VERSION 5.8 ;
BUSBITCHARS "[]" ;
DIVIDERCHAR "/" ;
UNITS
    DATABASE MICRONS 1000 ;
END UNITS

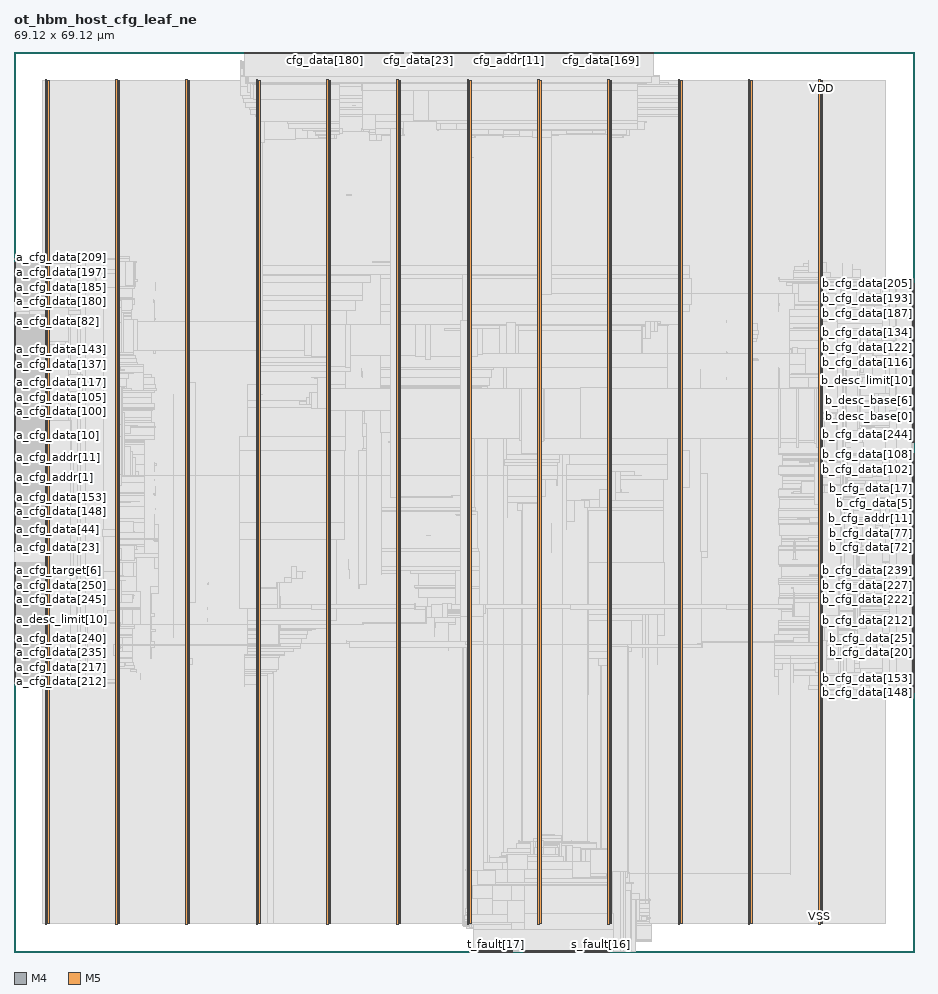
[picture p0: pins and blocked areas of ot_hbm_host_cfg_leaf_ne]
MACRO ot_hbm_host_cfg_leaf_ne
  FOREIGN ot_hbm_host_cfg_leaf_ne 0 0 ;
  CLASS BLOCK ;
  SIZE 69.12 BY 69.12 ;
  PIN a_cfg_addr[0]
    DIRECTION OUTPUT ;
    USE SIGNAL ;
    PORT
      LAYER M4 ;
        RECT  0 36.912 0.084 36.936 ;
    END
  END a_cfg_addr[0]
  PIN a_cfg_addr[10]
    DIRECTION OUTPUT ;
    USE SIGNAL ;
    PORT
      LAYER M4 ;
        RECT  0 37.872 0.084 37.896 ;
    END
  END a_cfg_addr[10]
  PIN a_cfg_addr[11]
    DIRECTION OUTPUT ;
    USE SIGNAL ;
    PORT
      LAYER M4 ;
        RECT  0 37.968 0.084 37.992 ;
    END
  END a_cfg_addr[11]
  PIN a_cfg_addr[1]
    DIRECTION OUTPUT ;
    USE SIGNAL ;
    PORT
      LAYER M4 ;
        RECT  0 37.008 0.084 37.032 ;
    END
  END a_cfg_addr[1]
  PIN a_cfg_addr[2]
    DIRECTION OUTPUT ;
    USE SIGNAL ;
    PORT
      LAYER M4 ;
        RECT  0 37.104 0.084 37.128 ;
    END
  END a_cfg_addr[2]
  PIN a_cfg_addr[3]
    DIRECTION OUTPUT ;
    USE SIGNAL ;
    PORT
      LAYER M4 ;
        RECT  0 37.2 0.084 37.224 ;
    END
  END a_cfg_addr[3]
  PIN a_cfg_addr[4]
    DIRECTION OUTPUT ;
    USE SIGNAL ;
    PORT
      LAYER M4 ;
        RECT  0 37.296 0.084 37.32 ;
    END
  END a_cfg_addr[4]
  PIN a_cfg_addr[5]
    DIRECTION OUTPUT ;
    USE SIGNAL ;
    PORT
      LAYER M4 ;
        RECT  0 37.392 0.084 37.416 ;
    END
  END a_cfg_addr[5]
  PIN a_cfg_addr[6]
    DIRECTION OUTPUT ;
    USE SIGNAL ;
    PORT
      LAYER M4 ;
        RECT  0 37.488 0.084 37.512 ;
    END
  END a_cfg_addr[6]
  PIN a_cfg_addr[7]
    DIRECTION OUTPUT ;
    USE SIGNAL ;
    PORT
      LAYER M4 ;
        RECT  0 37.584 0.084 37.608 ;
    END
  END a_cfg_addr[7]
  PIN a_cfg_addr[8]
    DIRECTION OUTPUT ;
    USE SIGNAL ;
    PORT
      LAYER M4 ;
        RECT  0 37.68 0.084 37.704 ;
    END
  END a_cfg_addr[8]
  PIN a_cfg_addr[9]
    DIRECTION OUTPUT ;
    USE SIGNAL ;
    PORT
      LAYER M4 ;
        RECT  0 37.776 0.084 37.8 ;
    END
  END a_cfg_addr[9]
  PIN a_cfg_data[0]
    DIRECTION OUTPUT ;
    USE SIGNAL ;
    PORT
      LAYER M4 ;
        RECT  0 38.064 0.084 38.088 ;
    END
  END a_cfg_data[0]
  PIN a_cfg_data[100]
    DIRECTION OUTPUT ;
    USE SIGNAL ;
    PORT
      LAYER M4 ;
        RECT  0 41.52 0.084 41.544 ;
    END
  END a_cfg_data[100]
  PIN a_cfg_data[101]
    DIRECTION OUTPUT ;
    USE SIGNAL ;
    PORT
      LAYER M4 ;
        RECT  0 41.616 0.084 41.64 ;
    END
  END a_cfg_data[101]
  PIN a_cfg_data[102]
    DIRECTION OUTPUT ;
    USE SIGNAL ;
    PORT
      LAYER M4 ;
        RECT  0 41.712 0.084 41.736 ;
    END
  END a_cfg_data[102]
  PIN a_cfg_data[103]
    DIRECTION OUTPUT ;
    USE SIGNAL ;
    PORT
      LAYER M4 ;
        RECT  0 41.808 0.084 41.832 ;
    END
  END a_cfg_data[103]
  PIN a_cfg_data[104]
    DIRECTION OUTPUT ;
    USE SIGNAL ;
    PORT
      LAYER M4 ;
        RECT  0 41.904 0.084 41.928 ;
    END
  END a_cfg_data[104]
  PIN a_cfg_data[105]
    DIRECTION OUTPUT ;
    USE SIGNAL ;
    PORT
      LAYER M4 ;
        RECT  0 42 0.084 42.024 ;
    END
  END a_cfg_data[105]
  PIN a_cfg_data[106]
    DIRECTION OUTPUT ;
    USE SIGNAL ;
    PORT
      LAYER M4 ;
        RECT  0 42.096 0.084 42.12 ;
    END
  END a_cfg_data[106]
  PIN a_cfg_data[107]
    DIRECTION OUTPUT ;
    USE SIGNAL ;
    PORT
      LAYER M4 ;
        RECT  0 42.192 0.084 42.216 ;
    END
  END a_cfg_data[107]
  PIN a_cfg_data[108]
    DIRECTION OUTPUT ;
    USE SIGNAL ;
    PORT
      LAYER M4 ;
        RECT  0 42.288 0.084 42.312 ;
    END
  END a_cfg_data[108]
  PIN a_cfg_data[109]
    DIRECTION OUTPUT ;
    USE SIGNAL ;
    PORT
      LAYER M4 ;
        RECT  0 42.384 0.084 42.408 ;
    END
  END a_cfg_data[109]
  PIN a_cfg_data[10]
    DIRECTION OUTPUT ;
    USE SIGNAL ;
    PORT
      LAYER M4 ;
        RECT  0 39.024 0.084 39.048 ;
    END
  END a_cfg_data[10]
  PIN a_cfg_data[110]
    DIRECTION OUTPUT ;
    USE SIGNAL ;
    PORT
      LAYER M4 ;
        RECT  0 42.48 0.084 42.504 ;
    END
  END a_cfg_data[110]
  PIN a_cfg_data[111]
    DIRECTION OUTPUT ;
    USE SIGNAL ;
    PORT
      LAYER M4 ;
        RECT  0 42.576 0.084 42.6 ;
    END
  END a_cfg_data[111]
  PIN a_cfg_data[112]
    DIRECTION OUTPUT ;
    USE SIGNAL ;
    PORT
      LAYER M4 ;
        RECT  0 42.672 0.084 42.696 ;
    END
  END a_cfg_data[112]
  PIN a_cfg_data[113]
    DIRECTION OUTPUT ;
    USE SIGNAL ;
    PORT
      LAYER M4 ;
        RECT  0 42.768 0.084 42.792 ;
    END
  END a_cfg_data[113]
  PIN a_cfg_data[114]
    DIRECTION OUTPUT ;
    USE SIGNAL ;
    PORT
      LAYER M4 ;
        RECT  0 42.864 0.084 42.888 ;
    END
  END a_cfg_data[114]
  PIN a_cfg_data[115]
    DIRECTION OUTPUT ;
    USE SIGNAL ;
    PORT
      LAYER M4 ;
        RECT  0 42.96 0.084 42.984 ;
    END
  END a_cfg_data[115]
  PIN a_cfg_data[116]
    DIRECTION OUTPUT ;
    USE SIGNAL ;
    PORT
      LAYER M4 ;
        RECT  0 43.056 0.084 43.08 ;
    END
  END a_cfg_data[116]
  PIN a_cfg_data[117]
    DIRECTION OUTPUT ;
    USE SIGNAL ;
    PORT
      LAYER M4 ;
        RECT  0 43.152 0.084 43.176 ;
    END
  END a_cfg_data[117]
  PIN a_cfg_data[118]
    DIRECTION OUTPUT ;
    USE SIGNAL ;
    PORT
      LAYER M4 ;
        RECT  0 43.248 0.084 43.272 ;
    END
  END a_cfg_data[118]
  PIN a_cfg_data[119]
    DIRECTION OUTPUT ;
    USE SIGNAL ;
    PORT
      LAYER M4 ;
        RECT  0 43.344 0.084 43.368 ;
    END
  END a_cfg_data[119]
  PIN a_cfg_data[11]
    DIRECTION OUTPUT ;
    USE SIGNAL ;
    PORT
      LAYER M4 ;
        RECT  0 39.12 0.084 39.144 ;
    END
  END a_cfg_data[11]
  PIN a_cfg_data[120]
    DIRECTION OUTPUT ;
    USE SIGNAL ;
    PORT
      LAYER M4 ;
        RECT  0 43.44 0.084 43.464 ;
    END
  END a_cfg_data[120]
  PIN a_cfg_data[121]
    DIRECTION OUTPUT ;
    USE SIGNAL ;
    PORT
      LAYER M4 ;
        RECT  0 43.536 0.084 43.56 ;
    END
  END a_cfg_data[121]
  PIN a_cfg_data[122]
    DIRECTION OUTPUT ;
    USE SIGNAL ;
    PORT
      LAYER M4 ;
        RECT  0 43.632 0.084 43.656 ;
    END
  END a_cfg_data[122]
  PIN a_cfg_data[123]
    DIRECTION OUTPUT ;
    USE SIGNAL ;
    PORT
      LAYER M4 ;
        RECT  0 43.728 0.084 43.752 ;
    END
  END a_cfg_data[123]
  PIN a_cfg_data[124]
    DIRECTION OUTPUT ;
    USE SIGNAL ;
    PORT
      LAYER M4 ;
        RECT  0 43.824 0.084 43.848 ;
    END
  END a_cfg_data[124]
  PIN a_cfg_data[125]
    DIRECTION OUTPUT ;
    USE SIGNAL ;
    PORT
      LAYER M4 ;
        RECT  0 43.92 0.084 43.944 ;
    END
  END a_cfg_data[125]
  PIN a_cfg_data[126]
    DIRECTION OUTPUT ;
    USE SIGNAL ;
    PORT
      LAYER M4 ;
        RECT  0 44.016 0.084 44.04 ;
    END
  END a_cfg_data[126]
  PIN a_cfg_data[127]
    DIRECTION OUTPUT ;
    USE SIGNAL ;
    PORT
      LAYER M4 ;
        RECT  0 44.112 0.084 44.136 ;
    END
  END a_cfg_data[127]
  PIN a_cfg_data[128]
    DIRECTION OUTPUT ;
    USE SIGNAL ;
    PORT
      LAYER M4 ;
        RECT  0 44.208 0.084 44.232 ;
    END
  END a_cfg_data[128]
  PIN a_cfg_data[129]
    DIRECTION OUTPUT ;
    USE SIGNAL ;
    PORT
      LAYER M4 ;
        RECT  0 44.304 0.084 44.328 ;
    END
  END a_cfg_data[129]
  PIN a_cfg_data[12]
    DIRECTION OUTPUT ;
    USE SIGNAL ;
    PORT
      LAYER M4 ;
        RECT  0 39.216 0.084 39.24 ;
    END
  END a_cfg_data[12]
  PIN a_cfg_data[130]
    DIRECTION OUTPUT ;
    USE SIGNAL ;
    PORT
      LAYER M4 ;
        RECT  0 44.4 0.084 44.424 ;
    END
  END a_cfg_data[130]
  PIN a_cfg_data[131]
    DIRECTION OUTPUT ;
    USE SIGNAL ;
    PORT
      LAYER M4 ;
        RECT  0 44.496 0.084 44.52 ;
    END
  END a_cfg_data[131]
  PIN a_cfg_data[132]
    DIRECTION OUTPUT ;
    USE SIGNAL ;
    PORT
      LAYER M4 ;
        RECT  0 44.592 0.084 44.616 ;
    END
  END a_cfg_data[132]
  PIN a_cfg_data[133]
    DIRECTION OUTPUT ;
    USE SIGNAL ;
    PORT
      LAYER M4 ;
        RECT  0 44.688 0.084 44.712 ;
    END
  END a_cfg_data[133]
  PIN a_cfg_data[134]
    DIRECTION OUTPUT ;
    USE SIGNAL ;
    PORT
      LAYER M4 ;
        RECT  0 44.784 0.084 44.808 ;
    END
  END a_cfg_data[134]
  PIN a_cfg_data[135]
    DIRECTION OUTPUT ;
    USE SIGNAL ;
    PORT
      LAYER M4 ;
        RECT  0 44.88 0.084 44.904 ;
    END
  END a_cfg_data[135]
  PIN a_cfg_data[136]
    DIRECTION OUTPUT ;
    USE SIGNAL ;
    PORT
      LAYER M4 ;
        RECT  0 44.976 0.084 45 ;
    END
  END a_cfg_data[136]
  PIN a_cfg_data[137]
    DIRECTION OUTPUT ;
    USE SIGNAL ;
    PORT
      LAYER M4 ;
        RECT  0 45.072 0.084 45.096 ;
    END
  END a_cfg_data[137]
  PIN a_cfg_data[138]
    DIRECTION OUTPUT ;
    USE SIGNAL ;
    PORT
      LAYER M4 ;
        RECT  0 45.168 0.084 45.192 ;
    END
  END a_cfg_data[138]
  PIN a_cfg_data[139]
    DIRECTION OUTPUT ;
    USE SIGNAL ;
    PORT
      LAYER M4 ;
        RECT  0 45.264 0.084 45.288 ;
    END
  END a_cfg_data[139]
  PIN a_cfg_data[13]
    DIRECTION OUTPUT ;
    USE SIGNAL ;
    PORT
      LAYER M4 ;
        RECT  0 39.312 0.084 39.336 ;
    END
  END a_cfg_data[13]
  PIN a_cfg_data[140]
    DIRECTION OUTPUT ;
    USE SIGNAL ;
    PORT
      LAYER M4 ;
        RECT  0 45.36 0.084 45.384 ;
    END
  END a_cfg_data[140]
  PIN a_cfg_data[141]
    DIRECTION OUTPUT ;
    USE SIGNAL ;
    PORT
      LAYER M4 ;
        RECT  0 45.456 0.084 45.48 ;
    END
  END a_cfg_data[141]
  PIN a_cfg_data[142]
    DIRECTION OUTPUT ;
    USE SIGNAL ;
    PORT
      LAYER M4 ;
        RECT  0 45.552 0.084 45.576 ;
    END
  END a_cfg_data[142]
  PIN a_cfg_data[143]
    DIRECTION OUTPUT ;
    USE SIGNAL ;
    PORT
      LAYER M4 ;
        RECT  0 45.648 0.084 45.672 ;
    END
  END a_cfg_data[143]
  PIN a_cfg_data[144]
    DIRECTION OUTPUT ;
    USE SIGNAL ;
    PORT
      LAYER M4 ;
        RECT  0 45.744 0.084 45.768 ;
    END
  END a_cfg_data[144]
  PIN a_cfg_data[145]
    DIRECTION OUTPUT ;
    USE SIGNAL ;
    PORT
      LAYER M4 ;
        RECT  0 45.84 0.084 45.864 ;
    END
  END a_cfg_data[145]
  PIN a_cfg_data[146]
    DIRECTION OUTPUT ;
    USE SIGNAL ;
    PORT
      LAYER M4 ;
        RECT  0 45.936 0.084 45.96 ;
    END
  END a_cfg_data[146]
  PIN a_cfg_data[147]
    DIRECTION OUTPUT ;
    USE SIGNAL ;
    PORT
      LAYER M4 ;
        RECT  0 46.032 0.084 46.056 ;
    END
  END a_cfg_data[147]
  PIN a_cfg_data[148]
    DIRECTION OUTPUT ;
    USE SIGNAL ;
    PORT
      LAYER M4 ;
        RECT  0 33.84 0.084 33.864 ;
    END
  END a_cfg_data[148]
  PIN a_cfg_data[149]
    DIRECTION OUTPUT ;
    USE SIGNAL ;
    PORT
      LAYER M4 ;
        RECT  0 33.936 0.084 33.96 ;
    END
  END a_cfg_data[149]
  PIN a_cfg_data[14]
    DIRECTION OUTPUT ;
    USE SIGNAL ;
    PORT
      LAYER M4 ;
        RECT  0 39.408 0.084 39.432 ;
    END
  END a_cfg_data[14]
  PIN a_cfg_data[150]
    DIRECTION OUTPUT ;
    USE SIGNAL ;
    PORT
      LAYER M4 ;
        RECT  0 34.032 0.084 34.056 ;
    END
  END a_cfg_data[150]
  PIN a_cfg_data[151]
    DIRECTION OUTPUT ;
    USE SIGNAL ;
    PORT
      LAYER M4 ;
        RECT  0 34.128 0.084 34.152 ;
    END
  END a_cfg_data[151]
  PIN a_cfg_data[152]
    DIRECTION OUTPUT ;
    USE SIGNAL ;
    PORT
      LAYER M4 ;
        RECT  0 34.224 0.084 34.248 ;
    END
  END a_cfg_data[152]
  PIN a_cfg_data[153]
    DIRECTION OUTPUT ;
    USE SIGNAL ;
    PORT
      LAYER M4 ;
        RECT  0 34.32 0.084 34.344 ;
    END
  END a_cfg_data[153]
  PIN a_cfg_data[154]
    DIRECTION OUTPUT ;
    USE SIGNAL ;
    PORT
      LAYER M4 ;
        RECT  0 34.416 0.084 34.44 ;
    END
  END a_cfg_data[154]
  PIN a_cfg_data[155]
    DIRECTION OUTPUT ;
    USE SIGNAL ;
    PORT
      LAYER M4 ;
        RECT  0 34.512 0.084 34.536 ;
    END
  END a_cfg_data[155]
  PIN a_cfg_data[156]
    DIRECTION OUTPUT ;
    USE SIGNAL ;
    PORT
      LAYER M4 ;
        RECT  0 34.608 0.084 34.632 ;
    END
  END a_cfg_data[156]
  PIN a_cfg_data[157]
    DIRECTION OUTPUT ;
    USE SIGNAL ;
    PORT
      LAYER M4 ;
        RECT  0 34.704 0.084 34.728 ;
    END
  END a_cfg_data[157]
  PIN a_cfg_data[158]
    DIRECTION OUTPUT ;
    USE SIGNAL ;
    PORT
      LAYER M4 ;
        RECT  0 34.8 0.084 34.824 ;
    END
  END a_cfg_data[158]
  PIN a_cfg_data[159]
    DIRECTION OUTPUT ;
    USE SIGNAL ;
    PORT
      LAYER M4 ;
        RECT  0 34.896 0.084 34.92 ;
    END
  END a_cfg_data[159]
  PIN a_cfg_data[15]
    DIRECTION OUTPUT ;
    USE SIGNAL ;
    PORT
      LAYER M4 ;
        RECT  0 39.504 0.084 39.528 ;
    END
  END a_cfg_data[15]
  PIN a_cfg_data[160]
    DIRECTION OUTPUT ;
    USE SIGNAL ;
    PORT
      LAYER M4 ;
        RECT  0 34.992 0.084 35.016 ;
    END
  END a_cfg_data[160]
  PIN a_cfg_data[161]
    DIRECTION OUTPUT ;
    USE SIGNAL ;
    PORT
      LAYER M4 ;
        RECT  0 35.088 0.084 35.112 ;
    END
  END a_cfg_data[161]
  PIN a_cfg_data[162]
    DIRECTION OUTPUT ;
    USE SIGNAL ;
    PORT
      LAYER M4 ;
        RECT  0 35.184 0.084 35.208 ;
    END
  END a_cfg_data[162]
  PIN a_cfg_data[163]
    DIRECTION OUTPUT ;
    USE SIGNAL ;
    PORT
      LAYER M4 ;
        RECT  0 35.28 0.084 35.304 ;
    END
  END a_cfg_data[163]
  PIN a_cfg_data[164]
    DIRECTION OUTPUT ;
    USE SIGNAL ;
    PORT
      LAYER M4 ;
        RECT  0 35.376 0.084 35.4 ;
    END
  END a_cfg_data[164]
  PIN a_cfg_data[165]
    DIRECTION OUTPUT ;
    USE SIGNAL ;
    PORT
      LAYER M4 ;
        RECT  0 35.472 0.084 35.496 ;
    END
  END a_cfg_data[165]
  PIN a_cfg_data[166]
    DIRECTION OUTPUT ;
    USE SIGNAL ;
    PORT
      LAYER M4 ;
        RECT  0 35.568 0.084 35.592 ;
    END
  END a_cfg_data[166]
  PIN a_cfg_data[167]
    DIRECTION OUTPUT ;
    USE SIGNAL ;
    PORT
      LAYER M4 ;
        RECT  0 35.664 0.084 35.688 ;
    END
  END a_cfg_data[167]
  PIN a_cfg_data[168]
    DIRECTION OUTPUT ;
    USE SIGNAL ;
    PORT
      LAYER M4 ;
        RECT  0 35.76 0.084 35.784 ;
    END
  END a_cfg_data[168]
  PIN a_cfg_data[169]
    DIRECTION OUTPUT ;
    USE SIGNAL ;
    PORT
      LAYER M4 ;
        RECT  0 35.856 0.084 35.88 ;
    END
  END a_cfg_data[169]
  PIN a_cfg_data[16]
    DIRECTION OUTPUT ;
    USE SIGNAL ;
    PORT
      LAYER M4 ;
        RECT  0 39.6 0.084 39.624 ;
    END
  END a_cfg_data[16]
  PIN a_cfg_data[170]
    DIRECTION OUTPUT ;
    USE SIGNAL ;
    PORT
      LAYER M4 ;
        RECT  0 35.952 0.084 35.976 ;
    END
  END a_cfg_data[170]
  PIN a_cfg_data[171]
    DIRECTION OUTPUT ;
    USE SIGNAL ;
    PORT
      LAYER M4 ;
        RECT  0 36.048 0.084 36.072 ;
    END
  END a_cfg_data[171]
  PIN a_cfg_data[172]
    DIRECTION OUTPUT ;
    USE SIGNAL ;
    PORT
      LAYER M4 ;
        RECT  0 36.144 0.084 36.168 ;
    END
  END a_cfg_data[172]
  PIN a_cfg_data[173]
    DIRECTION OUTPUT ;
    USE SIGNAL ;
    PORT
      LAYER M4 ;
        RECT  0 36.24 0.084 36.264 ;
    END
  END a_cfg_data[173]
  PIN a_cfg_data[174]
    DIRECTION OUTPUT ;
    USE SIGNAL ;
    PORT
      LAYER M4 ;
        RECT  0 36.336 0.084 36.36 ;
    END
  END a_cfg_data[174]
  PIN a_cfg_data[175]
    DIRECTION OUTPUT ;
    USE SIGNAL ;
    PORT
      LAYER M4 ;
        RECT  0 36.432 0.084 36.456 ;
    END
  END a_cfg_data[175]
  PIN a_cfg_data[176]
    DIRECTION OUTPUT ;
    USE SIGNAL ;
    PORT
      LAYER M4 ;
        RECT  0 36.528 0.084 36.552 ;
    END
  END a_cfg_data[176]
  PIN a_cfg_data[177]
    DIRECTION OUTPUT ;
    USE SIGNAL ;
    PORT
      LAYER M4 ;
        RECT  0 36.624 0.084 36.648 ;
    END
  END a_cfg_data[177]
  PIN a_cfg_data[178]
    DIRECTION OUTPUT ;
    USE SIGNAL ;
    PORT
      LAYER M4 ;
        RECT  0 36.72 0.084 36.744 ;
    END
  END a_cfg_data[178]
  PIN a_cfg_data[179]
    DIRECTION OUTPUT ;
    USE SIGNAL ;
    PORT
      LAYER M4 ;
        RECT  0 36.816 0.084 36.84 ;
    END
  END a_cfg_data[179]
  PIN a_cfg_data[17]
    DIRECTION OUTPUT ;
    USE SIGNAL ;
    PORT
      LAYER M4 ;
        RECT  0 39.696 0.084 39.72 ;
    END
  END a_cfg_data[17]
  PIN a_cfg_data[180]
    DIRECTION OUTPUT ;
    USE SIGNAL ;
    PORT
      LAYER M4 ;
        RECT  0 49.968 0.084 49.992 ;
    END
  END a_cfg_data[180]
  PIN a_cfg_data[181]
    DIRECTION OUTPUT ;
    USE SIGNAL ;
    PORT
      LAYER M4 ;
        RECT  0 50.064 0.084 50.088 ;
    END
  END a_cfg_data[181]
  PIN a_cfg_data[182]
    DIRECTION OUTPUT ;
    USE SIGNAL ;
    PORT
      LAYER M4 ;
        RECT  0 50.16 0.084 50.184 ;
    END
  END a_cfg_data[182]
  PIN a_cfg_data[183]
    DIRECTION OUTPUT ;
    USE SIGNAL ;
    PORT
      LAYER M4 ;
        RECT  0 50.256 0.084 50.28 ;
    END
  END a_cfg_data[183]
  PIN a_cfg_data[184]
    DIRECTION OUTPUT ;
    USE SIGNAL ;
    PORT
      LAYER M4 ;
        RECT  0 50.352 0.084 50.376 ;
    END
  END a_cfg_data[184]
  PIN a_cfg_data[185]
    DIRECTION OUTPUT ;
    USE SIGNAL ;
    PORT
      LAYER M4 ;
        RECT  0 50.448 0.084 50.472 ;
    END
  END a_cfg_data[185]
  PIN a_cfg_data[186]
    DIRECTION OUTPUT ;
    USE SIGNAL ;
    PORT
      LAYER M4 ;
        RECT  0 50.544 0.084 50.568 ;
    END
  END a_cfg_data[186]
  PIN a_cfg_data[187]
    DIRECTION OUTPUT ;
    USE SIGNAL ;
    PORT
      LAYER M4 ;
        RECT  0 50.64 0.084 50.664 ;
    END
  END a_cfg_data[187]
  PIN a_cfg_data[188]
    DIRECTION OUTPUT ;
    USE SIGNAL ;
    PORT
      LAYER M4 ;
        RECT  0 50.736 0.084 50.76 ;
    END
  END a_cfg_data[188]
  PIN a_cfg_data[189]
    DIRECTION OUTPUT ;
    USE SIGNAL ;
    PORT
      LAYER M4 ;
        RECT  0 50.832 0.084 50.856 ;
    END
  END a_cfg_data[189]
  PIN a_cfg_data[18]
    DIRECTION OUTPUT ;
    USE SIGNAL ;
    PORT
      LAYER M4 ;
        RECT  0 39.792 0.084 39.816 ;
    END
  END a_cfg_data[18]
  PIN a_cfg_data[190]
    DIRECTION OUTPUT ;
    USE SIGNAL ;
    PORT
      LAYER M4 ;
        RECT  0 50.928 0.084 50.952 ;
    END
  END a_cfg_data[190]
  PIN a_cfg_data[191]
    DIRECTION OUTPUT ;
    USE SIGNAL ;
    PORT
      LAYER M4 ;
        RECT  0 51.024 0.084 51.048 ;
    END
  END a_cfg_data[191]
  PIN a_cfg_data[192]
    DIRECTION OUTPUT ;
    USE SIGNAL ;
    PORT
      LAYER M4 ;
        RECT  0 51.12 0.084 51.144 ;
    END
  END a_cfg_data[192]
  PIN a_cfg_data[193]
    DIRECTION OUTPUT ;
    USE SIGNAL ;
    PORT
      LAYER M4 ;
        RECT  0 51.216 0.084 51.24 ;
    END
  END a_cfg_data[193]
  PIN a_cfg_data[194]
    DIRECTION OUTPUT ;
    USE SIGNAL ;
    PORT
      LAYER M4 ;
        RECT  0 51.312 0.084 51.336 ;
    END
  END a_cfg_data[194]
  PIN a_cfg_data[195]
    DIRECTION OUTPUT ;
    USE SIGNAL ;
    PORT
      LAYER M4 ;
        RECT  0 51.408 0.084 51.432 ;
    END
  END a_cfg_data[195]
  PIN a_cfg_data[196]
    DIRECTION OUTPUT ;
    USE SIGNAL ;
    PORT
      LAYER M4 ;
        RECT  0 51.504 0.084 51.528 ;
    END
  END a_cfg_data[196]
  PIN a_cfg_data[197]
    DIRECTION OUTPUT ;
    USE SIGNAL ;
    PORT
      LAYER M4 ;
        RECT  0 51.6 0.084 51.624 ;
    END
  END a_cfg_data[197]
  PIN a_cfg_data[198]
    DIRECTION OUTPUT ;
    USE SIGNAL ;
    PORT
      LAYER M4 ;
        RECT  0 51.696 0.084 51.72 ;
    END
  END a_cfg_data[198]
  PIN a_cfg_data[199]
    DIRECTION OUTPUT ;
    USE SIGNAL ;
    PORT
      LAYER M4 ;
        RECT  0 51.792 0.084 51.816 ;
    END
  END a_cfg_data[199]
  PIN a_cfg_data[19]
    DIRECTION OUTPUT ;
    USE SIGNAL ;
    PORT
      LAYER M4 ;
        RECT  0 39.888 0.084 39.912 ;
    END
  END a_cfg_data[19]
  PIN a_cfg_data[1]
    DIRECTION OUTPUT ;
    USE SIGNAL ;
    PORT
      LAYER M4 ;
        RECT  0 38.16 0.084 38.184 ;
    END
  END a_cfg_data[1]
  PIN a_cfg_data[200]
    DIRECTION OUTPUT ;
    USE SIGNAL ;
    PORT
      LAYER M4 ;
        RECT  0 51.888 0.084 51.912 ;
    END
  END a_cfg_data[200]
  PIN a_cfg_data[201]
    DIRECTION OUTPUT ;
    USE SIGNAL ;
    PORT
      LAYER M4 ;
        RECT  0 51.984 0.084 52.008 ;
    END
  END a_cfg_data[201]
  PIN a_cfg_data[202]
    DIRECTION OUTPUT ;
    USE SIGNAL ;
    PORT
      LAYER M4 ;
        RECT  0 52.08 0.084 52.104 ;
    END
  END a_cfg_data[202]
  PIN a_cfg_data[203]
    DIRECTION OUTPUT ;
    USE SIGNAL ;
    PORT
      LAYER M4 ;
        RECT  0 52.176 0.084 52.2 ;
    END
  END a_cfg_data[203]
  PIN a_cfg_data[204]
    DIRECTION OUTPUT ;
    USE SIGNAL ;
    PORT
      LAYER M4 ;
        RECT  0 52.272 0.084 52.296 ;
    END
  END a_cfg_data[204]
  PIN a_cfg_data[205]
    DIRECTION OUTPUT ;
    USE SIGNAL ;
    PORT
      LAYER M4 ;
        RECT  0 52.368 0.084 52.392 ;
    END
  END a_cfg_data[205]
  PIN a_cfg_data[206]
    DIRECTION OUTPUT ;
    USE SIGNAL ;
    PORT
      LAYER M4 ;
        RECT  0 52.464 0.084 52.488 ;
    END
  END a_cfg_data[206]
  PIN a_cfg_data[207]
    DIRECTION OUTPUT ;
    USE SIGNAL ;
    PORT
      LAYER M4 ;
        RECT  0 52.56 0.084 52.584 ;
    END
  END a_cfg_data[207]
  PIN a_cfg_data[208]
    DIRECTION OUTPUT ;
    USE SIGNAL ;
    PORT
      LAYER M4 ;
        RECT  0 52.656 0.084 52.68 ;
    END
  END a_cfg_data[208]
  PIN a_cfg_data[209]
    DIRECTION OUTPUT ;
    USE SIGNAL ;
    PORT
      LAYER M4 ;
        RECT  0 52.752 0.084 52.776 ;
    END
  END a_cfg_data[209]
  PIN a_cfg_data[20]
    DIRECTION OUTPUT ;
    USE SIGNAL ;
    PORT
      LAYER M4 ;
        RECT  0 30.768 0.084 30.792 ;
    END
  END a_cfg_data[20]
  PIN a_cfg_data[210]
    DIRECTION OUTPUT ;
    USE SIGNAL ;
    PORT
      LAYER M4 ;
        RECT  0 52.848 0.084 52.872 ;
    END
  END a_cfg_data[210]
  PIN a_cfg_data[211]
    DIRECTION OUTPUT ;
    USE SIGNAL ;
    PORT
      LAYER M4 ;
        RECT  0 52.944 0.084 52.968 ;
    END
  END a_cfg_data[211]
  PIN a_cfg_data[212]
    DIRECTION OUTPUT ;
    USE SIGNAL ;
    PORT
      LAYER M4 ;
        RECT  0 20.784 0.084 20.808 ;
    END
  END a_cfg_data[212]
  PIN a_cfg_data[213]
    DIRECTION OUTPUT ;
    USE SIGNAL ;
    PORT
      LAYER M4 ;
        RECT  0 20.88 0.084 20.904 ;
    END
  END a_cfg_data[213]
  PIN a_cfg_data[214]
    DIRECTION OUTPUT ;
    USE SIGNAL ;
    PORT
      LAYER M4 ;
        RECT  0 20.976 0.084 21 ;
    END
  END a_cfg_data[214]
  PIN a_cfg_data[215]
    DIRECTION OUTPUT ;
    USE SIGNAL ;
    PORT
      LAYER M4 ;
        RECT  0 21.072 0.084 21.096 ;
    END
  END a_cfg_data[215]
  PIN a_cfg_data[216]
    DIRECTION OUTPUT ;
    USE SIGNAL ;
    PORT
      LAYER M4 ;
        RECT  0 21.168 0.084 21.192 ;
    END
  END a_cfg_data[216]
  PIN a_cfg_data[217]
    DIRECTION OUTPUT ;
    USE SIGNAL ;
    PORT
      LAYER M4 ;
        RECT  0 21.264 0.084 21.288 ;
    END
  END a_cfg_data[217]
  PIN a_cfg_data[218]
    DIRECTION OUTPUT ;
    USE SIGNAL ;
    PORT
      LAYER M4 ;
        RECT  0 21.36 0.084 21.384 ;
    END
  END a_cfg_data[218]
  PIN a_cfg_data[219]
    DIRECTION OUTPUT ;
    USE SIGNAL ;
    PORT
      LAYER M4 ;
        RECT  0 21.456 0.084 21.48 ;
    END
  END a_cfg_data[219]
  PIN a_cfg_data[21]
    DIRECTION OUTPUT ;
    USE SIGNAL ;
    PORT
      LAYER M4 ;
        RECT  0 30.864 0.084 30.888 ;
    END
  END a_cfg_data[21]
  PIN a_cfg_data[220]
    DIRECTION OUTPUT ;
    USE SIGNAL ;
    PORT
      LAYER M4 ;
        RECT  0 21.552 0.084 21.576 ;
    END
  END a_cfg_data[220]
  PIN a_cfg_data[221]
    DIRECTION OUTPUT ;
    USE SIGNAL ;
    PORT
      LAYER M4 ;
        RECT  0 21.648 0.084 21.672 ;
    END
  END a_cfg_data[221]
  PIN a_cfg_data[222]
    DIRECTION OUTPUT ;
    USE SIGNAL ;
    PORT
      LAYER M4 ;
        RECT  0 21.744 0.084 21.768 ;
    END
  END a_cfg_data[222]
  PIN a_cfg_data[223]
    DIRECTION OUTPUT ;
    USE SIGNAL ;
    PORT
      LAYER M4 ;
        RECT  0 21.84 0.084 21.864 ;
    END
  END a_cfg_data[223]
  PIN a_cfg_data[224]
    DIRECTION OUTPUT ;
    USE SIGNAL ;
    PORT
      LAYER M4 ;
        RECT  0 21.936 0.084 21.96 ;
    END
  END a_cfg_data[224]
  PIN a_cfg_data[225]
    DIRECTION OUTPUT ;
    USE SIGNAL ;
    PORT
      LAYER M4 ;
        RECT  0 22.032 0.084 22.056 ;
    END
  END a_cfg_data[225]
  PIN a_cfg_data[226]
    DIRECTION OUTPUT ;
    USE SIGNAL ;
    PORT
      LAYER M4 ;
        RECT  0 22.128 0.084 22.152 ;
    END
  END a_cfg_data[226]
  PIN a_cfg_data[227]
    DIRECTION OUTPUT ;
    USE SIGNAL ;
    PORT
      LAYER M4 ;
        RECT  0 22.224 0.084 22.248 ;
    END
  END a_cfg_data[227]
  PIN a_cfg_data[228]
    DIRECTION OUTPUT ;
    USE SIGNAL ;
    PORT
      LAYER M4 ;
        RECT  0 22.32 0.084 22.344 ;
    END
  END a_cfg_data[228]
  PIN a_cfg_data[229]
    DIRECTION OUTPUT ;
    USE SIGNAL ;
    PORT
      LAYER M4 ;
        RECT  0 22.416 0.084 22.44 ;
    END
  END a_cfg_data[229]
  PIN a_cfg_data[22]
    DIRECTION OUTPUT ;
    USE SIGNAL ;
    PORT
      LAYER M4 ;
        RECT  0 30.96 0.084 30.984 ;
    END
  END a_cfg_data[22]
  PIN a_cfg_data[230]
    DIRECTION OUTPUT ;
    USE SIGNAL ;
    PORT
      LAYER M4 ;
        RECT  0 22.512 0.084 22.536 ;
    END
  END a_cfg_data[230]
  PIN a_cfg_data[231]
    DIRECTION OUTPUT ;
    USE SIGNAL ;
    PORT
      LAYER M4 ;
        RECT  0 22.608 0.084 22.632 ;
    END
  END a_cfg_data[231]
  PIN a_cfg_data[232]
    DIRECTION OUTPUT ;
    USE SIGNAL ;
    PORT
      LAYER M4 ;
        RECT  0 22.704 0.084 22.728 ;
    END
  END a_cfg_data[232]
  PIN a_cfg_data[233]
    DIRECTION OUTPUT ;
    USE SIGNAL ;
    PORT
      LAYER M4 ;
        RECT  0 22.8 0.084 22.824 ;
    END
  END a_cfg_data[233]
  PIN a_cfg_data[234]
    DIRECTION OUTPUT ;
    USE SIGNAL ;
    PORT
      LAYER M4 ;
        RECT  0 22.896 0.084 22.92 ;
    END
  END a_cfg_data[234]
  PIN a_cfg_data[235]
    DIRECTION OUTPUT ;
    USE SIGNAL ;
    PORT
      LAYER M4 ;
        RECT  0 22.992 0.084 23.016 ;
    END
  END a_cfg_data[235]
  PIN a_cfg_data[236]
    DIRECTION OUTPUT ;
    USE SIGNAL ;
    PORT
      LAYER M4 ;
        RECT  0 23.088 0.084 23.112 ;
    END
  END a_cfg_data[236]
  PIN a_cfg_data[237]
    DIRECTION OUTPUT ;
    USE SIGNAL ;
    PORT
      LAYER M4 ;
        RECT  0 23.184 0.084 23.208 ;
    END
  END a_cfg_data[237]
  PIN a_cfg_data[238]
    DIRECTION OUTPUT ;
    USE SIGNAL ;
    PORT
      LAYER M4 ;
        RECT  0 23.28 0.084 23.304 ;
    END
  END a_cfg_data[238]
  PIN a_cfg_data[239]
    DIRECTION OUTPUT ;
    USE SIGNAL ;
    PORT
      LAYER M4 ;
        RECT  0 23.376 0.084 23.4 ;
    END
  END a_cfg_data[239]
  PIN a_cfg_data[23]
    DIRECTION OUTPUT ;
    USE SIGNAL ;
    PORT
      LAYER M4 ;
        RECT  0 31.056 0.084 31.08 ;
    END
  END a_cfg_data[23]
  PIN a_cfg_data[240]
    DIRECTION OUTPUT ;
    USE SIGNAL ;
    PORT
      LAYER M4 ;
        RECT  0 23.472 0.084 23.496 ;
    END
  END a_cfg_data[240]
  PIN a_cfg_data[241]
    DIRECTION OUTPUT ;
    USE SIGNAL ;
    PORT
      LAYER M4 ;
        RECT  0 23.568 0.084 23.592 ;
    END
  END a_cfg_data[241]
  PIN a_cfg_data[242]
    DIRECTION OUTPUT ;
    USE SIGNAL ;
    PORT
      LAYER M4 ;
        RECT  0 23.664 0.084 23.688 ;
    END
  END a_cfg_data[242]
  PIN a_cfg_data[243]
    DIRECTION OUTPUT ;
    USE SIGNAL ;
    PORT
      LAYER M4 ;
        RECT  0 23.76 0.084 23.784 ;
    END
  END a_cfg_data[243]
  PIN a_cfg_data[244]
    DIRECTION OUTPUT ;
    USE SIGNAL ;
    PORT
      LAYER M4 ;
        RECT  0 26.928 0.084 26.952 ;
    END
  END a_cfg_data[244]
  PIN a_cfg_data[245]
    DIRECTION OUTPUT ;
    USE SIGNAL ;
    PORT
      LAYER M4 ;
        RECT  0 27.024 0.084 27.048 ;
    END
  END a_cfg_data[245]
  PIN a_cfg_data[246]
    DIRECTION OUTPUT ;
    USE SIGNAL ;
    PORT
      LAYER M4 ;
        RECT  0 27.12 0.084 27.144 ;
    END
  END a_cfg_data[246]
  PIN a_cfg_data[247]
    DIRECTION OUTPUT ;
    USE SIGNAL ;
    PORT
      LAYER M4 ;
        RECT  0 27.216 0.084 27.24 ;
    END
  END a_cfg_data[247]
  PIN a_cfg_data[248]
    DIRECTION OUTPUT ;
    USE SIGNAL ;
    PORT
      LAYER M4 ;
        RECT  0 27.312 0.084 27.336 ;
    END
  END a_cfg_data[248]
  PIN a_cfg_data[249]
    DIRECTION OUTPUT ;
    USE SIGNAL ;
    PORT
      LAYER M4 ;
        RECT  0 27.408 0.084 27.432 ;
    END
  END a_cfg_data[249]
  PIN a_cfg_data[24]
    DIRECTION OUTPUT ;
    USE SIGNAL ;
    PORT
      LAYER M4 ;
        RECT  0 31.152 0.084 31.176 ;
    END
  END a_cfg_data[24]
  PIN a_cfg_data[250]
    DIRECTION OUTPUT ;
    USE SIGNAL ;
    PORT
      LAYER M4 ;
        RECT  0 27.504 0.084 27.528 ;
    END
  END a_cfg_data[250]
  PIN a_cfg_data[251]
    DIRECTION OUTPUT ;
    USE SIGNAL ;
    PORT
      LAYER M4 ;
        RECT  0 27.6 0.084 27.624 ;
    END
  END a_cfg_data[251]
  PIN a_cfg_data[252]
    DIRECTION OUTPUT ;
    USE SIGNAL ;
    PORT
      LAYER M4 ;
        RECT  0 27.696 0.084 27.72 ;
    END
  END a_cfg_data[252]
  PIN a_cfg_data[253]
    DIRECTION OUTPUT ;
    USE SIGNAL ;
    PORT
      LAYER M4 ;
        RECT  0 27.792 0.084 27.816 ;
    END
  END a_cfg_data[253]
  PIN a_cfg_data[254]
    DIRECTION OUTPUT ;
    USE SIGNAL ;
    PORT
      LAYER M4 ;
        RECT  0 27.888 0.084 27.912 ;
    END
  END a_cfg_data[254]
  PIN a_cfg_data[255]
    DIRECTION OUTPUT ;
    USE SIGNAL ;
    PORT
      LAYER M4 ;
        RECT  0 27.984 0.084 28.008 ;
    END
  END a_cfg_data[255]
  PIN a_cfg_data[25]
    DIRECTION OUTPUT ;
    USE SIGNAL ;
    PORT
      LAYER M4 ;
        RECT  0 31.248 0.084 31.272 ;
    END
  END a_cfg_data[25]
  PIN a_cfg_data[26]
    DIRECTION OUTPUT ;
    USE SIGNAL ;
    PORT
      LAYER M4 ;
        RECT  0 31.344 0.084 31.368 ;
    END
  END a_cfg_data[26]
  PIN a_cfg_data[27]
    DIRECTION OUTPUT ;
    USE SIGNAL ;
    PORT
      LAYER M4 ;
        RECT  0 31.44 0.084 31.464 ;
    END
  END a_cfg_data[27]
  PIN a_cfg_data[28]
    DIRECTION OUTPUT ;
    USE SIGNAL ;
    PORT
      LAYER M4 ;
        RECT  0 31.536 0.084 31.56 ;
    END
  END a_cfg_data[28]
  PIN a_cfg_data[29]
    DIRECTION OUTPUT ;
    USE SIGNAL ;
    PORT
      LAYER M4 ;
        RECT  0 31.632 0.084 31.656 ;
    END
  END a_cfg_data[29]
  PIN a_cfg_data[2]
    DIRECTION OUTPUT ;
    USE SIGNAL ;
    PORT
      LAYER M4 ;
        RECT  0 38.256 0.084 38.28 ;
    END
  END a_cfg_data[2]
  PIN a_cfg_data[30]
    DIRECTION OUTPUT ;
    USE SIGNAL ;
    PORT
      LAYER M4 ;
        RECT  0 31.728 0.084 31.752 ;
    END
  END a_cfg_data[30]
  PIN a_cfg_data[31]
    DIRECTION OUTPUT ;
    USE SIGNAL ;
    PORT
      LAYER M4 ;
        RECT  0 31.824 0.084 31.848 ;
    END
  END a_cfg_data[31]
  PIN a_cfg_data[32]
    DIRECTION OUTPUT ;
    USE SIGNAL ;
    PORT
      LAYER M4 ;
        RECT  0 31.92 0.084 31.944 ;
    END
  END a_cfg_data[32]
  PIN a_cfg_data[33]
    DIRECTION OUTPUT ;
    USE SIGNAL ;
    PORT
      LAYER M4 ;
        RECT  0 32.016 0.084 32.04 ;
    END
  END a_cfg_data[33]
  PIN a_cfg_data[34]
    DIRECTION OUTPUT ;
    USE SIGNAL ;
    PORT
      LAYER M4 ;
        RECT  0 32.112 0.084 32.136 ;
    END
  END a_cfg_data[34]
  PIN a_cfg_data[35]
    DIRECTION OUTPUT ;
    USE SIGNAL ;
    PORT
      LAYER M4 ;
        RECT  0 32.208 0.084 32.232 ;
    END
  END a_cfg_data[35]
  PIN a_cfg_data[36]
    DIRECTION OUTPUT ;
    USE SIGNAL ;
    PORT
      LAYER M4 ;
        RECT  0 32.304 0.084 32.328 ;
    END
  END a_cfg_data[36]
  PIN a_cfg_data[37]
    DIRECTION OUTPUT ;
    USE SIGNAL ;
    PORT
      LAYER M4 ;
        RECT  0 32.4 0.084 32.424 ;
    END
  END a_cfg_data[37]
  PIN a_cfg_data[38]
    DIRECTION OUTPUT ;
    USE SIGNAL ;
    PORT
      LAYER M4 ;
        RECT  0 32.496 0.084 32.52 ;
    END
  END a_cfg_data[38]
  PIN a_cfg_data[39]
    DIRECTION OUTPUT ;
    USE SIGNAL ;
    PORT
      LAYER M4 ;
        RECT  0 32.592 0.084 32.616 ;
    END
  END a_cfg_data[39]
  PIN a_cfg_data[3]
    DIRECTION OUTPUT ;
    USE SIGNAL ;
    PORT
      LAYER M4 ;
        RECT  0 38.352 0.084 38.376 ;
    END
  END a_cfg_data[3]
  PIN a_cfg_data[40]
    DIRECTION OUTPUT ;
    USE SIGNAL ;
    PORT
      LAYER M4 ;
        RECT  0 32.688 0.084 32.712 ;
    END
  END a_cfg_data[40]
  PIN a_cfg_data[41]
    DIRECTION OUTPUT ;
    USE SIGNAL ;
    PORT
      LAYER M4 ;
        RECT  0 32.784 0.084 32.808 ;
    END
  END a_cfg_data[41]
  PIN a_cfg_data[42]
    DIRECTION OUTPUT ;
    USE SIGNAL ;
    PORT
      LAYER M4 ;
        RECT  0 32.88 0.084 32.904 ;
    END
  END a_cfg_data[42]
  PIN a_cfg_data[43]
    DIRECTION OUTPUT ;
    USE SIGNAL ;
    PORT
      LAYER M4 ;
        RECT  0 32.976 0.084 33 ;
    END
  END a_cfg_data[43]
  PIN a_cfg_data[44]
    DIRECTION OUTPUT ;
    USE SIGNAL ;
    PORT
      LAYER M4 ;
        RECT  0 33.072 0.084 33.096 ;
    END
  END a_cfg_data[44]
  PIN a_cfg_data[45]
    DIRECTION OUTPUT ;
    USE SIGNAL ;
    PORT
      LAYER M4 ;
        RECT  0 33.168 0.084 33.192 ;
    END
  END a_cfg_data[45]
  PIN a_cfg_data[46]
    DIRECTION OUTPUT ;
    USE SIGNAL ;
    PORT
      LAYER M4 ;
        RECT  0 33.264 0.084 33.288 ;
    END
  END a_cfg_data[46]
  PIN a_cfg_data[47]
    DIRECTION OUTPUT ;
    USE SIGNAL ;
    PORT
      LAYER M4 ;
        RECT  0 33.36 0.084 33.384 ;
    END
  END a_cfg_data[47]
  PIN a_cfg_data[48]
    DIRECTION OUTPUT ;
    USE SIGNAL ;
    PORT
      LAYER M4 ;
        RECT  0 33.456 0.084 33.48 ;
    END
  END a_cfg_data[48]
  PIN a_cfg_data[49]
    DIRECTION OUTPUT ;
    USE SIGNAL ;
    PORT
      LAYER M4 ;
        RECT  0 33.552 0.084 33.576 ;
    END
  END a_cfg_data[49]
  PIN a_cfg_data[4]
    DIRECTION OUTPUT ;
    USE SIGNAL ;
    PORT
      LAYER M4 ;
        RECT  0 38.448 0.084 38.472 ;
    END
  END a_cfg_data[4]
  PIN a_cfg_data[50]
    DIRECTION OUTPUT ;
    USE SIGNAL ;
    PORT
      LAYER M4 ;
        RECT  0 33.648 0.084 33.672 ;
    END
  END a_cfg_data[50]
  PIN a_cfg_data[51]
    DIRECTION OUTPUT ;
    USE SIGNAL ;
    PORT
      LAYER M4 ;
        RECT  0 33.744 0.084 33.768 ;
    END
  END a_cfg_data[51]
  PIN a_cfg_data[52]
    DIRECTION OUTPUT ;
    USE SIGNAL ;
    PORT
      LAYER M4 ;
        RECT  0 46.128 0.084 46.152 ;
    END
  END a_cfg_data[52]
  PIN a_cfg_data[53]
    DIRECTION OUTPUT ;
    USE SIGNAL ;
    PORT
      LAYER M4 ;
        RECT  0 46.224 0.084 46.248 ;
    END
  END a_cfg_data[53]
  PIN a_cfg_data[54]
    DIRECTION OUTPUT ;
    USE SIGNAL ;
    PORT
      LAYER M4 ;
        RECT  0 46.32 0.084 46.344 ;
    END
  END a_cfg_data[54]
  PIN a_cfg_data[55]
    DIRECTION OUTPUT ;
    USE SIGNAL ;
    PORT
      LAYER M4 ;
        RECT  0 46.416 0.084 46.44 ;
    END
  END a_cfg_data[55]
  PIN a_cfg_data[56]
    DIRECTION OUTPUT ;
    USE SIGNAL ;
    PORT
      LAYER M4 ;
        RECT  0 46.512 0.084 46.536 ;
    END
  END a_cfg_data[56]
  PIN a_cfg_data[57]
    DIRECTION OUTPUT ;
    USE SIGNAL ;
    PORT
      LAYER M4 ;
        RECT  0 46.608 0.084 46.632 ;
    END
  END a_cfg_data[57]
  PIN a_cfg_data[58]
    DIRECTION OUTPUT ;
    USE SIGNAL ;
    PORT
      LAYER M4 ;
        RECT  0 46.704 0.084 46.728 ;
    END
  END a_cfg_data[58]
  PIN a_cfg_data[59]
    DIRECTION OUTPUT ;
    USE SIGNAL ;
    PORT
      LAYER M4 ;
        RECT  0 46.8 0.084 46.824 ;
    END
  END a_cfg_data[59]
  PIN a_cfg_data[5]
    DIRECTION OUTPUT ;
    USE SIGNAL ;
    PORT
      LAYER M4 ;
        RECT  0 38.544 0.084 38.568 ;
    END
  END a_cfg_data[5]
  PIN a_cfg_data[60]
    DIRECTION OUTPUT ;
    USE SIGNAL ;
    PORT
      LAYER M4 ;
        RECT  0 46.896 0.084 46.92 ;
    END
  END a_cfg_data[60]
  PIN a_cfg_data[61]
    DIRECTION OUTPUT ;
    USE SIGNAL ;
    PORT
      LAYER M4 ;
        RECT  0 46.992 0.084 47.016 ;
    END
  END a_cfg_data[61]
  PIN a_cfg_data[62]
    DIRECTION OUTPUT ;
    USE SIGNAL ;
    PORT
      LAYER M4 ;
        RECT  0 47.088 0.084 47.112 ;
    END
  END a_cfg_data[62]
  PIN a_cfg_data[63]
    DIRECTION OUTPUT ;
    USE SIGNAL ;
    PORT
      LAYER M4 ;
        RECT  0 47.184 0.084 47.208 ;
    END
  END a_cfg_data[63]
  PIN a_cfg_data[64]
    DIRECTION OUTPUT ;
    USE SIGNAL ;
    PORT
      LAYER M4 ;
        RECT  0 47.28 0.084 47.304 ;
    END
  END a_cfg_data[64]
  PIN a_cfg_data[65]
    DIRECTION OUTPUT ;
    USE SIGNAL ;
    PORT
      LAYER M4 ;
        RECT  0 47.376 0.084 47.4 ;
    END
  END a_cfg_data[65]
  PIN a_cfg_data[66]
    DIRECTION OUTPUT ;
    USE SIGNAL ;
    PORT
      LAYER M4 ;
        RECT  0 47.472 0.084 47.496 ;
    END
  END a_cfg_data[66]
  PIN a_cfg_data[67]
    DIRECTION OUTPUT ;
    USE SIGNAL ;
    PORT
      LAYER M4 ;
        RECT  0 47.568 0.084 47.592 ;
    END
  END a_cfg_data[67]
  PIN a_cfg_data[68]
    DIRECTION OUTPUT ;
    USE SIGNAL ;
    PORT
      LAYER M4 ;
        RECT  0 47.664 0.084 47.688 ;
    END
  END a_cfg_data[68]
  PIN a_cfg_data[69]
    DIRECTION OUTPUT ;
    USE SIGNAL ;
    PORT
      LAYER M4 ;
        RECT  0 47.76 0.084 47.784 ;
    END
  END a_cfg_data[69]
  PIN a_cfg_data[6]
    DIRECTION OUTPUT ;
    USE SIGNAL ;
    PORT
      LAYER M4 ;
        RECT  0 38.64 0.084 38.664 ;
    END
  END a_cfg_data[6]
  PIN a_cfg_data[70]
    DIRECTION OUTPUT ;
    USE SIGNAL ;
    PORT
      LAYER M4 ;
        RECT  0 47.856 0.084 47.88 ;
    END
  END a_cfg_data[70]
  PIN a_cfg_data[71]
    DIRECTION OUTPUT ;
    USE SIGNAL ;
    PORT
      LAYER M4 ;
        RECT  0 47.952 0.084 47.976 ;
    END
  END a_cfg_data[71]
  PIN a_cfg_data[72]
    DIRECTION OUTPUT ;
    USE SIGNAL ;
    PORT
      LAYER M4 ;
        RECT  0 48.048 0.084 48.072 ;
    END
  END a_cfg_data[72]
  PIN a_cfg_data[73]
    DIRECTION OUTPUT ;
    USE SIGNAL ;
    PORT
      LAYER M4 ;
        RECT  0 48.144 0.084 48.168 ;
    END
  END a_cfg_data[73]
  PIN a_cfg_data[74]
    DIRECTION OUTPUT ;
    USE SIGNAL ;
    PORT
      LAYER M4 ;
        RECT  0 48.24 0.084 48.264 ;
    END
  END a_cfg_data[74]
  PIN a_cfg_data[75]
    DIRECTION OUTPUT ;
    USE SIGNAL ;
    PORT
      LAYER M4 ;
        RECT  0 48.336 0.084 48.36 ;
    END
  END a_cfg_data[75]
  PIN a_cfg_data[76]
    DIRECTION OUTPUT ;
    USE SIGNAL ;
    PORT
      LAYER M4 ;
        RECT  0 48.432 0.084 48.456 ;
    END
  END a_cfg_data[76]
  PIN a_cfg_data[77]
    DIRECTION OUTPUT ;
    USE SIGNAL ;
    PORT
      LAYER M4 ;
        RECT  0 48.528 0.084 48.552 ;
    END
  END a_cfg_data[77]
  PIN a_cfg_data[78]
    DIRECTION OUTPUT ;
    USE SIGNAL ;
    PORT
      LAYER M4 ;
        RECT  0 48.624 0.084 48.648 ;
    END
  END a_cfg_data[78]
  PIN a_cfg_data[79]
    DIRECTION OUTPUT ;
    USE SIGNAL ;
    PORT
      LAYER M4 ;
        RECT  0 48.72 0.084 48.744 ;
    END
  END a_cfg_data[79]
  PIN a_cfg_data[7]
    DIRECTION OUTPUT ;
    USE SIGNAL ;
    PORT
      LAYER M4 ;
        RECT  0 38.736 0.084 38.76 ;
    END
  END a_cfg_data[7]
  PIN a_cfg_data[80]
    DIRECTION OUTPUT ;
    USE SIGNAL ;
    PORT
      LAYER M4 ;
        RECT  0 48.816 0.084 48.84 ;
    END
  END a_cfg_data[80]
  PIN a_cfg_data[81]
    DIRECTION OUTPUT ;
    USE SIGNAL ;
    PORT
      LAYER M4 ;
        RECT  0 48.912 0.084 48.936 ;
    END
  END a_cfg_data[81]
  PIN a_cfg_data[82]
    DIRECTION OUTPUT ;
    USE SIGNAL ;
    PORT
      LAYER M4 ;
        RECT  0 49.008 0.084 49.032 ;
    END
  END a_cfg_data[82]
  PIN a_cfg_data[83]
    DIRECTION OUTPUT ;
    USE SIGNAL ;
    PORT
      LAYER M4 ;
        RECT  0 49.104 0.084 49.128 ;
    END
  END a_cfg_data[83]
  PIN a_cfg_data[84]
    DIRECTION OUTPUT ;
    USE SIGNAL ;
    PORT
      LAYER M4 ;
        RECT  0 39.984 0.084 40.008 ;
    END
  END a_cfg_data[84]
  PIN a_cfg_data[85]
    DIRECTION OUTPUT ;
    USE SIGNAL ;
    PORT
      LAYER M4 ;
        RECT  0 40.08 0.084 40.104 ;
    END
  END a_cfg_data[85]
  PIN a_cfg_data[86]
    DIRECTION OUTPUT ;
    USE SIGNAL ;
    PORT
      LAYER M4 ;
        RECT  0 40.176 0.084 40.2 ;
    END
  END a_cfg_data[86]
  PIN a_cfg_data[87]
    DIRECTION OUTPUT ;
    USE SIGNAL ;
    PORT
      LAYER M4 ;
        RECT  0 40.272 0.084 40.296 ;
    END
  END a_cfg_data[87]
  PIN a_cfg_data[88]
    DIRECTION OUTPUT ;
    USE SIGNAL ;
    PORT
      LAYER M4 ;
        RECT  0 40.368 0.084 40.392 ;
    END
  END a_cfg_data[88]
  PIN a_cfg_data[89]
    DIRECTION OUTPUT ;
    USE SIGNAL ;
    PORT
      LAYER M4 ;
        RECT  0 40.464 0.084 40.488 ;
    END
  END a_cfg_data[89]
  PIN a_cfg_data[8]
    DIRECTION OUTPUT ;
    USE SIGNAL ;
    PORT
      LAYER M4 ;
        RECT  0 38.832 0.084 38.856 ;
    END
  END a_cfg_data[8]
  PIN a_cfg_data[90]
    DIRECTION OUTPUT ;
    USE SIGNAL ;
    PORT
      LAYER M4 ;
        RECT  0 40.56 0.084 40.584 ;
    END
  END a_cfg_data[90]
  PIN a_cfg_data[91]
    DIRECTION OUTPUT ;
    USE SIGNAL ;
    PORT
      LAYER M4 ;
        RECT  0 40.656 0.084 40.68 ;
    END
  END a_cfg_data[91]
  PIN a_cfg_data[92]
    DIRECTION OUTPUT ;
    USE SIGNAL ;
    PORT
      LAYER M4 ;
        RECT  0 40.752 0.084 40.776 ;
    END
  END a_cfg_data[92]
  PIN a_cfg_data[93]
    DIRECTION OUTPUT ;
    USE SIGNAL ;
    PORT
      LAYER M4 ;
        RECT  0 40.848 0.084 40.872 ;
    END
  END a_cfg_data[93]
  PIN a_cfg_data[94]
    DIRECTION OUTPUT ;
    USE SIGNAL ;
    PORT
      LAYER M4 ;
        RECT  0 40.944 0.084 40.968 ;
    END
  END a_cfg_data[94]
  PIN a_cfg_data[95]
    DIRECTION OUTPUT ;
    USE SIGNAL ;
    PORT
      LAYER M4 ;
        RECT  0 41.04 0.084 41.064 ;
    END
  END a_cfg_data[95]
  PIN a_cfg_data[96]
    DIRECTION OUTPUT ;
    USE SIGNAL ;
    PORT
      LAYER M4 ;
        RECT  0 41.136 0.084 41.16 ;
    END
  END a_cfg_data[96]
  PIN a_cfg_data[97]
    DIRECTION OUTPUT ;
    USE SIGNAL ;
    PORT
      LAYER M4 ;
        RECT  0 41.232 0.084 41.256 ;
    END
  END a_cfg_data[97]
  PIN a_cfg_data[98]
    DIRECTION OUTPUT ;
    USE SIGNAL ;
    PORT
      LAYER M4 ;
        RECT  0 41.328 0.084 41.352 ;
    END
  END a_cfg_data[98]
  PIN a_cfg_data[99]
    DIRECTION OUTPUT ;
    USE SIGNAL ;
    PORT
      LAYER M4 ;
        RECT  0 41.424 0.084 41.448 ;
    END
  END a_cfg_data[99]
  PIN a_cfg_data[9]
    DIRECTION OUTPUT ;
    USE SIGNAL ;
    PORT
      LAYER M4 ;
        RECT  0 38.928 0.084 38.952 ;
    END
  END a_cfg_data[9]
  PIN a_cfg_target[0]
    DIRECTION OUTPUT ;
    USE SIGNAL ;
    PORT
      LAYER M4 ;
        RECT  0 28.08 0.084 28.104 ;
    END
  END a_cfg_target[0]
  PIN a_cfg_target[1]
    DIRECTION OUTPUT ;
    USE SIGNAL ;
    PORT
      LAYER M4 ;
        RECT  0 28.176 0.084 28.2 ;
    END
  END a_cfg_target[1]
  PIN a_cfg_target[2]
    DIRECTION OUTPUT ;
    USE SIGNAL ;
    PORT
      LAYER M4 ;
        RECT  0 28.272 0.084 28.296 ;
    END
  END a_cfg_target[2]
  PIN a_cfg_target[3]
    DIRECTION OUTPUT ;
    USE SIGNAL ;
    PORT
      LAYER M4 ;
        RECT  0 28.368 0.084 28.392 ;
    END
  END a_cfg_target[3]
  PIN a_cfg_target[4]
    DIRECTION OUTPUT ;
    USE SIGNAL ;
    PORT
      LAYER M4 ;
        RECT  0 28.464 0.084 28.488 ;
    END
  END a_cfg_target[4]
  PIN a_cfg_target[5]
    DIRECTION OUTPUT ;
    USE SIGNAL ;
    PORT
      LAYER M4 ;
        RECT  0 28.56 0.084 28.584 ;
    END
  END a_cfg_target[5]
  PIN a_cfg_target[6]
    DIRECTION OUTPUT ;
    USE SIGNAL ;
    PORT
      LAYER M4 ;
        RECT  0 28.656 0.084 28.68 ;
    END
  END a_cfg_target[6]
  PIN a_cfg_target[7]
    DIRECTION OUTPUT ;
    USE SIGNAL ;
    PORT
      LAYER M4 ;
        RECT  0 28.752 0.084 28.776 ;
    END
  END a_cfg_target[7]
  PIN a_cfg_v
    DIRECTION OUTPUT ;
    USE SIGNAL ;
    PORT
      LAYER M4 ;
        RECT  0 28.848 0.084 28.872 ;
    END
  END a_cfg_v
  PIN a_desc_base[0]
    DIRECTION OUTPUT ;
    USE SIGNAL ;
    PORT
      LAYER M4 ;
        RECT  0 28.944 0.084 28.968 ;
    END
  END a_desc_base[0]
  PIN a_desc_base[10]
    DIRECTION OUTPUT ;
    USE SIGNAL ;
    PORT
      LAYER M4 ;
        RECT  0 29.904 0.084 29.928 ;
    END
  END a_desc_base[10]
  PIN a_desc_base[11]
    DIRECTION OUTPUT ;
    USE SIGNAL ;
    PORT
      LAYER M4 ;
        RECT  0 23.856 0.084 23.88 ;
    END
  END a_desc_base[11]
  PIN a_desc_base[1]
    DIRECTION OUTPUT ;
    USE SIGNAL ;
    PORT
      LAYER M4 ;
        RECT  0 29.04 0.084 29.064 ;
    END
  END a_desc_base[1]
  PIN a_desc_base[2]
    DIRECTION OUTPUT ;
    USE SIGNAL ;
    PORT
      LAYER M4 ;
        RECT  0 29.136 0.084 29.16 ;
    END
  END a_desc_base[2]
  PIN a_desc_base[3]
    DIRECTION OUTPUT ;
    USE SIGNAL ;
    PORT
      LAYER M4 ;
        RECT  0 29.232 0.084 29.256 ;
    END
  END a_desc_base[3]
  PIN a_desc_base[4]
    DIRECTION OUTPUT ;
    USE SIGNAL ;
    PORT
      LAYER M4 ;
        RECT  0 29.328 0.084 29.352 ;
    END
  END a_desc_base[4]
  PIN a_desc_base[5]
    DIRECTION OUTPUT ;
    USE SIGNAL ;
    PORT
      LAYER M4 ;
        RECT  0 29.424 0.084 29.448 ;
    END
  END a_desc_base[5]
  PIN a_desc_base[6]
    DIRECTION OUTPUT ;
    USE SIGNAL ;
    PORT
      LAYER M4 ;
        RECT  0 29.52 0.084 29.544 ;
    END
  END a_desc_base[6]
  PIN a_desc_base[7]
    DIRECTION OUTPUT ;
    USE SIGNAL ;
    PORT
      LAYER M4 ;
        RECT  0 29.616 0.084 29.64 ;
    END
  END a_desc_base[7]
  PIN a_desc_base[8]
    DIRECTION OUTPUT ;
    USE SIGNAL ;
    PORT
      LAYER M4 ;
        RECT  0 29.712 0.084 29.736 ;
    END
  END a_desc_base[8]
  PIN a_desc_base[9]
    DIRECTION OUTPUT ;
    USE SIGNAL ;
    PORT
      LAYER M4 ;
        RECT  0 29.808 0.084 29.832 ;
    END
  END a_desc_base[9]
  PIN a_desc_limit[0]
    DIRECTION OUTPUT ;
    USE SIGNAL ;
    PORT
      LAYER M4 ;
        RECT  0 23.952 0.084 23.976 ;
    END
  END a_desc_limit[0]
  PIN a_desc_limit[10]
    DIRECTION OUTPUT ;
    USE SIGNAL ;
    PORT
      LAYER M4 ;
        RECT  0 24.912 0.084 24.936 ;
    END
  END a_desc_limit[10]
  PIN a_desc_limit[11]
    DIRECTION OUTPUT ;
    USE SIGNAL ;
    PORT
      LAYER M4 ;
        RECT  0 25.008 0.084 25.032 ;
    END
  END a_desc_limit[11]
  PIN a_desc_limit[12]
    DIRECTION OUTPUT ;
    USE SIGNAL ;
    PORT
      LAYER M4 ;
        RECT  0 25.104 0.084 25.128 ;
    END
  END a_desc_limit[12]
  PIN a_desc_limit[1]
    DIRECTION OUTPUT ;
    USE SIGNAL ;
    PORT
      LAYER M4 ;
        RECT  0 24.048 0.084 24.072 ;
    END
  END a_desc_limit[1]
  PIN a_desc_limit[2]
    DIRECTION OUTPUT ;
    USE SIGNAL ;
    PORT
      LAYER M4 ;
        RECT  0 24.144 0.084 24.168 ;
    END
  END a_desc_limit[2]
  PIN a_desc_limit[3]
    DIRECTION OUTPUT ;
    USE SIGNAL ;
    PORT
      LAYER M4 ;
        RECT  0 24.24 0.084 24.264 ;
    END
  END a_desc_limit[3]
  PIN a_desc_limit[4]
    DIRECTION OUTPUT ;
    USE SIGNAL ;
    PORT
      LAYER M4 ;
        RECT  0 24.336 0.084 24.36 ;
    END
  END a_desc_limit[4]
  PIN a_desc_limit[5]
    DIRECTION OUTPUT ;
    USE SIGNAL ;
    PORT
      LAYER M4 ;
        RECT  0 24.432 0.084 24.456 ;
    END
  END a_desc_limit[5]
  PIN a_desc_limit[6]
    DIRECTION OUTPUT ;
    USE SIGNAL ;
    PORT
      LAYER M4 ;
        RECT  0 24.528 0.084 24.552 ;
    END
  END a_desc_limit[6]
  PIN a_desc_limit[7]
    DIRECTION OUTPUT ;
    USE SIGNAL ;
    PORT
      LAYER M4 ;
        RECT  0 24.624 0.084 24.648 ;
    END
  END a_desc_limit[7]
  PIN a_desc_limit[8]
    DIRECTION OUTPUT ;
    USE SIGNAL ;
    PORT
      LAYER M4 ;
        RECT  0 24.72 0.084 24.744 ;
    END
  END a_desc_limit[8]
  PIN a_desc_limit[9]
    DIRECTION OUTPUT ;
    USE SIGNAL ;
    PORT
      LAYER M4 ;
        RECT  0 24.816 0.084 24.84 ;
    END
  END a_desc_limit[9]
  PIN a_desc_loops[0]
    DIRECTION OUTPUT ;
    USE SIGNAL ;
    PORT
      LAYER M4 ;
        RECT  0 25.2 0.084 25.224 ;
    END
  END a_desc_loops[0]
  PIN a_desc_loops[10]
    DIRECTION OUTPUT ;
    USE SIGNAL ;
    PORT
      LAYER M4 ;
        RECT  0 26.16 0.084 26.184 ;
    END
  END a_desc_loops[10]
  PIN a_desc_loops[11]
    DIRECTION OUTPUT ;
    USE SIGNAL ;
    PORT
      LAYER M4 ;
        RECT  0 26.256 0.084 26.28 ;
    END
  END a_desc_loops[11]
  PIN a_desc_loops[12]
    DIRECTION OUTPUT ;
    USE SIGNAL ;
    PORT
      LAYER M4 ;
        RECT  0 26.352 0.084 26.376 ;
    END
  END a_desc_loops[12]
  PIN a_desc_loops[13]
    DIRECTION OUTPUT ;
    USE SIGNAL ;
    PORT
      LAYER M4 ;
        RECT  0 26.448 0.084 26.472 ;
    END
  END a_desc_loops[13]
  PIN a_desc_loops[14]
    DIRECTION OUTPUT ;
    USE SIGNAL ;
    PORT
      LAYER M4 ;
        RECT  0 26.544 0.084 26.568 ;
    END
  END a_desc_loops[14]
  PIN a_desc_loops[15]
    DIRECTION OUTPUT ;
    USE SIGNAL ;
    PORT
      LAYER M4 ;
        RECT  0 26.64 0.084 26.664 ;
    END
  END a_desc_loops[15]
  PIN a_desc_loops[1]
    DIRECTION OUTPUT ;
    USE SIGNAL ;
    PORT
      LAYER M4 ;
        RECT  0 25.296 0.084 25.32 ;
    END
  END a_desc_loops[1]
  PIN a_desc_loops[2]
    DIRECTION OUTPUT ;
    USE SIGNAL ;
    PORT
      LAYER M4 ;
        RECT  0 25.392 0.084 25.416 ;
    END
  END a_desc_loops[2]
  PIN a_desc_loops[3]
    DIRECTION OUTPUT ;
    USE SIGNAL ;
    PORT
      LAYER M4 ;
        RECT  0 25.488 0.084 25.512 ;
    END
  END a_desc_loops[3]
  PIN a_desc_loops[4]
    DIRECTION OUTPUT ;
    USE SIGNAL ;
    PORT
      LAYER M4 ;
        RECT  0 25.584 0.084 25.608 ;
    END
  END a_desc_loops[4]
  PIN a_desc_loops[5]
    DIRECTION OUTPUT ;
    USE SIGNAL ;
    PORT
      LAYER M4 ;
        RECT  0 25.68 0.084 25.704 ;
    END
  END a_desc_loops[5]
  PIN a_desc_loops[6]
    DIRECTION OUTPUT ;
    USE SIGNAL ;
    PORT
      LAYER M4 ;
        RECT  0 25.776 0.084 25.8 ;
    END
  END a_desc_loops[6]
  PIN a_desc_loops[7]
    DIRECTION OUTPUT ;
    USE SIGNAL ;
    PORT
      LAYER M4 ;
        RECT  0 25.872 0.084 25.896 ;
    END
  END a_desc_loops[7]
  PIN a_desc_loops[8]
    DIRECTION OUTPUT ;
    USE SIGNAL ;
    PORT
      LAYER M4 ;
        RECT  0 25.968 0.084 25.992 ;
    END
  END a_desc_loops[8]
  PIN a_desc_loops[9]
    DIRECTION OUTPUT ;
    USE SIGNAL ;
    PORT
      LAYER M4 ;
        RECT  0 26.064 0.084 26.088 ;
    END
  END a_desc_loops[9]
  PIN a_desc_v
    DIRECTION OUTPUT ;
    USE SIGNAL ;
    PORT
      LAYER M4 ;
        RECT  0 26.736 0.084 26.76 ;
    END
  END a_desc_v
  PIN a_launch_v
    DIRECTION OUTPUT ;
    USE SIGNAL ;
    PORT
      LAYER M4 ;
        RECT  0 26.832 0.084 26.856 ;
    END
  END a_launch_v
  PIN b_cfg_addr[0]
    DIRECTION OUTPUT ;
    USE SIGNAL ;
    PORT
      LAYER M4 ;
        RECT  69.036 32.208 69.12 32.232 ;
    END
  END b_cfg_addr[0]
  PIN b_cfg_addr[10]
    DIRECTION OUTPUT ;
    USE SIGNAL ;
    PORT
      LAYER M4 ;
        RECT  69.036 33.168 69.12 33.192 ;
    END
  END b_cfg_addr[10]
  PIN b_cfg_addr[11]
    DIRECTION OUTPUT ;
    USE SIGNAL ;
    PORT
      LAYER M4 ;
        RECT  69.036 33.264 69.12 33.288 ;
    END
  END b_cfg_addr[11]
  PIN b_cfg_addr[1]
    DIRECTION OUTPUT ;
    USE SIGNAL ;
    PORT
      LAYER M4 ;
        RECT  69.036 32.304 69.12 32.328 ;
    END
  END b_cfg_addr[1]
  PIN b_cfg_addr[2]
    DIRECTION OUTPUT ;
    USE SIGNAL ;
    PORT
      LAYER M4 ;
        RECT  69.036 32.4 69.12 32.424 ;
    END
  END b_cfg_addr[2]
  PIN b_cfg_addr[3]
    DIRECTION OUTPUT ;
    USE SIGNAL ;
    PORT
      LAYER M4 ;
        RECT  69.036 32.496 69.12 32.52 ;
    END
  END b_cfg_addr[3]
  PIN b_cfg_addr[4]
    DIRECTION OUTPUT ;
    USE SIGNAL ;
    PORT
      LAYER M4 ;
        RECT  69.036 32.592 69.12 32.616 ;
    END
  END b_cfg_addr[4]
  PIN b_cfg_addr[5]
    DIRECTION OUTPUT ;
    USE SIGNAL ;
    PORT
      LAYER M4 ;
        RECT  69.036 32.688 69.12 32.712 ;
    END
  END b_cfg_addr[5]
  PIN b_cfg_addr[6]
    DIRECTION OUTPUT ;
    USE SIGNAL ;
    PORT
      LAYER M4 ;
        RECT  69.036 32.784 69.12 32.808 ;
    END
  END b_cfg_addr[6]
  PIN b_cfg_addr[7]
    DIRECTION OUTPUT ;
    USE SIGNAL ;
    PORT
      LAYER M4 ;
        RECT  69.036 32.88 69.12 32.904 ;
    END
  END b_cfg_addr[7]
  PIN b_cfg_addr[8]
    DIRECTION OUTPUT ;
    USE SIGNAL ;
    PORT
      LAYER M4 ;
        RECT  69.036 32.976 69.12 33 ;
    END
  END b_cfg_addr[8]
  PIN b_cfg_addr[9]
    DIRECTION OUTPUT ;
    USE SIGNAL ;
    PORT
      LAYER M4 ;
        RECT  69.036 33.072 69.12 33.096 ;
    END
  END b_cfg_addr[9]
  PIN b_cfg_data[0]
    DIRECTION OUTPUT ;
    USE SIGNAL ;
    PORT
      LAYER M4 ;
        RECT  69.036 33.36 69.12 33.384 ;
    END
  END b_cfg_data[0]
  PIN b_cfg_data[100]
    DIRECTION OUTPUT ;
    USE SIGNAL ;
    PORT
      LAYER M4 ;
        RECT  69.036 36.816 69.12 36.84 ;
    END
  END b_cfg_data[100]
  PIN b_cfg_data[101]
    DIRECTION OUTPUT ;
    USE SIGNAL ;
    PORT
      LAYER M4 ;
        RECT  69.036 36.912 69.12 36.936 ;
    END
  END b_cfg_data[101]
  PIN b_cfg_data[102]
    DIRECTION OUTPUT ;
    USE SIGNAL ;
    PORT
      LAYER M4 ;
        RECT  69.036 37.008 69.12 37.032 ;
    END
  END b_cfg_data[102]
  PIN b_cfg_data[103]
    DIRECTION OUTPUT ;
    USE SIGNAL ;
    PORT
      LAYER M4 ;
        RECT  69.036 37.104 69.12 37.128 ;
    END
  END b_cfg_data[103]
  PIN b_cfg_data[104]
    DIRECTION OUTPUT ;
    USE SIGNAL ;
    PORT
      LAYER M4 ;
        RECT  69.036 37.2 69.12 37.224 ;
    END
  END b_cfg_data[104]
  PIN b_cfg_data[105]
    DIRECTION OUTPUT ;
    USE SIGNAL ;
    PORT
      LAYER M4 ;
        RECT  69.036 37.296 69.12 37.32 ;
    END
  END b_cfg_data[105]
  PIN b_cfg_data[106]
    DIRECTION OUTPUT ;
    USE SIGNAL ;
    PORT
      LAYER M4 ;
        RECT  69.036 37.392 69.12 37.416 ;
    END
  END b_cfg_data[106]
  PIN b_cfg_data[107]
    DIRECTION OUTPUT ;
    USE SIGNAL ;
    PORT
      LAYER M4 ;
        RECT  69.036 37.488 69.12 37.512 ;
    END
  END b_cfg_data[107]
  PIN b_cfg_data[108]
    DIRECTION OUTPUT ;
    USE SIGNAL ;
    PORT
      LAYER M4 ;
        RECT  69.036 37.584 69.12 37.608 ;
    END
  END b_cfg_data[108]
  PIN b_cfg_data[109]
    DIRECTION OUTPUT ;
    USE SIGNAL ;
    PORT
      LAYER M4 ;
        RECT  69.036 37.68 69.12 37.704 ;
    END
  END b_cfg_data[109]
  PIN b_cfg_data[10]
    DIRECTION OUTPUT ;
    USE SIGNAL ;
    PORT
      LAYER M4 ;
        RECT  69.036 34.32 69.12 34.344 ;
    END
  END b_cfg_data[10]
  PIN b_cfg_data[110]
    DIRECTION OUTPUT ;
    USE SIGNAL ;
    PORT
      LAYER M4 ;
        RECT  69.036 37.776 69.12 37.8 ;
    END
  END b_cfg_data[110]
  PIN b_cfg_data[111]
    DIRECTION OUTPUT ;
    USE SIGNAL ;
    PORT
      LAYER M4 ;
        RECT  69.036 37.872 69.12 37.896 ;
    END
  END b_cfg_data[111]
  PIN b_cfg_data[112]
    DIRECTION OUTPUT ;
    USE SIGNAL ;
    PORT
      LAYER M4 ;
        RECT  69.036 37.968 69.12 37.992 ;
    END
  END b_cfg_data[112]
  PIN b_cfg_data[113]
    DIRECTION OUTPUT ;
    USE SIGNAL ;
    PORT
      LAYER M4 ;
        RECT  69.036 38.064 69.12 38.088 ;
    END
  END b_cfg_data[113]
  PIN b_cfg_data[114]
    DIRECTION OUTPUT ;
    USE SIGNAL ;
    PORT
      LAYER M4 ;
        RECT  69.036 38.16 69.12 38.184 ;
    END
  END b_cfg_data[114]
  PIN b_cfg_data[115]
    DIRECTION OUTPUT ;
    USE SIGNAL ;
    PORT
      LAYER M4 ;
        RECT  69.036 38.256 69.12 38.28 ;
    END
  END b_cfg_data[115]
  PIN b_cfg_data[116]
    DIRECTION OUTPUT ;
    USE SIGNAL ;
    PORT
      LAYER M4 ;
        RECT  69.036 45.264 69.12 45.288 ;
    END
  END b_cfg_data[116]
  PIN b_cfg_data[117]
    DIRECTION OUTPUT ;
    USE SIGNAL ;
    PORT
      LAYER M4 ;
        RECT  69.036 45.36 69.12 45.384 ;
    END
  END b_cfg_data[117]
  PIN b_cfg_data[118]
    DIRECTION OUTPUT ;
    USE SIGNAL ;
    PORT
      LAYER M4 ;
        RECT  69.036 45.456 69.12 45.48 ;
    END
  END b_cfg_data[118]
  PIN b_cfg_data[119]
    DIRECTION OUTPUT ;
    USE SIGNAL ;
    PORT
      LAYER M4 ;
        RECT  69.036 45.552 69.12 45.576 ;
    END
  END b_cfg_data[119]
  PIN b_cfg_data[11]
    DIRECTION OUTPUT ;
    USE SIGNAL ;
    PORT
      LAYER M4 ;
        RECT  69.036 34.416 69.12 34.44 ;
    END
  END b_cfg_data[11]
  PIN b_cfg_data[120]
    DIRECTION OUTPUT ;
    USE SIGNAL ;
    PORT
      LAYER M4 ;
        RECT  69.036 45.648 69.12 45.672 ;
    END
  END b_cfg_data[120]
  PIN b_cfg_data[121]
    DIRECTION OUTPUT ;
    USE SIGNAL ;
    PORT
      LAYER M4 ;
        RECT  69.036 45.744 69.12 45.768 ;
    END
  END b_cfg_data[121]
  PIN b_cfg_data[122]
    DIRECTION OUTPUT ;
    USE SIGNAL ;
    PORT
      LAYER M4 ;
        RECT  69.036 45.84 69.12 45.864 ;
    END
  END b_cfg_data[122]
  PIN b_cfg_data[123]
    DIRECTION OUTPUT ;
    USE SIGNAL ;
    PORT
      LAYER M4 ;
        RECT  69.036 45.936 69.12 45.96 ;
    END
  END b_cfg_data[123]
  PIN b_cfg_data[124]
    DIRECTION OUTPUT ;
    USE SIGNAL ;
    PORT
      LAYER M4 ;
        RECT  69.036 46.032 69.12 46.056 ;
    END
  END b_cfg_data[124]
  PIN b_cfg_data[125]
    DIRECTION OUTPUT ;
    USE SIGNAL ;
    PORT
      LAYER M4 ;
        RECT  69.036 46.128 69.12 46.152 ;
    END
  END b_cfg_data[125]
  PIN b_cfg_data[126]
    DIRECTION OUTPUT ;
    USE SIGNAL ;
    PORT
      LAYER M4 ;
        RECT  69.036 46.224 69.12 46.248 ;
    END
  END b_cfg_data[126]
  PIN b_cfg_data[127]
    DIRECTION OUTPUT ;
    USE SIGNAL ;
    PORT
      LAYER M4 ;
        RECT  69.036 46.32 69.12 46.344 ;
    END
  END b_cfg_data[127]
  PIN b_cfg_data[128]
    DIRECTION OUTPUT ;
    USE SIGNAL ;
    PORT
      LAYER M4 ;
        RECT  69.036 46.416 69.12 46.44 ;
    END
  END b_cfg_data[128]
  PIN b_cfg_data[129]
    DIRECTION OUTPUT ;
    USE SIGNAL ;
    PORT
      LAYER M4 ;
        RECT  69.036 46.512 69.12 46.536 ;
    END
  END b_cfg_data[129]
  PIN b_cfg_data[12]
    DIRECTION OUTPUT ;
    USE SIGNAL ;
    PORT
      LAYER M4 ;
        RECT  69.036 34.512 69.12 34.536 ;
    END
  END b_cfg_data[12]
  PIN b_cfg_data[130]
    DIRECTION OUTPUT ;
    USE SIGNAL ;
    PORT
      LAYER M4 ;
        RECT  69.036 46.608 69.12 46.632 ;
    END
  END b_cfg_data[130]
  PIN b_cfg_data[131]
    DIRECTION OUTPUT ;
    USE SIGNAL ;
    PORT
      LAYER M4 ;
        RECT  69.036 46.704 69.12 46.728 ;
    END
  END b_cfg_data[131]
  PIN b_cfg_data[132]
    DIRECTION OUTPUT ;
    USE SIGNAL ;
    PORT
      LAYER M4 ;
        RECT  69.036 46.8 69.12 46.824 ;
    END
  END b_cfg_data[132]
  PIN b_cfg_data[133]
    DIRECTION OUTPUT ;
    USE SIGNAL ;
    PORT
      LAYER M4 ;
        RECT  69.036 46.896 69.12 46.92 ;
    END
  END b_cfg_data[133]
  PIN b_cfg_data[134]
    DIRECTION OUTPUT ;
    USE SIGNAL ;
    PORT
      LAYER M4 ;
        RECT  69.036 46.992 69.12 47.016 ;
    END
  END b_cfg_data[134]
  PIN b_cfg_data[135]
    DIRECTION OUTPUT ;
    USE SIGNAL ;
    PORT
      LAYER M4 ;
        RECT  69.036 47.088 69.12 47.112 ;
    END
  END b_cfg_data[135]
  PIN b_cfg_data[136]
    DIRECTION OUTPUT ;
    USE SIGNAL ;
    PORT
      LAYER M4 ;
        RECT  69.036 47.184 69.12 47.208 ;
    END
  END b_cfg_data[136]
  PIN b_cfg_data[137]
    DIRECTION OUTPUT ;
    USE SIGNAL ;
    PORT
      LAYER M4 ;
        RECT  69.036 47.28 69.12 47.304 ;
    END
  END b_cfg_data[137]
  PIN b_cfg_data[138]
    DIRECTION OUTPUT ;
    USE SIGNAL ;
    PORT
      LAYER M4 ;
        RECT  69.036 47.376 69.12 47.4 ;
    END
  END b_cfg_data[138]
  PIN b_cfg_data[139]
    DIRECTION OUTPUT ;
    USE SIGNAL ;
    PORT
      LAYER M4 ;
        RECT  69.036 47.472 69.12 47.496 ;
    END
  END b_cfg_data[139]
  PIN b_cfg_data[13]
    DIRECTION OUTPUT ;
    USE SIGNAL ;
    PORT
      LAYER M4 ;
        RECT  69.036 34.608 69.12 34.632 ;
    END
  END b_cfg_data[13]
  PIN b_cfg_data[140]
    DIRECTION OUTPUT ;
    USE SIGNAL ;
    PORT
      LAYER M4 ;
        RECT  69.036 47.568 69.12 47.592 ;
    END
  END b_cfg_data[140]
  PIN b_cfg_data[141]
    DIRECTION OUTPUT ;
    USE SIGNAL ;
    PORT
      LAYER M4 ;
        RECT  69.036 47.664 69.12 47.688 ;
    END
  END b_cfg_data[141]
  PIN b_cfg_data[142]
    DIRECTION OUTPUT ;
    USE SIGNAL ;
    PORT
      LAYER M4 ;
        RECT  69.036 47.76 69.12 47.784 ;
    END
  END b_cfg_data[142]
  PIN b_cfg_data[143]
    DIRECTION OUTPUT ;
    USE SIGNAL ;
    PORT
      LAYER M4 ;
        RECT  69.036 47.856 69.12 47.88 ;
    END
  END b_cfg_data[143]
  PIN b_cfg_data[144]
    DIRECTION OUTPUT ;
    USE SIGNAL ;
    PORT
      LAYER M4 ;
        RECT  69.036 47.952 69.12 47.976 ;
    END
  END b_cfg_data[144]
  PIN b_cfg_data[145]
    DIRECTION OUTPUT ;
    USE SIGNAL ;
    PORT
      LAYER M4 ;
        RECT  69.036 48.048 69.12 48.072 ;
    END
  END b_cfg_data[145]
  PIN b_cfg_data[146]
    DIRECTION OUTPUT ;
    USE SIGNAL ;
    PORT
      LAYER M4 ;
        RECT  69.036 48.144 69.12 48.168 ;
    END
  END b_cfg_data[146]
  PIN b_cfg_data[147]
    DIRECTION OUTPUT ;
    USE SIGNAL ;
    PORT
      LAYER M4 ;
        RECT  69.036 48.24 69.12 48.264 ;
    END
  END b_cfg_data[147]
  PIN b_cfg_data[148]
    DIRECTION OUTPUT ;
    USE SIGNAL ;
    PORT
      LAYER M4 ;
        RECT  69.036 19.92 69.12 19.944 ;
    END
  END b_cfg_data[148]
  PIN b_cfg_data[149]
    DIRECTION OUTPUT ;
    USE SIGNAL ;
    PORT
      LAYER M4 ;
        RECT  69.036 20.016 69.12 20.04 ;
    END
  END b_cfg_data[149]
  PIN b_cfg_data[14]
    DIRECTION OUTPUT ;
    USE SIGNAL ;
    PORT
      LAYER M4 ;
        RECT  69.036 34.704 69.12 34.728 ;
    END
  END b_cfg_data[14]
  PIN b_cfg_data[150]
    DIRECTION OUTPUT ;
    USE SIGNAL ;
    PORT
      LAYER M4 ;
        RECT  69.036 20.112 69.12 20.136 ;
    END
  END b_cfg_data[150]
  PIN b_cfg_data[151]
    DIRECTION OUTPUT ;
    USE SIGNAL ;
    PORT
      LAYER M4 ;
        RECT  69.036 20.208 69.12 20.232 ;
    END
  END b_cfg_data[151]
  PIN b_cfg_data[152]
    DIRECTION OUTPUT ;
    USE SIGNAL ;
    PORT
      LAYER M4 ;
        RECT  69.036 20.304 69.12 20.328 ;
    END
  END b_cfg_data[152]
  PIN b_cfg_data[153]
    DIRECTION OUTPUT ;
    USE SIGNAL ;
    PORT
      LAYER M4 ;
        RECT  69.036 20.4 69.12 20.424 ;
    END
  END b_cfg_data[153]
  PIN b_cfg_data[154]
    DIRECTION OUTPUT ;
    USE SIGNAL ;
    PORT
      LAYER M4 ;
        RECT  69.036 20.496 69.12 20.52 ;
    END
  END b_cfg_data[154]
  PIN b_cfg_data[155]
    DIRECTION OUTPUT ;
    USE SIGNAL ;
    PORT
      LAYER M4 ;
        RECT  69.036 20.592 69.12 20.616 ;
    END
  END b_cfg_data[155]
  PIN b_cfg_data[156]
    DIRECTION OUTPUT ;
    USE SIGNAL ;
    PORT
      LAYER M4 ;
        RECT  69.036 20.688 69.12 20.712 ;
    END
  END b_cfg_data[156]
  PIN b_cfg_data[157]
    DIRECTION OUTPUT ;
    USE SIGNAL ;
    PORT
      LAYER M4 ;
        RECT  69.036 20.784 69.12 20.808 ;
    END
  END b_cfg_data[157]
  PIN b_cfg_data[158]
    DIRECTION OUTPUT ;
    USE SIGNAL ;
    PORT
      LAYER M4 ;
        RECT  69.036 20.88 69.12 20.904 ;
    END
  END b_cfg_data[158]
  PIN b_cfg_data[159]
    DIRECTION OUTPUT ;
    USE SIGNAL ;
    PORT
      LAYER M4 ;
        RECT  69.036 20.976 69.12 21 ;
    END
  END b_cfg_data[159]
  PIN b_cfg_data[15]
    DIRECTION OUTPUT ;
    USE SIGNAL ;
    PORT
      LAYER M4 ;
        RECT  69.036 34.8 69.12 34.824 ;
    END
  END b_cfg_data[15]
  PIN b_cfg_data[160]
    DIRECTION OUTPUT ;
    USE SIGNAL ;
    PORT
      LAYER M4 ;
        RECT  69.036 21.072 69.12 21.096 ;
    END
  END b_cfg_data[160]
  PIN b_cfg_data[161]
    DIRECTION OUTPUT ;
    USE SIGNAL ;
    PORT
      LAYER M4 ;
        RECT  69.036 21.168 69.12 21.192 ;
    END
  END b_cfg_data[161]
  PIN b_cfg_data[162]
    DIRECTION OUTPUT ;
    USE SIGNAL ;
    PORT
      LAYER M4 ;
        RECT  69.036 21.264 69.12 21.288 ;
    END
  END b_cfg_data[162]
  PIN b_cfg_data[163]
    DIRECTION OUTPUT ;
    USE SIGNAL ;
    PORT
      LAYER M4 ;
        RECT  69.036 21.36 69.12 21.384 ;
    END
  END b_cfg_data[163]
  PIN b_cfg_data[164]
    DIRECTION OUTPUT ;
    USE SIGNAL ;
    PORT
      LAYER M4 ;
        RECT  69.036 21.456 69.12 21.48 ;
    END
  END b_cfg_data[164]
  PIN b_cfg_data[165]
    DIRECTION OUTPUT ;
    USE SIGNAL ;
    PORT
      LAYER M4 ;
        RECT  69.036 21.552 69.12 21.576 ;
    END
  END b_cfg_data[165]
  PIN b_cfg_data[166]
    DIRECTION OUTPUT ;
    USE SIGNAL ;
    PORT
      LAYER M4 ;
        RECT  69.036 21.648 69.12 21.672 ;
    END
  END b_cfg_data[166]
  PIN b_cfg_data[167]
    DIRECTION OUTPUT ;
    USE SIGNAL ;
    PORT
      LAYER M4 ;
        RECT  69.036 21.744 69.12 21.768 ;
    END
  END b_cfg_data[167]
  PIN b_cfg_data[168]
    DIRECTION OUTPUT ;
    USE SIGNAL ;
    PORT
      LAYER M4 ;
        RECT  69.036 21.84 69.12 21.864 ;
    END
  END b_cfg_data[168]
  PIN b_cfg_data[169]
    DIRECTION OUTPUT ;
    USE SIGNAL ;
    PORT
      LAYER M4 ;
        RECT  69.036 21.936 69.12 21.96 ;
    END
  END b_cfg_data[169]
  PIN b_cfg_data[16]
    DIRECTION OUTPUT ;
    USE SIGNAL ;
    PORT
      LAYER M4 ;
        RECT  69.036 34.896 69.12 34.92 ;
    END
  END b_cfg_data[16]
  PIN b_cfg_data[170]
    DIRECTION OUTPUT ;
    USE SIGNAL ;
    PORT
      LAYER M4 ;
        RECT  69.036 22.032 69.12 22.056 ;
    END
  END b_cfg_data[170]
  PIN b_cfg_data[171]
    DIRECTION OUTPUT ;
    USE SIGNAL ;
    PORT
      LAYER M4 ;
        RECT  69.036 22.128 69.12 22.152 ;
    END
  END b_cfg_data[171]
  PIN b_cfg_data[172]
    DIRECTION OUTPUT ;
    USE SIGNAL ;
    PORT
      LAYER M4 ;
        RECT  69.036 22.224 69.12 22.248 ;
    END
  END b_cfg_data[172]
  PIN b_cfg_data[173]
    DIRECTION OUTPUT ;
    USE SIGNAL ;
    PORT
      LAYER M4 ;
        RECT  69.036 22.32 69.12 22.344 ;
    END
  END b_cfg_data[173]
  PIN b_cfg_data[174]
    DIRECTION OUTPUT ;
    USE SIGNAL ;
    PORT
      LAYER M4 ;
        RECT  69.036 22.416 69.12 22.44 ;
    END
  END b_cfg_data[174]
  PIN b_cfg_data[175]
    DIRECTION OUTPUT ;
    USE SIGNAL ;
    PORT
      LAYER M4 ;
        RECT  69.036 22.512 69.12 22.536 ;
    END
  END b_cfg_data[175]
  PIN b_cfg_data[176]
    DIRECTION OUTPUT ;
    USE SIGNAL ;
    PORT
      LAYER M4 ;
        RECT  69.036 22.608 69.12 22.632 ;
    END
  END b_cfg_data[176]
  PIN b_cfg_data[177]
    DIRECTION OUTPUT ;
    USE SIGNAL ;
    PORT
      LAYER M4 ;
        RECT  69.036 22.704 69.12 22.728 ;
    END
  END b_cfg_data[177]
  PIN b_cfg_data[178]
    DIRECTION OUTPUT ;
    USE SIGNAL ;
    PORT
      LAYER M4 ;
        RECT  69.036 22.8 69.12 22.824 ;
    END
  END b_cfg_data[178]
  PIN b_cfg_data[179]
    DIRECTION OUTPUT ;
    USE SIGNAL ;
    PORT
      LAYER M4 ;
        RECT  69.036 22.896 69.12 22.92 ;
    END
  END b_cfg_data[179]
  PIN b_cfg_data[17]
    DIRECTION OUTPUT ;
    USE SIGNAL ;
    PORT
      LAYER M4 ;
        RECT  69.036 34.992 69.12 35.016 ;
    END
  END b_cfg_data[17]
  PIN b_cfg_data[180]
    DIRECTION OUTPUT ;
    USE SIGNAL ;
    PORT
      LAYER M4 ;
        RECT  69.036 48.336 69.12 48.36 ;
    END
  END b_cfg_data[180]
  PIN b_cfg_data[181]
    DIRECTION OUTPUT ;
    USE SIGNAL ;
    PORT
      LAYER M4 ;
        RECT  69.036 48.432 69.12 48.456 ;
    END
  END b_cfg_data[181]
  PIN b_cfg_data[182]
    DIRECTION OUTPUT ;
    USE SIGNAL ;
    PORT
      LAYER M4 ;
        RECT  69.036 48.528 69.12 48.552 ;
    END
  END b_cfg_data[182]
  PIN b_cfg_data[183]
    DIRECTION OUTPUT ;
    USE SIGNAL ;
    PORT
      LAYER M4 ;
        RECT  69.036 48.624 69.12 48.648 ;
    END
  END b_cfg_data[183]
  PIN b_cfg_data[184]
    DIRECTION OUTPUT ;
    USE SIGNAL ;
    PORT
      LAYER M4 ;
        RECT  69.036 48.72 69.12 48.744 ;
    END
  END b_cfg_data[184]
  PIN b_cfg_data[185]
    DIRECTION OUTPUT ;
    USE SIGNAL ;
    PORT
      LAYER M4 ;
        RECT  69.036 48.816 69.12 48.84 ;
    END
  END b_cfg_data[185]
  PIN b_cfg_data[186]
    DIRECTION OUTPUT ;
    USE SIGNAL ;
    PORT
      LAYER M4 ;
        RECT  69.036 48.912 69.12 48.936 ;
    END
  END b_cfg_data[186]
  PIN b_cfg_data[187]
    DIRECTION OUTPUT ;
    USE SIGNAL ;
    PORT
      LAYER M4 ;
        RECT  69.036 49.008 69.12 49.032 ;
    END
  END b_cfg_data[187]
  PIN b_cfg_data[188]
    DIRECTION OUTPUT ;
    USE SIGNAL ;
    PORT
      LAYER M4 ;
        RECT  69.036 49.104 69.12 49.128 ;
    END
  END b_cfg_data[188]
  PIN b_cfg_data[189]
    DIRECTION OUTPUT ;
    USE SIGNAL ;
    PORT
      LAYER M4 ;
        RECT  69.036 49.2 69.12 49.224 ;
    END
  END b_cfg_data[189]
  PIN b_cfg_data[18]
    DIRECTION OUTPUT ;
    USE SIGNAL ;
    PORT
      LAYER M4 ;
        RECT  69.036 35.088 69.12 35.112 ;
    END
  END b_cfg_data[18]
  PIN b_cfg_data[190]
    DIRECTION OUTPUT ;
    USE SIGNAL ;
    PORT
      LAYER M4 ;
        RECT  69.036 49.296 69.12 49.32 ;
    END
  END b_cfg_data[190]
  PIN b_cfg_data[191]
    DIRECTION OUTPUT ;
    USE SIGNAL ;
    PORT
      LAYER M4 ;
        RECT  69.036 49.392 69.12 49.416 ;
    END
  END b_cfg_data[191]
  PIN b_cfg_data[192]
    DIRECTION OUTPUT ;
    USE SIGNAL ;
    PORT
      LAYER M4 ;
        RECT  69.036 49.488 69.12 49.512 ;
    END
  END b_cfg_data[192]
  PIN b_cfg_data[193]
    DIRECTION OUTPUT ;
    USE SIGNAL ;
    PORT
      LAYER M4 ;
        RECT  69.036 49.584 69.12 49.608 ;
    END
  END b_cfg_data[193]
  PIN b_cfg_data[194]
    DIRECTION OUTPUT ;
    USE SIGNAL ;
    PORT
      LAYER M4 ;
        RECT  69.036 49.68 69.12 49.704 ;
    END
  END b_cfg_data[194]
  PIN b_cfg_data[195]
    DIRECTION OUTPUT ;
    USE SIGNAL ;
    PORT
      LAYER M4 ;
        RECT  69.036 49.776 69.12 49.8 ;
    END
  END b_cfg_data[195]
  PIN b_cfg_data[196]
    DIRECTION OUTPUT ;
    USE SIGNAL ;
    PORT
      LAYER M4 ;
        RECT  69.036 49.872 69.12 49.896 ;
    END
  END b_cfg_data[196]
  PIN b_cfg_data[197]
    DIRECTION OUTPUT ;
    USE SIGNAL ;
    PORT
      LAYER M4 ;
        RECT  69.036 49.968 69.12 49.992 ;
    END
  END b_cfg_data[197]
  PIN b_cfg_data[198]
    DIRECTION OUTPUT ;
    USE SIGNAL ;
    PORT
      LAYER M4 ;
        RECT  69.036 50.064 69.12 50.088 ;
    END
  END b_cfg_data[198]
  PIN b_cfg_data[199]
    DIRECTION OUTPUT ;
    USE SIGNAL ;
    PORT
      LAYER M4 ;
        RECT  69.036 50.16 69.12 50.184 ;
    END
  END b_cfg_data[199]
  PIN b_cfg_data[19]
    DIRECTION OUTPUT ;
    USE SIGNAL ;
    PORT
      LAYER M4 ;
        RECT  69.036 35.184 69.12 35.208 ;
    END
  END b_cfg_data[19]
  PIN b_cfg_data[1]
    DIRECTION OUTPUT ;
    USE SIGNAL ;
    PORT
      LAYER M4 ;
        RECT  69.036 33.456 69.12 33.48 ;
    END
  END b_cfg_data[1]
  PIN b_cfg_data[200]
    DIRECTION OUTPUT ;
    USE SIGNAL ;
    PORT
      LAYER M4 ;
        RECT  69.036 50.256 69.12 50.28 ;
    END
  END b_cfg_data[200]
  PIN b_cfg_data[201]
    DIRECTION OUTPUT ;
    USE SIGNAL ;
    PORT
      LAYER M4 ;
        RECT  69.036 50.352 69.12 50.376 ;
    END
  END b_cfg_data[201]
  PIN b_cfg_data[202]
    DIRECTION OUTPUT ;
    USE SIGNAL ;
    PORT
      LAYER M4 ;
        RECT  69.036 50.448 69.12 50.472 ;
    END
  END b_cfg_data[202]
  PIN b_cfg_data[203]
    DIRECTION OUTPUT ;
    USE SIGNAL ;
    PORT
      LAYER M4 ;
        RECT  69.036 50.544 69.12 50.568 ;
    END
  END b_cfg_data[203]
  PIN b_cfg_data[204]
    DIRECTION OUTPUT ;
    USE SIGNAL ;
    PORT
      LAYER M4 ;
        RECT  69.036 50.64 69.12 50.664 ;
    END
  END b_cfg_data[204]
  PIN b_cfg_data[205]
    DIRECTION OUTPUT ;
    USE SIGNAL ;
    PORT
      LAYER M4 ;
        RECT  69.036 50.736 69.12 50.76 ;
    END
  END b_cfg_data[205]
  PIN b_cfg_data[206]
    DIRECTION OUTPUT ;
    USE SIGNAL ;
    PORT
      LAYER M4 ;
        RECT  69.036 50.832 69.12 50.856 ;
    END
  END b_cfg_data[206]
  PIN b_cfg_data[207]
    DIRECTION OUTPUT ;
    USE SIGNAL ;
    PORT
      LAYER M4 ;
        RECT  69.036 50.928 69.12 50.952 ;
    END
  END b_cfg_data[207]
  PIN b_cfg_data[208]
    DIRECTION OUTPUT ;
    USE SIGNAL ;
    PORT
      LAYER M4 ;
        RECT  69.036 51.024 69.12 51.048 ;
    END
  END b_cfg_data[208]
  PIN b_cfg_data[209]
    DIRECTION OUTPUT ;
    USE SIGNAL ;
    PORT
      LAYER M4 ;
        RECT  69.036 51.12 69.12 51.144 ;
    END
  END b_cfg_data[209]
  PIN b_cfg_data[20]
    DIRECTION OUTPUT ;
    USE SIGNAL ;
    PORT
      LAYER M4 ;
        RECT  69.036 22.992 69.12 23.016 ;
    END
  END b_cfg_data[20]
  PIN b_cfg_data[210]
    DIRECTION OUTPUT ;
    USE SIGNAL ;
    PORT
      LAYER M4 ;
        RECT  69.036 51.216 69.12 51.24 ;
    END
  END b_cfg_data[210]
  PIN b_cfg_data[211]
    DIRECTION OUTPUT ;
    USE SIGNAL ;
    PORT
      LAYER M4 ;
        RECT  69.036 51.312 69.12 51.336 ;
    END
  END b_cfg_data[211]
  PIN b_cfg_data[212]
    DIRECTION OUTPUT ;
    USE SIGNAL ;
    PORT
      LAYER M4 ;
        RECT  69.036 26.064 69.12 26.088 ;
    END
  END b_cfg_data[212]
  PIN b_cfg_data[213]
    DIRECTION OUTPUT ;
    USE SIGNAL ;
    PORT
      LAYER M4 ;
        RECT  69.036 26.16 69.12 26.184 ;
    END
  END b_cfg_data[213]
  PIN b_cfg_data[214]
    DIRECTION OUTPUT ;
    USE SIGNAL ;
    PORT
      LAYER M4 ;
        RECT  69.036 26.256 69.12 26.28 ;
    END
  END b_cfg_data[214]
  PIN b_cfg_data[215]
    DIRECTION OUTPUT ;
    USE SIGNAL ;
    PORT
      LAYER M4 ;
        RECT  69.036 26.352 69.12 26.376 ;
    END
  END b_cfg_data[215]
  PIN b_cfg_data[216]
    DIRECTION OUTPUT ;
    USE SIGNAL ;
    PORT
      LAYER M4 ;
        RECT  69.036 26.448 69.12 26.472 ;
    END
  END b_cfg_data[216]
  PIN b_cfg_data[217]
    DIRECTION OUTPUT ;
    USE SIGNAL ;
    PORT
      LAYER M4 ;
        RECT  69.036 26.544 69.12 26.568 ;
    END
  END b_cfg_data[217]
  PIN b_cfg_data[218]
    DIRECTION OUTPUT ;
    USE SIGNAL ;
    PORT
      LAYER M4 ;
        RECT  69.036 26.64 69.12 26.664 ;
    END
  END b_cfg_data[218]
  PIN b_cfg_data[219]
    DIRECTION OUTPUT ;
    USE SIGNAL ;
    PORT
      LAYER M4 ;
        RECT  69.036 26.736 69.12 26.76 ;
    END
  END b_cfg_data[219]
  PIN b_cfg_data[21]
    DIRECTION OUTPUT ;
    USE SIGNAL ;
    PORT
      LAYER M4 ;
        RECT  69.036 23.088 69.12 23.112 ;
    END
  END b_cfg_data[21]
  PIN b_cfg_data[220]
    DIRECTION OUTPUT ;
    USE SIGNAL ;
    PORT
      LAYER M4 ;
        RECT  69.036 26.832 69.12 26.856 ;
    END
  END b_cfg_data[220]
  PIN b_cfg_data[221]
    DIRECTION OUTPUT ;
    USE SIGNAL ;
    PORT
      LAYER M4 ;
        RECT  69.036 26.928 69.12 26.952 ;
    END
  END b_cfg_data[221]
  PIN b_cfg_data[222]
    DIRECTION OUTPUT ;
    USE SIGNAL ;
    PORT
      LAYER M4 ;
        RECT  69.036 27.024 69.12 27.048 ;
    END
  END b_cfg_data[222]
  PIN b_cfg_data[223]
    DIRECTION OUTPUT ;
    USE SIGNAL ;
    PORT
      LAYER M4 ;
        RECT  69.036 27.12 69.12 27.144 ;
    END
  END b_cfg_data[223]
  PIN b_cfg_data[224]
    DIRECTION OUTPUT ;
    USE SIGNAL ;
    PORT
      LAYER M4 ;
        RECT  69.036 27.216 69.12 27.24 ;
    END
  END b_cfg_data[224]
  PIN b_cfg_data[225]
    DIRECTION OUTPUT ;
    USE SIGNAL ;
    PORT
      LAYER M4 ;
        RECT  69.036 27.312 69.12 27.336 ;
    END
  END b_cfg_data[225]
  PIN b_cfg_data[226]
    DIRECTION OUTPUT ;
    USE SIGNAL ;
    PORT
      LAYER M4 ;
        RECT  69.036 27.408 69.12 27.432 ;
    END
  END b_cfg_data[226]
  PIN b_cfg_data[227]
    DIRECTION OUTPUT ;
    USE SIGNAL ;
    PORT
      LAYER M4 ;
        RECT  69.036 27.504 69.12 27.528 ;
    END
  END b_cfg_data[227]
  PIN b_cfg_data[228]
    DIRECTION OUTPUT ;
    USE SIGNAL ;
    PORT
      LAYER M4 ;
        RECT  69.036 27.6 69.12 27.624 ;
    END
  END b_cfg_data[228]
  PIN b_cfg_data[229]
    DIRECTION OUTPUT ;
    USE SIGNAL ;
    PORT
      LAYER M4 ;
        RECT  69.036 27.696 69.12 27.72 ;
    END
  END b_cfg_data[229]
  PIN b_cfg_data[22]
    DIRECTION OUTPUT ;
    USE SIGNAL ;
    PORT
      LAYER M4 ;
        RECT  69.036 23.184 69.12 23.208 ;
    END
  END b_cfg_data[22]
  PIN b_cfg_data[230]
    DIRECTION OUTPUT ;
    USE SIGNAL ;
    PORT
      LAYER M4 ;
        RECT  69.036 27.792 69.12 27.816 ;
    END
  END b_cfg_data[230]
  PIN b_cfg_data[231]
    DIRECTION OUTPUT ;
    USE SIGNAL ;
    PORT
      LAYER M4 ;
        RECT  69.036 27.888 69.12 27.912 ;
    END
  END b_cfg_data[231]
  PIN b_cfg_data[232]
    DIRECTION OUTPUT ;
    USE SIGNAL ;
    PORT
      LAYER M4 ;
        RECT  69.036 27.984 69.12 28.008 ;
    END
  END b_cfg_data[232]
  PIN b_cfg_data[233]
    DIRECTION OUTPUT ;
    USE SIGNAL ;
    PORT
      LAYER M4 ;
        RECT  69.036 28.08 69.12 28.104 ;
    END
  END b_cfg_data[233]
  PIN b_cfg_data[234]
    DIRECTION OUTPUT ;
    USE SIGNAL ;
    PORT
      LAYER M4 ;
        RECT  69.036 28.176 69.12 28.2 ;
    END
  END b_cfg_data[234]
  PIN b_cfg_data[235]
    DIRECTION OUTPUT ;
    USE SIGNAL ;
    PORT
      LAYER M4 ;
        RECT  69.036 28.272 69.12 28.296 ;
    END
  END b_cfg_data[235]
  PIN b_cfg_data[236]
    DIRECTION OUTPUT ;
    USE SIGNAL ;
    PORT
      LAYER M4 ;
        RECT  69.036 28.368 69.12 28.392 ;
    END
  END b_cfg_data[236]
  PIN b_cfg_data[237]
    DIRECTION OUTPUT ;
    USE SIGNAL ;
    PORT
      LAYER M4 ;
        RECT  69.036 28.464 69.12 28.488 ;
    END
  END b_cfg_data[237]
  PIN b_cfg_data[238]
    DIRECTION OUTPUT ;
    USE SIGNAL ;
    PORT
      LAYER M4 ;
        RECT  69.036 28.56 69.12 28.584 ;
    END
  END b_cfg_data[238]
  PIN b_cfg_data[239]
    DIRECTION OUTPUT ;
    USE SIGNAL ;
    PORT
      LAYER M4 ;
        RECT  69.036 28.656 69.12 28.68 ;
    END
  END b_cfg_data[239]
  PIN b_cfg_data[23]
    DIRECTION OUTPUT ;
    USE SIGNAL ;
    PORT
      LAYER M4 ;
        RECT  69.036 23.28 69.12 23.304 ;
    END
  END b_cfg_data[23]
  PIN b_cfg_data[240]
    DIRECTION OUTPUT ;
    USE SIGNAL ;
    PORT
      LAYER M4 ;
        RECT  69.036 28.752 69.12 28.776 ;
    END
  END b_cfg_data[240]
  PIN b_cfg_data[241]
    DIRECTION OUTPUT ;
    USE SIGNAL ;
    PORT
      LAYER M4 ;
        RECT  69.036 28.848 69.12 28.872 ;
    END
  END b_cfg_data[241]
  PIN b_cfg_data[242]
    DIRECTION OUTPUT ;
    USE SIGNAL ;
    PORT
      LAYER M4 ;
        RECT  69.036 28.944 69.12 28.968 ;
    END
  END b_cfg_data[242]
  PIN b_cfg_data[243]
    DIRECTION OUTPUT ;
    USE SIGNAL ;
    PORT
      LAYER M4 ;
        RECT  69.036 29.04 69.12 29.064 ;
    END
  END b_cfg_data[243]
  PIN b_cfg_data[244]
    DIRECTION OUTPUT ;
    USE SIGNAL ;
    PORT
      LAYER M4 ;
        RECT  69.036 39.12 69.12 39.144 ;
    END
  END b_cfg_data[244]
  PIN b_cfg_data[245]
    DIRECTION OUTPUT ;
    USE SIGNAL ;
    PORT
      LAYER M4 ;
        RECT  69.036 39.216 69.12 39.24 ;
    END
  END b_cfg_data[245]
  PIN b_cfg_data[246]
    DIRECTION OUTPUT ;
    USE SIGNAL ;
    PORT
      LAYER M4 ;
        RECT  69.036 39.312 69.12 39.336 ;
    END
  END b_cfg_data[246]
  PIN b_cfg_data[247]
    DIRECTION OUTPUT ;
    USE SIGNAL ;
    PORT
      LAYER M4 ;
        RECT  69.036 39.408 69.12 39.432 ;
    END
  END b_cfg_data[247]
  PIN b_cfg_data[248]
    DIRECTION OUTPUT ;
    USE SIGNAL ;
    PORT
      LAYER M4 ;
        RECT  69.036 39.504 69.12 39.528 ;
    END
  END b_cfg_data[248]
  PIN b_cfg_data[249]
    DIRECTION OUTPUT ;
    USE SIGNAL ;
    PORT
      LAYER M4 ;
        RECT  69.036 39.6 69.12 39.624 ;
    END
  END b_cfg_data[249]
  PIN b_cfg_data[24]
    DIRECTION OUTPUT ;
    USE SIGNAL ;
    PORT
      LAYER M4 ;
        RECT  69.036 23.376 69.12 23.4 ;
    END
  END b_cfg_data[24]
  PIN b_cfg_data[250]
    DIRECTION OUTPUT ;
    USE SIGNAL ;
    PORT
      LAYER M4 ;
        RECT  69.036 39.696 69.12 39.72 ;
    END
  END b_cfg_data[250]
  PIN b_cfg_data[251]
    DIRECTION OUTPUT ;
    USE SIGNAL ;
    PORT
      LAYER M4 ;
        RECT  69.036 39.792 69.12 39.816 ;
    END
  END b_cfg_data[251]
  PIN b_cfg_data[252]
    DIRECTION OUTPUT ;
    USE SIGNAL ;
    PORT
      LAYER M4 ;
        RECT  69.036 39.888 69.12 39.912 ;
    END
  END b_cfg_data[252]
  PIN b_cfg_data[253]
    DIRECTION OUTPUT ;
    USE SIGNAL ;
    PORT
      LAYER M4 ;
        RECT  69.036 39.984 69.12 40.008 ;
    END
  END b_cfg_data[253]
  PIN b_cfg_data[254]
    DIRECTION OUTPUT ;
    USE SIGNAL ;
    PORT
      LAYER M4 ;
        RECT  69.036 40.08 69.12 40.104 ;
    END
  END b_cfg_data[254]
  PIN b_cfg_data[255]
    DIRECTION OUTPUT ;
    USE SIGNAL ;
    PORT
      LAYER M4 ;
        RECT  69.036 40.176 69.12 40.2 ;
    END
  END b_cfg_data[255]
  PIN b_cfg_data[25]
    DIRECTION OUTPUT ;
    USE SIGNAL ;
    PORT
      LAYER M4 ;
        RECT  69.036 23.472 69.12 23.496 ;
    END
  END b_cfg_data[25]
  PIN b_cfg_data[26]
    DIRECTION OUTPUT ;
    USE SIGNAL ;
    PORT
      LAYER M4 ;
        RECT  69.036 23.568 69.12 23.592 ;
    END
  END b_cfg_data[26]
  PIN b_cfg_data[27]
    DIRECTION OUTPUT ;
    USE SIGNAL ;
    PORT
      LAYER M4 ;
        RECT  69.036 23.664 69.12 23.688 ;
    END
  END b_cfg_data[27]
  PIN b_cfg_data[28]
    DIRECTION OUTPUT ;
    USE SIGNAL ;
    PORT
      LAYER M4 ;
        RECT  69.036 23.76 69.12 23.784 ;
    END
  END b_cfg_data[28]
  PIN b_cfg_data[29]
    DIRECTION OUTPUT ;
    USE SIGNAL ;
    PORT
      LAYER M4 ;
        RECT  69.036 23.856 69.12 23.88 ;
    END
  END b_cfg_data[29]
  PIN b_cfg_data[2]
    DIRECTION OUTPUT ;
    USE SIGNAL ;
    PORT
      LAYER M4 ;
        RECT  69.036 33.552 69.12 33.576 ;
    END
  END b_cfg_data[2]
  PIN b_cfg_data[30]
    DIRECTION OUTPUT ;
    USE SIGNAL ;
    PORT
      LAYER M4 ;
        RECT  69.036 23.952 69.12 23.976 ;
    END
  END b_cfg_data[30]
  PIN b_cfg_data[31]
    DIRECTION OUTPUT ;
    USE SIGNAL ;
    PORT
      LAYER M4 ;
        RECT  69.036 24.048 69.12 24.072 ;
    END
  END b_cfg_data[31]
  PIN b_cfg_data[32]
    DIRECTION OUTPUT ;
    USE SIGNAL ;
    PORT
      LAYER M4 ;
        RECT  69.036 24.144 69.12 24.168 ;
    END
  END b_cfg_data[32]
  PIN b_cfg_data[33]
    DIRECTION OUTPUT ;
    USE SIGNAL ;
    PORT
      LAYER M4 ;
        RECT  69.036 24.24 69.12 24.264 ;
    END
  END b_cfg_data[33]
  PIN b_cfg_data[34]
    DIRECTION OUTPUT ;
    USE SIGNAL ;
    PORT
      LAYER M4 ;
        RECT  69.036 24.336 69.12 24.36 ;
    END
  END b_cfg_data[34]
  PIN b_cfg_data[35]
    DIRECTION OUTPUT ;
    USE SIGNAL ;
    PORT
      LAYER M4 ;
        RECT  69.036 24.432 69.12 24.456 ;
    END
  END b_cfg_data[35]
  PIN b_cfg_data[36]
    DIRECTION OUTPUT ;
    USE SIGNAL ;
    PORT
      LAYER M4 ;
        RECT  69.036 24.528 69.12 24.552 ;
    END
  END b_cfg_data[36]
  PIN b_cfg_data[37]
    DIRECTION OUTPUT ;
    USE SIGNAL ;
    PORT
      LAYER M4 ;
        RECT  69.036 24.624 69.12 24.648 ;
    END
  END b_cfg_data[37]
  PIN b_cfg_data[38]
    DIRECTION OUTPUT ;
    USE SIGNAL ;
    PORT
      LAYER M4 ;
        RECT  69.036 24.72 69.12 24.744 ;
    END
  END b_cfg_data[38]
  PIN b_cfg_data[39]
    DIRECTION OUTPUT ;
    USE SIGNAL ;
    PORT
      LAYER M4 ;
        RECT  69.036 24.816 69.12 24.84 ;
    END
  END b_cfg_data[39]
  PIN b_cfg_data[3]
    DIRECTION OUTPUT ;
    USE SIGNAL ;
    PORT
      LAYER M4 ;
        RECT  69.036 33.648 69.12 33.672 ;
    END
  END b_cfg_data[3]
  PIN b_cfg_data[40]
    DIRECTION OUTPUT ;
    USE SIGNAL ;
    PORT
      LAYER M4 ;
        RECT  69.036 24.912 69.12 24.936 ;
    END
  END b_cfg_data[40]
  PIN b_cfg_data[41]
    DIRECTION OUTPUT ;
    USE SIGNAL ;
    PORT
      LAYER M4 ;
        RECT  69.036 25.008 69.12 25.032 ;
    END
  END b_cfg_data[41]
  PIN b_cfg_data[42]
    DIRECTION OUTPUT ;
    USE SIGNAL ;
    PORT
      LAYER M4 ;
        RECT  69.036 25.104 69.12 25.128 ;
    END
  END b_cfg_data[42]
  PIN b_cfg_data[43]
    DIRECTION OUTPUT ;
    USE SIGNAL ;
    PORT
      LAYER M4 ;
        RECT  69.036 25.2 69.12 25.224 ;
    END
  END b_cfg_data[43]
  PIN b_cfg_data[44]
    DIRECTION OUTPUT ;
    USE SIGNAL ;
    PORT
      LAYER M4 ;
        RECT  69.036 25.296 69.12 25.32 ;
    END
  END b_cfg_data[44]
  PIN b_cfg_data[45]
    DIRECTION OUTPUT ;
    USE SIGNAL ;
    PORT
      LAYER M4 ;
        RECT  69.036 25.392 69.12 25.416 ;
    END
  END b_cfg_data[45]
  PIN b_cfg_data[46]
    DIRECTION OUTPUT ;
    USE SIGNAL ;
    PORT
      LAYER M4 ;
        RECT  69.036 25.488 69.12 25.512 ;
    END
  END b_cfg_data[46]
  PIN b_cfg_data[47]
    DIRECTION OUTPUT ;
    USE SIGNAL ;
    PORT
      LAYER M4 ;
        RECT  69.036 25.584 69.12 25.608 ;
    END
  END b_cfg_data[47]
  PIN b_cfg_data[48]
    DIRECTION OUTPUT ;
    USE SIGNAL ;
    PORT
      LAYER M4 ;
        RECT  69.036 25.68 69.12 25.704 ;
    END
  END b_cfg_data[48]
  PIN b_cfg_data[49]
    DIRECTION OUTPUT ;
    USE SIGNAL ;
    PORT
      LAYER M4 ;
        RECT  69.036 25.776 69.12 25.8 ;
    END
  END b_cfg_data[49]
  PIN b_cfg_data[4]
    DIRECTION OUTPUT ;
    USE SIGNAL ;
    PORT
      LAYER M4 ;
        RECT  69.036 33.744 69.12 33.768 ;
    END
  END b_cfg_data[4]
  PIN b_cfg_data[50]
    DIRECTION OUTPUT ;
    USE SIGNAL ;
    PORT
      LAYER M4 ;
        RECT  69.036 25.872 69.12 25.896 ;
    END
  END b_cfg_data[50]
  PIN b_cfg_data[51]
    DIRECTION OUTPUT ;
    USE SIGNAL ;
    PORT
      LAYER M4 ;
        RECT  69.036 25.968 69.12 25.992 ;
    END
  END b_cfg_data[51]
  PIN b_cfg_data[52]
    DIRECTION OUTPUT ;
    USE SIGNAL ;
    PORT
      LAYER M4 ;
        RECT  69.036 29.136 69.12 29.16 ;
    END
  END b_cfg_data[52]
  PIN b_cfg_data[53]
    DIRECTION OUTPUT ;
    USE SIGNAL ;
    PORT
      LAYER M4 ;
        RECT  69.036 29.232 69.12 29.256 ;
    END
  END b_cfg_data[53]
  PIN b_cfg_data[54]
    DIRECTION OUTPUT ;
    USE SIGNAL ;
    PORT
      LAYER M4 ;
        RECT  69.036 29.328 69.12 29.352 ;
    END
  END b_cfg_data[54]
  PIN b_cfg_data[55]
    DIRECTION OUTPUT ;
    USE SIGNAL ;
    PORT
      LAYER M4 ;
        RECT  69.036 29.424 69.12 29.448 ;
    END
  END b_cfg_data[55]
  PIN b_cfg_data[56]
    DIRECTION OUTPUT ;
    USE SIGNAL ;
    PORT
      LAYER M4 ;
        RECT  69.036 29.52 69.12 29.544 ;
    END
  END b_cfg_data[56]
  PIN b_cfg_data[57]
    DIRECTION OUTPUT ;
    USE SIGNAL ;
    PORT
      LAYER M4 ;
        RECT  69.036 29.616 69.12 29.64 ;
    END
  END b_cfg_data[57]
  PIN b_cfg_data[58]
    DIRECTION OUTPUT ;
    USE SIGNAL ;
    PORT
      LAYER M4 ;
        RECT  69.036 29.712 69.12 29.736 ;
    END
  END b_cfg_data[58]
  PIN b_cfg_data[59]
    DIRECTION OUTPUT ;
    USE SIGNAL ;
    PORT
      LAYER M4 ;
        RECT  69.036 29.808 69.12 29.832 ;
    END
  END b_cfg_data[59]
  PIN b_cfg_data[5]
    DIRECTION OUTPUT ;
    USE SIGNAL ;
    PORT
      LAYER M4 ;
        RECT  69.036 33.84 69.12 33.864 ;
    END
  END b_cfg_data[5]
  PIN b_cfg_data[60]
    DIRECTION OUTPUT ;
    USE SIGNAL ;
    PORT
      LAYER M4 ;
        RECT  69.036 29.904 69.12 29.928 ;
    END
  END b_cfg_data[60]
  PIN b_cfg_data[61]
    DIRECTION OUTPUT ;
    USE SIGNAL ;
    PORT
      LAYER M4 ;
        RECT  69.036 30 69.12 30.024 ;
    END
  END b_cfg_data[61]
  PIN b_cfg_data[62]
    DIRECTION OUTPUT ;
    USE SIGNAL ;
    PORT
      LAYER M4 ;
        RECT  69.036 30.096 69.12 30.12 ;
    END
  END b_cfg_data[62]
  PIN b_cfg_data[63]
    DIRECTION OUTPUT ;
    USE SIGNAL ;
    PORT
      LAYER M4 ;
        RECT  69.036 30.192 69.12 30.216 ;
    END
  END b_cfg_data[63]
  PIN b_cfg_data[64]
    DIRECTION OUTPUT ;
    USE SIGNAL ;
    PORT
      LAYER M4 ;
        RECT  69.036 30.288 69.12 30.312 ;
    END
  END b_cfg_data[64]
  PIN b_cfg_data[65]
    DIRECTION OUTPUT ;
    USE SIGNAL ;
    PORT
      LAYER M4 ;
        RECT  69.036 30.384 69.12 30.408 ;
    END
  END b_cfg_data[65]
  PIN b_cfg_data[66]
    DIRECTION OUTPUT ;
    USE SIGNAL ;
    PORT
      LAYER M4 ;
        RECT  69.036 30.48 69.12 30.504 ;
    END
  END b_cfg_data[66]
  PIN b_cfg_data[67]
    DIRECTION OUTPUT ;
    USE SIGNAL ;
    PORT
      LAYER M4 ;
        RECT  69.036 30.576 69.12 30.6 ;
    END
  END b_cfg_data[67]
  PIN b_cfg_data[68]
    DIRECTION OUTPUT ;
    USE SIGNAL ;
    PORT
      LAYER M4 ;
        RECT  69.036 30.672 69.12 30.696 ;
    END
  END b_cfg_data[68]
  PIN b_cfg_data[69]
    DIRECTION OUTPUT ;
    USE SIGNAL ;
    PORT
      LAYER M4 ;
        RECT  69.036 30.768 69.12 30.792 ;
    END
  END b_cfg_data[69]
  PIN b_cfg_data[6]
    DIRECTION OUTPUT ;
    USE SIGNAL ;
    PORT
      LAYER M4 ;
        RECT  69.036 33.936 69.12 33.96 ;
    END
  END b_cfg_data[6]
  PIN b_cfg_data[70]
    DIRECTION OUTPUT ;
    USE SIGNAL ;
    PORT
      LAYER M4 ;
        RECT  69.036 30.864 69.12 30.888 ;
    END
  END b_cfg_data[70]
  PIN b_cfg_data[71]
    DIRECTION OUTPUT ;
    USE SIGNAL ;
    PORT
      LAYER M4 ;
        RECT  69.036 30.96 69.12 30.984 ;
    END
  END b_cfg_data[71]
  PIN b_cfg_data[72]
    DIRECTION OUTPUT ;
    USE SIGNAL ;
    PORT
      LAYER M4 ;
        RECT  69.036 31.056 69.12 31.08 ;
    END
  END b_cfg_data[72]
  PIN b_cfg_data[73]
    DIRECTION OUTPUT ;
    USE SIGNAL ;
    PORT
      LAYER M4 ;
        RECT  69.036 31.152 69.12 31.176 ;
    END
  END b_cfg_data[73]
  PIN b_cfg_data[74]
    DIRECTION OUTPUT ;
    USE SIGNAL ;
    PORT
      LAYER M4 ;
        RECT  69.036 31.248 69.12 31.272 ;
    END
  END b_cfg_data[74]
  PIN b_cfg_data[75]
    DIRECTION OUTPUT ;
    USE SIGNAL ;
    PORT
      LAYER M4 ;
        RECT  69.036 31.344 69.12 31.368 ;
    END
  END b_cfg_data[75]
  PIN b_cfg_data[76]
    DIRECTION OUTPUT ;
    USE SIGNAL ;
    PORT
      LAYER M4 ;
        RECT  69.036 31.44 69.12 31.464 ;
    END
  END b_cfg_data[76]
  PIN b_cfg_data[77]
    DIRECTION OUTPUT ;
    USE SIGNAL ;
    PORT
      LAYER M4 ;
        RECT  69.036 31.536 69.12 31.56 ;
    END
  END b_cfg_data[77]
  PIN b_cfg_data[78]
    DIRECTION OUTPUT ;
    USE SIGNAL ;
    PORT
      LAYER M4 ;
        RECT  69.036 31.632 69.12 31.656 ;
    END
  END b_cfg_data[78]
  PIN b_cfg_data[79]
    DIRECTION OUTPUT ;
    USE SIGNAL ;
    PORT
      LAYER M4 ;
        RECT  69.036 31.728 69.12 31.752 ;
    END
  END b_cfg_data[79]
  PIN b_cfg_data[7]
    DIRECTION OUTPUT ;
    USE SIGNAL ;
    PORT
      LAYER M4 ;
        RECT  69.036 34.032 69.12 34.056 ;
    END
  END b_cfg_data[7]
  PIN b_cfg_data[80]
    DIRECTION OUTPUT ;
    USE SIGNAL ;
    PORT
      LAYER M4 ;
        RECT  69.036 31.824 69.12 31.848 ;
    END
  END b_cfg_data[80]
  PIN b_cfg_data[81]
    DIRECTION OUTPUT ;
    USE SIGNAL ;
    PORT
      LAYER M4 ;
        RECT  69.036 31.92 69.12 31.944 ;
    END
  END b_cfg_data[81]
  PIN b_cfg_data[82]
    DIRECTION OUTPUT ;
    USE SIGNAL ;
    PORT
      LAYER M4 ;
        RECT  69.036 32.016 69.12 32.04 ;
    END
  END b_cfg_data[82]
  PIN b_cfg_data[83]
    DIRECTION OUTPUT ;
    USE SIGNAL ;
    PORT
      LAYER M4 ;
        RECT  69.036 32.112 69.12 32.136 ;
    END
  END b_cfg_data[83]
  PIN b_cfg_data[84]
    DIRECTION OUTPUT ;
    USE SIGNAL ;
    PORT
      LAYER M4 ;
        RECT  69.036 35.28 69.12 35.304 ;
    END
  END b_cfg_data[84]
  PIN b_cfg_data[85]
    DIRECTION OUTPUT ;
    USE SIGNAL ;
    PORT
      LAYER M4 ;
        RECT  69.036 35.376 69.12 35.4 ;
    END
  END b_cfg_data[85]
  PIN b_cfg_data[86]
    DIRECTION OUTPUT ;
    USE SIGNAL ;
    PORT
      LAYER M4 ;
        RECT  69.036 35.472 69.12 35.496 ;
    END
  END b_cfg_data[86]
  PIN b_cfg_data[87]
    DIRECTION OUTPUT ;
    USE SIGNAL ;
    PORT
      LAYER M4 ;
        RECT  69.036 35.568 69.12 35.592 ;
    END
  END b_cfg_data[87]
  PIN b_cfg_data[88]
    DIRECTION OUTPUT ;
    USE SIGNAL ;
    PORT
      LAYER M4 ;
        RECT  69.036 35.664 69.12 35.688 ;
    END
  END b_cfg_data[88]
  PIN b_cfg_data[89]
    DIRECTION OUTPUT ;
    USE SIGNAL ;
    PORT
      LAYER M4 ;
        RECT  69.036 35.76 69.12 35.784 ;
    END
  END b_cfg_data[89]
  PIN b_cfg_data[8]
    DIRECTION OUTPUT ;
    USE SIGNAL ;
    PORT
      LAYER M4 ;
        RECT  69.036 34.128 69.12 34.152 ;
    END
  END b_cfg_data[8]
  PIN b_cfg_data[90]
    DIRECTION OUTPUT ;
    USE SIGNAL ;
    PORT
      LAYER M4 ;
        RECT  69.036 35.856 69.12 35.88 ;
    END
  END b_cfg_data[90]
  PIN b_cfg_data[91]
    DIRECTION OUTPUT ;
    USE SIGNAL ;
    PORT
      LAYER M4 ;
        RECT  69.036 35.952 69.12 35.976 ;
    END
  END b_cfg_data[91]
  PIN b_cfg_data[92]
    DIRECTION OUTPUT ;
    USE SIGNAL ;
    PORT
      LAYER M4 ;
        RECT  69.036 36.048 69.12 36.072 ;
    END
  END b_cfg_data[92]
  PIN b_cfg_data[93]
    DIRECTION OUTPUT ;
    USE SIGNAL ;
    PORT
      LAYER M4 ;
        RECT  69.036 36.144 69.12 36.168 ;
    END
  END b_cfg_data[93]
  PIN b_cfg_data[94]
    DIRECTION OUTPUT ;
    USE SIGNAL ;
    PORT
      LAYER M4 ;
        RECT  69.036 36.24 69.12 36.264 ;
    END
  END b_cfg_data[94]
  PIN b_cfg_data[95]
    DIRECTION OUTPUT ;
    USE SIGNAL ;
    PORT
      LAYER M4 ;
        RECT  69.036 36.336 69.12 36.36 ;
    END
  END b_cfg_data[95]
  PIN b_cfg_data[96]
    DIRECTION OUTPUT ;
    USE SIGNAL ;
    PORT
      LAYER M4 ;
        RECT  69.036 36.432 69.12 36.456 ;
    END
  END b_cfg_data[96]
  PIN b_cfg_data[97]
    DIRECTION OUTPUT ;
    USE SIGNAL ;
    PORT
      LAYER M4 ;
        RECT  69.036 36.528 69.12 36.552 ;
    END
  END b_cfg_data[97]
  PIN b_cfg_data[98]
    DIRECTION OUTPUT ;
    USE SIGNAL ;
    PORT
      LAYER M4 ;
        RECT  69.036 36.624 69.12 36.648 ;
    END
  END b_cfg_data[98]
  PIN b_cfg_data[99]
    DIRECTION OUTPUT ;
    USE SIGNAL ;
    PORT
      LAYER M4 ;
        RECT  69.036 36.72 69.12 36.744 ;
    END
  END b_cfg_data[99]
  PIN b_cfg_data[9]
    DIRECTION OUTPUT ;
    USE SIGNAL ;
    PORT
      LAYER M4 ;
        RECT  69.036 34.224 69.12 34.248 ;
    END
  END b_cfg_data[9]
  PIN b_cfg_target[0]
    DIRECTION OUTPUT ;
    USE SIGNAL ;
    PORT
      LAYER M4 ;
        RECT  69.036 40.272 69.12 40.296 ;
    END
  END b_cfg_target[0]
  PIN b_cfg_target[1]
    DIRECTION OUTPUT ;
    USE SIGNAL ;
    PORT
      LAYER M4 ;
        RECT  69.036 40.368 69.12 40.392 ;
    END
  END b_cfg_target[1]
  PIN b_cfg_target[2]
    DIRECTION OUTPUT ;
    USE SIGNAL ;
    PORT
      LAYER M4 ;
        RECT  69.036 40.464 69.12 40.488 ;
    END
  END b_cfg_target[2]
  PIN b_cfg_target[3]
    DIRECTION OUTPUT ;
    USE SIGNAL ;
    PORT
      LAYER M4 ;
        RECT  69.036 40.56 69.12 40.584 ;
    END
  END b_cfg_target[3]
  PIN b_cfg_target[4]
    DIRECTION OUTPUT ;
    USE SIGNAL ;
    PORT
      LAYER M4 ;
        RECT  69.036 40.656 69.12 40.68 ;
    END
  END b_cfg_target[4]
  PIN b_cfg_target[5]
    DIRECTION OUTPUT ;
    USE SIGNAL ;
    PORT
      LAYER M4 ;
        RECT  69.036 40.752 69.12 40.776 ;
    END
  END b_cfg_target[5]
  PIN b_cfg_target[6]
    DIRECTION OUTPUT ;
    USE SIGNAL ;
    PORT
      LAYER M4 ;
        RECT  69.036 40.848 69.12 40.872 ;
    END
  END b_cfg_target[6]
  PIN b_cfg_target[7]
    DIRECTION OUTPUT ;
    USE SIGNAL ;
    PORT
      LAYER M4 ;
        RECT  69.036 40.944 69.12 40.968 ;
    END
  END b_cfg_target[7]
  PIN b_cfg_v
    DIRECTION OUTPUT ;
    USE SIGNAL ;
    PORT
      LAYER M4 ;
        RECT  69.036 41.04 69.12 41.064 ;
    END
  END b_cfg_v
  PIN b_desc_base[0]
    DIRECTION OUTPUT ;
    USE SIGNAL ;
    PORT
      LAYER M4 ;
        RECT  69.036 41.136 69.12 41.16 ;
    END
  END b_desc_base[0]
  PIN b_desc_base[10]
    DIRECTION OUTPUT ;
    USE SIGNAL ;
    PORT
      LAYER M4 ;
        RECT  69.036 42.096 69.12 42.12 ;
    END
  END b_desc_base[10]
  PIN b_desc_base[11]
    DIRECTION OUTPUT ;
    USE SIGNAL ;
    PORT
      LAYER M4 ;
        RECT  69.036 42.192 69.12 42.216 ;
    END
  END b_desc_base[11]
  PIN b_desc_base[1]
    DIRECTION OUTPUT ;
    USE SIGNAL ;
    PORT
      LAYER M4 ;
        RECT  69.036 41.232 69.12 41.256 ;
    END
  END b_desc_base[1]
  PIN b_desc_base[2]
    DIRECTION OUTPUT ;
    USE SIGNAL ;
    PORT
      LAYER M4 ;
        RECT  69.036 41.328 69.12 41.352 ;
    END
  END b_desc_base[2]
  PIN b_desc_base[3]
    DIRECTION OUTPUT ;
    USE SIGNAL ;
    PORT
      LAYER M4 ;
        RECT  69.036 41.424 69.12 41.448 ;
    END
  END b_desc_base[3]
  PIN b_desc_base[4]
    DIRECTION OUTPUT ;
    USE SIGNAL ;
    PORT
      LAYER M4 ;
        RECT  69.036 41.52 69.12 41.544 ;
    END
  END b_desc_base[4]
  PIN b_desc_base[5]
    DIRECTION OUTPUT ;
    USE SIGNAL ;
    PORT
      LAYER M4 ;
        RECT  69.036 41.616 69.12 41.64 ;
    END
  END b_desc_base[5]
  PIN b_desc_base[6]
    DIRECTION OUTPUT ;
    USE SIGNAL ;
    PORT
      LAYER M4 ;
        RECT  69.036 41.712 69.12 41.736 ;
    END
  END b_desc_base[6]
  PIN b_desc_base[7]
    DIRECTION OUTPUT ;
    USE SIGNAL ;
    PORT
      LAYER M4 ;
        RECT  69.036 41.808 69.12 41.832 ;
    END
  END b_desc_base[7]
  PIN b_desc_base[8]
    DIRECTION OUTPUT ;
    USE SIGNAL ;
    PORT
      LAYER M4 ;
        RECT  69.036 41.904 69.12 41.928 ;
    END
  END b_desc_base[8]
  PIN b_desc_base[9]
    DIRECTION OUTPUT ;
    USE SIGNAL ;
    PORT
      LAYER M4 ;
        RECT  69.036 42 69.12 42.024 ;
    END
  END b_desc_base[9]
  PIN b_desc_limit[0]
    DIRECTION OUTPUT ;
    USE SIGNAL ;
    PORT
      LAYER M4 ;
        RECT  69.036 42.288 69.12 42.312 ;
    END
  END b_desc_limit[0]
  PIN b_desc_limit[10]
    DIRECTION OUTPUT ;
    USE SIGNAL ;
    PORT
      LAYER M4 ;
        RECT  69.036 43.248 69.12 43.272 ;
    END
  END b_desc_limit[10]
  PIN b_desc_limit[11]
    DIRECTION OUTPUT ;
    USE SIGNAL ;
    PORT
      LAYER M4 ;
        RECT  69.036 43.344 69.12 43.368 ;
    END
  END b_desc_limit[11]
  PIN b_desc_limit[12]
    DIRECTION OUTPUT ;
    USE SIGNAL ;
    PORT
      LAYER M4 ;
        RECT  69.036 43.44 69.12 43.464 ;
    END
  END b_desc_limit[12]
  PIN b_desc_limit[1]
    DIRECTION OUTPUT ;
    USE SIGNAL ;
    PORT
      LAYER M4 ;
        RECT  69.036 42.384 69.12 42.408 ;
    END
  END b_desc_limit[1]
  PIN b_desc_limit[2]
    DIRECTION OUTPUT ;
    USE SIGNAL ;
    PORT
      LAYER M4 ;
        RECT  69.036 42.48 69.12 42.504 ;
    END
  END b_desc_limit[2]
  PIN b_desc_limit[3]
    DIRECTION OUTPUT ;
    USE SIGNAL ;
    PORT
      LAYER M4 ;
        RECT  69.036 42.576 69.12 42.6 ;
    END
  END b_desc_limit[3]
  PIN b_desc_limit[4]
    DIRECTION OUTPUT ;
    USE SIGNAL ;
    PORT
      LAYER M4 ;
        RECT  69.036 42.672 69.12 42.696 ;
    END
  END b_desc_limit[4]
  PIN b_desc_limit[5]
    DIRECTION OUTPUT ;
    USE SIGNAL ;
    PORT
      LAYER M4 ;
        RECT  69.036 42.768 69.12 42.792 ;
    END
  END b_desc_limit[5]
  PIN b_desc_limit[6]
    DIRECTION OUTPUT ;
    USE SIGNAL ;
    PORT
      LAYER M4 ;
        RECT  69.036 42.864 69.12 42.888 ;
    END
  END b_desc_limit[6]
  PIN b_desc_limit[7]
    DIRECTION OUTPUT ;
    USE SIGNAL ;
    PORT
      LAYER M4 ;
        RECT  69.036 42.96 69.12 42.984 ;
    END
  END b_desc_limit[7]
  PIN b_desc_limit[8]
    DIRECTION OUTPUT ;
    USE SIGNAL ;
    PORT
      LAYER M4 ;
        RECT  69.036 43.056 69.12 43.08 ;
    END
  END b_desc_limit[8]
  PIN b_desc_limit[9]
    DIRECTION OUTPUT ;
    USE SIGNAL ;
    PORT
      LAYER M4 ;
        RECT  69.036 43.152 69.12 43.176 ;
    END
  END b_desc_limit[9]
  PIN b_desc_loops[0]
    DIRECTION OUTPUT ;
    USE SIGNAL ;
    PORT
      LAYER M4 ;
        RECT  69.036 43.536 69.12 43.56 ;
    END
  END b_desc_loops[0]
  PIN b_desc_loops[10]
    DIRECTION OUTPUT ;
    USE SIGNAL ;
    PORT
      LAYER M4 ;
        RECT  69.036 44.496 69.12 44.52 ;
    END
  END b_desc_loops[10]
  PIN b_desc_loops[11]
    DIRECTION OUTPUT ;
    USE SIGNAL ;
    PORT
      LAYER M4 ;
        RECT  69.036 44.592 69.12 44.616 ;
    END
  END b_desc_loops[11]
  PIN b_desc_loops[12]
    DIRECTION OUTPUT ;
    USE SIGNAL ;
    PORT
      LAYER M4 ;
        RECT  69.036 44.688 69.12 44.712 ;
    END
  END b_desc_loops[12]
  PIN b_desc_loops[13]
    DIRECTION OUTPUT ;
    USE SIGNAL ;
    PORT
      LAYER M4 ;
        RECT  69.036 44.784 69.12 44.808 ;
    END
  END b_desc_loops[13]
  PIN b_desc_loops[14]
    DIRECTION OUTPUT ;
    USE SIGNAL ;
    PORT
      LAYER M4 ;
        RECT  69.036 44.88 69.12 44.904 ;
    END
  END b_desc_loops[14]
  PIN b_desc_loops[15]
    DIRECTION OUTPUT ;
    USE SIGNAL ;
    PORT
      LAYER M4 ;
        RECT  69.036 44.976 69.12 45 ;
    END
  END b_desc_loops[15]
  PIN b_desc_loops[1]
    DIRECTION OUTPUT ;
    USE SIGNAL ;
    PORT
      LAYER M4 ;
        RECT  69.036 43.632 69.12 43.656 ;
    END
  END b_desc_loops[1]
  PIN b_desc_loops[2]
    DIRECTION OUTPUT ;
    USE SIGNAL ;
    PORT
      LAYER M4 ;
        RECT  69.036 43.728 69.12 43.752 ;
    END
  END b_desc_loops[2]
  PIN b_desc_loops[3]
    DIRECTION OUTPUT ;
    USE SIGNAL ;
    PORT
      LAYER M4 ;
        RECT  69.036 43.824 69.12 43.848 ;
    END
  END b_desc_loops[3]
  PIN b_desc_loops[4]
    DIRECTION OUTPUT ;
    USE SIGNAL ;
    PORT
      LAYER M4 ;
        RECT  69.036 43.92 69.12 43.944 ;
    END
  END b_desc_loops[4]
  PIN b_desc_loops[5]
    DIRECTION OUTPUT ;
    USE SIGNAL ;
    PORT
      LAYER M4 ;
        RECT  69.036 44.016 69.12 44.04 ;
    END
  END b_desc_loops[5]
  PIN b_desc_loops[6]
    DIRECTION OUTPUT ;
    USE SIGNAL ;
    PORT
      LAYER M4 ;
        RECT  69.036 44.112 69.12 44.136 ;
    END
  END b_desc_loops[6]
  PIN b_desc_loops[7]
    DIRECTION OUTPUT ;
    USE SIGNAL ;
    PORT
      LAYER M4 ;
        RECT  69.036 44.208 69.12 44.232 ;
    END
  END b_desc_loops[7]
  PIN b_desc_loops[8]
    DIRECTION OUTPUT ;
    USE SIGNAL ;
    PORT
      LAYER M4 ;
        RECT  69.036 44.304 69.12 44.328 ;
    END
  END b_desc_loops[8]
  PIN b_desc_loops[9]
    DIRECTION OUTPUT ;
    USE SIGNAL ;
    PORT
      LAYER M4 ;
        RECT  69.036 44.4 69.12 44.424 ;
    END
  END b_desc_loops[9]
  PIN b_desc_v
    DIRECTION OUTPUT ;
    USE SIGNAL ;
    PORT
      LAYER M4 ;
        RECT  69.036 45.072 69.12 45.096 ;
    END
  END b_desc_v
  PIN b_launch_v
    DIRECTION OUTPUT ;
    USE SIGNAL ;
    PORT
      LAYER M4 ;
        RECT  69.036 45.168 69.12 45.192 ;
    END
  END b_launch_v
  PIN cfg_addr[0]
    DIRECTION INPUT ;
    USE SIGNAL ;
    PORT
      LAYER M5 ;
        RECT  36.912 69.036 36.936 69.12 ;
    END
  END cfg_addr[0]
  PIN cfg_addr[10]
    DIRECTION INPUT ;
    USE SIGNAL ;
    PORT
      LAYER M5 ;
        RECT  37.872 69.036 37.896 69.12 ;
    END
  END cfg_addr[10]
  PIN cfg_addr[11]
    DIRECTION INPUT ;
    USE SIGNAL ;
    PORT
      LAYER M5 ;
        RECT  37.968 69.036 37.992 69.12 ;
    END
  END cfg_addr[11]
  PIN cfg_addr[1]
    DIRECTION INPUT ;
    USE SIGNAL ;
    PORT
      LAYER M5 ;
        RECT  37.008 69.036 37.032 69.12 ;
    END
  END cfg_addr[1]
  PIN cfg_addr[2]
    DIRECTION INPUT ;
    USE SIGNAL ;
    PORT
      LAYER M5 ;
        RECT  37.104 69.036 37.128 69.12 ;
    END
  END cfg_addr[2]
  PIN cfg_addr[3]
    DIRECTION INPUT ;
    USE SIGNAL ;
    PORT
      LAYER M5 ;
        RECT  37.2 69.036 37.224 69.12 ;
    END
  END cfg_addr[3]
  PIN cfg_addr[4]
    DIRECTION INPUT ;
    USE SIGNAL ;
    PORT
      LAYER M5 ;
        RECT  37.296 69.036 37.32 69.12 ;
    END
  END cfg_addr[4]
  PIN cfg_addr[5]
    DIRECTION INPUT ;
    USE SIGNAL ;
    PORT
      LAYER M5 ;
        RECT  37.392 69.036 37.416 69.12 ;
    END
  END cfg_addr[5]
  PIN cfg_addr[6]
    DIRECTION INPUT ;
    USE SIGNAL ;
    PORT
      LAYER M5 ;
        RECT  37.488 69.036 37.512 69.12 ;
    END
  END cfg_addr[6]
  PIN cfg_addr[7]
    DIRECTION INPUT ;
    USE SIGNAL ;
    PORT
      LAYER M5 ;
        RECT  37.584 69.036 37.608 69.12 ;
    END
  END cfg_addr[7]
  PIN cfg_addr[8]
    DIRECTION INPUT ;
    USE SIGNAL ;
    PORT
      LAYER M5 ;
        RECT  37.68 69.036 37.704 69.12 ;
    END
  END cfg_addr[8]
  PIN cfg_addr[9]
    DIRECTION INPUT ;
    USE SIGNAL ;
    PORT
      LAYER M5 ;
        RECT  37.776 69.036 37.8 69.12 ;
    END
  END cfg_addr[9]
  PIN cfg_data[0]
    DIRECTION INPUT ;
    USE SIGNAL ;
    PORT
      LAYER M5 ;
        RECT  38.064 69.036 38.088 69.12 ;
    END
  END cfg_data[0]
  PIN cfg_data[100]
    DIRECTION INPUT ;
    USE SIGNAL ;
    PORT
      LAYER M5 ;
        RECT  41.52 69.036 41.544 69.12 ;
    END
  END cfg_data[100]
  PIN cfg_data[101]
    DIRECTION INPUT ;
    USE SIGNAL ;
    PORT
      LAYER M5 ;
        RECT  41.616 69.036 41.64 69.12 ;
    END
  END cfg_data[101]
  PIN cfg_data[102]
    DIRECTION INPUT ;
    USE SIGNAL ;
    PORT
      LAYER M5 ;
        RECT  41.712 69.036 41.736 69.12 ;
    END
  END cfg_data[102]
  PIN cfg_data[103]
    DIRECTION INPUT ;
    USE SIGNAL ;
    PORT
      LAYER M5 ;
        RECT  41.808 69.036 41.832 69.12 ;
    END
  END cfg_data[103]
  PIN cfg_data[104]
    DIRECTION INPUT ;
    USE SIGNAL ;
    PORT
      LAYER M5 ;
        RECT  41.904 69.036 41.928 69.12 ;
    END
  END cfg_data[104]
  PIN cfg_data[105]
    DIRECTION INPUT ;
    USE SIGNAL ;
    PORT
      LAYER M5 ;
        RECT  42 69.036 42.024 69.12 ;
    END
  END cfg_data[105]
  PIN cfg_data[106]
    DIRECTION INPUT ;
    USE SIGNAL ;
    PORT
      LAYER M5 ;
        RECT  42.096 69.036 42.12 69.12 ;
    END
  END cfg_data[106]
  PIN cfg_data[107]
    DIRECTION INPUT ;
    USE SIGNAL ;
    PORT
      LAYER M5 ;
        RECT  42.192 69.036 42.216 69.12 ;
    END
  END cfg_data[107]
  PIN cfg_data[108]
    DIRECTION INPUT ;
    USE SIGNAL ;
    PORT
      LAYER M5 ;
        RECT  42.288 69.036 42.312 69.12 ;
    END
  END cfg_data[108]
  PIN cfg_data[109]
    DIRECTION INPUT ;
    USE SIGNAL ;
    PORT
      LAYER M5 ;
        RECT  42.384 69.036 42.408 69.12 ;
    END
  END cfg_data[109]
  PIN cfg_data[10]
    DIRECTION INPUT ;
    USE SIGNAL ;
    PORT
      LAYER M5 ;
        RECT  39.024 69.036 39.048 69.12 ;
    END
  END cfg_data[10]
  PIN cfg_data[110]
    DIRECTION INPUT ;
    USE SIGNAL ;
    PORT
      LAYER M5 ;
        RECT  42.48 69.036 42.504 69.12 ;
    END
  END cfg_data[110]
  PIN cfg_data[111]
    DIRECTION INPUT ;
    USE SIGNAL ;
    PORT
      LAYER M5 ;
        RECT  42.576 69.036 42.6 69.12 ;
    END
  END cfg_data[111]
  PIN cfg_data[112]
    DIRECTION INPUT ;
    USE SIGNAL ;
    PORT
      LAYER M5 ;
        RECT  42.672 69.036 42.696 69.12 ;
    END
  END cfg_data[112]
  PIN cfg_data[113]
    DIRECTION INPUT ;
    USE SIGNAL ;
    PORT
      LAYER M5 ;
        RECT  42.768 69.036 42.792 69.12 ;
    END
  END cfg_data[113]
  PIN cfg_data[114]
    DIRECTION INPUT ;
    USE SIGNAL ;
    PORT
      LAYER M5 ;
        RECT  42.864 69.036 42.888 69.12 ;
    END
  END cfg_data[114]
  PIN cfg_data[115]
    DIRECTION INPUT ;
    USE SIGNAL ;
    PORT
      LAYER M5 ;
        RECT  42.96 69.036 42.984 69.12 ;
    END
  END cfg_data[115]
  PIN cfg_data[116]
    DIRECTION INPUT ;
    USE SIGNAL ;
    PORT
      LAYER M5 ;
        RECT  33.84 69.036 33.864 69.12 ;
    END
  END cfg_data[116]
  PIN cfg_data[117]
    DIRECTION INPUT ;
    USE SIGNAL ;
    PORT
      LAYER M5 ;
        RECT  33.936 69.036 33.96 69.12 ;
    END
  END cfg_data[117]
  PIN cfg_data[118]
    DIRECTION INPUT ;
    USE SIGNAL ;
    PORT
      LAYER M5 ;
        RECT  34.032 69.036 34.056 69.12 ;
    END
  END cfg_data[118]
  PIN cfg_data[119]
    DIRECTION INPUT ;
    USE SIGNAL ;
    PORT
      LAYER M5 ;
        RECT  34.128 69.036 34.152 69.12 ;
    END
  END cfg_data[119]
  PIN cfg_data[11]
    DIRECTION INPUT ;
    USE SIGNAL ;
    PORT
      LAYER M5 ;
        RECT  39.12 69.036 39.144 69.12 ;
    END
  END cfg_data[11]
  PIN cfg_data[120]
    DIRECTION INPUT ;
    USE SIGNAL ;
    PORT
      LAYER M5 ;
        RECT  34.224 69.036 34.248 69.12 ;
    END
  END cfg_data[120]
  PIN cfg_data[121]
    DIRECTION INPUT ;
    USE SIGNAL ;
    PORT
      LAYER M5 ;
        RECT  34.32 69.036 34.344 69.12 ;
    END
  END cfg_data[121]
  PIN cfg_data[122]
    DIRECTION INPUT ;
    USE SIGNAL ;
    PORT
      LAYER M5 ;
        RECT  34.416 69.036 34.44 69.12 ;
    END
  END cfg_data[122]
  PIN cfg_data[123]
    DIRECTION INPUT ;
    USE SIGNAL ;
    PORT
      LAYER M5 ;
        RECT  34.512 69.036 34.536 69.12 ;
    END
  END cfg_data[123]
  PIN cfg_data[124]
    DIRECTION INPUT ;
    USE SIGNAL ;
    PORT
      LAYER M5 ;
        RECT  34.608 69.036 34.632 69.12 ;
    END
  END cfg_data[124]
  PIN cfg_data[125]
    DIRECTION INPUT ;
    USE SIGNAL ;
    PORT
      LAYER M5 ;
        RECT  34.704 69.036 34.728 69.12 ;
    END
  END cfg_data[125]
  PIN cfg_data[126]
    DIRECTION INPUT ;
    USE SIGNAL ;
    PORT
      LAYER M5 ;
        RECT  34.8 69.036 34.824 69.12 ;
    END
  END cfg_data[126]
  PIN cfg_data[127]
    DIRECTION INPUT ;
    USE SIGNAL ;
    PORT
      LAYER M5 ;
        RECT  34.896 69.036 34.92 69.12 ;
    END
  END cfg_data[127]
  PIN cfg_data[128]
    DIRECTION INPUT ;
    USE SIGNAL ;
    PORT
      LAYER M5 ;
        RECT  34.992 69.036 35.016 69.12 ;
    END
  END cfg_data[128]
  PIN cfg_data[129]
    DIRECTION INPUT ;
    USE SIGNAL ;
    PORT
      LAYER M5 ;
        RECT  35.088 69.036 35.112 69.12 ;
    END
  END cfg_data[129]
  PIN cfg_data[12]
    DIRECTION INPUT ;
    USE SIGNAL ;
    PORT
      LAYER M5 ;
        RECT  39.216 69.036 39.24 69.12 ;
    END
  END cfg_data[12]
  PIN cfg_data[130]
    DIRECTION INPUT ;
    USE SIGNAL ;
    PORT
      LAYER M5 ;
        RECT  35.184 69.036 35.208 69.12 ;
    END
  END cfg_data[130]
  PIN cfg_data[131]
    DIRECTION INPUT ;
    USE SIGNAL ;
    PORT
      LAYER M5 ;
        RECT  35.28 69.036 35.304 69.12 ;
    END
  END cfg_data[131]
  PIN cfg_data[132]
    DIRECTION INPUT ;
    USE SIGNAL ;
    PORT
      LAYER M5 ;
        RECT  35.376 69.036 35.4 69.12 ;
    END
  END cfg_data[132]
  PIN cfg_data[133]
    DIRECTION INPUT ;
    USE SIGNAL ;
    PORT
      LAYER M5 ;
        RECT  35.472 69.036 35.496 69.12 ;
    END
  END cfg_data[133]
  PIN cfg_data[134]
    DIRECTION INPUT ;
    USE SIGNAL ;
    PORT
      LAYER M5 ;
        RECT  35.568 69.036 35.592 69.12 ;
    END
  END cfg_data[134]
  PIN cfg_data[135]
    DIRECTION INPUT ;
    USE SIGNAL ;
    PORT
      LAYER M5 ;
        RECT  35.664 69.036 35.688 69.12 ;
    END
  END cfg_data[135]
  PIN cfg_data[136]
    DIRECTION INPUT ;
    USE SIGNAL ;
    PORT
      LAYER M5 ;
        RECT  35.76 69.036 35.784 69.12 ;
    END
  END cfg_data[136]
  PIN cfg_data[137]
    DIRECTION INPUT ;
    USE SIGNAL ;
    PORT
      LAYER M5 ;
        RECT  35.856 69.036 35.88 69.12 ;
    END
  END cfg_data[137]
  PIN cfg_data[138]
    DIRECTION INPUT ;
    USE SIGNAL ;
    PORT
      LAYER M5 ;
        RECT  35.952 69.036 35.976 69.12 ;
    END
  END cfg_data[138]
  PIN cfg_data[139]
    DIRECTION INPUT ;
    USE SIGNAL ;
    PORT
      LAYER M5 ;
        RECT  36.048 69.036 36.072 69.12 ;
    END
  END cfg_data[139]
  PIN cfg_data[13]
    DIRECTION INPUT ;
    USE SIGNAL ;
    PORT
      LAYER M5 ;
        RECT  39.312 69.036 39.336 69.12 ;
    END
  END cfg_data[13]
  PIN cfg_data[140]
    DIRECTION INPUT ;
    USE SIGNAL ;
    PORT
      LAYER M5 ;
        RECT  36.144 69.036 36.168 69.12 ;
    END
  END cfg_data[140]
  PIN cfg_data[141]
    DIRECTION INPUT ;
    USE SIGNAL ;
    PORT
      LAYER M5 ;
        RECT  36.24 69.036 36.264 69.12 ;
    END
  END cfg_data[141]
  PIN cfg_data[142]
    DIRECTION INPUT ;
    USE SIGNAL ;
    PORT
      LAYER M5 ;
        RECT  36.336 69.036 36.36 69.12 ;
    END
  END cfg_data[142]
  PIN cfg_data[143]
    DIRECTION INPUT ;
    USE SIGNAL ;
    PORT
      LAYER M5 ;
        RECT  36.432 69.036 36.456 69.12 ;
    END
  END cfg_data[143]
  PIN cfg_data[144]
    DIRECTION INPUT ;
    USE SIGNAL ;
    PORT
      LAYER M5 ;
        RECT  36.528 69.036 36.552 69.12 ;
    END
  END cfg_data[144]
  PIN cfg_data[145]
    DIRECTION INPUT ;
    USE SIGNAL ;
    PORT
      LAYER M5 ;
        RECT  36.624 69.036 36.648 69.12 ;
    END
  END cfg_data[145]
  PIN cfg_data[146]
    DIRECTION INPUT ;
    USE SIGNAL ;
    PORT
      LAYER M5 ;
        RECT  36.72 69.036 36.744 69.12 ;
    END
  END cfg_data[146]
  PIN cfg_data[147]
    DIRECTION INPUT ;
    USE SIGNAL ;
    PORT
      LAYER M5 ;
        RECT  36.816 69.036 36.84 69.12 ;
    END
  END cfg_data[147]
  PIN cfg_data[148]
    DIRECTION INPUT ;
    USE SIGNAL ;
    PORT
      LAYER M5 ;
        RECT  43.056 69.036 43.08 69.12 ;
    END
  END cfg_data[148]
  PIN cfg_data[149]
    DIRECTION INPUT ;
    USE SIGNAL ;
    PORT
      LAYER M5 ;
        RECT  43.152 69.036 43.176 69.12 ;
    END
  END cfg_data[149]
  PIN cfg_data[14]
    DIRECTION INPUT ;
    USE SIGNAL ;
    PORT
      LAYER M5 ;
        RECT  39.408 69.036 39.432 69.12 ;
    END
  END cfg_data[14]
  PIN cfg_data[150]
    DIRECTION INPUT ;
    USE SIGNAL ;
    PORT
      LAYER M5 ;
        RECT  43.248 69.036 43.272 69.12 ;
    END
  END cfg_data[150]
  PIN cfg_data[151]
    DIRECTION INPUT ;
    USE SIGNAL ;
    PORT
      LAYER M5 ;
        RECT  43.344 69.036 43.368 69.12 ;
    END
  END cfg_data[151]
  PIN cfg_data[152]
    DIRECTION INPUT ;
    USE SIGNAL ;
    PORT
      LAYER M5 ;
        RECT  43.44 69.036 43.464 69.12 ;
    END
  END cfg_data[152]
  PIN cfg_data[153]
    DIRECTION INPUT ;
    USE SIGNAL ;
    PORT
      LAYER M5 ;
        RECT  43.536 69.036 43.56 69.12 ;
    END
  END cfg_data[153]
  PIN cfg_data[154]
    DIRECTION INPUT ;
    USE SIGNAL ;
    PORT
      LAYER M5 ;
        RECT  43.632 69.036 43.656 69.12 ;
    END
  END cfg_data[154]
  PIN cfg_data[155]
    DIRECTION INPUT ;
    USE SIGNAL ;
    PORT
      LAYER M5 ;
        RECT  43.728 69.036 43.752 69.12 ;
    END
  END cfg_data[155]
  PIN cfg_data[156]
    DIRECTION INPUT ;
    USE SIGNAL ;
    PORT
      LAYER M5 ;
        RECT  43.824 69.036 43.848 69.12 ;
    END
  END cfg_data[156]
  PIN cfg_data[157]
    DIRECTION INPUT ;
    USE SIGNAL ;
    PORT
      LAYER M5 ;
        RECT  43.92 69.036 43.944 69.12 ;
    END
  END cfg_data[157]
  PIN cfg_data[158]
    DIRECTION INPUT ;
    USE SIGNAL ;
    PORT
      LAYER M5 ;
        RECT  44.016 69.036 44.04 69.12 ;
    END
  END cfg_data[158]
  PIN cfg_data[159]
    DIRECTION INPUT ;
    USE SIGNAL ;
    PORT
      LAYER M5 ;
        RECT  44.112 69.036 44.136 69.12 ;
    END
  END cfg_data[159]
  PIN cfg_data[15]
    DIRECTION INPUT ;
    USE SIGNAL ;
    PORT
      LAYER M5 ;
        RECT  39.504 69.036 39.528 69.12 ;
    END
  END cfg_data[15]
  PIN cfg_data[160]
    DIRECTION INPUT ;
    USE SIGNAL ;
    PORT
      LAYER M5 ;
        RECT  44.208 69.036 44.232 69.12 ;
    END
  END cfg_data[160]
  PIN cfg_data[161]
    DIRECTION INPUT ;
    USE SIGNAL ;
    PORT
      LAYER M5 ;
        RECT  44.304 69.036 44.328 69.12 ;
    END
  END cfg_data[161]
  PIN cfg_data[162]
    DIRECTION INPUT ;
    USE SIGNAL ;
    PORT
      LAYER M5 ;
        RECT  44.4 69.036 44.424 69.12 ;
    END
  END cfg_data[162]
  PIN cfg_data[163]
    DIRECTION INPUT ;
    USE SIGNAL ;
    PORT
      LAYER M5 ;
        RECT  44.496 69.036 44.52 69.12 ;
    END
  END cfg_data[163]
  PIN cfg_data[164]
    DIRECTION INPUT ;
    USE SIGNAL ;
    PORT
      LAYER M5 ;
        RECT  44.592 69.036 44.616 69.12 ;
    END
  END cfg_data[164]
  PIN cfg_data[165]
    DIRECTION INPUT ;
    USE SIGNAL ;
    PORT
      LAYER M5 ;
        RECT  44.688 69.036 44.712 69.12 ;
    END
  END cfg_data[165]
  PIN cfg_data[166]
    DIRECTION INPUT ;
    USE SIGNAL ;
    PORT
      LAYER M5 ;
        RECT  44.784 69.036 44.808 69.12 ;
    END
  END cfg_data[166]
  PIN cfg_data[167]
    DIRECTION INPUT ;
    USE SIGNAL ;
    PORT
      LAYER M5 ;
        RECT  44.88 69.036 44.904 69.12 ;
    END
  END cfg_data[167]
  PIN cfg_data[168]
    DIRECTION INPUT ;
    USE SIGNAL ;
    PORT
      LAYER M5 ;
        RECT  44.976 69.036 45 69.12 ;
    END
  END cfg_data[168]
  PIN cfg_data[169]
    DIRECTION INPUT ;
    USE SIGNAL ;
    PORT
      LAYER M5 ;
        RECT  45.072 69.036 45.096 69.12 ;
    END
  END cfg_data[169]
  PIN cfg_data[16]
    DIRECTION INPUT ;
    USE SIGNAL ;
    PORT
      LAYER M5 ;
        RECT  39.6 69.036 39.624 69.12 ;
    END
  END cfg_data[16]
  PIN cfg_data[170]
    DIRECTION INPUT ;
    USE SIGNAL ;
    PORT
      LAYER M5 ;
        RECT  45.168 69.036 45.192 69.12 ;
    END
  END cfg_data[170]
  PIN cfg_data[171]
    DIRECTION INPUT ;
    USE SIGNAL ;
    PORT
      LAYER M5 ;
        RECT  45.264 69.036 45.288 69.12 ;
    END
  END cfg_data[171]
  PIN cfg_data[172]
    DIRECTION INPUT ;
    USE SIGNAL ;
    PORT
      LAYER M5 ;
        RECT  45.36 69.036 45.384 69.12 ;
    END
  END cfg_data[172]
  PIN cfg_data[173]
    DIRECTION INPUT ;
    USE SIGNAL ;
    PORT
      LAYER M5 ;
        RECT  45.456 69.036 45.48 69.12 ;
    END
  END cfg_data[173]
  PIN cfg_data[174]
    DIRECTION INPUT ;
    USE SIGNAL ;
    PORT
      LAYER M5 ;
        RECT  45.552 69.036 45.576 69.12 ;
    END
  END cfg_data[174]
  PIN cfg_data[175]
    DIRECTION INPUT ;
    USE SIGNAL ;
    PORT
      LAYER M5 ;
        RECT  45.648 69.036 45.672 69.12 ;
    END
  END cfg_data[175]
  PIN cfg_data[176]
    DIRECTION INPUT ;
    USE SIGNAL ;
    PORT
      LAYER M5 ;
        RECT  45.744 69.036 45.768 69.12 ;
    END
  END cfg_data[176]
  PIN cfg_data[177]
    DIRECTION INPUT ;
    USE SIGNAL ;
    PORT
      LAYER M5 ;
        RECT  45.84 69.036 45.864 69.12 ;
    END
  END cfg_data[177]
  PIN cfg_data[178]
    DIRECTION INPUT ;
    USE SIGNAL ;
    PORT
      LAYER M5 ;
        RECT  45.936 69.036 45.96 69.12 ;
    END
  END cfg_data[178]
  PIN cfg_data[179]
    DIRECTION INPUT ;
    USE SIGNAL ;
    PORT
      LAYER M5 ;
        RECT  46.032 69.036 46.056 69.12 ;
    END
  END cfg_data[179]
  PIN cfg_data[17]
    DIRECTION INPUT ;
    USE SIGNAL ;
    PORT
      LAYER M5 ;
        RECT  39.696 69.036 39.72 69.12 ;
    END
  END cfg_data[17]
  PIN cfg_data[180]
    DIRECTION INPUT ;
    USE SIGNAL ;
    PORT
      LAYER M5 ;
        RECT  23.856 69.036 23.88 69.12 ;
    END
  END cfg_data[180]
  PIN cfg_data[181]
    DIRECTION INPUT ;
    USE SIGNAL ;
    PORT
      LAYER M5 ;
        RECT  23.952 69.036 23.976 69.12 ;
    END
  END cfg_data[181]
  PIN cfg_data[182]
    DIRECTION INPUT ;
    USE SIGNAL ;
    PORT
      LAYER M5 ;
        RECT  24.048 69.036 24.072 69.12 ;
    END
  END cfg_data[182]
  PIN cfg_data[183]
    DIRECTION INPUT ;
    USE SIGNAL ;
    PORT
      LAYER M5 ;
        RECT  24.144 69.036 24.168 69.12 ;
    END
  END cfg_data[183]
  PIN cfg_data[184]
    DIRECTION INPUT ;
    USE SIGNAL ;
    PORT
      LAYER M5 ;
        RECT  24.24 69.036 24.264 69.12 ;
    END
  END cfg_data[184]
  PIN cfg_data[185]
    DIRECTION INPUT ;
    USE SIGNAL ;
    PORT
      LAYER M5 ;
        RECT  24.336 69.036 24.36 69.12 ;
    END
  END cfg_data[185]
  PIN cfg_data[186]
    DIRECTION INPUT ;
    USE SIGNAL ;
    PORT
      LAYER M5 ;
        RECT  24.432 69.036 24.456 69.12 ;
    END
  END cfg_data[186]
  PIN cfg_data[187]
    DIRECTION INPUT ;
    USE SIGNAL ;
    PORT
      LAYER M5 ;
        RECT  24.528 69.036 24.552 69.12 ;
    END
  END cfg_data[187]
  PIN cfg_data[188]
    DIRECTION INPUT ;
    USE SIGNAL ;
    PORT
      LAYER M5 ;
        RECT  24.624 69.036 24.648 69.12 ;
    END
  END cfg_data[188]
  PIN cfg_data[189]
    DIRECTION INPUT ;
    USE SIGNAL ;
    PORT
      LAYER M5 ;
        RECT  24.72 69.036 24.744 69.12 ;
    END
  END cfg_data[189]
  PIN cfg_data[18]
    DIRECTION INPUT ;
    USE SIGNAL ;
    PORT
      LAYER M5 ;
        RECT  39.792 69.036 39.816 69.12 ;
    END
  END cfg_data[18]
  PIN cfg_data[190]
    DIRECTION INPUT ;
    USE SIGNAL ;
    PORT
      LAYER M5 ;
        RECT  24.816 69.036 24.84 69.12 ;
    END
  END cfg_data[190]
  PIN cfg_data[191]
    DIRECTION INPUT ;
    USE SIGNAL ;
    PORT
      LAYER M5 ;
        RECT  24.912 69.036 24.936 69.12 ;
    END
  END cfg_data[191]
  PIN cfg_data[192]
    DIRECTION INPUT ;
    USE SIGNAL ;
    PORT
      LAYER M5 ;
        RECT  25.008 69.036 25.032 69.12 ;
    END
  END cfg_data[192]
  PIN cfg_data[193]
    DIRECTION INPUT ;
    USE SIGNAL ;
    PORT
      LAYER M5 ;
        RECT  25.104 69.036 25.128 69.12 ;
    END
  END cfg_data[193]
  PIN cfg_data[194]
    DIRECTION INPUT ;
    USE SIGNAL ;
    PORT
      LAYER M5 ;
        RECT  25.2 69.036 25.224 69.12 ;
    END
  END cfg_data[194]
  PIN cfg_data[195]
    DIRECTION INPUT ;
    USE SIGNAL ;
    PORT
      LAYER M5 ;
        RECT  25.296 69.036 25.32 69.12 ;
    END
  END cfg_data[195]
  PIN cfg_data[196]
    DIRECTION INPUT ;
    USE SIGNAL ;
    PORT
      LAYER M5 ;
        RECT  25.392 69.036 25.416 69.12 ;
    END
  END cfg_data[196]
  PIN cfg_data[197]
    DIRECTION INPUT ;
    USE SIGNAL ;
    PORT
      LAYER M5 ;
        RECT  25.488 69.036 25.512 69.12 ;
    END
  END cfg_data[197]
  PIN cfg_data[198]
    DIRECTION INPUT ;
    USE SIGNAL ;
    PORT
      LAYER M5 ;
        RECT  25.584 69.036 25.608 69.12 ;
    END
  END cfg_data[198]
  PIN cfg_data[199]
    DIRECTION INPUT ;
    USE SIGNAL ;
    PORT
      LAYER M5 ;
        RECT  25.68 69.036 25.704 69.12 ;
    END
  END cfg_data[199]
  PIN cfg_data[19]
    DIRECTION INPUT ;
    USE SIGNAL ;
    PORT
      LAYER M5 ;
        RECT  39.888 69.036 39.912 69.12 ;
    END
  END cfg_data[19]
  PIN cfg_data[1]
    DIRECTION INPUT ;
    USE SIGNAL ;
    PORT
      LAYER M5 ;
        RECT  38.16 69.036 38.184 69.12 ;
    END
  END cfg_data[1]
  PIN cfg_data[200]
    DIRECTION INPUT ;
    USE SIGNAL ;
    PORT
      LAYER M5 ;
        RECT  25.776 69.036 25.8 69.12 ;
    END
  END cfg_data[200]
  PIN cfg_data[201]
    DIRECTION INPUT ;
    USE SIGNAL ;
    PORT
      LAYER M5 ;
        RECT  25.872 69.036 25.896 69.12 ;
    END
  END cfg_data[201]
  PIN cfg_data[202]
    DIRECTION INPUT ;
    USE SIGNAL ;
    PORT
      LAYER M5 ;
        RECT  25.968 69.036 25.992 69.12 ;
    END
  END cfg_data[202]
  PIN cfg_data[203]
    DIRECTION INPUT ;
    USE SIGNAL ;
    PORT
      LAYER M5 ;
        RECT  26.064 69.036 26.088 69.12 ;
    END
  END cfg_data[203]
  PIN cfg_data[204]
    DIRECTION INPUT ;
    USE SIGNAL ;
    PORT
      LAYER M5 ;
        RECT  26.16 69.036 26.184 69.12 ;
    END
  END cfg_data[204]
  PIN cfg_data[205]
    DIRECTION INPUT ;
    USE SIGNAL ;
    PORT
      LAYER M5 ;
        RECT  26.256 69.036 26.28 69.12 ;
    END
  END cfg_data[205]
  PIN cfg_data[206]
    DIRECTION INPUT ;
    USE SIGNAL ;
    PORT
      LAYER M5 ;
        RECT  26.352 69.036 26.376 69.12 ;
    END
  END cfg_data[206]
  PIN cfg_data[207]
    DIRECTION INPUT ;
    USE SIGNAL ;
    PORT
      LAYER M5 ;
        RECT  26.448 69.036 26.472 69.12 ;
    END
  END cfg_data[207]
  PIN cfg_data[208]
    DIRECTION INPUT ;
    USE SIGNAL ;
    PORT
      LAYER M5 ;
        RECT  26.544 69.036 26.568 69.12 ;
    END
  END cfg_data[208]
  PIN cfg_data[209]
    DIRECTION INPUT ;
    USE SIGNAL ;
    PORT
      LAYER M5 ;
        RECT  26.64 69.036 26.664 69.12 ;
    END
  END cfg_data[209]
  PIN cfg_data[20]
    DIRECTION INPUT ;
    USE SIGNAL ;
    PORT
      LAYER M5 ;
        RECT  30.768 69.036 30.792 69.12 ;
    END
  END cfg_data[20]
  PIN cfg_data[210]
    DIRECTION INPUT ;
    USE SIGNAL ;
    PORT
      LAYER M5 ;
        RECT  26.736 69.036 26.76 69.12 ;
    END
  END cfg_data[210]
  PIN cfg_data[211]
    DIRECTION INPUT ;
    USE SIGNAL ;
    PORT
      LAYER M5 ;
        RECT  26.832 69.036 26.856 69.12 ;
    END
  END cfg_data[211]
  PIN cfg_data[212]
    DIRECTION INPUT ;
    USE SIGNAL ;
    PORT
      LAYER M5 ;
        RECT  17.712 69.036 17.736 69.12 ;
    END
  END cfg_data[212]
  PIN cfg_data[213]
    DIRECTION INPUT ;
    USE SIGNAL ;
    PORT
      LAYER M5 ;
        RECT  17.808 69.036 17.832 69.12 ;
    END
  END cfg_data[213]
  PIN cfg_data[214]
    DIRECTION INPUT ;
    USE SIGNAL ;
    PORT
      LAYER M5 ;
        RECT  17.904 69.036 17.928 69.12 ;
    END
  END cfg_data[214]
  PIN cfg_data[215]
    DIRECTION INPUT ;
    USE SIGNAL ;
    PORT
      LAYER M5 ;
        RECT  18 69.036 18.024 69.12 ;
    END
  END cfg_data[215]
  PIN cfg_data[216]
    DIRECTION INPUT ;
    USE SIGNAL ;
    PORT
      LAYER M5 ;
        RECT  18.096 69.036 18.12 69.12 ;
    END
  END cfg_data[216]
  PIN cfg_data[217]
    DIRECTION INPUT ;
    USE SIGNAL ;
    PORT
      LAYER M5 ;
        RECT  18.192 69.036 18.216 69.12 ;
    END
  END cfg_data[217]
  PIN cfg_data[218]
    DIRECTION INPUT ;
    USE SIGNAL ;
    PORT
      LAYER M5 ;
        RECT  18.288 69.036 18.312 69.12 ;
    END
  END cfg_data[218]
  PIN cfg_data[219]
    DIRECTION INPUT ;
    USE SIGNAL ;
    PORT
      LAYER M5 ;
        RECT  18.384 69.036 18.408 69.12 ;
    END
  END cfg_data[219]
  PIN cfg_data[21]
    DIRECTION INPUT ;
    USE SIGNAL ;
    PORT
      LAYER M5 ;
        RECT  30.864 69.036 30.888 69.12 ;
    END
  END cfg_data[21]
  PIN cfg_data[220]
    DIRECTION INPUT ;
    USE SIGNAL ;
    PORT
      LAYER M5 ;
        RECT  18.48 69.036 18.504 69.12 ;
    END
  END cfg_data[220]
  PIN cfg_data[221]
    DIRECTION INPUT ;
    USE SIGNAL ;
    PORT
      LAYER M5 ;
        RECT  18.576 69.036 18.6 69.12 ;
    END
  END cfg_data[221]
  PIN cfg_data[222]
    DIRECTION INPUT ;
    USE SIGNAL ;
    PORT
      LAYER M5 ;
        RECT  18.672 69.036 18.696 69.12 ;
    END
  END cfg_data[222]
  PIN cfg_data[223]
    DIRECTION INPUT ;
    USE SIGNAL ;
    PORT
      LAYER M5 ;
        RECT  18.768 69.036 18.792 69.12 ;
    END
  END cfg_data[223]
  PIN cfg_data[224]
    DIRECTION INPUT ;
    USE SIGNAL ;
    PORT
      LAYER M5 ;
        RECT  18.864 69.036 18.888 69.12 ;
    END
  END cfg_data[224]
  PIN cfg_data[225]
    DIRECTION INPUT ;
    USE SIGNAL ;
    PORT
      LAYER M5 ;
        RECT  18.96 69.036 18.984 69.12 ;
    END
  END cfg_data[225]
  PIN cfg_data[226]
    DIRECTION INPUT ;
    USE SIGNAL ;
    PORT
      LAYER M5 ;
        RECT  19.056 69.036 19.08 69.12 ;
    END
  END cfg_data[226]
  PIN cfg_data[227]
    DIRECTION INPUT ;
    USE SIGNAL ;
    PORT
      LAYER M5 ;
        RECT  19.152 69.036 19.176 69.12 ;
    END
  END cfg_data[227]
  PIN cfg_data[228]
    DIRECTION INPUT ;
    USE SIGNAL ;
    PORT
      LAYER M5 ;
        RECT  19.248 69.036 19.272 69.12 ;
    END
  END cfg_data[228]
  PIN cfg_data[229]
    DIRECTION INPUT ;
    USE SIGNAL ;
    PORT
      LAYER M5 ;
        RECT  19.344 69.036 19.368 69.12 ;
    END
  END cfg_data[229]
  PIN cfg_data[22]
    DIRECTION INPUT ;
    USE SIGNAL ;
    PORT
      LAYER M5 ;
        RECT  30.96 69.036 30.984 69.12 ;
    END
  END cfg_data[22]
  PIN cfg_data[230]
    DIRECTION INPUT ;
    USE SIGNAL ;
    PORT
      LAYER M5 ;
        RECT  19.44 69.036 19.464 69.12 ;
    END
  END cfg_data[230]
  PIN cfg_data[231]
    DIRECTION INPUT ;
    USE SIGNAL ;
    PORT
      LAYER M5 ;
        RECT  19.536 69.036 19.56 69.12 ;
    END
  END cfg_data[231]
  PIN cfg_data[232]
    DIRECTION INPUT ;
    USE SIGNAL ;
    PORT
      LAYER M5 ;
        RECT  19.632 69.036 19.656 69.12 ;
    END
  END cfg_data[232]
  PIN cfg_data[233]
    DIRECTION INPUT ;
    USE SIGNAL ;
    PORT
      LAYER M5 ;
        RECT  19.728 69.036 19.752 69.12 ;
    END
  END cfg_data[233]
  PIN cfg_data[234]
    DIRECTION INPUT ;
    USE SIGNAL ;
    PORT
      LAYER M5 ;
        RECT  19.824 69.036 19.848 69.12 ;
    END
  END cfg_data[234]
  PIN cfg_data[235]
    DIRECTION INPUT ;
    USE SIGNAL ;
    PORT
      LAYER M5 ;
        RECT  19.92 69.036 19.944 69.12 ;
    END
  END cfg_data[235]
  PIN cfg_data[236]
    DIRECTION INPUT ;
    USE SIGNAL ;
    PORT
      LAYER M5 ;
        RECT  20.016 69.036 20.04 69.12 ;
    END
  END cfg_data[236]
  PIN cfg_data[237]
    DIRECTION INPUT ;
    USE SIGNAL ;
    PORT
      LAYER M5 ;
        RECT  20.112 69.036 20.136 69.12 ;
    END
  END cfg_data[237]
  PIN cfg_data[238]
    DIRECTION INPUT ;
    USE SIGNAL ;
    PORT
      LAYER M5 ;
        RECT  20.208 69.036 20.232 69.12 ;
    END
  END cfg_data[238]
  PIN cfg_data[239]
    DIRECTION INPUT ;
    USE SIGNAL ;
    PORT
      LAYER M5 ;
        RECT  20.304 69.036 20.328 69.12 ;
    END
  END cfg_data[239]
  PIN cfg_data[23]
    DIRECTION INPUT ;
    USE SIGNAL ;
    PORT
      LAYER M5 ;
        RECT  31.056 69.036 31.08 69.12 ;
    END
  END cfg_data[23]
  PIN cfg_data[240]
    DIRECTION INPUT ;
    USE SIGNAL ;
    PORT
      LAYER M5 ;
        RECT  20.4 69.036 20.424 69.12 ;
    END
  END cfg_data[240]
  PIN cfg_data[241]
    DIRECTION INPUT ;
    USE SIGNAL ;
    PORT
      LAYER M5 ;
        RECT  20.496 69.036 20.52 69.12 ;
    END
  END cfg_data[241]
  PIN cfg_data[242]
    DIRECTION INPUT ;
    USE SIGNAL ;
    PORT
      LAYER M5 ;
        RECT  20.592 69.036 20.616 69.12 ;
    END
  END cfg_data[242]
  PIN cfg_data[243]
    DIRECTION INPUT ;
    USE SIGNAL ;
    PORT
      LAYER M5 ;
        RECT  20.688 69.036 20.712 69.12 ;
    END
  END cfg_data[243]
  PIN cfg_data[244]
    DIRECTION INPUT ;
    USE SIGNAL ;
    PORT
      LAYER M5 ;
        RECT  26.928 69.036 26.952 69.12 ;
    END
  END cfg_data[244]
  PIN cfg_data[245]
    DIRECTION INPUT ;
    USE SIGNAL ;
    PORT
      LAYER M5 ;
        RECT  27.024 69.036 27.048 69.12 ;
    END
  END cfg_data[245]
  PIN cfg_data[246]
    DIRECTION INPUT ;
    USE SIGNAL ;
    PORT
      LAYER M5 ;
        RECT  27.12 69.036 27.144 69.12 ;
    END
  END cfg_data[246]
  PIN cfg_data[247]
    DIRECTION INPUT ;
    USE SIGNAL ;
    PORT
      LAYER M5 ;
        RECT  27.216 69.036 27.24 69.12 ;
    END
  END cfg_data[247]
  PIN cfg_data[248]
    DIRECTION INPUT ;
    USE SIGNAL ;
    PORT
      LAYER M5 ;
        RECT  27.312 69.036 27.336 69.12 ;
    END
  END cfg_data[248]
  PIN cfg_data[249]
    DIRECTION INPUT ;
    USE SIGNAL ;
    PORT
      LAYER M5 ;
        RECT  27.408 69.036 27.432 69.12 ;
    END
  END cfg_data[249]
  PIN cfg_data[24]
    DIRECTION INPUT ;
    USE SIGNAL ;
    PORT
      LAYER M5 ;
        RECT  31.152 69.036 31.176 69.12 ;
    END
  END cfg_data[24]
  PIN cfg_data[250]
    DIRECTION INPUT ;
    USE SIGNAL ;
    PORT
      LAYER M5 ;
        RECT  27.504 69.036 27.528 69.12 ;
    END
  END cfg_data[250]
  PIN cfg_data[251]
    DIRECTION INPUT ;
    USE SIGNAL ;
    PORT
      LAYER M5 ;
        RECT  27.6 69.036 27.624 69.12 ;
    END
  END cfg_data[251]
  PIN cfg_data[252]
    DIRECTION INPUT ;
    USE SIGNAL ;
    PORT
      LAYER M5 ;
        RECT  27.696 69.036 27.72 69.12 ;
    END
  END cfg_data[252]
  PIN cfg_data[253]
    DIRECTION INPUT ;
    USE SIGNAL ;
    PORT
      LAYER M5 ;
        RECT  27.792 69.036 27.816 69.12 ;
    END
  END cfg_data[253]
  PIN cfg_data[254]
    DIRECTION INPUT ;
    USE SIGNAL ;
    PORT
      LAYER M5 ;
        RECT  27.888 69.036 27.912 69.12 ;
    END
  END cfg_data[254]
  PIN cfg_data[255]
    DIRECTION INPUT ;
    USE SIGNAL ;
    PORT
      LAYER M5 ;
        RECT  27.984 69.036 28.008 69.12 ;
    END
  END cfg_data[255]
  PIN cfg_data[25]
    DIRECTION INPUT ;
    USE SIGNAL ;
    PORT
      LAYER M5 ;
        RECT  31.248 69.036 31.272 69.12 ;
    END
  END cfg_data[25]
  PIN cfg_data[26]
    DIRECTION INPUT ;
    USE SIGNAL ;
    PORT
      LAYER M5 ;
        RECT  31.344 69.036 31.368 69.12 ;
    END
  END cfg_data[26]
  PIN cfg_data[27]
    DIRECTION INPUT ;
    USE SIGNAL ;
    PORT
      LAYER M5 ;
        RECT  31.44 69.036 31.464 69.12 ;
    END
  END cfg_data[27]
  PIN cfg_data[28]
    DIRECTION INPUT ;
    USE SIGNAL ;
    PORT
      LAYER M5 ;
        RECT  31.536 69.036 31.56 69.12 ;
    END
  END cfg_data[28]
  PIN cfg_data[29]
    DIRECTION INPUT ;
    USE SIGNAL ;
    PORT
      LAYER M5 ;
        RECT  31.632 69.036 31.656 69.12 ;
    END
  END cfg_data[29]
  PIN cfg_data[2]
    DIRECTION INPUT ;
    USE SIGNAL ;
    PORT
      LAYER M5 ;
        RECT  38.256 69.036 38.28 69.12 ;
    END
  END cfg_data[2]
  PIN cfg_data[30]
    DIRECTION INPUT ;
    USE SIGNAL ;
    PORT
      LAYER M5 ;
        RECT  31.728 69.036 31.752 69.12 ;
    END
  END cfg_data[30]
  PIN cfg_data[31]
    DIRECTION INPUT ;
    USE SIGNAL ;
    PORT
      LAYER M5 ;
        RECT  31.824 69.036 31.848 69.12 ;
    END
  END cfg_data[31]
  PIN cfg_data[32]
    DIRECTION INPUT ;
    USE SIGNAL ;
    PORT
      LAYER M5 ;
        RECT  31.92 69.036 31.944 69.12 ;
    END
  END cfg_data[32]
  PIN cfg_data[33]
    DIRECTION INPUT ;
    USE SIGNAL ;
    PORT
      LAYER M5 ;
        RECT  32.016 69.036 32.04 69.12 ;
    END
  END cfg_data[33]
  PIN cfg_data[34]
    DIRECTION INPUT ;
    USE SIGNAL ;
    PORT
      LAYER M5 ;
        RECT  32.112 69.036 32.136 69.12 ;
    END
  END cfg_data[34]
  PIN cfg_data[35]
    DIRECTION INPUT ;
    USE SIGNAL ;
    PORT
      LAYER M5 ;
        RECT  32.208 69.036 32.232 69.12 ;
    END
  END cfg_data[35]
  PIN cfg_data[36]
    DIRECTION INPUT ;
    USE SIGNAL ;
    PORT
      LAYER M5 ;
        RECT  32.304 69.036 32.328 69.12 ;
    END
  END cfg_data[36]
  PIN cfg_data[37]
    DIRECTION INPUT ;
    USE SIGNAL ;
    PORT
      LAYER M5 ;
        RECT  32.4 69.036 32.424 69.12 ;
    END
  END cfg_data[37]
  PIN cfg_data[38]
    DIRECTION INPUT ;
    USE SIGNAL ;
    PORT
      LAYER M5 ;
        RECT  32.496 69.036 32.52 69.12 ;
    END
  END cfg_data[38]
  PIN cfg_data[39]
    DIRECTION INPUT ;
    USE SIGNAL ;
    PORT
      LAYER M5 ;
        RECT  32.592 69.036 32.616 69.12 ;
    END
  END cfg_data[39]
  PIN cfg_data[3]
    DIRECTION INPUT ;
    USE SIGNAL ;
    PORT
      LAYER M5 ;
        RECT  38.352 69.036 38.376 69.12 ;
    END
  END cfg_data[3]
  PIN cfg_data[40]
    DIRECTION INPUT ;
    USE SIGNAL ;
    PORT
      LAYER M5 ;
        RECT  32.688 69.036 32.712 69.12 ;
    END
  END cfg_data[40]
  PIN cfg_data[41]
    DIRECTION INPUT ;
    USE SIGNAL ;
    PORT
      LAYER M5 ;
        RECT  32.784 69.036 32.808 69.12 ;
    END
  END cfg_data[41]
  PIN cfg_data[42]
    DIRECTION INPUT ;
    USE SIGNAL ;
    PORT
      LAYER M5 ;
        RECT  32.88 69.036 32.904 69.12 ;
    END
  END cfg_data[42]
  PIN cfg_data[43]
    DIRECTION INPUT ;
    USE SIGNAL ;
    PORT
      LAYER M5 ;
        RECT  32.976 69.036 33 69.12 ;
    END
  END cfg_data[43]
  PIN cfg_data[44]
    DIRECTION INPUT ;
    USE SIGNAL ;
    PORT
      LAYER M5 ;
        RECT  33.072 69.036 33.096 69.12 ;
    END
  END cfg_data[44]
  PIN cfg_data[45]
    DIRECTION INPUT ;
    USE SIGNAL ;
    PORT
      LAYER M5 ;
        RECT  33.168 69.036 33.192 69.12 ;
    END
  END cfg_data[45]
  PIN cfg_data[46]
    DIRECTION INPUT ;
    USE SIGNAL ;
    PORT
      LAYER M5 ;
        RECT  33.264 69.036 33.288 69.12 ;
    END
  END cfg_data[46]
  PIN cfg_data[47]
    DIRECTION INPUT ;
    USE SIGNAL ;
    PORT
      LAYER M5 ;
        RECT  33.36 69.036 33.384 69.12 ;
    END
  END cfg_data[47]
  PIN cfg_data[48]
    DIRECTION INPUT ;
    USE SIGNAL ;
    PORT
      LAYER M5 ;
        RECT  33.456 69.036 33.48 69.12 ;
    END
  END cfg_data[48]
  PIN cfg_data[49]
    DIRECTION INPUT ;
    USE SIGNAL ;
    PORT
      LAYER M5 ;
        RECT  33.552 69.036 33.576 69.12 ;
    END
  END cfg_data[49]
  PIN cfg_data[4]
    DIRECTION INPUT ;
    USE SIGNAL ;
    PORT
      LAYER M5 ;
        RECT  38.448 69.036 38.472 69.12 ;
    END
  END cfg_data[4]
  PIN cfg_data[50]
    DIRECTION INPUT ;
    USE SIGNAL ;
    PORT
      LAYER M5 ;
        RECT  33.648 69.036 33.672 69.12 ;
    END
  END cfg_data[50]
  PIN cfg_data[51]
    DIRECTION INPUT ;
    USE SIGNAL ;
    PORT
      LAYER M5 ;
        RECT  33.744 69.036 33.768 69.12 ;
    END
  END cfg_data[51]
  PIN cfg_data[52]
    DIRECTION INPUT ;
    USE SIGNAL ;
    PORT
      LAYER M5 ;
        RECT  46.128 69.036 46.152 69.12 ;
    END
  END cfg_data[52]
  PIN cfg_data[53]
    DIRECTION INPUT ;
    USE SIGNAL ;
    PORT
      LAYER M5 ;
        RECT  46.224 69.036 46.248 69.12 ;
    END
  END cfg_data[53]
  PIN cfg_data[54]
    DIRECTION INPUT ;
    USE SIGNAL ;
    PORT
      LAYER M5 ;
        RECT  46.32 69.036 46.344 69.12 ;
    END
  END cfg_data[54]
  PIN cfg_data[55]
    DIRECTION INPUT ;
    USE SIGNAL ;
    PORT
      LAYER M5 ;
        RECT  46.416 69.036 46.44 69.12 ;
    END
  END cfg_data[55]
  PIN cfg_data[56]
    DIRECTION INPUT ;
    USE SIGNAL ;
    PORT
      LAYER M5 ;
        RECT  46.512 69.036 46.536 69.12 ;
    END
  END cfg_data[56]
  PIN cfg_data[57]
    DIRECTION INPUT ;
    USE SIGNAL ;
    PORT
      LAYER M5 ;
        RECT  46.608 69.036 46.632 69.12 ;
    END
  END cfg_data[57]
  PIN cfg_data[58]
    DIRECTION INPUT ;
    USE SIGNAL ;
    PORT
      LAYER M5 ;
        RECT  46.704 69.036 46.728 69.12 ;
    END
  END cfg_data[58]
  PIN cfg_data[59]
    DIRECTION INPUT ;
    USE SIGNAL ;
    PORT
      LAYER M5 ;
        RECT  46.8 69.036 46.824 69.12 ;
    END
  END cfg_data[59]
  PIN cfg_data[5]
    DIRECTION INPUT ;
    USE SIGNAL ;
    PORT
      LAYER M5 ;
        RECT  38.544 69.036 38.568 69.12 ;
    END
  END cfg_data[5]
  PIN cfg_data[60]
    DIRECTION INPUT ;
    USE SIGNAL ;
    PORT
      LAYER M5 ;
        RECT  46.896 69.036 46.92 69.12 ;
    END
  END cfg_data[60]
  PIN cfg_data[61]
    DIRECTION INPUT ;
    USE SIGNAL ;
    PORT
      LAYER M5 ;
        RECT  46.992 69.036 47.016 69.12 ;
    END
  END cfg_data[61]
  PIN cfg_data[62]
    DIRECTION INPUT ;
    USE SIGNAL ;
    PORT
      LAYER M5 ;
        RECT  47.088 69.036 47.112 69.12 ;
    END
  END cfg_data[62]
  PIN cfg_data[63]
    DIRECTION INPUT ;
    USE SIGNAL ;
    PORT
      LAYER M5 ;
        RECT  47.184 69.036 47.208 69.12 ;
    END
  END cfg_data[63]
  PIN cfg_data[64]
    DIRECTION INPUT ;
    USE SIGNAL ;
    PORT
      LAYER M5 ;
        RECT  47.28 69.036 47.304 69.12 ;
    END
  END cfg_data[64]
  PIN cfg_data[65]
    DIRECTION INPUT ;
    USE SIGNAL ;
    PORT
      LAYER M5 ;
        RECT  47.376 69.036 47.4 69.12 ;
    END
  END cfg_data[65]
  PIN cfg_data[66]
    DIRECTION INPUT ;
    USE SIGNAL ;
    PORT
      LAYER M5 ;
        RECT  47.472 69.036 47.496 69.12 ;
    END
  END cfg_data[66]
  PIN cfg_data[67]
    DIRECTION INPUT ;
    USE SIGNAL ;
    PORT
      LAYER M5 ;
        RECT  47.568 69.036 47.592 69.12 ;
    END
  END cfg_data[67]
  PIN cfg_data[68]
    DIRECTION INPUT ;
    USE SIGNAL ;
    PORT
      LAYER M5 ;
        RECT  47.664 69.036 47.688 69.12 ;
    END
  END cfg_data[68]
  PIN cfg_data[69]
    DIRECTION INPUT ;
    USE SIGNAL ;
    PORT
      LAYER M5 ;
        RECT  47.76 69.036 47.784 69.12 ;
    END
  END cfg_data[69]
  PIN cfg_data[6]
    DIRECTION INPUT ;
    USE SIGNAL ;
    PORT
      LAYER M5 ;
        RECT  38.64 69.036 38.664 69.12 ;
    END
  END cfg_data[6]
  PIN cfg_data[70]
    DIRECTION INPUT ;
    USE SIGNAL ;
    PORT
      LAYER M5 ;
        RECT  47.856 69.036 47.88 69.12 ;
    END
  END cfg_data[70]
  PIN cfg_data[71]
    DIRECTION INPUT ;
    USE SIGNAL ;
    PORT
      LAYER M5 ;
        RECT  47.952 69.036 47.976 69.12 ;
    END
  END cfg_data[71]
  PIN cfg_data[72]
    DIRECTION INPUT ;
    USE SIGNAL ;
    PORT
      LAYER M5 ;
        RECT  48.048 69.036 48.072 69.12 ;
    END
  END cfg_data[72]
  PIN cfg_data[73]
    DIRECTION INPUT ;
    USE SIGNAL ;
    PORT
      LAYER M5 ;
        RECT  48.144 69.036 48.168 69.12 ;
    END
  END cfg_data[73]
  PIN cfg_data[74]
    DIRECTION INPUT ;
    USE SIGNAL ;
    PORT
      LAYER M5 ;
        RECT  48.24 69.036 48.264 69.12 ;
    END
  END cfg_data[74]
  PIN cfg_data[75]
    DIRECTION INPUT ;
    USE SIGNAL ;
    PORT
      LAYER M5 ;
        RECT  48.336 69.036 48.36 69.12 ;
    END
  END cfg_data[75]
  PIN cfg_data[76]
    DIRECTION INPUT ;
    USE SIGNAL ;
    PORT
      LAYER M5 ;
        RECT  48.432 69.036 48.456 69.12 ;
    END
  END cfg_data[76]
  PIN cfg_data[77]
    DIRECTION INPUT ;
    USE SIGNAL ;
    PORT
      LAYER M5 ;
        RECT  48.528 69.036 48.552 69.12 ;
    END
  END cfg_data[77]
  PIN cfg_data[78]
    DIRECTION INPUT ;
    USE SIGNAL ;
    PORT
      LAYER M5 ;
        RECT  48.624 69.036 48.648 69.12 ;
    END
  END cfg_data[78]
  PIN cfg_data[79]
    DIRECTION INPUT ;
    USE SIGNAL ;
    PORT
      LAYER M5 ;
        RECT  48.72 69.036 48.744 69.12 ;
    END
  END cfg_data[79]
  PIN cfg_data[7]
    DIRECTION INPUT ;
    USE SIGNAL ;
    PORT
      LAYER M5 ;
        RECT  38.736 69.036 38.76 69.12 ;
    END
  END cfg_data[7]
  PIN cfg_data[80]
    DIRECTION INPUT ;
    USE SIGNAL ;
    PORT
      LAYER M5 ;
        RECT  48.816 69.036 48.84 69.12 ;
    END
  END cfg_data[80]
  PIN cfg_data[81]
    DIRECTION INPUT ;
    USE SIGNAL ;
    PORT
      LAYER M5 ;
        RECT  48.912 69.036 48.936 69.12 ;
    END
  END cfg_data[81]
  PIN cfg_data[82]
    DIRECTION INPUT ;
    USE SIGNAL ;
    PORT
      LAYER M5 ;
        RECT  49.008 69.036 49.032 69.12 ;
    END
  END cfg_data[82]
  PIN cfg_data[83]
    DIRECTION INPUT ;
    USE SIGNAL ;
    PORT
      LAYER M5 ;
        RECT  49.104 69.036 49.128 69.12 ;
    END
  END cfg_data[83]
  PIN cfg_data[84]
    DIRECTION INPUT ;
    USE SIGNAL ;
    PORT
      LAYER M5 ;
        RECT  39.984 69.036 40.008 69.12 ;
    END
  END cfg_data[84]
  PIN cfg_data[85]
    DIRECTION INPUT ;
    USE SIGNAL ;
    PORT
      LAYER M5 ;
        RECT  40.08 69.036 40.104 69.12 ;
    END
  END cfg_data[85]
  PIN cfg_data[86]
    DIRECTION INPUT ;
    USE SIGNAL ;
    PORT
      LAYER M5 ;
        RECT  40.176 69.036 40.2 69.12 ;
    END
  END cfg_data[86]
  PIN cfg_data[87]
    DIRECTION INPUT ;
    USE SIGNAL ;
    PORT
      LAYER M5 ;
        RECT  40.272 69.036 40.296 69.12 ;
    END
  END cfg_data[87]
  PIN cfg_data[88]
    DIRECTION INPUT ;
    USE SIGNAL ;
    PORT
      LAYER M5 ;
        RECT  40.368 69.036 40.392 69.12 ;
    END
  END cfg_data[88]
  PIN cfg_data[89]
    DIRECTION INPUT ;
    USE SIGNAL ;
    PORT
      LAYER M5 ;
        RECT  40.464 69.036 40.488 69.12 ;
    END
  END cfg_data[89]
  PIN cfg_data[8]
    DIRECTION INPUT ;
    USE SIGNAL ;
    PORT
      LAYER M5 ;
        RECT  38.832 69.036 38.856 69.12 ;
    END
  END cfg_data[8]
  PIN cfg_data[90]
    DIRECTION INPUT ;
    USE SIGNAL ;
    PORT
      LAYER M5 ;
        RECT  40.56 69.036 40.584 69.12 ;
    END
  END cfg_data[90]
  PIN cfg_data[91]
    DIRECTION INPUT ;
    USE SIGNAL ;
    PORT
      LAYER M5 ;
        RECT  40.656 69.036 40.68 69.12 ;
    END
  END cfg_data[91]
  PIN cfg_data[92]
    DIRECTION INPUT ;
    USE SIGNAL ;
    PORT
      LAYER M5 ;
        RECT  40.752 69.036 40.776 69.12 ;
    END
  END cfg_data[92]
  PIN cfg_data[93]
    DIRECTION INPUT ;
    USE SIGNAL ;
    PORT
      LAYER M5 ;
        RECT  40.848 69.036 40.872 69.12 ;
    END
  END cfg_data[93]
  PIN cfg_data[94]
    DIRECTION INPUT ;
    USE SIGNAL ;
    PORT
      LAYER M5 ;
        RECT  40.944 69.036 40.968 69.12 ;
    END
  END cfg_data[94]
  PIN cfg_data[95]
    DIRECTION INPUT ;
    USE SIGNAL ;
    PORT
      LAYER M5 ;
        RECT  41.04 69.036 41.064 69.12 ;
    END
  END cfg_data[95]
  PIN cfg_data[96]
    DIRECTION INPUT ;
    USE SIGNAL ;
    PORT
      LAYER M5 ;
        RECT  41.136 69.036 41.16 69.12 ;
    END
  END cfg_data[96]
  PIN cfg_data[97]
    DIRECTION INPUT ;
    USE SIGNAL ;
    PORT
      LAYER M5 ;
        RECT  41.232 69.036 41.256 69.12 ;
    END
  END cfg_data[97]
  PIN cfg_data[98]
    DIRECTION INPUT ;
    USE SIGNAL ;
    PORT
      LAYER M5 ;
        RECT  41.328 69.036 41.352 69.12 ;
    END
  END cfg_data[98]
  PIN cfg_data[99]
    DIRECTION INPUT ;
    USE SIGNAL ;
    PORT
      LAYER M5 ;
        RECT  41.424 69.036 41.448 69.12 ;
    END
  END cfg_data[99]
  PIN cfg_data[9]
    DIRECTION INPUT ;
    USE SIGNAL ;
    PORT
      LAYER M5 ;
        RECT  38.928 69.036 38.952 69.12 ;
    END
  END cfg_data[9]
  PIN cfg_target[0]
    DIRECTION INPUT ;
    USE SIGNAL ;
    PORT
      LAYER M5 ;
        RECT  28.08 69.036 28.104 69.12 ;
    END
  END cfg_target[0]
  PIN cfg_target[1]
    DIRECTION INPUT ;
    USE SIGNAL ;
    PORT
      LAYER M5 ;
        RECT  28.176 69.036 28.2 69.12 ;
    END
  END cfg_target[1]
  PIN cfg_target[2]
    DIRECTION INPUT ;
    USE SIGNAL ;
    PORT
      LAYER M5 ;
        RECT  28.272 69.036 28.296 69.12 ;
    END
  END cfg_target[2]
  PIN cfg_target[3]
    DIRECTION INPUT ;
    USE SIGNAL ;
    PORT
      LAYER M5 ;
        RECT  28.368 69.036 28.392 69.12 ;
    END
  END cfg_target[3]
  PIN cfg_target[4]
    DIRECTION INPUT ;
    USE SIGNAL ;
    PORT
      LAYER M5 ;
        RECT  28.464 69.036 28.488 69.12 ;
    END
  END cfg_target[4]
  PIN cfg_target[5]
    DIRECTION INPUT ;
    USE SIGNAL ;
    PORT
      LAYER M5 ;
        RECT  28.56 69.036 28.584 69.12 ;
    END
  END cfg_target[5]
  PIN cfg_target[6]
    DIRECTION INPUT ;
    USE SIGNAL ;
    PORT
      LAYER M5 ;
        RECT  28.656 69.036 28.68 69.12 ;
    END
  END cfg_target[6]
  PIN cfg_target[7]
    DIRECTION INPUT ;
    USE SIGNAL ;
    PORT
      LAYER M5 ;
        RECT  28.752 69.036 28.776 69.12 ;
    END
  END cfg_target[7]
  PIN cfg_v
    DIRECTION INPUT ;
    USE SIGNAL ;
    PORT
      LAYER M5 ;
        RECT  28.848 69.036 28.872 69.12 ;
    END
  END cfg_v
  PIN clk
    DIRECTION INPUT ;
    USE SIGNAL ;
    PORT
      LAYER M5 ;
        RECT  28.944 69.036 28.968 69.12 ;
    END
  END clk
  PIN desc_base[0]
    DIRECTION INPUT ;
    USE SIGNAL ;
    PORT
      LAYER M5 ;
        RECT  29.04 69.036 29.064 69.12 ;
    END
  END desc_base[0]
  PIN desc_base[10]
    DIRECTION INPUT ;
    USE SIGNAL ;
    PORT
      LAYER M5 ;
        RECT  20.784 69.036 20.808 69.12 ;
    END
  END desc_base[10]
  PIN desc_base[11]
    DIRECTION INPUT ;
    USE SIGNAL ;
    PORT
      LAYER M5 ;
        RECT  20.88 69.036 20.904 69.12 ;
    END
  END desc_base[11]
  PIN desc_base[1]
    DIRECTION INPUT ;
    USE SIGNAL ;
    PORT
      LAYER M5 ;
        RECT  29.136 69.036 29.16 69.12 ;
    END
  END desc_base[1]
  PIN desc_base[2]
    DIRECTION INPUT ;
    USE SIGNAL ;
    PORT
      LAYER M5 ;
        RECT  29.232 69.036 29.256 69.12 ;
    END
  END desc_base[2]
  PIN desc_base[3]
    DIRECTION INPUT ;
    USE SIGNAL ;
    PORT
      LAYER M5 ;
        RECT  29.328 69.036 29.352 69.12 ;
    END
  END desc_base[3]
  PIN desc_base[4]
    DIRECTION INPUT ;
    USE SIGNAL ;
    PORT
      LAYER M5 ;
        RECT  29.424 69.036 29.448 69.12 ;
    END
  END desc_base[4]
  PIN desc_base[5]
    DIRECTION INPUT ;
    USE SIGNAL ;
    PORT
      LAYER M5 ;
        RECT  29.52 69.036 29.544 69.12 ;
    END
  END desc_base[5]
  PIN desc_base[6]
    DIRECTION INPUT ;
    USE SIGNAL ;
    PORT
      LAYER M5 ;
        RECT  29.616 69.036 29.64 69.12 ;
    END
  END desc_base[6]
  PIN desc_base[7]
    DIRECTION INPUT ;
    USE SIGNAL ;
    PORT
      LAYER M5 ;
        RECT  29.712 69.036 29.736 69.12 ;
    END
  END desc_base[7]
  PIN desc_base[8]
    DIRECTION INPUT ;
    USE SIGNAL ;
    PORT
      LAYER M5 ;
        RECT  29.808 69.036 29.832 69.12 ;
    END
  END desc_base[8]
  PIN desc_base[9]
    DIRECTION INPUT ;
    USE SIGNAL ;
    PORT
      LAYER M5 ;
        RECT  29.904 69.036 29.928 69.12 ;
    END
  END desc_base[9]
  PIN desc_limit[0]
    DIRECTION INPUT ;
    USE SIGNAL ;
    PORT
      LAYER M5 ;
        RECT  20.976 69.036 21 69.12 ;
    END
  END desc_limit[0]
  PIN desc_limit[10]
    DIRECTION INPUT ;
    USE SIGNAL ;
    PORT
      LAYER M5 ;
        RECT  21.936 69.036 21.96 69.12 ;
    END
  END desc_limit[10]
  PIN desc_limit[11]
    DIRECTION INPUT ;
    USE SIGNAL ;
    PORT
      LAYER M5 ;
        RECT  22.032 69.036 22.056 69.12 ;
    END
  END desc_limit[11]
  PIN desc_limit[12]
    DIRECTION INPUT ;
    USE SIGNAL ;
    PORT
      LAYER M5 ;
        RECT  22.128 69.036 22.152 69.12 ;
    END
  END desc_limit[12]
  PIN desc_limit[1]
    DIRECTION INPUT ;
    USE SIGNAL ;
    PORT
      LAYER M5 ;
        RECT  21.072 69.036 21.096 69.12 ;
    END
  END desc_limit[1]
  PIN desc_limit[2]
    DIRECTION INPUT ;
    USE SIGNAL ;
    PORT
      LAYER M5 ;
        RECT  21.168 69.036 21.192 69.12 ;
    END
  END desc_limit[2]
  PIN desc_limit[3]
    DIRECTION INPUT ;
    USE SIGNAL ;
    PORT
      LAYER M5 ;
        RECT  21.264 69.036 21.288 69.12 ;
    END
  END desc_limit[3]
  PIN desc_limit[4]
    DIRECTION INPUT ;
    USE SIGNAL ;
    PORT
      LAYER M5 ;
        RECT  21.36 69.036 21.384 69.12 ;
    END
  END desc_limit[4]
  PIN desc_limit[5]
    DIRECTION INPUT ;
    USE SIGNAL ;
    PORT
      LAYER M5 ;
        RECT  21.456 69.036 21.48 69.12 ;
    END
  END desc_limit[5]
  PIN desc_limit[6]
    DIRECTION INPUT ;
    USE SIGNAL ;
    PORT
      LAYER M5 ;
        RECT  21.552 69.036 21.576 69.12 ;
    END
  END desc_limit[6]
  PIN desc_limit[7]
    DIRECTION INPUT ;
    USE SIGNAL ;
    PORT
      LAYER M5 ;
        RECT  21.648 69.036 21.672 69.12 ;
    END
  END desc_limit[7]
  PIN desc_limit[8]
    DIRECTION INPUT ;
    USE SIGNAL ;
    PORT
      LAYER M5 ;
        RECT  21.744 69.036 21.768 69.12 ;
    END
  END desc_limit[8]
  PIN desc_limit[9]
    DIRECTION INPUT ;
    USE SIGNAL ;
    PORT
      LAYER M5 ;
        RECT  21.84 69.036 21.864 69.12 ;
    END
  END desc_limit[9]
  PIN desc_loops[0]
    DIRECTION INPUT ;
    USE SIGNAL ;
    PORT
      LAYER M5 ;
        RECT  22.224 69.036 22.248 69.12 ;
    END
  END desc_loops[0]
  PIN desc_loops[10]
    DIRECTION INPUT ;
    USE SIGNAL ;
    PORT
      LAYER M5 ;
        RECT  23.184 69.036 23.208 69.12 ;
    END
  END desc_loops[10]
  PIN desc_loops[11]
    DIRECTION INPUT ;
    USE SIGNAL ;
    PORT
      LAYER M5 ;
        RECT  23.28 69.036 23.304 69.12 ;
    END
  END desc_loops[11]
  PIN desc_loops[12]
    DIRECTION INPUT ;
    USE SIGNAL ;
    PORT
      LAYER M5 ;
        RECT  23.376 69.036 23.4 69.12 ;
    END
  END desc_loops[12]
  PIN desc_loops[13]
    DIRECTION INPUT ;
    USE SIGNAL ;
    PORT
      LAYER M5 ;
        RECT  23.472 69.036 23.496 69.12 ;
    END
  END desc_loops[13]
  PIN desc_loops[14]
    DIRECTION INPUT ;
    USE SIGNAL ;
    PORT
      LAYER M5 ;
        RECT  23.568 69.036 23.592 69.12 ;
    END
  END desc_loops[14]
  PIN desc_loops[15]
    DIRECTION INPUT ;
    USE SIGNAL ;
    PORT
      LAYER M5 ;
        RECT  23.664 69.036 23.688 69.12 ;
    END
  END desc_loops[15]
  PIN desc_loops[1]
    DIRECTION INPUT ;
    USE SIGNAL ;
    PORT
      LAYER M5 ;
        RECT  22.32 69.036 22.344 69.12 ;
    END
  END desc_loops[1]
  PIN desc_loops[2]
    DIRECTION INPUT ;
    USE SIGNAL ;
    PORT
      LAYER M5 ;
        RECT  22.416 69.036 22.44 69.12 ;
    END
  END desc_loops[2]
  PIN desc_loops[3]
    DIRECTION INPUT ;
    USE SIGNAL ;
    PORT
      LAYER M5 ;
        RECT  22.512 69.036 22.536 69.12 ;
    END
  END desc_loops[3]
  PIN desc_loops[4]
    DIRECTION INPUT ;
    USE SIGNAL ;
    PORT
      LAYER M5 ;
        RECT  22.608 69.036 22.632 69.12 ;
    END
  END desc_loops[4]
  PIN desc_loops[5]
    DIRECTION INPUT ;
    USE SIGNAL ;
    PORT
      LAYER M5 ;
        RECT  22.704 69.036 22.728 69.12 ;
    END
  END desc_loops[5]
  PIN desc_loops[6]
    DIRECTION INPUT ;
    USE SIGNAL ;
    PORT
      LAYER M5 ;
        RECT  22.8 69.036 22.824 69.12 ;
    END
  END desc_loops[6]
  PIN desc_loops[7]
    DIRECTION INPUT ;
    USE SIGNAL ;
    PORT
      LAYER M5 ;
        RECT  22.896 69.036 22.92 69.12 ;
    END
  END desc_loops[7]
  PIN desc_loops[8]
    DIRECTION INPUT ;
    USE SIGNAL ;
    PORT
      LAYER M5 ;
        RECT  22.992 69.036 23.016 69.12 ;
    END
  END desc_loops[8]
  PIN desc_loops[9]
    DIRECTION INPUT ;
    USE SIGNAL ;
    PORT
      LAYER M5 ;
        RECT  23.088 69.036 23.112 69.12 ;
    END
  END desc_loops[9]
  PIN desc_v
    DIRECTION INPUT ;
    USE SIGNAL ;
    PORT
      LAYER M5 ;
        RECT  23.76 69.036 23.784 69.12 ;
    END
  END desc_v
  PIN launch_v
    DIRECTION INPUT ;
    USE SIGNAL ;
    PORT
      LAYER M5 ;
        RECT  30.576 69.036 30.6 69.12 ;
    END
  END launch_v
  PIN rst_n
    DIRECTION INPUT ;
    USE SIGNAL ;
    PORT
      LAYER M5 ;
        RECT  30.672 69.036 30.696 69.12 ;
    END
  END rst_n
  PIN s_active[0]
    DIRECTION OUTPUT ;
    USE SIGNAL ;
    PORT
      LAYER M5 ;
        RECT  42.192 0 42.216 0.084 ;
    END
  END s_active[0]
  PIN s_active[10]
    DIRECTION OUTPUT ;
    USE SIGNAL ;
    PORT
      LAYER M5 ;
        RECT  43.152 0 43.176 0.084 ;
    END
  END s_active[10]
  PIN s_active[11]
    DIRECTION OUTPUT ;
    USE SIGNAL ;
    PORT
      LAYER M5 ;
        RECT  43.248 0 43.272 0.084 ;
    END
  END s_active[11]
  PIN s_active[12]
    DIRECTION OUTPUT ;
    USE SIGNAL ;
    PORT
      LAYER M5 ;
        RECT  43.344 0 43.368 0.084 ;
    END
  END s_active[12]
  PIN s_active[13]
    DIRECTION OUTPUT ;
    USE SIGNAL ;
    PORT
      LAYER M5 ;
        RECT  43.44 0 43.464 0.084 ;
    END
  END s_active[13]
  PIN s_active[1]
    DIRECTION OUTPUT ;
    USE SIGNAL ;
    PORT
      LAYER M5 ;
        RECT  42.288 0 42.312 0.084 ;
    END
  END s_active[1]
  PIN s_active[2]
    DIRECTION OUTPUT ;
    USE SIGNAL ;
    PORT
      LAYER M5 ;
        RECT  42.384 0 42.408 0.084 ;
    END
  END s_active[2]
  PIN s_active[3]
    DIRECTION OUTPUT ;
    USE SIGNAL ;
    PORT
      LAYER M5 ;
        RECT  42.48 0 42.504 0.084 ;
    END
  END s_active[3]
  PIN s_active[4]
    DIRECTION OUTPUT ;
    USE SIGNAL ;
    PORT
      LAYER M5 ;
        RECT  42.576 0 42.6 0.084 ;
    END
  END s_active[4]
  PIN s_active[5]
    DIRECTION OUTPUT ;
    USE SIGNAL ;
    PORT
      LAYER M5 ;
        RECT  42.672 0 42.696 0.084 ;
    END
  END s_active[5]
  PIN s_active[6]
    DIRECTION OUTPUT ;
    USE SIGNAL ;
    PORT
      LAYER M5 ;
        RECT  42.768 0 42.792 0.084 ;
    END
  END s_active[6]
  PIN s_active[7]
    DIRECTION OUTPUT ;
    USE SIGNAL ;
    PORT
      LAYER M5 ;
        RECT  42.864 0 42.888 0.084 ;
    END
  END s_active[7]
  PIN s_active[8]
    DIRECTION OUTPUT ;
    USE SIGNAL ;
    PORT
      LAYER M5 ;
        RECT  42.96 0 42.984 0.084 ;
    END
  END s_active[8]
  PIN s_active[9]
    DIRECTION OUTPUT ;
    USE SIGNAL ;
    PORT
      LAYER M5 ;
        RECT  43.056 0 43.08 0.084 ;
    END
  END s_active[9]
  PIN s_fault[0]
    DIRECTION OUTPUT ;
    USE SIGNAL ;
    PORT
      LAYER M5 ;
        RECT  43.536 0 43.56 0.084 ;
    END
  END s_fault[0]
  PIN s_fault[10]
    DIRECTION OUTPUT ;
    USE SIGNAL ;
    PORT
      LAYER M5 ;
        RECT  44.496 0 44.52 0.084 ;
    END
  END s_fault[10]
  PIN s_fault[11]
    DIRECTION OUTPUT ;
    USE SIGNAL ;
    PORT
      LAYER M5 ;
        RECT  44.592 0 44.616 0.084 ;
    END
  END s_fault[11]
  PIN s_fault[12]
    DIRECTION OUTPUT ;
    USE SIGNAL ;
    PORT
      LAYER M5 ;
        RECT  44.688 0 44.712 0.084 ;
    END
  END s_fault[12]
  PIN s_fault[13]
    DIRECTION OUTPUT ;
    USE SIGNAL ;
    PORT
      LAYER M5 ;
        RECT  44.784 0 44.808 0.084 ;
    END
  END s_fault[13]
  PIN s_fault[14]
    DIRECTION OUTPUT ;
    USE SIGNAL ;
    PORT
      LAYER M5 ;
        RECT  44.88 0 44.904 0.084 ;
    END
  END s_fault[14]
  PIN s_fault[15]
    DIRECTION OUTPUT ;
    USE SIGNAL ;
    PORT
      LAYER M5 ;
        RECT  44.976 0 45 0.084 ;
    END
  END s_fault[15]
  PIN s_fault[16]
    DIRECTION OUTPUT ;
    USE SIGNAL ;
    PORT
      LAYER M5 ;
        RECT  45.072 0 45.096 0.084 ;
    END
  END s_fault[16]
  PIN s_fault[17]
    DIRECTION OUTPUT ;
    USE SIGNAL ;
    PORT
      LAYER M5 ;
        RECT  45.168 0 45.192 0.084 ;
    END
  END s_fault[17]
  PIN s_fault[18]
    DIRECTION OUTPUT ;
    USE SIGNAL ;
    PORT
      LAYER M5 ;
        RECT  39.12 0 39.144 0.084 ;
    END
  END s_fault[18]
  PIN s_fault[19]
    DIRECTION OUTPUT ;
    USE SIGNAL ;
    PORT
      LAYER M5 ;
        RECT  39.216 0 39.24 0.084 ;
    END
  END s_fault[19]
  PIN s_fault[1]
    DIRECTION OUTPUT ;
    USE SIGNAL ;
    PORT
      LAYER M5 ;
        RECT  43.632 0 43.656 0.084 ;
    END
  END s_fault[1]
  PIN s_fault[20]
    DIRECTION OUTPUT ;
    USE SIGNAL ;
    PORT
      LAYER M5 ;
        RECT  39.312 0 39.336 0.084 ;
    END
  END s_fault[20]
  PIN s_fault[21]
    DIRECTION OUTPUT ;
    USE SIGNAL ;
    PORT
      LAYER M5 ;
        RECT  39.408 0 39.432 0.084 ;
    END
  END s_fault[21]
  PIN s_fault[22]
    DIRECTION OUTPUT ;
    USE SIGNAL ;
    PORT
      LAYER M5 ;
        RECT  39.504 0 39.528 0.084 ;
    END
  END s_fault[22]
  PIN s_fault[2]
    DIRECTION OUTPUT ;
    USE SIGNAL ;
    PORT
      LAYER M5 ;
        RECT  43.728 0 43.752 0.084 ;
    END
  END s_fault[2]
  PIN s_fault[3]
    DIRECTION OUTPUT ;
    USE SIGNAL ;
    PORT
      LAYER M5 ;
        RECT  43.824 0 43.848 0.084 ;
    END
  END s_fault[3]
  PIN s_fault[4]
    DIRECTION OUTPUT ;
    USE SIGNAL ;
    PORT
      LAYER M5 ;
        RECT  43.92 0 43.944 0.084 ;
    END
  END s_fault[4]
  PIN s_fault[5]
    DIRECTION OUTPUT ;
    USE SIGNAL ;
    PORT
      LAYER M5 ;
        RECT  44.016 0 44.04 0.084 ;
    END
  END s_fault[5]
  PIN s_fault[6]
    DIRECTION OUTPUT ;
    USE SIGNAL ;
    PORT
      LAYER M5 ;
        RECT  44.112 0 44.136 0.084 ;
    END
  END s_fault[6]
  PIN s_fault[7]
    DIRECTION OUTPUT ;
    USE SIGNAL ;
    PORT
      LAYER M5 ;
        RECT  44.208 0 44.232 0.084 ;
    END
  END s_fault[7]
  PIN s_fault[8]
    DIRECTION OUTPUT ;
    USE SIGNAL ;
    PORT
      LAYER M5 ;
        RECT  44.304 0 44.328 0.084 ;
    END
  END s_fault[8]
  PIN s_fault[9]
    DIRECTION OUTPUT ;
    USE SIGNAL ;
    PORT
      LAYER M5 ;
        RECT  44.4 0 44.424 0.084 ;
    END
  END s_fault[9]
  PIN s_ready[0]
    DIRECTION OUTPUT ;
    USE SIGNAL ;
    PORT
      LAYER M5 ;
        RECT  39.6 0 39.624 0.084 ;
    END
  END s_ready[0]
  PIN s_ready[10]
    DIRECTION OUTPUT ;
    USE SIGNAL ;
    PORT
      LAYER M5 ;
        RECT  40.56 0 40.584 0.084 ;
    END
  END s_ready[10]
  PIN s_ready[11]
    DIRECTION OUTPUT ;
    USE SIGNAL ;
    PORT
      LAYER M5 ;
        RECT  40.656 0 40.68 0.084 ;
    END
  END s_ready[11]
  PIN s_ready[12]
    DIRECTION OUTPUT ;
    USE SIGNAL ;
    PORT
      LAYER M5 ;
        RECT  40.752 0 40.776 0.084 ;
    END
  END s_ready[12]
  PIN s_ready[13]
    DIRECTION OUTPUT ;
    USE SIGNAL ;
    PORT
      LAYER M5 ;
        RECT  40.848 0 40.872 0.084 ;
    END
  END s_ready[13]
  PIN s_ready[1]
    DIRECTION OUTPUT ;
    USE SIGNAL ;
    PORT
      LAYER M5 ;
        RECT  39.696 0 39.72 0.084 ;
    END
  END s_ready[1]
  PIN s_ready[2]
    DIRECTION OUTPUT ;
    USE SIGNAL ;
    PORT
      LAYER M5 ;
        RECT  39.792 0 39.816 0.084 ;
    END
  END s_ready[2]
  PIN s_ready[3]
    DIRECTION OUTPUT ;
    USE SIGNAL ;
    PORT
      LAYER M5 ;
        RECT  39.888 0 39.912 0.084 ;
    END
  END s_ready[3]
  PIN s_ready[4]
    DIRECTION OUTPUT ;
    USE SIGNAL ;
    PORT
      LAYER M5 ;
        RECT  39.984 0 40.008 0.084 ;
    END
  END s_ready[4]
  PIN s_ready[5]
    DIRECTION OUTPUT ;
    USE SIGNAL ;
    PORT
      LAYER M5 ;
        RECT  40.08 0 40.104 0.084 ;
    END
  END s_ready[5]
  PIN s_ready[6]
    DIRECTION OUTPUT ;
    USE SIGNAL ;
    PORT
      LAYER M5 ;
        RECT  40.176 0 40.2 0.084 ;
    END
  END s_ready[6]
  PIN s_ready[7]
    DIRECTION OUTPUT ;
    USE SIGNAL ;
    PORT
      LAYER M5 ;
        RECT  40.272 0 40.296 0.084 ;
    END
  END s_ready[7]
  PIN s_ready[8]
    DIRECTION OUTPUT ;
    USE SIGNAL ;
    PORT
      LAYER M5 ;
        RECT  40.368 0 40.392 0.084 ;
    END
  END s_ready[8]
  PIN s_ready[9]
    DIRECTION OUTPUT ;
    USE SIGNAL ;
    PORT
      LAYER M5 ;
        RECT  40.464 0 40.488 0.084 ;
    END
  END s_ready[9]
  PIN t_active[0]
    DIRECTION INPUT ;
    USE SIGNAL ;
    PORT
      LAYER M5 ;
        RECT  40.944 0 40.968 0.084 ;
    END
  END t_active[0]
  PIN t_active[10]
    DIRECTION INPUT ;
    USE SIGNAL ;
    PORT
      LAYER M5 ;
        RECT  41.904 0 41.928 0.084 ;
    END
  END t_active[10]
  PIN t_active[11]
    DIRECTION INPUT ;
    USE SIGNAL ;
    PORT
      LAYER M5 ;
        RECT  42 0 42.024 0.084 ;
    END
  END t_active[11]
  PIN t_active[12]
    DIRECTION INPUT ;
    USE SIGNAL ;
    PORT
      LAYER M5 ;
        RECT  42.096 0 42.12 0.084 ;
    END
  END t_active[12]
  PIN t_active[13]
    DIRECTION INPUT ;
    USE SIGNAL ;
    PORT
      LAYER M5 ;
        RECT  35.28 0 35.304 0.084 ;
    END
  END t_active[13]
  PIN t_active[1]
    DIRECTION INPUT ;
    USE SIGNAL ;
    PORT
      LAYER M5 ;
        RECT  41.04 0 41.064 0.084 ;
    END
  END t_active[1]
  PIN t_active[2]
    DIRECTION INPUT ;
    USE SIGNAL ;
    PORT
      LAYER M5 ;
        RECT  41.136 0 41.16 0.084 ;
    END
  END t_active[2]
  PIN t_active[3]
    DIRECTION INPUT ;
    USE SIGNAL ;
    PORT
      LAYER M5 ;
        RECT  41.232 0 41.256 0.084 ;
    END
  END t_active[3]
  PIN t_active[4]
    DIRECTION INPUT ;
    USE SIGNAL ;
    PORT
      LAYER M5 ;
        RECT  41.328 0 41.352 0.084 ;
    END
  END t_active[4]
  PIN t_active[5]
    DIRECTION INPUT ;
    USE SIGNAL ;
    PORT
      LAYER M5 ;
        RECT  41.424 0 41.448 0.084 ;
    END
  END t_active[5]
  PIN t_active[6]
    DIRECTION INPUT ;
    USE SIGNAL ;
    PORT
      LAYER M5 ;
        RECT  41.52 0 41.544 0.084 ;
    END
  END t_active[6]
  PIN t_active[7]
    DIRECTION INPUT ;
    USE SIGNAL ;
    PORT
      LAYER M5 ;
        RECT  41.616 0 41.64 0.084 ;
    END
  END t_active[7]
  PIN t_active[8]
    DIRECTION INPUT ;
    USE SIGNAL ;
    PORT
      LAYER M5 ;
        RECT  41.712 0 41.736 0.084 ;
    END
  END t_active[8]
  PIN t_active[9]
    DIRECTION INPUT ;
    USE SIGNAL ;
    PORT
      LAYER M5 ;
        RECT  41.808 0 41.832 0.084 ;
    END
  END t_active[9]
  PIN t_fault[0]
    DIRECTION INPUT ;
    USE SIGNAL ;
    PORT
      LAYER M5 ;
        RECT  35.376 0 35.4 0.084 ;
    END
  END t_fault[0]
  PIN t_fault[10]
    DIRECTION INPUT ;
    USE SIGNAL ;
    PORT
      LAYER M5 ;
        RECT  36.336 0 36.36 0.084 ;
    END
  END t_fault[10]
  PIN t_fault[11]
    DIRECTION INPUT ;
    USE SIGNAL ;
    PORT
      LAYER M5 ;
        RECT  36.432 0 36.456 0.084 ;
    END
  END t_fault[11]
  PIN t_fault[12]
    DIRECTION INPUT ;
    USE SIGNAL ;
    PORT
      LAYER M5 ;
        RECT  36.528 0 36.552 0.084 ;
    END
  END t_fault[12]
  PIN t_fault[13]
    DIRECTION INPUT ;
    USE SIGNAL ;
    PORT
      LAYER M5 ;
        RECT  36.624 0 36.648 0.084 ;
    END
  END t_fault[13]
  PIN t_fault[14]
    DIRECTION INPUT ;
    USE SIGNAL ;
    PORT
      LAYER M5 ;
        RECT  36.72 0 36.744 0.084 ;
    END
  END t_fault[14]
  PIN t_fault[15]
    DIRECTION INPUT ;
    USE SIGNAL ;
    PORT
      LAYER M5 ;
        RECT  36.816 0 36.84 0.084 ;
    END
  END t_fault[15]
  PIN t_fault[16]
    DIRECTION INPUT ;
    USE SIGNAL ;
    PORT
      LAYER M5 ;
        RECT  36.912 0 36.936 0.084 ;
    END
  END t_fault[16]
  PIN t_fault[17]
    DIRECTION INPUT ;
    USE SIGNAL ;
    PORT
      LAYER M5 ;
        RECT  37.008 0 37.032 0.084 ;
    END
  END t_fault[17]
  PIN t_fault[18]
    DIRECTION INPUT ;
    USE SIGNAL ;
    PORT
      LAYER M5 ;
        RECT  37.104 0 37.128 0.084 ;
    END
  END t_fault[18]
  PIN t_fault[19]
    DIRECTION INPUT ;
    USE SIGNAL ;
    PORT
      LAYER M5 ;
        RECT  37.2 0 37.224 0.084 ;
    END
  END t_fault[19]
  PIN t_fault[1]
    DIRECTION INPUT ;
    USE SIGNAL ;
    PORT
      LAYER M5 ;
        RECT  35.472 0 35.496 0.084 ;
    END
  END t_fault[1]
  PIN t_fault[20]
    DIRECTION INPUT ;
    USE SIGNAL ;
    PORT
      LAYER M5 ;
        RECT  37.296 0 37.32 0.084 ;
    END
  END t_fault[20]
  PIN t_fault[21]
    DIRECTION INPUT ;
    USE SIGNAL ;
    PORT
      LAYER M5 ;
        RECT  37.392 0 37.416 0.084 ;
    END
  END t_fault[21]
  PIN t_fault[22]
    DIRECTION INPUT ;
    USE SIGNAL ;
    PORT
      LAYER M5 ;
        RECT  37.488 0 37.512 0.084 ;
    END
  END t_fault[22]
  PIN t_fault[2]
    DIRECTION INPUT ;
    USE SIGNAL ;
    PORT
      LAYER M5 ;
        RECT  35.568 0 35.592 0.084 ;
    END
  END t_fault[2]
  PIN t_fault[3]
    DIRECTION INPUT ;
    USE SIGNAL ;
    PORT
      LAYER M5 ;
        RECT  35.664 0 35.688 0.084 ;
    END
  END t_fault[3]
  PIN t_fault[4]
    DIRECTION INPUT ;
    USE SIGNAL ;
    PORT
      LAYER M5 ;
        RECT  35.76 0 35.784 0.084 ;
    END
  END t_fault[4]
  PIN t_fault[5]
    DIRECTION INPUT ;
    USE SIGNAL ;
    PORT
      LAYER M5 ;
        RECT  35.856 0 35.88 0.084 ;
    END
  END t_fault[5]
  PIN t_fault[6]
    DIRECTION INPUT ;
    USE SIGNAL ;
    PORT
      LAYER M5 ;
        RECT  35.952 0 35.976 0.084 ;
    END
  END t_fault[6]
  PIN t_fault[7]
    DIRECTION INPUT ;
    USE SIGNAL ;
    PORT
      LAYER M5 ;
        RECT  36.048 0 36.072 0.084 ;
    END
  END t_fault[7]
  PIN t_fault[8]
    DIRECTION INPUT ;
    USE SIGNAL ;
    PORT
      LAYER M5 ;
        RECT  36.144 0 36.168 0.084 ;
    END
  END t_fault[8]
  PIN t_fault[9]
    DIRECTION INPUT ;
    USE SIGNAL ;
    PORT
      LAYER M5 ;
        RECT  36.24 0 36.264 0.084 ;
    END
  END t_fault[9]
  PIN t_ready[0]
    DIRECTION INPUT ;
    USE SIGNAL ;
    PORT
      LAYER M5 ;
        RECT  37.584 0 37.608 0.084 ;
    END
  END t_ready[0]
  PIN t_ready[10]
    DIRECTION INPUT ;
    USE SIGNAL ;
    PORT
      LAYER M5 ;
        RECT  45.456 0 45.48 0.084 ;
    END
  END t_ready[10]
  PIN t_ready[11]
    DIRECTION INPUT ;
    USE SIGNAL ;
    PORT
      LAYER M5 ;
        RECT  45.552 0 45.576 0.084 ;
    END
  END t_ready[11]
  PIN t_ready[12]
    DIRECTION INPUT ;
    USE SIGNAL ;
    PORT
      LAYER M5 ;
        RECT  45.648 0 45.672 0.084 ;
    END
  END t_ready[12]
  PIN t_ready[13]
    DIRECTION INPUT ;
    USE SIGNAL ;
    PORT
      LAYER M5 ;
        RECT  45.744 0 45.768 0.084 ;
    END
  END t_ready[13]
  PIN t_ready[1]
    DIRECTION INPUT ;
    USE SIGNAL ;
    PORT
      LAYER M5 ;
        RECT  37.68 0 37.704 0.084 ;
    END
  END t_ready[1]
  PIN t_ready[2]
    DIRECTION INPUT ;
    USE SIGNAL ;
    PORT
      LAYER M5 ;
        RECT  37.776 0 37.8 0.084 ;
    END
  END t_ready[2]
  PIN t_ready[3]
    DIRECTION INPUT ;
    USE SIGNAL ;
    PORT
      LAYER M5 ;
        RECT  37.872 0 37.896 0.084 ;
    END
  END t_ready[3]
  PIN t_ready[4]
    DIRECTION INPUT ;
    USE SIGNAL ;
    PORT
      LAYER M5 ;
        RECT  37.968 0 37.992 0.084 ;
    END
  END t_ready[4]
  PIN t_ready[5]
    DIRECTION INPUT ;
    USE SIGNAL ;
    PORT
      LAYER M5 ;
        RECT  38.064 0 38.088 0.084 ;
    END
  END t_ready[5]
  PIN t_ready[6]
    DIRECTION INPUT ;
    USE SIGNAL ;
    PORT
      LAYER M5 ;
        RECT  38.16 0 38.184 0.084 ;
    END
  END t_ready[6]
  PIN t_ready[7]
    DIRECTION INPUT ;
    USE SIGNAL ;
    PORT
      LAYER M5 ;
        RECT  38.256 0 38.28 0.084 ;
    END
  END t_ready[7]
  PIN t_ready[8]
    DIRECTION INPUT ;
    USE SIGNAL ;
    PORT
      LAYER M5 ;
        RECT  45.264 0 45.288 0.084 ;
    END
  END t_ready[8]
  PIN t_ready[9]
    DIRECTION INPUT ;
    USE SIGNAL ;
    PORT
      LAYER M5 ;
        RECT  45.36 0 45.384 0.084 ;
    END
  END t_ready[9]
  PIN VDD
    DIRECTION INOUT ;
    USE POWER ;
    PORT
      LAYER M5 ;
        RECT  61.992 2.151 62.112 66.969 ;
        RECT  56.592 2.151 56.712 66.969 ;
        RECT  51.192 2.151 51.312 66.969 ;
        RECT  45.792 2.151 45.912 66.969 ;
        RECT  40.392 2.151 40.512 66.969 ;
        RECT  34.992 2.151 35.112 66.969 ;
        RECT  29.592 2.151 29.712 66.969 ;
        RECT  24.192 2.151 24.312 66.969 ;
        RECT  18.792 2.151 18.912 66.969 ;
        RECT  13.392 2.151 13.512 66.969 ;
        RECT  7.992 2.151 8.112 66.969 ;
        RECT  2.592 2.151 2.712 66.969 ;
    END
  END VDD
  PIN VSS
    DIRECTION INOUT ;
    USE GROUND ;
    PORT
      LAYER M5 ;
        RECT  61.8 2.137 61.92 66.983 ;
        RECT  56.4 2.137 56.52 66.983 ;
        RECT  51 2.137 51.12 66.983 ;
        RECT  45.6 2.137 45.72 66.983 ;
        RECT  40.2 2.137 40.32 66.983 ;
        RECT  34.8 2.137 34.92 66.983 ;
        RECT  29.4 2.137 29.52 66.983 ;
        RECT  24 2.137 24.12 66.983 ;
        RECT  18.6 2.137 18.72 66.983 ;
        RECT  13.2 2.137 13.32 66.983 ;
        RECT  7.8 2.137 7.92 66.983 ;
        RECT  2.4 2.137 2.52 66.983 ;
    END
  END VSS
  # OT_OBS_CLOSED layer=M5 d_um=1.536 added=59
  OBS
    LAYER RVTN ;
     RECT  2.16 2.16 66.96 2.295 ;
     RECT  2.16 2.565 66.96 2.835 ;
     RECT  2.16 3.105 66.96 3.375 ;
     RECT  2.16 3.645 66.96 3.915 ;
     RECT  2.16 4.185 66.96 4.455 ;
     RECT  2.16 4.725 66.96 4.995 ;
     RECT  2.16 5.265 66.96 5.535 ;
     RECT  2.16 5.805 66.96 6.075 ;
     RECT  2.16 6.345 66.96 6.615 ;
     RECT  2.16 6.885 66.96 7.155 ;
     RECT  2.16 7.425 66.96 7.695 ;
     RECT  2.16 7.965 66.96 8.235 ;
     RECT  2.16 8.505 66.96 8.775 ;
     RECT  2.16 9.045 66.96 9.315 ;
     RECT  2.16 9.585 66.96 9.855 ;
     RECT  2.16 10.125 66.96 10.395 ;
     RECT  2.16 10.665 66.96 10.935 ;
     RECT  2.16 11.205 66.96 11.475 ;
     RECT  2.16 11.745 66.96 12.015 ;
     RECT  2.16 12.285 66.96 12.555 ;
     RECT  2.16 12.825 66.96 13.095 ;
     RECT  2.16 13.365 66.96 13.635 ;
     RECT  2.16 13.905 66.96 14.175 ;
     RECT  2.16 14.445 66.96 14.715 ;
     RECT  2.16 14.985 66.96 15.255 ;
     RECT  2.16 15.525 66.96 15.795 ;
     RECT  2.16 16.065 66.96 16.335 ;
     RECT  2.16 16.605 66.96 16.875 ;
     RECT  2.16 17.145 66.96 17.415 ;
     RECT  2.16 17.685 66.96 17.955 ;
     RECT  2.16 18.225 66.96 18.495 ;
     RECT  2.16 18.765 66.96 19.035 ;
     RECT  2.16 19.305 66.96 19.575 ;
     RECT  2.16 19.845 66.96 20.115 ;
     RECT  2.16 20.385 66.96 20.655 ;
     RECT  2.16 20.925 66.96 21.195 ;
     RECT  2.16 21.465 66.96 21.735 ;
     RECT  2.16 22.005 66.96 22.275 ;
     RECT  2.16 22.545 66.96 22.815 ;
     RECT  2.16 23.085 66.96 23.355 ;
     RECT  2.16 23.625 66.96 23.895 ;
     RECT  2.16 24.165 66.96 24.435 ;
     RECT  2.16 24.705 66.96 24.975 ;
     RECT  2.16 25.245 66.96 25.515 ;
     RECT  2.16 25.785 66.96 26.055 ;
     RECT  2.16 26.325 66.96 26.595 ;
     RECT  2.16 26.865 66.96 27.135 ;
     RECT  2.16 27.405 66.96 27.675 ;
     RECT  2.16 27.945 66.96 28.215 ;
     RECT  2.16 28.485 66.96 28.755 ;
     RECT  2.16 29.025 66.96 29.295 ;
     RECT  2.16 29.565 66.96 29.835 ;
     RECT  2.16 30.105 66.96 30.375 ;
     RECT  2.16 30.645 66.96 30.915 ;
     RECT  2.16 31.185 66.96 31.455 ;
     RECT  2.16 31.725 66.96 31.995 ;
     RECT  2.16 32.265 66.96 32.535 ;
     RECT  2.16 32.805 66.96 33.075 ;
     RECT  2.16 33.345 66.96 33.615 ;
     RECT  2.16 33.885 66.96 34.155 ;
     RECT  2.16 34.425 66.96 34.695 ;
     RECT  2.16 34.965 66.96 35.235 ;
     RECT  2.16 35.505 66.96 35.775 ;
     RECT  2.16 36.045 66.96 36.315 ;
     RECT  2.16 36.585 66.96 36.855 ;
     RECT  2.16 37.125 66.96 37.395 ;
     RECT  2.16 37.665 66.96 37.935 ;
     RECT  2.16 38.205 66.96 38.475 ;
     RECT  2.16 38.745 66.96 39.015 ;
     RECT  2.16 39.285 66.96 39.555 ;
     RECT  2.16 39.825 66.96 40.095 ;
     RECT  2.16 40.365 66.96 40.635 ;
     RECT  2.16 40.905 66.96 41.175 ;
     RECT  2.16 41.445 66.96 41.715 ;
     RECT  2.16 41.985 66.96 42.255 ;
     RECT  2.16 42.525 66.96 42.795 ;
     RECT  2.16 43.065 66.96 43.335 ;
     RECT  2.16 43.605 66.96 43.875 ;
     RECT  2.16 44.145 66.96 44.415 ;
     RECT  2.16 44.685 66.96 44.955 ;
     RECT  2.16 45.225 66.96 45.495 ;
     RECT  2.16 45.765 66.96 46.035 ;
     RECT  2.16 46.305 66.96 46.575 ;
     RECT  2.16 46.845 66.96 47.115 ;
     RECT  2.16 47.385 66.96 47.655 ;
     RECT  2.16 47.925 66.96 48.195 ;
     RECT  2.16 48.465 66.96 48.735 ;
     RECT  2.16 49.005 66.96 49.275 ;
     RECT  2.16 49.545 66.96 49.815 ;
     RECT  2.16 50.085 66.96 50.355 ;
     RECT  2.16 50.625 66.96 50.895 ;
     RECT  2.16 51.165 66.96 51.435 ;
     RECT  2.16 51.705 66.96 51.975 ;
     RECT  2.16 52.245 66.96 52.515 ;
     RECT  2.16 52.785 66.96 53.055 ;
     RECT  2.16 53.325 66.96 53.595 ;
     RECT  2.16 53.865 66.96 54.135 ;
     RECT  2.16 54.405 66.96 54.675 ;
     RECT  2.16 54.945 66.96 55.215 ;
     RECT  2.16 55.485 66.96 55.755 ;
     RECT  2.16 56.025 66.96 56.295 ;
     RECT  2.16 56.565 66.96 56.835 ;
     RECT  2.16 57.105 66.96 57.375 ;
     RECT  2.16 57.645 66.96 57.915 ;
     RECT  2.16 58.185 66.96 58.455 ;
     RECT  2.16 58.725 66.96 58.995 ;
     RECT  2.16 59.265 66.96 59.535 ;
     RECT  2.16 59.805 66.96 60.075 ;
     RECT  2.16 60.345 66.96 60.615 ;
     RECT  2.16 60.885 66.96 61.155 ;
     RECT  2.16 61.425 66.96 61.695 ;
     RECT  2.16 61.965 66.96 62.235 ;
     RECT  2.16 62.505 66.96 62.775 ;
     RECT  2.16 63.045 66.96 63.315 ;
     RECT  2.16 63.585 66.96 63.855 ;
     RECT  2.16 64.125 66.96 64.395 ;
     RECT  2.16 64.665 66.96 64.935 ;
     RECT  2.16 65.205 66.96 65.475 ;
     RECT  2.16 65.745 66.96 66.015 ;
     RECT  2.16 66.285 66.96 66.555 ;
     RECT  2.16 66.825 66.96 66.96 ;
    LAYER RVTP ;
     RECT  2.16 2.295 66.96 2.565 ;
     RECT  2.16 2.835 66.96 3.105 ;
     RECT  2.16 3.375 66.96 3.645 ;
     RECT  2.16 3.915 66.96 4.185 ;
     RECT  2.16 4.455 66.96 4.725 ;
     RECT  2.16 4.995 66.96 5.265 ;
     RECT  2.16 5.535 66.96 5.805 ;
     RECT  2.16 6.075 66.96 6.345 ;
     RECT  2.16 6.615 66.96 6.885 ;
     RECT  2.16 7.155 66.96 7.425 ;
     RECT  2.16 7.695 66.96 7.965 ;
     RECT  2.16 8.235 66.96 8.505 ;
     RECT  2.16 8.775 66.96 9.045 ;
     RECT  2.16 9.315 66.96 9.585 ;
     RECT  2.16 9.855 66.96 10.125 ;
     RECT  2.16 10.395 66.96 10.665 ;
     RECT  2.16 10.935 66.96 11.205 ;
     RECT  2.16 11.475 66.96 11.745 ;
     RECT  2.16 12.015 66.96 12.285 ;
     RECT  2.16 12.555 66.96 12.825 ;
     RECT  2.16 13.095 66.96 13.365 ;
     RECT  2.16 13.635 66.96 13.905 ;
     RECT  2.16 14.175 66.96 14.445 ;
     RECT  2.16 14.715 66.96 14.985 ;
     RECT  2.16 15.255 66.96 15.525 ;
     RECT  2.16 15.795 66.96 16.065 ;
     RECT  2.16 16.335 66.96 16.605 ;
     RECT  2.16 16.875 66.96 17.145 ;
     RECT  2.16 17.415 66.96 17.685 ;
     RECT  2.16 17.955 66.96 18.225 ;
     RECT  2.16 18.495 66.96 18.765 ;
     RECT  2.16 19.035 66.96 19.305 ;
     RECT  2.16 19.575 66.96 19.845 ;
     RECT  2.16 20.115 66.96 20.385 ;
     RECT  2.16 20.655 66.96 20.925 ;
     RECT  2.16 21.195 66.96 21.465 ;
     RECT  2.16 21.735 66.96 22.005 ;
     RECT  2.16 22.275 66.96 22.545 ;
     RECT  2.16 22.815 66.96 23.085 ;
     RECT  2.16 23.355 66.96 23.625 ;
     RECT  2.16 23.895 66.96 24.165 ;
     RECT  2.16 24.435 66.96 24.705 ;
     RECT  2.16 24.975 66.96 25.245 ;
     RECT  2.16 25.515 66.96 25.785 ;
     RECT  2.16 26.055 66.96 26.325 ;
     RECT  2.16 26.595 66.96 26.865 ;
     RECT  2.16 27.135 66.96 27.405 ;
     RECT  2.16 27.675 66.96 27.945 ;
     RECT  2.16 28.215 66.96 28.485 ;
     RECT  2.16 28.755 66.96 29.025 ;
     RECT  2.16 29.295 66.96 29.565 ;
     RECT  2.16 29.835 66.96 30.105 ;
     RECT  2.16 30.375 66.96 30.645 ;
     RECT  2.16 30.915 66.96 31.185 ;
     RECT  2.16 31.455 66.96 31.725 ;
     RECT  2.16 31.995 66.96 32.265 ;
     RECT  2.16 32.535 66.96 32.805 ;
     RECT  2.16 33.075 66.96 33.345 ;
     RECT  2.16 33.615 66.96 33.885 ;
     RECT  2.16 34.155 66.96 34.425 ;
     RECT  2.16 34.695 66.96 34.965 ;
     RECT  2.16 35.235 66.96 35.505 ;
     RECT  2.16 35.775 66.96 36.045 ;
     RECT  2.16 36.315 66.96 36.585 ;
     RECT  2.16 36.855 66.96 37.125 ;
     RECT  2.16 37.395 66.96 37.665 ;
     RECT  2.16 37.935 66.96 38.205 ;
     RECT  2.16 38.475 66.96 38.745 ;
     RECT  2.16 39.015 66.96 39.285 ;
     RECT  2.16 39.555 66.96 39.825 ;
     RECT  2.16 40.095 66.96 40.365 ;
     RECT  2.16 40.635 66.96 40.905 ;
     RECT  2.16 41.175 66.96 41.445 ;
     RECT  2.16 41.715 66.96 41.985 ;
     RECT  2.16 42.255 66.96 42.525 ;
     RECT  2.16 42.795 66.96 43.065 ;
     RECT  2.16 43.335 66.96 43.605 ;
     RECT  2.16 43.875 66.96 44.145 ;
     RECT  2.16 44.415 66.96 44.685 ;
     RECT  2.16 44.955 66.96 45.225 ;
     RECT  2.16 45.495 66.96 45.765 ;
     RECT  2.16 46.035 66.96 46.305 ;
     RECT  2.16 46.575 66.96 46.845 ;
     RECT  2.16 47.115 66.96 47.385 ;
     RECT  2.16 47.655 66.96 47.925 ;
     RECT  2.16 48.195 66.96 48.465 ;
     RECT  2.16 48.735 66.96 49.005 ;
     RECT  2.16 49.275 66.96 49.545 ;
     RECT  2.16 49.815 66.96 50.085 ;
     RECT  2.16 50.355 66.96 50.625 ;
     RECT  2.16 50.895 66.96 51.165 ;
     RECT  2.16 51.435 66.96 51.705 ;
     RECT  2.16 51.975 66.96 52.245 ;
     RECT  2.16 52.515 66.96 52.785 ;
     RECT  2.16 53.055 66.96 53.325 ;
     RECT  2.16 53.595 66.96 53.865 ;
     RECT  2.16 54.135 66.96 54.405 ;
     RECT  2.16 54.675 66.96 54.945 ;
     RECT  2.16 55.215 66.96 55.485 ;
     RECT  2.16 55.755 66.96 56.025 ;
     RECT  2.16 56.295 66.96 56.565 ;
     RECT  2.16 56.835 66.96 57.105 ;
     RECT  2.16 57.375 66.96 57.645 ;
     RECT  2.16 57.915 66.96 58.185 ;
     RECT  2.16 58.455 66.96 58.725 ;
     RECT  2.16 58.995 66.96 59.265 ;
     RECT  2.16 59.535 66.96 59.805 ;
     RECT  2.16 60.075 66.96 60.345 ;
     RECT  2.16 60.615 66.96 60.885 ;
     RECT  2.16 61.155 66.96 61.425 ;
     RECT  2.16 61.695 66.96 61.965 ;
     RECT  2.16 62.235 66.96 62.505 ;
     RECT  2.16 62.775 66.96 63.045 ;
     RECT  2.16 63.315 66.96 63.585 ;
     RECT  2.16 63.855 66.96 64.125 ;
     RECT  2.16 64.395 66.96 64.665 ;
     RECT  2.16 64.935 66.96 65.205 ;
     RECT  2.16 65.475 66.96 65.745 ;
     RECT  2.16 66.015 66.96 66.285 ;
     RECT  2.16 66.555 66.96 66.825 ;
    LAYER M1 ;
     RECT  2.16 2.151 66.96 66.969 ;
    LAYER M2 ;
     RECT  0.103 48.366 0.175 48.456 ;
     RECT  0.103 21.402 0.203 21.42 ;
     RECT  0.103 23.796 0.203 23.814 ;
     RECT  0.103 25.758 0.203 25.776 ;
     RECT  0.103 27.072 0.203 27.774 ;
     RECT  0.103 31.23 0.203 31.914 ;
     RECT  0.103 33.93 0.203 33.948 ;
     RECT  0.103 34.776 0.203 34.794 ;
     RECT  0.103 35.712 0.203 35.73 ;
     RECT  0.103 38.412 0.203 38.43 ;
     RECT  0.103 40.644 0.203 40.662 ;
     RECT  0.103 41.922 0.203 42.174 ;
     RECT  0.103 44.19 0.203 44.91 ;
     RECT  0.103 46.08 0.203 46.098 ;
     RECT  0.103 51.21 0.203 51.228 ;
     RECT  0.203 44.892 0.239 44.91 ;
     RECT  0.175 48.366 0.311 49.104 ;
     RECT  0.247 26.802 0.347 26.82 ;
     RECT  0.211 32.976 0.535 33.066 ;
     RECT  0.103 37.566 0.535 37.584 ;
     RECT  0.211 42.696 0.535 43.164 ;
     RECT  0.535 22.716 0.635 22.914 ;
     RECT  0.535 50.13 0.635 50.454 ;
     RECT  0.535 36.126 1.147 36.144 ;
     RECT  1.147 36.054 1.175 36.144 ;
     RECT  0.535 21.636 2.16 21.654 ;
     RECT  0.635 22.716 2.16 22.734 ;
     RECT  0.535 24.246 2.16 24.264 ;
     RECT  0.203 31.734 2.16 31.914 ;
     RECT  0.535 32.814 2.16 33.066 ;
     RECT  1.175 36.054 2.16 36.072 ;
     RECT  0.535 37.404 2.16 37.584 ;
     RECT  0.535 41.454 2.16 41.472 ;
     RECT  0.535 42.696 2.16 43.326 ;
     RECT  2.155 47.286 2.16 47.304 ;
     RECT  0.311 48.366 2.16 48.384 ;
     RECT  0.635 50.13 2.16 50.148 ;
     RECT  2.16 2.151 19.435 66.969 ;
     RECT  19.435 2.151 19.967 67.014 ;
     RECT  19.967 2.151 34.411 66.969 ;
     RECT  34.411 2.07 34.555 66.969 ;
     RECT  34.555 1.962 34.735 66.969 ;
     RECT  34.735 1.8 36.391 66.969 ;
     RECT  36.391 1.764 37.571 66.969 ;
     RECT  37.571 1.8 37.607 66.969 ;
     RECT  37.607 1.836 38.983 66.969 ;
     RECT  38.983 1.152 39.047 66.969 ;
     RECT  39.047 1.152 39.119 1.17 ;
     RECT  39.047 2.034 42.107 66.969 ;
     RECT  42.107 2.07 44.023 66.969 ;
     RECT  44.023 2.034 45.067 66.969 ;
     RECT  45.067 1.998 45.103 66.969 ;
     RECT  45.103 1.962 47.219 66.969 ;
     RECT  47.219 1.998 48.479 66.969 ;
     RECT  48.479 2.106 48.695 66.969 ;
     RECT  48.695 2.151 66.96 66.969 ;
     RECT  66.96 19.746 67.811 51.534 ;
     RECT  67.811 19.746 67.847 23.886 ;
     RECT  67.811 24.714 67.847 40.464 ;
     RECT  67.811 41.382 68.351 51.534 ;
     RECT  67.847 19.746 68.387 21.654 ;
     RECT  67.847 24.714 68.387 38.304 ;
     RECT  68.351 41.49 68.387 51.534 ;
     RECT  68.387 19.746 68.423 19.764 ;
     RECT  68.387 24.714 68.423 26.964 ;
     RECT  68.387 27.756 68.423 29.124 ;
     RECT  68.387 30.006 68.423 31.68 ;
     RECT  68.387 32.616 68.423 38.304 ;
     RECT  67.847 39.06 68.423 40.464 ;
     RECT  68.387 41.688 68.423 42.75 ;
     RECT  68.387 43.65 68.423 47.646 ;
     RECT  68.387 21.51 68.459 21.654 ;
     RECT  68.423 24.714 68.459 25.506 ;
     RECT  68.423 26.334 68.459 26.784 ;
     RECT  68.423 39.366 68.459 40.464 ;
     RECT  68.423 42.732 68.459 42.75 ;
     RECT  68.459 25.254 68.963 25.506 ;
     RECT  68.387 50.094 68.963 51.534 ;
     RECT  68.963 25.254 68.999 25.308 ;
     RECT  68.459 26.334 68.999 26.586 ;
     RECT  68.423 27.756 68.999 28.044 ;
     RECT  68.423 33.048 68.999 36.684 ;
     RECT  68.423 41.688 68.999 41.814 ;
     RECT  68.423 43.65 68.999 47.448 ;
     RECT  68.387 20.628 69.035 20.646 ;
     RECT  68.459 21.546 69.035 21.654 ;
     RECT  67.847 22.752 69.035 23.886 ;
     RECT  68.999 25.254 69.035 25.272 ;
     RECT  68.999 26.334 69.035 26.514 ;
     RECT  68.999 27.756 69.035 27.774 ;
     RECT  68.423 29.106 69.035 29.124 ;
     RECT  68.423 30.456 69.035 31.68 ;
     RECT  68.999 33.048 69.035 35.19 ;
     RECT  68.999 36.054 69.035 36.684 ;
     RECT  68.423 37.566 69.035 38.304 ;
     RECT  68.459 40.446 69.035 40.464 ;
     RECT  68.999 41.688 69.035 41.706 ;
     RECT  68.999 43.686 69.035 46.368 ;
     RECT  68.999 47.124 69.035 47.448 ;
     RECT  68.387 48.402 69.035 49.104 ;
     RECT  68.963 50.094 69.035 51.426 ;
    LAYER M3 ;
     RECT  42.696 0.043 42.714 0.091 ;
     RECT  42.228 0.091 42.714 0.173 ;
     RECT  40.68 0.091 40.698 0.235 ;
     RECT  40.572 0.235 40.698 0.413 ;
     RECT  35.928 0.139 35.946 0.523 ;
     RECT  37.62 0.091 37.638 0.571 ;
     RECT  47.7 0.043 47.718 0.859 ;
     RECT  48.96 0.811 48.978 0.859 ;
     RECT  47.7 0.859 48.978 0.907 ;
     RECT  47.232 0.907 48.978 0.955 ;
     RECT  38.988 0.523 39.006 1.099 ;
     RECT  35.316 0.523 35.946 1.147 ;
     RECT  36.72 0.571 36.738 1.147 ;
     RECT  37.548 0.571 37.638 1.723 ;
     RECT  38.988 1.099 39.69 1.723 ;
     RECT  41.004 0.523 41.022 1.723 ;
     RECT  41.004 1.723 41.49 1.771 ;
     RECT  42.228 0.173 42.246 1.771 ;
     RECT  35.316 1.147 36.738 1.795 ;
     RECT  34.74 1.795 36.738 1.957 ;
     RECT  37.548 1.723 39.798 1.957 ;
     RECT  45.108 1.723 45.486 1.993 ;
     RECT  45.072 1.993 45.486 2.011 ;
     RECT  44.172 1.147 44.19 2.029 ;
     RECT  46.944 0.955 48.978 2.059 ;
     RECT  34.56 1.957 39.798 2.065 ;
     RECT  40.86 1.771 42.246 2.065 ;
     RECT  34.416 2.065 39.798 2.101 ;
     RECT  40.86 2.065 42.318 2.101 ;
     RECT  44.028 2.029 44.19 2.101 ;
     RECT  45.072 2.011 45.522 2.101 ;
     RECT  44.028 2.101 45.522 2.143 ;
     RECT  34.416 2.101 42.318 2.191 ;
     RECT  46.656 2.059 48.978 2.219 ;
     RECT  34.416 2.191 42.894 2.255 ;
     RECT  44.028 2.143 45.705 2.299 ;
     RECT  34.56 2.255 42.894 2.335 ;
     RECT  43.704 2.299 45.705 2.335 ;
     RECT  46.656 2.219 48.834 2.335 ;
     RECT  34.56 2.335 45.705 2.347 ;
     RECT  46.512 2.335 48.834 2.347 ;
     RECT  2.415 2.143 2.505 2.413 ;
     RECT  7.815 2.143 7.905 2.413 ;
     RECT  13.215 2.143 13.305 2.413 ;
     RECT  18.615 2.143 18.705 2.413 ;
     RECT  24.015 2.143 24.105 2.413 ;
     RECT  29.415 2.143 29.505 2.413 ;
     RECT  51.015 2.143 51.105 2.413 ;
     RECT  56.415 2.143 56.505 2.413 ;
     RECT  61.815 2.143 61.905 2.413 ;
     RECT  34.56 2.347 48.834 2.489 ;
     RECT  34.632 2.489 48.834 2.795 ;
     RECT  34.668 2.795 48.834 3.029 ;
     RECT  34.704 3.029 48.834 3.335 ;
     RECT  34.815 3.335 48.834 3.749 ;
     RECT  48.816 3.749 48.834 4.109 ;
     RECT  34.815 3.749 48.042 4.487 ;
     RECT  34.815 4.487 47.394 5.269 ;
     RECT  34.815 5.269 47.574 5.369 ;
     RECT  48.672 5.995 48.69 6.035 ;
     RECT  34.815 5.369 47.286 6.071 ;
     RECT  34.815 6.071 47.214 6.115 ;
     RECT  34.776 6.115 47.214 6.277 ;
     RECT  34.704 6.277 47.214 6.317 ;
     RECT  34.776 6.317 47.214 6.539 ;
     RECT  34.776 6.539 46.746 6.575 ;
     RECT  36.144 6.575 46.746 6.611 ;
     RECT  36.504 6.611 46.746 6.683 ;
     RECT  36.504 6.683 46.71 6.809 ;
     RECT  36.504 6.809 46.53 7.259 ;
     RECT  37.296 7.259 46.53 7.349 ;
     RECT  36.504 7.259 36.522 7.385 ;
     RECT  37.44 7.349 45.954 7.385 ;
     RECT  37.44 7.385 45.897 7.655 ;
     RECT  34.776 6.575 35.262 7.765 ;
     RECT  34.776 7.765 35.586 7.771 ;
     RECT  34.776 7.771 36.018 7.805 ;
     RECT  37.908 7.655 45.897 7.925 ;
     RECT  38.592 7.925 45.897 7.961 ;
     RECT  36 7.805 36.018 8.093 ;
     RECT  38.592 7.961 44.73 8.339 ;
     RECT  38.772 8.339 44.73 8.429 ;
     RECT  39.636 8.429 44.19 8.465 ;
     RECT  39.708 8.465 43.866 8.501 ;
     RECT  38.772 8.429 38.79 8.525 ;
     RECT  42.804 8.501 42.822 8.573 ;
     RECT  39.924 8.501 42.03 8.699 ;
     RECT  40.176 8.699 42.03 8.969 ;
     RECT  40.176 8.969 41.49 9.005 ;
     RECT  40.215 9.005 41.13 9.041 ;
     RECT  61.815 2.413 62.097 19.741 ;
     RECT  61.815 19.741 62.442 19.771 ;
     RECT  45.615 7.961 45.897 19.849 ;
     RECT  66.132 19.915 66.15 20.011 ;
     RECT  66.132 20.011 66.726 20.047 ;
     RECT  61.815 19.771 63.486 20.083 ;
     RECT  68.4 19.741 68.418 20.107 ;
     RECT  64.692 19.885 64.71 20.119 ;
     RECT  65.7 20.047 66.726 20.119 ;
     RECT  64.692 20.119 66.726 20.147 ;
     RECT  66.672 20.147 66.726 20.155 ;
     RECT  61.056 20.155 61.074 20.191 ;
     RECT  61.815 20.083 63.594 20.191 ;
     RECT  64.692 20.147 65.718 20.191 ;
     RECT  45.615 19.849 46.458 20.389 ;
     RECT  61.056 20.191 63.738 20.461 ;
     RECT  64.476 20.191 65.718 20.461 ;
     RECT  61.056 20.461 65.718 20.489 ;
     RECT  68.364 20.107 68.418 20.491 ;
     RECT  6.84 20.281 6.858 20.551 ;
     RECT  17.676 20.389 17.694 20.551 ;
     RECT  18.615 2.413 18.897 20.551 ;
     RECT  5.184 20.461 5.85 20.573 ;
     RECT  66.672 20.155 67.302 20.581 ;
     RECT  68.364 20.491 69.03 20.581 ;
     RECT  6.84 20.551 7.074 20.623 ;
     RECT  7.815 2.413 8.097 20.623 ;
     RECT  4.356 20.539 4.374 20.695 ;
     RECT  4.068 20.695 4.374 20.731 ;
     RECT  5.472 20.573 5.85 20.731 ;
     RECT  6.84 20.623 8.097 20.731 ;
     RECT  2.415 2.413 2.697 20.779 ;
     RECT  66.672 20.581 69.03 20.849 ;
     RECT  3.96 20.731 4.374 21.001 ;
     RECT  3.96 21.001 4.41 21.067 ;
     RECT  2.304 20.779 2.697 21.091 ;
     RECT  3.456 21.067 4.41 21.091 ;
     RECT  66.672 20.849 66.726 21.091 ;
     RECT  58.716 19.777 58.734 21.127 ;
     RECT  2.304 21.091 4.41 21.211 ;
     RECT  17.676 20.551 18.897 21.271 ;
     RECT  59.868 20.731 59.886 21.271 ;
     RECT  61.092 20.489 65.106 21.271 ;
     RECT  17.676 21.271 19.458 21.361 ;
     RECT  66.204 21.091 66.726 21.361 ;
     RECT  0.144 20.923 0.162 21.388 ;
     RECT  9.684 20.893 9.702 21.389 ;
     RECT  5.472 20.731 8.097 21.469 ;
     RECT  0.108 21.388 0.198 21.485 ;
     RECT  65.988 21.361 66.726 21.533 ;
     RECT  2.304 21.211 4.446 21.541 ;
     RECT  5.436 21.469 8.097 21.541 ;
     RECT  9.396 21.469 9.414 21.541 ;
     RECT  17.676 21.361 19.854 21.541 ;
     RECT  67.824 20.849 69.03 21.581 ;
     RECT  0.144 21.485 0.198 21.631 ;
     RECT  59.868 21.271 65.106 21.631 ;
     RECT  8.964 21.541 9.414 21.659 ;
     RECT  66.6 21.533 66.726 21.659 ;
     RECT  58.392 21.127 58.734 21.667 ;
     RECT  0.144 21.631 0.558 21.677 ;
     RECT  59.868 21.631 65.286 21.677 ;
     RECT  69.012 21.581 69.03 21.677 ;
     RECT  2.304 21.541 8.097 21.695 ;
     RECT  17.676 21.541 20.178 21.703 ;
     RECT  5.472 21.695 8.097 21.775 ;
     RECT  8.964 21.659 9.27 21.775 ;
     RECT  67.824 21.581 67.842 21.835 ;
     RECT  0.144 21.677 0.162 21.869 ;
     RECT  67.788 21.835 67.842 21.928 ;
     RECT  45.615 20.389 46.638 22.009 ;
     RECT  5.472 21.775 9.27 22.037 ;
     RECT  13.215 2.413 13.497 22.045 ;
     RECT  66.708 21.659 66.726 22.045 ;
     RECT  67.752 21.928 67.842 22.045 ;
     RECT  58.392 21.667 58.986 22.171 ;
     RECT  59.868 21.677 64.962 22.171 ;
     RECT  5.472 22.037 9.162 22.199 ;
     RECT  2.304 21.695 4.662 22.507 ;
     RECT  5.472 22.199 9.09 22.507 ;
     RECT  44.136 19.777 44.154 22.513 ;
     RECT  44.892 22.009 46.638 22.513 ;
     RECT  13.215 22.045 13.698 22.541 ;
     RECT  44.136 22.513 46.638 22.549 ;
     RECT  58.392 22.171 64.962 22.549 ;
     RECT  66.708 22.045 67.842 22.585 ;
     RECT  2.304 22.507 9.09 22.603 ;
     RECT  17.676 21.703 20.322 22.621 ;
     RECT  58.392 22.549 65.07 22.775 ;
     RECT  17.676 22.621 20.394 22.783 ;
     RECT  0.54 22.711 0.558 22.843 ;
     RECT  17.676 22.783 20.79 22.847 ;
     RECT  65.844 22.549 65.862 22.891 ;
     RECT  66.6 22.585 67.842 22.891 ;
     RECT  69.012 22.411 69.03 22.891 ;
     RECT  0.54 22.843 0.63 22.919 ;
     RECT  0.54 22.919 0.558 22.928 ;
     RECT  17.964 22.847 20.79 23.053 ;
     RECT  2.268 22.603 9.09 23.081 ;
     RECT  44.136 22.549 47.034 23.089 ;
     RECT  65.844 22.891 69.03 23.213 ;
     RECT  17.964 23.053 21.474 23.323 ;
     RECT  2.268 23.081 8.298 23.357 ;
     RECT  10.512 22.549 10.53 23.395 ;
     RECT  17.964 23.323 21.978 23.431 ;
     RECT  58.392 22.775 64.674 23.521 ;
     RECT  65.448 23.323 65.466 23.521 ;
     RECT  52.812 23.419 52.83 23.611 ;
     RECT  10.512 23.395 10.782 23.629 ;
     RECT  17.964 23.431 22.014 23.665 ;
     RECT  66.276 23.213 69.03 23.693 ;
     RECT  52.524 23.611 52.83 23.729 ;
     RECT  0.144 23.611 0.162 23.788 ;
     RECT  25.776 23.419 25.794 23.791 ;
     RECT  56.415 2.413 56.697 23.791 ;
     RECT  10.512 23.629 10.818 23.819 ;
     RECT  25.524 23.791 25.794 23.819 ;
     RECT  56.304 23.791 56.697 23.837 ;
     RECT  52.776 23.729 52.83 23.842 ;
     RECT  25.524 23.819 25.542 23.885 ;
     RECT  58.392 23.521 65.466 23.891 ;
     RECT  58.392 23.891 65.394 23.927 ;
     RECT  17.964 23.665 22.086 24.061 ;
     RECT  0.108 23.788 0.198 24.077 ;
     RECT  2.304 23.357 8.298 24.169 ;
     RECT  9.072 23.081 9.09 24.169 ;
     RECT  0.144 24.077 0.198 24.241 ;
     RECT  66.276 23.693 67.806 24.269 ;
     RECT  2.304 24.169 9.09 24.331 ;
     RECT  49.392 22.081 49.41 24.331 ;
     RECT  2.268 24.331 9.09 24.368 ;
     RECT  58.392 23.927 64.746 24.395 ;
     RECT  17.964 24.061 22.482 24.403 ;
     RECT  48.24 22.585 48.258 24.403 ;
     RECT  66.672 24.269 67.806 24.427 ;
     RECT  69.012 23.693 69.03 24.427 ;
     RECT  10.512 23.819 10.53 24.601 ;
     RECT  0.144 24.241 0.558 24.701 ;
     RECT  17.964 24.403 22.554 24.709 ;
     RECT  58.716 24.395 64.746 24.709 ;
     RECT  10.512 24.601 10.854 24.737 ;
     RECT  17.964 24.709 22.842 24.745 ;
     RECT  0.54 24.701 0.558 24.749 ;
     RECT  33.372 23.161 33.39 24.781 ;
     RECT  58.716 24.709 64.782 24.781 ;
     RECT  2.304 24.368 9.09 24.871 ;
     RECT  17.964 24.745 23.13 24.871 ;
     RECT  24.015 2.413 24.297 24.871 ;
     RECT  58.716 24.781 64.818 24.871 ;
     RECT  32.292 24.205 32.31 24.943 ;
     RECT  2.304 24.871 9.234 25.003 ;
     RECT  58.716 24.871 65.502 25.051 ;
     RECT  66.672 24.427 69.03 25.051 ;
     RECT  2.304 25.003 9.27 25.141 ;
     RECT  33.336 24.781 33.39 25.141 ;
     RECT  2.304 25.141 9.414 25.169 ;
     RECT  9.072 25.169 9.414 25.177 ;
     RECT  26.784 25.147 26.802 25.277 ;
     RECT  58.716 25.051 69.03 25.277 ;
     RECT  58.716 25.277 68.994 25.313 ;
     RECT  32.292 24.943 32.346 25.321 ;
     RECT  33.336 25.141 33.93 25.321 ;
     RECT  17.964 24.871 24.297 25.447 ;
     RECT  48.24 24.403 48.294 25.447 ;
     RECT  58.716 25.313 68.958 25.475 ;
     RECT  17.964 25.447 24.786 25.483 ;
     RECT  44.136 23.089 47.394 25.483 ;
     RECT  48.168 25.447 48.294 25.483 ;
     RECT  14.868 25.411 14.886 25.619 ;
     RECT  34.776 7.805 35.262 25.681 ;
     RECT  32.292 25.321 33.93 25.717 ;
     RECT  34.668 25.681 35.262 25.717 ;
     RECT  0.18 25.531 0.198 25.753 ;
     RECT  10.512 24.737 10.53 25.789 ;
     RECT  32.292 25.717 35.478 25.825 ;
     RECT  0.108 25.753 0.198 25.853 ;
     RECT  0.108 25.853 0.126 25.901 ;
     RECT  44.136 25.483 48.294 25.951 ;
     RECT  49.392 24.331 49.95 25.951 ;
     RECT  10.512 25.789 10.818 25.979 ;
     RECT  31.896 25.825 36.018 25.987 ;
     RECT  31.896 25.987 36.054 26.011 ;
     RECT  10.512 25.979 10.782 26.015 ;
     RECT  31.896 26.011 36.234 26.051 ;
     RECT  31.896 26.051 36.162 26.131 ;
     RECT  58.968 25.475 68.958 26.155 ;
     RECT  31.824 26.131 36.162 26.159 ;
     RECT  31.824 26.159 36.09 26.249 ;
     RECT  31.824 26.249 36.054 26.251 ;
     RECT  31.68 26.251 36.054 26.285 ;
     RECT  31.68 26.285 33.93 26.291 ;
     RECT  2.304 25.169 8.298 26.293 ;
     RECT  9.072 25.177 9.702 26.293 ;
     RECT  58.968 26.155 69.03 26.293 ;
     RECT  17.928 25.483 24.786 26.365 ;
     RECT  2.304 26.293 9.702 26.401 ;
     RECT  14.832 26.293 14.85 26.429 ;
     RECT  42.768 26.299 42.786 26.429 ;
     RECT  54.72 26.299 54.738 26.429 ;
     RECT  2.268 26.401 9.702 26.477 ;
     RECT  26.784 26.365 26.802 26.519 ;
     RECT  58.716 26.293 69.03 26.519 ;
     RECT  30.78 26.299 30.798 26.539 ;
     RECT  58.716 26.519 68.994 26.591 ;
     RECT  34.776 26.285 36.054 26.627 ;
     RECT  34.815 26.627 36.054 26.663 ;
     RECT  30.78 26.539 30.834 26.671 ;
     RECT  0.252 26.587 0.27 26.779 ;
     RECT  30.78 26.671 30.87 26.789 ;
     RECT  0.252 26.779 0.342 26.825 ;
     RECT  13.215 22.541 13.497 26.833 ;
     RECT  0.252 26.825 0.27 26.861 ;
     RECT  0.144 26.875 0.198 27.052 ;
     RECT  58.716 26.591 68.454 27.167 ;
     RECT  31.752 26.291 33.93 27.211 ;
     RECT  58.716 27.167 67.842 27.239 ;
     RECT  58.752 27.239 67.842 27.365 ;
     RECT  58.788 27.365 67.842 27.509 ;
     RECT  10.512 26.015 10.53 27.571 ;
     RECT  2.304 26.477 9.702 27.671 ;
     RECT  68.976 27.499 69.03 27.779 ;
     RECT  0.108 27.052 0.198 27.788 ;
     RECT  31.032 27.211 33.93 27.949 ;
     RECT  34.815 26.663 35.73 27.949 ;
     RECT  67.248 27.509 67.842 27.985 ;
     RECT  30.852 27.949 33.93 28.021 ;
     RECT  10.512 27.571 11.106 28.049 ;
     RECT  34.776 27.949 35.73 28.049 ;
     RECT  68.976 27.779 68.994 28.049 ;
     RECT  30.78 28.021 33.93 28.139 ;
     RECT  58.788 27.509 66.078 28.219 ;
     RECT  14.868 28.219 14.886 28.255 ;
     RECT  26.496 27.913 26.514 28.255 ;
     RECT  14.868 28.255 14.958 28.319 ;
     RECT  67.248 27.985 67.878 28.363 ;
     RECT  58.716 28.219 66.078 28.381 ;
     RECT  67.248 28.363 68.418 28.381 ;
     RECT  0.144 27.788 0.162 28.397 ;
     RECT  14.94 28.319 14.958 28.409 ;
     RECT  58.716 28.381 68.418 28.493 ;
     RECT  58.716 28.493 66.114 28.715 ;
     RECT  58.968 28.715 66.114 28.823 ;
     RECT  2.304 27.671 9.414 28.859 ;
     RECT  2.304 28.859 8.442 28.949 ;
     RECT  67.284 28.493 68.418 28.949 ;
     RECT  67.284 28.949 67.338 28.973 ;
     RECT  68.328 28.949 68.418 29.035 ;
     RECT  68.328 29.035 69.03 29.057 ;
     RECT  31.032 28.139 33.93 29.065 ;
     RECT  28.224 29.029 28.242 29.101 ;
     RECT  29.415 2.413 29.697 29.101 ;
     RECT  67.284 28.973 67.302 29.227 ;
     RECT  67.248 29.227 67.302 29.323 ;
     RECT  28.224 29.101 29.697 29.335 ;
     RECT  30.456 29.065 33.93 29.335 ;
     RECT  34.815 28.049 35.73 29.335 ;
     RECT  25.74 28.687 25.758 29.363 ;
     RECT  1.152 29.275 1.17 29.419 ;
     RECT  11.088 28.049 11.106 29.461 ;
     RECT  28.224 29.335 35.73 29.569 ;
     RECT  1.152 29.419 1.242 29.597 ;
     RECT  58.968 28.823 66.078 29.641 ;
     RECT  1.152 29.597 1.17 29.645 ;
     RECT  58.788 29.641 66.078 29.669 ;
     RECT  58.788 29.669 65.61 29.731 ;
     RECT  58.716 29.731 65.61 29.759 ;
     RECT  67.212 29.323 67.302 29.899 ;
     RECT  68.364 29.057 69.03 29.899 ;
     RECT  2.304 28.949 8.298 29.911 ;
     RECT  9.18 28.859 9.414 29.911 ;
     RECT  67.212 29.899 69.03 29.911 ;
     RECT  44.136 25.951 49.95 29.939 ;
     RECT  25.668 29.371 25.686 30.173 ;
     RECT  2.304 29.911 9.414 30.209 ;
     RECT  52.776 23.842 52.794 30.271 ;
     RECT  2.415 30.209 9.414 30.307 ;
     RECT  10.8 29.461 11.106 30.307 ;
     RECT  2.415 30.307 11.106 30.569 ;
     RECT  52.776 30.271 53.298 30.721 ;
     RECT  28.188 29.569 35.73 30.749 ;
     RECT  66.672 29.911 69.03 30.763 ;
     RECT  58.716 29.759 65.502 30.847 ;
     RECT  66.528 30.763 69.03 30.875 ;
     RECT  58.716 30.847 65.682 30.883 ;
     RECT  28.188 30.749 35.694 31.019 ;
     RECT  58.716 30.883 66.33 31.109 ;
     RECT  2.415 30.569 9.99 31.147 ;
     RECT  0.144 30.763 0.162 31.225 ;
     RECT  58.788 31.109 65.79 31.253 ;
     RECT  2.304 31.147 9.99 31.289 ;
     RECT  58.968 31.253 65.79 31.517 ;
     RECT  11.088 30.569 11.106 31.531 ;
     RECT  10.8 31.531 11.106 31.621 ;
     RECT  17.352 26.365 24.786 31.657 ;
     RECT  67.248 30.875 69.03 31.657 ;
     RECT  1.152 31.099 1.17 31.675 ;
     RECT  58.968 31.517 65.718 31.685 ;
     RECT  67.212 31.657 69.03 31.685 ;
     RECT  2.415 31.289 9.99 31.693 ;
     RECT  10.728 31.621 11.106 31.693 ;
     RECT  58.968 31.685 65.646 31.721 ;
     RECT  0.108 31.225 0.198 31.729 ;
     RECT  1.152 31.675 1.242 31.729 ;
     RECT  67.212 31.685 68.418 31.729 ;
     RECT  66.528 31.729 68.418 31.757 ;
     RECT  2.415 31.693 11.106 31.793 ;
     RECT  58.968 31.721 65.574 31.793 ;
     RECT  0.108 31.729 1.242 31.853 ;
     RECT  0.108 31.853 0.558 31.949 ;
     RECT  58.968 31.793 65.178 31.999 ;
     RECT  2.415 31.793 9.99 32.203 ;
     RECT  66.528 31.757 68.382 32.503 ;
     RECT  66.168 32.503 68.382 32.611 ;
     RECT  66.168 32.611 68.418 32.779 ;
     RECT  10.8 31.793 11.106 32.801 ;
     RECT  58.788 31.999 65.178 32.809 ;
     RECT  10.8 32.801 10.818 32.881 ;
     RECT  58.716 32.809 65.178 32.881 ;
     RECT  66.168 32.779 69.03 32.881 ;
     RECT  41.292 30.649 41.31 32.909 ;
     RECT  0.54 31.949 0.558 32.971 ;
     RECT  2.304 32.203 9.99 32.999 ;
     RECT  10.764 32.881 10.818 32.999 ;
     RECT  17.352 31.657 25.362 33.007 ;
     RECT  42.444 32.431 42.462 33.043 ;
     RECT  0.216 32.971 0.558 33.197 ;
     RECT  58.716 32.881 65.322 33.241 ;
     RECT  66.096 32.881 69.03 33.241 ;
     RECT  4.14 32.999 9.99 33.269 ;
     RECT  58.716 33.241 69.03 33.377 ;
     RECT  2.304 32.999 3.294 33.485 ;
     RECT  67.788 33.377 69.03 33.485 ;
     RECT  10.8 32.999 10.818 33.611 ;
     RECT  67.788 33.485 67.842 33.773 ;
     RECT  28.188 31.019 35.622 33.809 ;
     RECT  44.136 29.939 49.878 33.889 ;
     RECT  0.144 33.739 0.198 33.916 ;
     RECT  28.188 33.809 35.442 33.917 ;
     RECT  58.716 33.377 66.582 33.917 ;
     RECT  39.024 32.611 39.042 33.925 ;
     RECT  10.836 33.961 10.854 34.079 ;
     RECT  58.716 33.917 65.106 34.079 ;
     RECT  65.88 33.917 66.582 34.117 ;
     RECT  67.788 33.773 67.806 34.117 ;
     RECT  44.064 33.889 49.878 34.123 ;
     RECT  28.188 33.917 35.406 34.151 ;
     RECT  65.88 34.117 67.806 34.187 ;
     RECT  2.415 33.485 3.294 34.219 ;
     RECT  2.304 34.219 3.294 34.231 ;
     RECT  4.212 33.269 9.99 34.231 ;
     RECT  38.664 33.925 39.042 34.465 ;
     RECT  40.215 9.041 40.497 34.465 ;
     RECT  37.872 33.385 37.89 34.501 ;
     RECT  38.664 34.465 40.497 34.501 ;
     RECT  69.012 33.485 69.03 34.69 ;
     RECT  42.444 33.043 43.038 34.699 ;
     RECT  43.776 34.123 49.878 34.699 ;
     RECT  58.752 34.079 65.106 34.771 ;
     RECT  66.564 34.187 67.806 34.795 ;
     RECT  68.976 34.69 69.03 34.795 ;
     RECT  0.108 33.916 0.198 34.799 ;
     RECT  58.752 34.771 65.358 34.933 ;
     RECT  66.564 34.795 69.03 34.933 ;
     RECT  58.716 34.933 65.358 34.997 ;
     RECT  37.872 34.501 40.497 35.005 ;
     RECT  2.304 34.231 9.99 35.068 ;
     RECT  10.8 35.041 10.89 35.131 ;
     RECT  10.728 35.131 10.89 35.159 ;
     RECT  66.24 34.933 69.03 35.195 ;
     RECT  2.268 35.068 9.99 35.231 ;
     RECT  10.728 35.159 10.854 35.231 ;
     RECT  3.96 35.231 9.99 35.267 ;
     RECT  2.268 35.231 3.15 35.339 ;
     RECT  58.716 34.997 65.286 35.537 ;
     RECT  58.788 35.537 65.286 35.573 ;
     RECT  66.24 35.195 68.994 35.671 ;
     RECT  0.144 34.799 0.162 35.692 ;
     RECT  51.015 2.413 51.297 35.707 ;
     RECT  10.836 35.231 10.854 35.771 ;
     RECT  0.108 35.692 0.198 35.885 ;
     RECT  66.204 35.671 68.994 35.947 ;
     RECT  59.004 35.573 65.286 35.977 ;
     RECT  2.304 35.339 3.15 36.085 ;
     RECT  3.996 35.267 9.99 36.085 ;
     RECT  1.152 36.049 1.17 36.121 ;
     RECT  59.004 35.977 65.358 36.211 ;
     RECT  66.204 35.947 69.03 36.211 ;
     RECT  42.444 34.699 49.878 36.283 ;
     RECT  10.8 36.211 10.818 36.311 ;
     RECT  37.872 35.005 40.842 36.319 ;
     RECT  41.688 35.851 41.706 36.319 ;
     RECT  2.304 36.085 9.99 36.509 ;
     RECT  59.004 36.211 69.03 36.509 ;
     RECT  59.004 36.509 67.806 36.589 ;
     RECT  58.896 36.589 67.806 36.661 ;
     RECT  0.54 36.121 1.17 36.715 ;
     RECT  52.704 30.721 53.298 36.779 ;
     RECT  0.54 36.715 1.278 36.845 ;
     RECT  0.54 36.845 0.558 36.859 ;
     RECT  10.764 36.931 10.782 37.129 ;
     RECT  58.716 36.661 67.806 37.319 ;
     RECT  10.764 37.129 10.818 37.327 ;
     RECT  58.788 37.319 67.806 37.327 ;
     RECT  69.012 36.509 69.03 37.327 ;
     RECT  37.872 36.319 41.706 37.363 ;
     RECT  58.788 37.327 69.03 37.391 ;
     RECT  10.764 37.327 10.926 37.399 ;
     RECT  2.304 36.509 3.294 37.435 ;
     RECT  4.032 36.509 9.99 37.435 ;
     RECT  42.444 36.283 50.202 37.463 ;
     RECT  10.764 37.399 10.962 37.499 ;
     RECT  0.144 36.859 0.558 37.561 ;
     RECT  10.764 37.499 10.782 37.589 ;
     RECT  37.656 37.363 41.706 37.597 ;
     RECT  59.04 37.391 69.03 37.709 ;
     RECT  0.108 37.561 0.558 37.805 ;
     RECT  59.04 37.709 66.726 37.805 ;
     RECT  37.656 37.597 41.886 37.859 ;
     RECT  59.04 37.805 66.69 37.931 ;
     RECT  59.04 37.931 66.51 38.129 ;
     RECT  2.304 37.435 9.99 38.189 ;
     RECT  59.04 38.129 66.078 38.201 ;
     RECT  67.788 37.709 69.03 38.201 ;
     RECT  37.8 37.859 41.886 38.245 ;
     RECT  42.624 37.463 50.202 38.245 ;
     RECT  59.04 38.201 66.006 38.245 ;
     RECT  67.824 38.201 69.03 38.285 ;
     RECT  58.716 38.245 66.006 38.309 ;
     RECT  69.012 38.285 69.03 38.309 ;
     RECT  65.988 38.309 66.006 38.399 ;
     RECT  17.352 33.007 25.398 38.479 ;
     RECT  26.496 28.255 27.054 38.507 ;
     RECT  51.015 35.707 51.894 38.507 ;
     RECT  0.108 37.805 0.198 38.669 ;
     RECT  26.784 38.507 27.054 38.669 ;
     RECT  0.18 38.669 0.198 38.717 ;
     RECT  2.304 38.189 3.33 38.923 ;
     RECT  2.232 38.923 3.33 38.983 ;
     RECT  4.14 38.189 9.99 38.983 ;
     RECT  67.824 38.285 67.842 39.055 ;
     RECT  67.824 39.055 68.418 39.115 ;
     RECT  2.232 38.983 9.99 39.119 ;
     RECT  58.716 38.309 65.25 39.119 ;
     RECT  2.268 39.119 9.99 39.212 ;
     RECT  67.788 39.115 68.418 39.245 ;
     RECT  2.304 39.212 9.99 39.317 ;
     RECT  7.164 39.317 9.99 39.361 ;
     RECT  10.8 39.325 10.818 39.361 ;
     RECT  68.328 39.245 68.418 39.361 ;
     RECT  56.415 23.837 56.697 39.451 ;
     RECT  66.672 39.325 66.69 39.451 ;
     RECT  56.304 39.451 56.697 39.488 ;
     RECT  66.672 39.451 67.302 39.515 ;
     RECT  26.856 38.669 27.054 39.559 ;
     RECT  17.352 38.479 25.47 39.623 ;
     RECT  7.164 39.361 10.818 39.629 ;
     RECT  28.188 34.151 35.334 39.865 ;
     RECT  2.304 39.317 6.282 39.965 ;
     RECT  58.716 39.119 65.142 40.171 ;
     RECT  65.88 40.135 65.898 40.171 ;
     RECT  68.328 39.361 68.454 40.171 ;
     RECT  7.236 39.629 10.818 40.261 ;
     RECT  58.716 40.171 65.898 40.261 ;
     RECT  66.708 39.515 67.302 40.261 ;
     RECT  58.716 40.261 67.302 40.267 ;
     RECT  68.328 40.171 69.03 40.267 ;
     RECT  2.304 39.965 6.246 40.289 ;
     RECT  7.236 40.261 10.854 40.361 ;
     RECT  58.716 40.267 69.03 40.469 ;
     RECT  4.32 40.289 6.246 40.493 ;
     RECT  2.304 40.289 3.51 40.559 ;
     RECT  26.784 39.559 27.054 40.559 ;
     RECT  7.236 40.361 10.818 40.631 ;
     RECT  0.144 39.883 0.162 40.636 ;
     RECT  4.356 40.493 6.246 40.667 ;
     RECT  7.236 40.631 10.53 40.801 ;
     RECT  58.716 40.469 68.382 40.829 ;
     RECT  0.108 40.636 0.198 40.877 ;
     RECT  66.204 40.829 68.382 40.877 ;
     RECT  4.428 40.667 6.246 41.071 ;
     RECT  7.164 40.801 10.53 41.071 ;
     RECT  2.304 40.559 3.474 41.099 ;
     RECT  67.248 40.877 68.382 41.323 ;
     RECT  0.144 40.877 0.198 41.449 ;
     RECT  26.784 40.559 26.946 41.477 ;
     RECT  67.248 41.323 69.03 41.549 ;
     RECT  4.428 41.071 10.53 41.611 ;
     RECT  56.415 39.488 56.697 41.611 ;
     RECT  0.144 41.449 0.558 41.645 ;
     RECT  4.428 41.611 10.638 41.647 ;
     RECT  4.428 41.647 10.782 41.683 ;
     RECT  67.824 41.549 69.03 41.711 ;
     RECT  4.428 41.683 10.818 41.719 ;
     RECT  66.204 40.877 66.366 41.755 ;
     RECT  4.32 41.719 10.818 41.791 ;
     RECT  17.928 39.623 25.47 41.791 ;
     RECT  0.144 41.645 0.198 41.803 ;
     RECT  4.284 41.791 10.818 41.803 ;
     RECT  67.824 41.711 68.994 41.819 ;
     RECT  58.716 40.829 65.142 41.953 ;
     RECT  66.096 41.755 66.366 41.953 ;
     RECT  54.792 41.881 54.81 41.981 ;
     RECT  2.304 41.099 3.33 42.025 ;
     RECT  58.716 41.953 66.366 42.025 ;
     RECT  4.212 41.803 10.818 42.089 ;
     RECT  26.784 41.477 26.874 42.089 ;
     RECT  56.304 41.611 56.697 42.089 ;
     RECT  67.824 41.819 68.418 42.125 ;
     RECT  2.304 42.025 3.438 42.151 ;
     RECT  4.212 42.089 10.53 42.151 ;
     RECT  54.72 42.025 54.738 42.179 ;
     RECT  0.108 41.803 0.198 42.221 ;
     RECT  0.18 42.221 0.198 42.269 ;
     RECT  26.784 42.089 26.802 42.287 ;
     RECT  58.716 42.025 66.474 42.331 ;
     RECT  17.928 41.791 25.686 42.359 ;
     RECT  2.304 42.151 10.53 42.557 ;
     RECT  67.86 42.125 68.418 42.667 ;
     RECT  58.716 42.331 66.726 42.719 ;
     RECT  66.132 42.719 66.726 42.727 ;
     RECT  67.86 42.667 68.454 42.755 ;
     RECT  67.86 42.755 68.418 42.797 ;
     RECT  12.24 24.169 12.258 42.827 ;
     RECT  58.716 42.719 65.034 42.827 ;
     RECT  66.132 42.727 66.87 42.893 ;
     RECT  66.852 42.893 66.87 42.899 ;
     RECT  0.216 42.691 0.234 42.952 ;
     RECT  67.86 42.797 68.382 42.955 ;
     RECT  0.216 42.952 0.27 42.961 ;
     RECT  6.12 42.557 10.53 42.961 ;
     RECT  67.788 42.955 68.382 43.085 ;
     RECT  6.12 42.961 10.782 43.097 ;
     RECT  67.788 43.085 67.842 43.105 ;
     RECT  9.936 43.097 10.782 43.141 ;
     RECT  0.216 42.961 0.342 43.181 ;
     RECT  56.415 42.089 56.697 43.243 ;
     RECT  9.936 43.141 10.926 43.259 ;
     RECT  6.12 43.097 9.054 43.295 ;
     RECT  56.304 43.243 56.697 43.295 ;
     RECT  28.152 39.865 35.334 43.339 ;
     RECT  59.544 42.827 65.034 43.367 ;
     RECT  2.304 42.557 5.382 43.411 ;
     RECT  6.12 43.295 8.622 43.411 ;
     RECT  28.152 43.339 35.91 43.411 ;
     RECT  61.776 43.367 65.034 43.501 ;
     RECT  28.152 43.411 36.306 43.537 ;
     RECT  0.54 43.303 0.558 43.565 ;
     RECT  9.936 43.259 10.854 43.565 ;
     RECT  17.928 42.359 25.47 43.601 ;
     RECT  13.215 26.833 13.95 43.709 ;
     RECT  61.776 43.501 65.106 43.807 ;
     RECT  67.248 43.105 67.842 43.915 ;
     RECT  68.976 43.531 69.03 43.915 ;
     RECT  66.168 43.915 66.186 43.951 ;
     RECT  2.304 43.411 8.622 44.041 ;
     RECT  2.304 44.041 8.73 44.069 ;
     RECT  66.06 43.951 66.186 44.069 ;
     RECT  4.068 44.069 8.73 44.077 ;
     RECT  54.72 43.951 54.738 44.105 ;
     RECT  9.936 43.565 10.818 44.141 ;
     RECT  2.304 44.069 3.294 44.149 ;
     RECT  28.152 43.537 36.486 44.149 ;
     RECT  59.544 43.367 61.038 44.149 ;
     RECT  61.776 43.807 65.178 44.149 ;
     RECT  67.248 43.915 69.03 44.149 ;
     RECT  0.144 44.011 0.198 44.185 ;
     RECT  26.748 44.113 26.766 44.221 ;
     RECT  66.672 44.149 69.03 44.249 ;
     RECT  2.268 44.149 3.294 44.333 ;
     RECT  59.544 44.149 65.898 44.339 ;
     RECT  9.936 44.141 10.53 44.375 ;
     RECT  4.068 44.077 8.802 44.419 ;
     RECT  4.068 44.419 9.198 44.491 ;
     RECT  9.936 44.375 9.954 44.491 ;
     RECT  18.615 43.601 25.47 44.581 ;
     RECT  26.676 44.221 26.766 44.609 ;
     RECT  28.152 44.149 36.702 44.725 ;
     RECT  52.704 36.779 52.722 44.753 ;
     RECT  0.108 44.185 0.198 44.779 ;
     RECT  26.676 44.609 26.694 44.789 ;
     RECT  58.716 42.827 58.806 44.789 ;
     RECT  58.716 44.789 58.734 44.879 ;
     RECT  28.152 44.725 36.846 44.887 ;
     RECT  37.8 38.245 50.202 44.887 ;
     RECT  0.108 44.779 0.342 44.909 ;
     RECT  0.108 44.909 0.234 44.915 ;
     RECT  0.216 44.915 0.234 44.957 ;
     RECT  2.304 44.333 3.294 44.971 ;
     RECT  4.068 44.491 9.954 44.971 ;
     RECT  61.815 44.339 65.898 44.971 ;
     RECT  67.212 44.249 69.03 44.987 ;
     RECT  18.615 44.581 25.866 45.005 ;
     RECT  61.815 44.971 65.934 45.023 ;
     RECT  59.544 44.339 61.038 45.112 ;
     RECT  61.815 45.023 65.466 45.112 ;
     RECT  2.304 44.971 9.954 45.149 ;
     RECT  59.544 45.112 65.466 45.149 ;
     RECT  2.304 45.149 9.45 45.257 ;
     RECT  18.615 45.005 25.83 45.257 ;
     RECT  56.415 43.295 56.697 45.391 ;
     RECT  61.815 45.149 65.466 45.419 ;
     RECT  56.415 45.391 57.042 45.427 ;
     RECT  56.415 45.427 57.186 45.527 ;
     RECT  2.304 45.257 9.378 45.563 ;
     RECT  56.415 45.527 57.114 45.563 ;
     RECT  56.415 45.563 57.042 45.599 ;
     RECT  18.615 45.257 25.722 45.689 ;
     RECT  66.24 45.535 66.258 45.769 ;
     RECT  2.304 45.563 9.342 45.797 ;
     RECT  65.952 45.769 66.258 45.805 ;
     RECT  67.248 44.987 69.03 45.805 ;
     RECT  2.304 45.797 9.198 45.869 ;
     RECT  0.144 45.643 0.162 45.931 ;
     RECT  56.415 45.599 56.754 45.931 ;
     RECT  10.8 45.931 10.818 45.967 ;
     RECT  56.304 45.931 56.754 45.968 ;
     RECT  54.792 45.931 54.81 46.003 ;
     RECT  54.72 46.003 54.81 46.031 ;
     RECT  0.144 45.931 0.342 46.06 ;
     RECT  54.72 46.031 54.738 46.103 ;
     RECT  56.415 45.968 56.754 46.103 ;
     RECT  2.415 45.869 9.198 46.109 ;
     RECT  61.815 45.419 64.962 46.237 ;
     RECT  0.108 46.06 0.342 46.253 ;
     RECT  61.815 46.237 65.106 46.273 ;
     RECT  65.952 45.805 69.03 46.273 ;
     RECT  0.18 46.253 0.342 46.301 ;
     RECT  59.544 45.149 61.038 46.309 ;
     RECT  59.544 46.309 61.074 46.381 ;
     RECT  61.815 46.273 69.03 46.381 ;
     RECT  0.216 46.301 0.342 46.541 ;
     RECT  2.415 46.109 9.126 46.571 ;
     RECT  10.692 45.967 10.854 46.579 ;
     RECT  2.415 46.571 8.55 46.651 ;
     RECT  0.216 46.541 0.234 46.733 ;
     RECT  10.26 46.579 10.854 46.849 ;
     RECT  56.415 46.103 56.697 46.849 ;
     RECT  2.304 46.651 8.55 46.913 ;
     RECT  59.544 46.381 69.03 46.949 ;
     RECT  2.304 46.913 8.442 47.039 ;
     RECT  56.415 46.849 57.042 47.083 ;
     RECT  2.304 47.039 8.37 47.272 ;
     RECT  2.16 47.272 8.37 47.309 ;
     RECT  0.18 47.323 0.198 47.419 ;
     RECT  67.716 46.949 69.03 47.453 ;
     RECT  56.415 47.083 57.078 47.461 ;
     RECT  0.144 47.419 0.198 47.597 ;
     RECT  9.216 47.425 9.234 47.615 ;
     RECT  10.26 46.849 10.926 47.687 ;
     RECT  59.544 46.949 66.654 47.695 ;
     RECT  2.304 47.309 8.37 47.723 ;
     RECT  10.728 47.687 10.926 47.759 ;
     RECT  18.615 45.689 25.686 47.759 ;
     RECT  56.415 47.461 57.15 47.759 ;
     RECT  2.304 47.723 5.706 47.849 ;
     RECT  59.544 47.695 66.726 47.857 ;
     RECT  67.716 47.453 68.418 47.857 ;
     RECT  6.48 47.723 8.37 47.929 ;
     RECT  18.615 47.759 25.542 48.127 ;
     RECT  28.152 44.887 50.202 48.127 ;
     RECT  18.216 48.127 25.542 48.173 ;
     RECT  28.152 48.127 50.274 48.199 ;
     RECT  51.015 38.507 51.297 48.199 ;
     RECT  59.544 47.857 68.418 48.235 ;
     RECT  56.415 47.759 57.078 48.299 ;
     RECT  0.18 47.597 0.198 48.331 ;
     RECT  17.748 48.235 17.766 48.413 ;
     RECT  10.728 47.759 10.818 48.425 ;
     RECT  54.72 48.361 54.738 48.461 ;
     RECT  6.48 47.929 8.658 48.505 ;
     RECT  9.396 48.469 9.414 48.505 ;
     RECT  6.48 48.505 9.45 48.523 ;
     RECT  10.764 48.425 10.818 48.541 ;
     RECT  6.444 48.523 9.45 48.605 ;
     RECT  0.108 48.331 0.198 48.653 ;
     RECT  10.764 48.541 10.854 48.659 ;
     RECT  2.304 47.849 5.562 48.667 ;
     RECT  59.544 48.235 69.03 48.803 ;
     RECT  6.444 48.605 9.054 48.811 ;
     RECT  2.304 48.667 5.598 48.839 ;
     RECT  2.304 48.839 4.014 48.848 ;
     RECT  4.824 48.839 5.598 48.901 ;
     RECT  6.372 48.811 9.054 48.901 ;
     RECT  10.764 48.659 10.818 48.929 ;
     RECT  4.824 48.901 9.054 49.037 ;
     RECT  0.18 48.653 0.198 49.051 ;
     RECT  5.904 49.037 9.054 49.085 ;
     RECT  0.18 49.051 0.306 49.109 ;
     RECT  5.904 49.085 6.93 49.109 ;
     RECT  0.18 49.109 0.198 49.133 ;
     RECT  1.116 49.003 1.134 49.181 ;
     RECT  5.904 49.109 6.75 49.199 ;
     RECT  28.152 48.199 51.297 49.207 ;
     RECT  67.284 48.803 69.03 49.229 ;
     RECT  6.012 49.199 6.75 49.235 ;
     RECT  18.615 48.173 25.542 49.243 ;
     RECT  7.815 49.085 9.054 49.271 ;
     RECT  59.544 48.803 66.114 49.307 ;
     RECT  9.036 49.271 9.054 49.351 ;
     RECT  9.036 49.351 9.126 49.379 ;
     RECT  67.284 49.229 67.302 49.579 ;
     RECT  58.716 49.171 58.734 49.621 ;
     RECT  59.976 49.307 66.114 49.621 ;
     RECT  67.248 49.579 67.302 49.621 ;
     RECT  59.976 49.621 67.302 49.739 ;
     RECT  9.108 49.379 9.126 49.747 ;
     RECT  28.152 49.207 51.894 49.747 ;
     RECT  4.824 49.037 5.166 49.783 ;
     RECT  58.716 49.621 58.806 49.811 ;
     RECT  2.415 48.848 4.014 49.855 ;
     RECT  4.824 49.783 5.238 49.855 ;
     RECT  10.8 48.929 10.818 49.855 ;
     RECT  65.448 49.739 67.302 49.981 ;
     RECT  68.328 49.229 69.03 49.981 ;
     RECT  2.415 49.855 5.238 50.009 ;
     RECT  6.012 49.235 6.21 50.009 ;
     RECT  10.728 49.855 10.818 50.009 ;
     RECT  6.984 49.855 7.002 50.011 ;
     RECT  6.84 50.011 7.002 50.051 ;
     RECT  18.615 49.243 26.262 50.053 ;
     RECT  2.415 50.009 4.302 50.059 ;
     RECT  65.448 49.981 69.03 50.093 ;
     RECT  10.728 50.009 10.746 50.117 ;
     RECT  5.076 50.009 5.238 50.125 ;
     RECT  7.815 49.271 8.262 50.125 ;
     RECT  9.108 49.747 9.234 50.125 ;
     RECT  5.076 50.125 5.742 50.153 ;
     RECT  7.815 50.125 9.234 50.153 ;
     RECT  65.448 50.093 66.726 50.153 ;
     RECT  7.815 50.153 9.126 50.251 ;
     RECT  7.236 50.251 9.126 50.288 ;
     RECT  0.54 50.125 0.558 50.395 ;
     RECT  18.615 50.053 26.73 50.431 ;
     RECT  0.54 50.395 0.63 50.459 ;
     RECT  58.716 49.811 58.734 50.459 ;
     RECT  0.54 50.459 0.558 50.477 ;
     RECT  65.628 50.153 66.726 50.477 ;
     RECT  65.628 50.477 66.546 50.549 ;
     RECT  65.628 50.549 65.646 50.729 ;
     RECT  2.304 50.059 4.302 50.791 ;
     RECT  59.976 49.739 64.674 50.791 ;
     RECT  67.788 50.093 69.03 50.819 ;
     RECT  5.364 50.153 5.742 50.899 ;
     RECT  2.304 50.791 4.518 50.923 ;
     RECT  5.364 50.899 6.426 50.923 ;
     RECT  7.815 50.288 9.126 50.971 ;
     RECT  2.304 50.923 6.426 51.019 ;
     RECT  7.815 50.971 9.234 51.097 ;
     RECT  7.815 51.097 9.306 51.149 ;
     RECT  66.528 50.549 66.546 51.149 ;
     RECT  2.304 51.019 6.75 51.169 ;
     RECT  7.815 51.149 8.262 51.169 ;
     RECT  59.868 50.791 64.674 51.169 ;
     RECT  0.144 51.019 0.198 51.196 ;
     RECT  9.036 51.149 9.306 51.269 ;
     RECT  0.108 51.196 0.198 51.341 ;
     RECT  68.328 50.819 69.03 51.359 ;
     RECT  0.18 51.341 0.198 51.389 ;
     RECT  59.292 51.169 64.674 51.403 ;
     RECT  10.836 50.791 10.854 51.431 ;
     RECT  68.94 51.359 69.03 51.431 ;
     RECT  18.615 50.431 26.766 51.439 ;
     RECT  9.288 51.269 9.306 51.511 ;
     RECT  59.292 51.403 64.998 51.511 ;
     RECT  68.94 51.431 68.958 51.539 ;
     RECT  9.288 51.511 9.45 51.629 ;
     RECT  66.672 51.403 66.69 51.629 ;
     RECT  58.788 51.511 64.998 51.665 ;
     RECT  58.788 51.665 58.806 51.673 ;
     RECT  28.152 49.747 52.002 51.701 ;
     RECT  58.716 51.673 58.806 51.773 ;
     RECT  59.868 51.665 64.998 51.773 ;
     RECT  63.612 51.773 64.998 51.809 ;
     RECT  18.615 51.439 27.378 51.979 ;
     RECT  9.288 51.629 9.306 52.015 ;
     RECT  18.615 51.979 27.414 52.015 ;
     RECT  28.152 51.701 51.894 52.015 ;
     RECT  63.612 51.809 63.666 52.043 ;
     RECT  2.304 51.169 8.262 52.051 ;
     RECT  9.216 52.015 9.306 52.051 ;
     RECT  1.152 52.027 1.17 52.075 ;
     RECT  59.868 51.773 62.73 52.169 ;
     RECT  1.152 52.075 1.278 52.205 ;
     RECT  59.868 52.169 62.37 52.205 ;
     RECT  59.868 52.205 61.002 52.313 ;
     RECT  64.404 51.809 64.998 52.439 ;
     RECT  2.304 52.051 9.306 52.619 ;
     RECT  59.976 52.313 61.002 52.619 ;
     RECT  2.304 52.619 3.294 52.745 ;
     RECT  18.615 52.015 51.894 52.745 ;
     RECT  64.404 52.439 64.422 52.781 ;
     RECT  4.068 52.619 9.306 52.789 ;
     RECT  63.612 52.043 63.63 52.853 ;
     RECT  2.304 52.745 2.697 52.889 ;
     RECT  60.624 52.619 61.002 52.889 ;
     RECT  61.815 52.205 62.37 52.979 ;
     RECT  4.068 52.789 9.342 52.981 ;
     RECT  4.068 52.981 9.414 53.015 ;
     RECT  4.5 53.015 9.414 53.021 ;
     RECT  60.984 52.889 61.002 53.123 ;
     RECT  4.5 53.021 5.814 53.249 ;
     RECT  6.768 53.021 8.874 53.249 ;
     RECT  4.5 53.249 5.058 53.285 ;
     RECT  7.815 53.249 8.874 53.393 ;
     RECT  8.856 53.393 8.874 53.429 ;
     RECT  5.04 53.285 5.058 53.519 ;
     RECT  5.796 53.249 5.814 53.519 ;
     RECT  6.912 53.249 6.93 53.519 ;
     RECT  18.615 52.745 51.297 64.165 ;
     RECT  18.576 64.165 51.297 64.327 ;
     RECT  18.18 64.327 51.297 64.705 ;
     RECT  18.072 64.705 51.297 64.867 ;
     RECT  17.784 64.867 51.297 65.245 ;
     RECT  17.64 65.245 51.297 65.515 ;
     RECT  17.568 65.515 51.297 65.785 ;
     RECT  17.424 65.785 51.297 66.479 ;
     RECT  29.268 66.479 51.297 66.653 ;
     RECT  2.415 52.889 2.697 66.707 ;
     RECT  7.815 53.393 8.097 66.707 ;
     RECT  13.215 43.709 13.497 66.707 ;
     RECT  51.015 66.653 51.297 66.707 ;
     RECT  56.415 48.299 56.697 66.707 ;
     RECT  61.815 52.979 62.097 66.707 ;
     RECT  29.268 66.653 50.238 66.749 ;
     RECT  29.268 66.749 39.402 66.797 ;
     RECT  29.268 66.797 37.242 66.857 ;
     RECT  40.212 66.749 49.59 66.893 ;
     RECT  31.14 66.857 37.242 66.929 ;
     RECT  2.415 66.707 2.505 66.977 ;
     RECT  7.815 66.707 7.905 66.977 ;
     RECT  13.215 66.707 13.305 66.977 ;
     RECT  40.215 66.893 44.442 66.977 ;
     RECT  51.015 66.707 51.105 66.977 ;
     RECT  56.415 66.707 56.505 66.977 ;
     RECT  61.815 66.707 61.905 66.977 ;
     RECT  40.356 66.977 44.442 67.085 ;
     RECT  17.424 66.479 28.494 67.229 ;
     RECT  29.268 66.857 30.402 67.229 ;
     RECT  45.396 66.893 49.59 67.229 ;
     RECT  17.424 67.229 24.894 67.277 ;
     RECT  25.632 67.229 28.494 67.277 ;
     RECT  29.34 67.229 29.358 67.277 ;
     RECT  30.384 67.229 30.402 67.277 ;
     RECT  31.14 66.929 33.966 67.277 ;
     RECT  34.74 66.929 37.242 67.277 ;
     RECT  38.016 66.797 39.402 67.277 ;
     RECT  41.04 67.085 44.442 67.277 ;
     RECT  45.972 67.229 49.59 67.277 ;
     RECT  23.58 67.277 23.922 67.325 ;
     RECT  24.696 67.277 24.714 67.325 ;
     RECT  36.072 67.277 37.242 67.325 ;
     RECT  46.044 67.277 46.422 67.325 ;
     RECT  23.58 67.325 23.598 67.805 ;
     RECT  17.424 67.277 17.658 67.853 ;
     RECT  27.792 67.277 28.458 67.853 ;
     RECT  32.904 67.277 32.922 67.853 ;
     RECT  34.74 67.277 35.298 67.853 ;
     RECT  36.432 67.325 37.242 67.853 ;
     RECT  39.384 67.277 39.402 67.853 ;
     RECT  41.976 67.277 43.254 67.853 ;
     RECT  44.316 67.277 44.334 67.853 ;
     RECT  17.424 67.853 17.586 67.901 ;
     RECT  27.792 67.853 27.81 68.381 ;
     RECT  31.356 67.277 31.914 68.381 ;
     RECT  17.424 67.901 17.442 68.429 ;
     RECT  37.008 67.853 37.242 68.429 ;
     RECT  42.624 67.853 42.642 68.429 ;
     RECT  29.268 68.443 29.286 68.621 ;
     RECT  45.18 68.683 45.198 68.731 ;
     RECT  23.364 68.779 23.382 68.827 ;
     RECT  45.18 68.731 45.306 68.875 ;
     RECT  47.16 67.277 47.178 68.875 ;
     RECT  19.26 67.277 19.818 68.957 ;
     RECT  22.932 68.827 23.382 68.957 ;
     RECT  47.016 68.875 47.178 68.957 ;
     RECT  19.26 68.957 19.278 69.005 ;
     RECT  23.004 68.957 23.382 69.005 ;
     RECT  31.788 68.381 31.806 69.005 ;
     RECT  34.236 68.875 34.254 69.005 ;
     RECT  37.224 68.429 37.242 69.005 ;
     RECT  44.892 68.875 45.306 69.005 ;
     RECT  47.016 68.957 47.034 69.005 ;
     RECT  48.996 67.277 49.014 69.005 ;
    LAYER M4 ;
     RECT  0.084 20.784 2.408 20.808 ;
     RECT  0.06 20.808 2.408 20.88 ;
     RECT  0.084 20.88 2.408 20.904 ;
     RECT  0.06 20.904 2.408 20.976 ;
     RECT  0.084 20.976 2.408 21 ;
     RECT  0.06 21 2.408 21.072 ;
     RECT  0.084 21.072 2.408 21.096 ;
     RECT  0.06 21.096 2.408 21.168 ;
     RECT  0.084 21.168 2.408 21.192 ;
     RECT  0.06 21.192 2.408 21.264 ;
     RECT  0.084 21.264 2.408 21.288 ;
     RECT  0.06 21.288 2.408 21.36 ;
     RECT  0.084 21.36 2.408 21.384 ;
     RECT  0.06 21.384 2.408 21.456 ;
     RECT  0.084 21.456 2.408 21.48 ;
     RECT  0.06 21.48 2.408 21.552 ;
     RECT  0.084 21.552 2.408 21.576 ;
     RECT  0.06 21.576 2.408 21.648 ;
     RECT  0.084 21.648 2.408 21.672 ;
     RECT  0.06 21.672 2.408 21.744 ;
     RECT  0.084 21.744 2.408 21.768 ;
     RECT  0.06 21.768 2.408 21.84 ;
     RECT  0.084 21.84 2.408 21.864 ;
     RECT  0.06 21.864 2.408 21.936 ;
     RECT  0.084 21.936 2.408 21.96 ;
     RECT  0.06 21.96 2.408 22.032 ;
     RECT  0.084 22.032 2.408 22.056 ;
     RECT  0.06 22.056 2.408 22.128 ;
     RECT  0.084 22.128 2.408 22.152 ;
     RECT  0.06 22.152 2.408 22.224 ;
     RECT  0.084 22.224 2.408 22.248 ;
     RECT  0.06 22.248 2.408 22.32 ;
     RECT  0.084 22.32 2.408 22.344 ;
     RECT  0.06 22.344 2.408 22.416 ;
     RECT  0.084 22.416 2.408 22.44 ;
     RECT  0.06 22.44 2.408 22.512 ;
     RECT  0.084 22.512 2.408 22.536 ;
     RECT  0.06 22.536 2.408 22.608 ;
     RECT  0.084 22.608 2.408 22.632 ;
     RECT  0.06 22.632 2.408 22.704 ;
     RECT  0.084 22.704 2.408 22.728 ;
     RECT  0.06 22.728 2.408 22.8 ;
     RECT  0.084 22.8 2.408 22.824 ;
     RECT  0.06 22.824 2.408 22.896 ;
     RECT  0.084 22.896 2.408 22.92 ;
     RECT  0.06 22.92 2.408 22.992 ;
     RECT  0.084 22.992 2.408 23.016 ;
     RECT  0.06 23.016 2.408 23.088 ;
     RECT  0.084 23.088 2.408 23.112 ;
     RECT  0.06 23.112 2.408 23.184 ;
     RECT  0.084 23.184 2.408 23.208 ;
     RECT  0.06 23.208 2.408 23.28 ;
     RECT  0.084 23.28 2.408 23.304 ;
     RECT  0.06 23.304 2.408 23.376 ;
     RECT  0.084 23.376 2.408 23.4 ;
     RECT  0.06 23.4 2.408 23.472 ;
     RECT  0.084 23.472 2.408 23.496 ;
     RECT  0.06 23.496 2.408 23.568 ;
     RECT  0.084 23.568 2.408 23.592 ;
     RECT  0.06 23.592 2.408 23.664 ;
     RECT  0.084 23.664 2.408 23.688 ;
     RECT  0.06 23.688 2.408 23.76 ;
     RECT  0.084 23.76 2.408 23.784 ;
     RECT  0.06 23.784 2.408 23.856 ;
     RECT  0.084 23.856 2.408 23.88 ;
     RECT  0.06 23.88 2.408 23.952 ;
     RECT  0.084 23.952 2.408 23.976 ;
     RECT  0.06 23.976 2.408 24.048 ;
     RECT  0.084 24.048 2.408 24.072 ;
     RECT  0.06 24.072 2.408 24.144 ;
     RECT  0.084 24.144 2.408 24.168 ;
     RECT  0.06 24.168 2.408 24.24 ;
     RECT  0.084 24.24 2.408 24.264 ;
     RECT  0.06 24.264 2.408 24.336 ;
     RECT  0.084 24.336 2.408 24.36 ;
     RECT  0.06 24.36 2.408 24.432 ;
     RECT  0.084 24.432 2.408 24.456 ;
     RECT  0.06 24.456 2.408 24.528 ;
     RECT  0.084 24.528 2.408 24.552 ;
     RECT  0.06 24.552 2.408 24.624 ;
     RECT  0.084 24.624 2.408 24.648 ;
     RECT  0.06 24.648 2.408 24.72 ;
     RECT  0.084 24.72 2.408 24.744 ;
     RECT  0.06 24.744 2.408 24.816 ;
     RECT  0.084 24.816 2.408 24.84 ;
     RECT  0.06 24.84 2.408 24.912 ;
     RECT  0.084 24.912 2.408 24.936 ;
     RECT  0.06 24.936 2.408 25.008 ;
     RECT  0.084 25.008 2.408 25.032 ;
     RECT  0.06 25.032 2.408 25.104 ;
     RECT  0.084 25.104 2.408 25.128 ;
     RECT  0.06 25.128 2.408 25.2 ;
     RECT  0.084 25.2 2.408 25.224 ;
     RECT  0.06 25.224 2.408 25.296 ;
     RECT  0.084 25.296 2.408 25.32 ;
     RECT  0.06 25.32 2.408 25.392 ;
     RECT  0.084 25.392 2.408 25.416 ;
     RECT  0.06 25.416 2.408 25.488 ;
     RECT  0.084 25.488 2.408 25.512 ;
     RECT  0.06 25.512 2.408 25.584 ;
     RECT  0.084 25.584 2.408 25.608 ;
     RECT  0.06 25.608 2.408 25.68 ;
     RECT  0.084 25.68 2.408 25.704 ;
     RECT  0.06 25.704 2.408 25.776 ;
     RECT  0.084 25.776 2.408 25.8 ;
     RECT  0.06 25.8 2.408 25.872 ;
     RECT  0.084 25.872 2.408 25.896 ;
     RECT  0.06 25.896 2.408 25.968 ;
     RECT  0.084 25.968 2.408 25.992 ;
     RECT  0.06 25.992 2.408 26.064 ;
     RECT  0.084 26.064 2.408 26.088 ;
     RECT  0.06 26.088 2.408 26.16 ;
     RECT  0.084 26.16 2.408 26.184 ;
     RECT  0.06 26.184 2.408 26.256 ;
     RECT  0.084 26.256 2.408 26.28 ;
     RECT  0.06 26.28 2.408 26.352 ;
     RECT  0.084 26.352 2.408 26.376 ;
     RECT  0.06 26.376 2.408 26.448 ;
     RECT  0.084 26.448 2.408 26.472 ;
     RECT  0.06 26.472 2.408 26.544 ;
     RECT  0.084 26.544 2.408 26.568 ;
     RECT  0.06 26.568 2.408 26.64 ;
     RECT  0.084 26.64 2.408 26.664 ;
     RECT  0.06 26.664 2.408 26.736 ;
     RECT  0.084 26.736 2.408 26.76 ;
     RECT  0.06 26.76 2.408 26.832 ;
     RECT  0.084 26.832 2.408 26.856 ;
     RECT  0.06 26.856 2.408 26.928 ;
     RECT  0.084 26.928 2.408 26.952 ;
     RECT  0.06 26.952 2.408 27.024 ;
     RECT  0.084 27.024 2.408 27.048 ;
     RECT  0.06 27.048 2.408 27.12 ;
     RECT  0.084 27.12 2.408 27.144 ;
     RECT  0.06 27.144 2.408 27.216 ;
     RECT  0.084 27.216 2.408 27.24 ;
     RECT  0.06 27.24 2.408 27.312 ;
     RECT  0.084 27.312 2.408 27.336 ;
     RECT  0.06 27.336 2.408 27.408 ;
     RECT  0.084 27.408 2.408 27.432 ;
     RECT  0.06 27.432 2.408 27.504 ;
     RECT  0.084 27.504 2.408 27.528 ;
     RECT  0.06 27.528 2.408 27.6 ;
     RECT  0.084 27.6 2.408 27.624 ;
     RECT  0.06 27.624 2.408 27.696 ;
     RECT  0.084 27.696 2.408 27.72 ;
     RECT  0.06 27.72 2.408 27.792 ;
     RECT  0.084 27.792 2.408 27.816 ;
     RECT  0.06 27.816 2.408 27.888 ;
     RECT  0.084 27.888 2.408 27.912 ;
     RECT  0.06 27.912 2.408 27.984 ;
     RECT  0.084 27.984 2.408 28.008 ;
     RECT  0.06 28.008 2.408 28.08 ;
     RECT  0.084 28.08 2.408 28.104 ;
     RECT  0.06 28.104 2.408 28.176 ;
     RECT  0.084 28.176 2.408 28.2 ;
     RECT  0.06 28.2 2.408 28.272 ;
     RECT  0.084 28.272 2.408 28.296 ;
     RECT  0.06 28.296 2.408 28.368 ;
     RECT  0.084 28.368 2.408 28.392 ;
     RECT  0.06 28.392 2.408 28.464 ;
     RECT  0.084 28.464 2.408 28.488 ;
     RECT  0.06 28.488 2.408 28.56 ;
     RECT  0.084 28.56 2.408 28.584 ;
     RECT  0.06 28.584 2.408 28.656 ;
     RECT  0.084 28.656 2.408 28.68 ;
     RECT  0.06 28.68 2.408 28.752 ;
     RECT  0.084 28.752 2.408 28.776 ;
     RECT  0.06 28.776 2.408 28.848 ;
     RECT  0.084 28.848 2.408 28.872 ;
     RECT  0.06 28.872 2.408 28.944 ;
     RECT  0.084 28.944 2.408 28.968 ;
     RECT  0.06 28.968 2.408 29.04 ;
     RECT  0.084 29.04 2.408 29.064 ;
     RECT  0.06 29.064 2.408 29.136 ;
     RECT  0.084 29.136 2.408 29.16 ;
     RECT  0.06 29.16 2.408 29.232 ;
     RECT  0.084 29.232 2.408 29.256 ;
     RECT  0.06 29.256 2.408 29.328 ;
     RECT  0.084 29.328 2.408 29.352 ;
     RECT  0.06 29.352 2.408 29.424 ;
     RECT  0.084 29.424 2.408 29.448 ;
     RECT  0.06 29.448 2.408 29.52 ;
     RECT  0.084 29.52 2.408 29.544 ;
     RECT  0.06 29.544 2.408 29.616 ;
     RECT  0.084 29.616 2.408 29.64 ;
     RECT  0.06 29.64 2.408 29.712 ;
     RECT  0.084 29.712 2.408 29.736 ;
     RECT  0.06 29.736 2.408 29.808 ;
     RECT  0.084 29.808 2.408 29.832 ;
     RECT  0.06 29.832 2.408 29.904 ;
     RECT  0.084 29.904 2.408 29.928 ;
     RECT  0.06 29.928 2.408 30.768 ;
     RECT  0.084 30.768 2.408 30.792 ;
     RECT  0.06 30.792 2.408 30.864 ;
     RECT  0.084 30.864 2.408 30.888 ;
     RECT  0.06 30.888 2.408 30.96 ;
     RECT  0.084 30.96 2.408 30.984 ;
     RECT  0.06 30.984 2.408 31.056 ;
     RECT  0.084 31.056 2.408 31.08 ;
     RECT  0.06 31.08 2.408 31.152 ;
     RECT  0.084 31.152 2.408 31.176 ;
     RECT  0.06 31.176 2.408 31.248 ;
     RECT  0.084 31.248 2.408 31.272 ;
     RECT  0.06 31.272 2.408 31.344 ;
     RECT  0.084 31.344 2.408 31.368 ;
     RECT  0.06 31.368 2.408 31.44 ;
     RECT  0.084 31.44 2.408 31.464 ;
     RECT  0.06 31.464 2.408 31.536 ;
     RECT  0.084 31.536 2.408 31.56 ;
     RECT  0.06 31.56 2.408 31.632 ;
     RECT  0.084 31.632 2.408 31.656 ;
     RECT  0.06 31.656 2.408 31.728 ;
     RECT  0.084 31.728 2.408 31.752 ;
     RECT  0.06 31.752 2.408 31.824 ;
     RECT  0.084 31.824 2.408 31.848 ;
     RECT  0.06 31.848 2.408 31.92 ;
     RECT  0.084 31.92 2.408 31.944 ;
     RECT  0.06 31.944 2.408 32.016 ;
     RECT  0.084 32.016 2.408 32.04 ;
     RECT  0.06 32.04 2.408 32.112 ;
     RECT  0.084 32.112 2.408 32.136 ;
     RECT  0.06 32.136 2.408 32.208 ;
     RECT  0.084 32.208 2.408 32.232 ;
     RECT  0.06 32.232 2.408 32.304 ;
     RECT  0.084 32.304 2.408 32.328 ;
     RECT  0.06 32.328 2.408 32.4 ;
     RECT  0.084 32.4 2.408 32.424 ;
     RECT  0.06 32.424 2.408 32.496 ;
     RECT  0.084 32.496 2.408 32.52 ;
     RECT  0.06 32.52 2.408 32.592 ;
     RECT  0.084 32.592 2.408 32.616 ;
     RECT  0.06 32.616 2.408 32.688 ;
     RECT  0.084 32.688 2.408 32.712 ;
     RECT  0.06 32.712 2.408 32.784 ;
     RECT  0.084 32.784 2.408 32.808 ;
     RECT  0.06 32.808 2.408 32.88 ;
     RECT  0.084 32.88 2.408 32.904 ;
     RECT  0.06 32.904 2.408 32.976 ;
     RECT  0.084 32.976 2.408 33 ;
     RECT  0.06 33 2.408 33.072 ;
     RECT  0.084 33.072 2.408 33.096 ;
     RECT  0.06 33.096 2.408 33.168 ;
     RECT  0.084 33.168 2.408 33.192 ;
     RECT  0.06 33.192 2.408 33.264 ;
     RECT  0.084 33.264 2.408 33.288 ;
     RECT  0.06 33.288 2.408 33.36 ;
     RECT  0.084 33.36 2.408 33.384 ;
     RECT  0.06 33.384 2.408 33.456 ;
     RECT  0.084 33.456 2.408 33.48 ;
     RECT  0.06 33.48 2.408 33.552 ;
     RECT  0.084 33.552 2.408 33.576 ;
     RECT  0.06 33.576 2.408 33.648 ;
     RECT  0.084 33.648 2.408 33.672 ;
     RECT  0.06 33.672 2.408 33.744 ;
     RECT  0.084 33.744 2.408 33.768 ;
     RECT  0.06 33.768 2.408 33.84 ;
     RECT  0.084 33.84 2.408 33.864 ;
     RECT  0.06 33.864 2.408 33.936 ;
     RECT  0.084 33.936 2.408 33.96 ;
     RECT  0.06 33.96 2.408 34.032 ;
     RECT  0.084 34.032 2.408 34.056 ;
     RECT  0.06 34.056 2.408 34.128 ;
     RECT  0.084 34.128 2.408 34.152 ;
     RECT  0.06 34.152 2.408 34.224 ;
     RECT  0.084 34.224 2.408 34.248 ;
     RECT  0.06 34.248 2.408 34.32 ;
     RECT  0.084 34.32 2.408 34.344 ;
     RECT  0.06 34.344 2.408 34.416 ;
     RECT  0.084 34.416 2.408 34.44 ;
     RECT  0.06 34.44 2.408 34.512 ;
     RECT  0.084 34.512 2.408 34.536 ;
     RECT  0.06 34.536 2.408 34.608 ;
     RECT  0.084 34.608 2.408 34.632 ;
     RECT  0.06 34.632 2.408 34.704 ;
     RECT  0.084 34.704 2.408 34.728 ;
     RECT  0.06 34.728 2.408 34.8 ;
     RECT  0.084 34.8 2.408 34.824 ;
     RECT  0.06 34.824 2.408 34.896 ;
     RECT  0.084 34.896 2.408 34.92 ;
     RECT  0.06 34.92 2.408 34.992 ;
     RECT  0.084 34.992 2.408 35.016 ;
     RECT  0.06 35.016 2.408 35.088 ;
     RECT  0.084 35.088 2.408 35.112 ;
     RECT  0.06 35.112 2.408 35.184 ;
     RECT  0.084 35.184 2.408 35.208 ;
     RECT  0.06 35.208 2.408 35.28 ;
     RECT  0.084 35.28 2.408 35.304 ;
     RECT  0.06 35.304 2.408 35.376 ;
     RECT  0.084 35.376 2.408 35.4 ;
     RECT  0.06 35.4 2.408 35.472 ;
     RECT  0.084 35.472 2.408 35.496 ;
     RECT  0.06 35.496 2.408 35.568 ;
     RECT  0.084 35.568 2.408 35.592 ;
     RECT  0.06 35.592 2.408 35.664 ;
     RECT  0.084 35.664 2.408 35.688 ;
     RECT  0.06 35.688 2.408 35.76 ;
     RECT  0.084 35.76 2.408 35.784 ;
     RECT  0.06 35.784 2.408 35.856 ;
     RECT  0.084 35.856 2.408 35.88 ;
     RECT  0.06 35.88 2.408 35.952 ;
     RECT  0.084 35.952 2.408 35.976 ;
     RECT  0.06 35.976 2.408 36.048 ;
     RECT  0.084 36.048 2.408 36.072 ;
     RECT  0.06 36.072 2.408 36.144 ;
     RECT  0.084 36.144 2.408 36.168 ;
     RECT  0.06 36.168 2.408 36.24 ;
     RECT  0.084 36.24 2.408 36.264 ;
     RECT  0.06 36.264 2.408 36.336 ;
     RECT  0.084 36.336 2.408 36.36 ;
     RECT  0.06 36.36 2.408 36.432 ;
     RECT  0.084 36.432 2.408 36.456 ;
     RECT  0.06 36.456 2.408 36.528 ;
     RECT  0.084 36.528 2.408 36.552 ;
     RECT  0.06 36.552 2.408 36.624 ;
     RECT  0.084 36.624 2.408 36.648 ;
     RECT  0.06 36.648 2.408 36.72 ;
     RECT  0.084 36.72 2.408 36.744 ;
     RECT  0.06 36.744 2.408 36.816 ;
     RECT  0.084 36.816 2.408 36.84 ;
     RECT  0.06 36.84 2.408 36.912 ;
     RECT  0.084 36.912 2.408 36.936 ;
     RECT  0.06 36.936 2.408 37.008 ;
     RECT  0.084 37.008 2.408 37.032 ;
     RECT  0.06 37.032 2.408 37.104 ;
     RECT  0.084 37.104 2.408 37.128 ;
     RECT  0.06 37.128 2.408 37.2 ;
     RECT  0.084 37.2 2.408 37.224 ;
     RECT  0.06 37.224 2.408 37.296 ;
     RECT  0.084 37.296 2.408 37.32 ;
     RECT  0.06 37.32 2.408 37.392 ;
     RECT  0.084 37.392 2.408 37.416 ;
     RECT  0.06 37.416 2.408 37.488 ;
     RECT  0.084 37.488 2.408 37.512 ;
     RECT  0.06 37.512 2.408 37.584 ;
     RECT  0.084 37.584 2.408 37.608 ;
     RECT  0.06 37.608 2.408 37.68 ;
     RECT  0.084 37.68 2.408 37.704 ;
     RECT  0.06 37.704 2.408 37.776 ;
     RECT  0.084 37.776 2.408 37.8 ;
     RECT  0.06 37.8 2.408 37.872 ;
     RECT  0.084 37.872 2.408 37.896 ;
     RECT  0.06 37.896 2.408 37.968 ;
     RECT  0.084 37.968 2.408 37.992 ;
     RECT  0.06 37.992 2.408 38.064 ;
     RECT  0.084 38.064 2.408 38.088 ;
     RECT  0.06 38.088 2.408 38.16 ;
     RECT  0.084 38.16 2.408 38.184 ;
     RECT  0.06 38.184 2.408 38.256 ;
     RECT  0.084 38.256 2.408 38.28 ;
     RECT  0.06 38.28 2.408 38.352 ;
     RECT  0.084 38.352 2.408 38.376 ;
     RECT  0.06 38.376 2.408 38.448 ;
     RECT  0.084 38.448 2.408 38.472 ;
     RECT  0.06 38.472 2.408 38.544 ;
     RECT  0.084 38.544 2.408 38.568 ;
     RECT  0.06 38.568 2.408 38.64 ;
     RECT  0.084 38.64 2.408 38.664 ;
     RECT  0.06 38.664 2.408 38.736 ;
     RECT  0.084 38.736 2.408 38.76 ;
     RECT  0.06 38.76 2.408 38.832 ;
     RECT  0.084 38.832 2.408 38.856 ;
     RECT  0.06 38.856 2.408 38.928 ;
     RECT  0.084 38.928 2.408 38.952 ;
     RECT  0.06 38.952 2.408 39.024 ;
     RECT  0.084 39.024 2.408 39.048 ;
     RECT  0.06 39.048 2.408 39.12 ;
     RECT  0.084 39.12 2.408 39.144 ;
     RECT  0.06 39.144 2.408 39.216 ;
     RECT  0.084 39.216 2.408 39.24 ;
     RECT  0.06 39.24 2.408 39.312 ;
     RECT  0.084 39.312 2.408 39.336 ;
     RECT  0.06 39.336 2.408 39.408 ;
     RECT  0.084 39.408 2.408 39.432 ;
     RECT  0.06 39.432 2.408 39.504 ;
     RECT  0.084 39.504 2.408 39.528 ;
     RECT  0.06 39.528 2.408 39.6 ;
     RECT  0.084 39.6 2.408 39.624 ;
     RECT  0.06 39.624 2.408 39.696 ;
     RECT  0.084 39.696 2.408 39.72 ;
     RECT  0.06 39.72 2.408 39.792 ;
     RECT  0.084 39.792 2.408 39.816 ;
     RECT  0.06 39.816 2.408 39.888 ;
     RECT  0.084 39.888 2.408 39.912 ;
     RECT  0.06 39.912 2.408 39.984 ;
     RECT  0.084 39.984 2.408 40.008 ;
     RECT  0.06 40.008 2.408 40.08 ;
     RECT  0.084 40.08 2.408 40.104 ;
     RECT  0.06 40.104 2.408 40.176 ;
     RECT  0.084 40.176 2.408 40.2 ;
     RECT  0.06 40.2 2.408 40.272 ;
     RECT  0.084 40.272 2.408 40.296 ;
     RECT  0.06 40.296 2.408 40.368 ;
     RECT  0.084 40.368 2.408 40.392 ;
     RECT  0.06 40.392 2.408 40.464 ;
     RECT  0.084 40.464 2.408 40.488 ;
     RECT  0.06 40.488 2.408 40.56 ;
     RECT  0.084 40.56 2.408 40.584 ;
     RECT  0.06 40.584 2.408 40.656 ;
     RECT  0.084 40.656 2.408 40.68 ;
     RECT  0.06 40.68 2.408 40.752 ;
     RECT  0.084 40.752 2.408 40.776 ;
     RECT  0.06 40.776 2.408 40.848 ;
     RECT  0.084 40.848 2.408 40.872 ;
     RECT  0.06 40.872 2.408 40.944 ;
     RECT  0.084 40.944 2.408 40.968 ;
     RECT  0.06 40.968 2.408 41.04 ;
     RECT  0.084 41.04 2.408 41.064 ;
     RECT  0.06 41.064 2.408 41.136 ;
     RECT  0.084 41.136 2.408 41.16 ;
     RECT  0.06 41.16 2.408 41.232 ;
     RECT  0.084 41.232 2.408 41.256 ;
     RECT  0.06 41.256 2.408 41.328 ;
     RECT  0.084 41.328 2.408 41.352 ;
     RECT  0.06 41.352 2.408 41.424 ;
     RECT  0.084 41.424 2.408 41.448 ;
     RECT  0.06 41.448 2.408 41.52 ;
     RECT  0.084 41.52 2.408 41.544 ;
     RECT  0.06 41.544 2.408 41.616 ;
     RECT  0.084 41.616 2.408 41.64 ;
     RECT  0.06 41.64 2.408 41.712 ;
     RECT  0.084 41.712 2.408 41.736 ;
     RECT  0.06 41.736 2.408 41.808 ;
     RECT  0.084 41.808 2.408 41.832 ;
     RECT  0.06 41.832 2.408 41.904 ;
     RECT  0.084 41.904 2.408 41.928 ;
     RECT  0.06 41.928 2.408 42 ;
     RECT  0.084 42 2.408 42.024 ;
     RECT  0.06 42.024 2.408 42.096 ;
     RECT  0.084 42.096 2.408 42.12 ;
     RECT  0.06 42.12 2.408 42.192 ;
     RECT  0.084 42.192 2.408 42.216 ;
     RECT  0.06 42.216 2.408 42.288 ;
     RECT  0.084 42.288 2.408 42.312 ;
     RECT  0.06 42.312 2.408 42.384 ;
     RECT  0.084 42.384 2.408 42.408 ;
     RECT  0.06 42.408 2.408 42.48 ;
     RECT  0.084 42.48 2.408 42.504 ;
     RECT  0.06 42.504 2.408 42.576 ;
     RECT  0.084 42.576 2.408 42.6 ;
     RECT  0.06 42.6 2.408 42.672 ;
     RECT  0.084 42.672 2.408 42.696 ;
     RECT  0.06 42.696 2.408 42.768 ;
     RECT  0.084 42.768 2.408 42.792 ;
     RECT  0.06 42.792 2.408 42.864 ;
     RECT  0.084 42.864 2.408 42.888 ;
     RECT  0.06 42.888 2.408 42.96 ;
     RECT  0.084 42.96 2.408 42.984 ;
     RECT  0.06 42.984 2.408 43.056 ;
     RECT  0.084 43.056 2.408 43.08 ;
     RECT  0.06 43.08 2.408 43.152 ;
     RECT  0.084 43.152 2.408 43.176 ;
     RECT  0.06 43.176 2.408 43.248 ;
     RECT  0.084 43.248 2.408 43.272 ;
     RECT  0.06 43.272 2.408 43.344 ;
     RECT  0.084 43.344 2.408 43.368 ;
     RECT  0.06 43.368 2.408 43.44 ;
     RECT  0.084 43.44 2.408 43.464 ;
     RECT  0.06 43.464 2.408 43.536 ;
     RECT  0.084 43.536 2.408 43.56 ;
     RECT  0.06 43.56 2.408 43.632 ;
     RECT  0.084 43.632 2.408 43.656 ;
     RECT  0.06 43.656 2.408 43.728 ;
     RECT  0.084 43.728 2.408 43.752 ;
     RECT  0.06 43.752 2.408 43.824 ;
     RECT  0.084 43.824 2.408 43.848 ;
     RECT  0.06 43.848 2.408 43.92 ;
     RECT  0.084 43.92 2.408 43.944 ;
     RECT  0.06 43.944 2.408 44.016 ;
     RECT  0.084 44.016 2.408 44.04 ;
     RECT  0.06 44.04 2.408 44.112 ;
     RECT  0.084 44.112 2.408 44.136 ;
     RECT  0.06 44.136 2.408 44.208 ;
     RECT  0.084 44.208 2.408 44.232 ;
     RECT  0.06 44.232 2.408 44.304 ;
     RECT  0.084 44.304 2.408 44.328 ;
     RECT  0.06 44.328 2.408 44.4 ;
     RECT  0.084 44.4 2.408 44.424 ;
     RECT  0.06 44.424 2.408 44.496 ;
     RECT  0.084 44.496 2.408 44.52 ;
     RECT  0.06 44.52 2.408 44.592 ;
     RECT  0.084 44.592 2.408 44.616 ;
     RECT  0.06 44.616 2.408 44.688 ;
     RECT  0.084 44.688 2.408 44.712 ;
     RECT  0.06 44.712 2.408 44.784 ;
     RECT  0.084 44.784 2.408 44.808 ;
     RECT  0.06 44.808 2.408 44.88 ;
     RECT  0.084 44.88 2.408 44.904 ;
     RECT  0.06 44.904 2.408 44.976 ;
     RECT  0.084 44.976 2.408 45 ;
     RECT  0.06 45 2.408 45.072 ;
     RECT  0.084 45.072 2.408 45.096 ;
     RECT  0.06 45.096 2.408 45.168 ;
     RECT  0.084 45.168 2.408 45.192 ;
     RECT  0.06 45.192 2.408 45.264 ;
     RECT  0.084 45.264 2.408 45.288 ;
     RECT  0.06 45.288 2.408 45.36 ;
     RECT  0.084 45.36 2.408 45.384 ;
     RECT  0.06 45.384 2.408 45.456 ;
     RECT  0.084 45.456 2.408 45.48 ;
     RECT  0.06 45.48 2.408 45.552 ;
     RECT  0.084 45.552 2.408 45.576 ;
     RECT  0.06 45.576 2.408 45.648 ;
     RECT  0.084 45.648 2.408 45.672 ;
     RECT  0.06 45.672 2.408 45.744 ;
     RECT  0.084 45.744 2.408 45.768 ;
     RECT  0.06 45.768 2.408 45.84 ;
     RECT  0.084 45.84 2.408 45.864 ;
     RECT  0.06 45.864 2.408 45.936 ;
     RECT  0.084 45.936 2.408 45.96 ;
     RECT  0.06 45.96 2.408 46.032 ;
     RECT  0.084 46.032 2.408 46.056 ;
     RECT  0.06 46.056 2.408 46.128 ;
     RECT  0.084 46.128 2.408 46.152 ;
     RECT  0.06 46.152 2.408 46.224 ;
     RECT  0.084 46.224 2.408 46.248 ;
     RECT  0.06 46.248 2.408 46.32 ;
     RECT  0.084 46.32 2.408 46.344 ;
     RECT  0.06 46.344 2.408 46.416 ;
     RECT  0.084 46.416 2.408 46.44 ;
     RECT  0.06 46.44 2.408 46.512 ;
     RECT  0.084 46.512 2.408 46.536 ;
     RECT  0.06 46.536 2.408 46.608 ;
     RECT  0.084 46.608 2.408 46.632 ;
     RECT  0.06 46.632 2.408 46.704 ;
     RECT  0.084 46.704 2.408 46.728 ;
     RECT  0.06 46.728 2.408 46.8 ;
     RECT  0.084 46.8 2.408 46.824 ;
     RECT  0.06 46.824 2.408 46.896 ;
     RECT  0.084 46.896 2.408 46.92 ;
     RECT  0.06 46.92 2.408 46.992 ;
     RECT  0.084 46.992 2.408 47.016 ;
     RECT  0.06 47.016 2.408 47.088 ;
     RECT  0.084 47.088 2.408 47.112 ;
     RECT  0.06 47.112 2.408 47.184 ;
     RECT  0.084 47.184 2.408 47.208 ;
     RECT  0.06 47.208 2.408 47.28 ;
     RECT  0.084 47.28 2.408 47.304 ;
     RECT  0.06 47.304 2.408 47.376 ;
     RECT  0.084 47.376 2.408 47.4 ;
     RECT  0.06 47.4 2.408 47.472 ;
     RECT  0.084 47.472 2.408 47.496 ;
     RECT  0.06 47.496 2.408 47.568 ;
     RECT  0.084 47.568 2.408 47.592 ;
     RECT  0.06 47.592 2.408 47.664 ;
     RECT  0.084 47.664 2.408 47.688 ;
     RECT  0.06 47.688 2.408 47.76 ;
     RECT  0.084 47.76 2.408 47.784 ;
     RECT  0.06 47.784 2.408 47.856 ;
     RECT  0.084 47.856 2.408 47.88 ;
     RECT  0.06 47.88 2.408 47.952 ;
     RECT  0.084 47.952 2.408 47.976 ;
     RECT  0.06 47.976 2.408 48.048 ;
     RECT  0.084 48.048 2.408 48.072 ;
     RECT  0.06 48.072 2.408 48.144 ;
     RECT  0.084 48.144 2.408 48.168 ;
     RECT  0.06 48.168 2.408 48.24 ;
     RECT  0.084 48.24 2.408 48.264 ;
     RECT  0.06 48.264 2.408 48.336 ;
     RECT  0.084 48.336 2.408 48.36 ;
     RECT  0.06 48.36 2.408 48.432 ;
     RECT  0.084 48.432 2.408 48.456 ;
     RECT  0.06 48.456 2.408 48.528 ;
     RECT  0.084 48.528 2.408 48.552 ;
     RECT  0.06 48.552 2.408 48.624 ;
     RECT  0.084 48.624 2.408 48.648 ;
     RECT  0.06 48.648 2.408 48.72 ;
     RECT  0.084 48.72 2.408 48.744 ;
     RECT  0.06 48.744 2.408 48.816 ;
     RECT  0.084 48.816 2.408 48.84 ;
     RECT  0.06 48.84 2.408 48.912 ;
     RECT  0.084 48.912 2.408 48.936 ;
     RECT  0.06 48.936 2.408 49.008 ;
     RECT  0.084 49.008 2.408 49.032 ;
     RECT  0.06 49.032 2.408 49.104 ;
     RECT  0.084 49.104 2.408 49.128 ;
     RECT  0.06 49.128 2.408 49.968 ;
     RECT  0.084 49.968 2.408 49.992 ;
     RECT  0.06 49.992 2.408 50.064 ;
     RECT  0.084 50.064 2.408 50.088 ;
     RECT  0.06 50.088 2.408 50.16 ;
     RECT  0.084 50.16 2.408 50.184 ;
     RECT  0.06 50.184 2.408 50.256 ;
     RECT  0.084 50.256 2.408 50.28 ;
     RECT  0.06 50.28 2.408 50.352 ;
     RECT  0.084 50.352 2.408 50.376 ;
     RECT  0.06 50.376 2.408 50.448 ;
     RECT  0.084 50.448 2.408 50.472 ;
     RECT  0.06 50.472 2.408 50.544 ;
     RECT  0.084 50.544 2.408 50.568 ;
     RECT  0.06 50.568 2.408 50.64 ;
     RECT  0.084 50.64 2.408 50.664 ;
     RECT  0.06 50.664 2.408 50.736 ;
     RECT  0.084 50.736 2.408 50.76 ;
     RECT  0.06 50.76 2.408 50.832 ;
     RECT  0.084 50.832 2.408 50.856 ;
     RECT  0.06 50.856 2.408 50.928 ;
     RECT  0.084 50.928 2.408 50.952 ;
     RECT  0.06 50.952 2.408 51.024 ;
     RECT  0.084 51.024 2.408 51.048 ;
     RECT  0.06 51.048 2.408 51.12 ;
     RECT  0.084 51.12 2.408 51.144 ;
     RECT  0.06 51.144 2.408 51.216 ;
     RECT  0.084 51.216 2.408 51.24 ;
     RECT  0.06 51.24 2.408 51.312 ;
     RECT  0.084 51.312 2.408 51.336 ;
     RECT  0.06 51.336 2.408 51.408 ;
     RECT  0.084 51.408 2.408 51.432 ;
     RECT  0.06 51.432 2.408 51.504 ;
     RECT  0.084 51.504 2.408 51.528 ;
     RECT  0.06 51.528 2.408 51.6 ;
     RECT  0.084 51.6 2.408 51.624 ;
     RECT  0.06 51.624 2.408 51.696 ;
     RECT  0.084 51.696 2.408 51.72 ;
     RECT  0.06 51.72 2.408 51.792 ;
     RECT  0.084 51.792 2.408 51.816 ;
     RECT  0.06 51.816 2.408 51.888 ;
     RECT  0.084 51.888 2.408 51.912 ;
     RECT  0.06 51.912 2.408 51.984 ;
     RECT  0.084 51.984 2.408 52.008 ;
     RECT  0.06 52.008 2.408 52.08 ;
     RECT  0.084 52.08 2.408 52.104 ;
     RECT  0.06 52.104 2.408 52.176 ;
     RECT  0.084 52.176 2.408 52.2 ;
     RECT  0.06 52.2 2.408 52.272 ;
     RECT  0.084 52.272 2.408 52.296 ;
     RECT  0.06 52.296 2.408 52.368 ;
     RECT  0.084 52.368 2.408 52.392 ;
     RECT  0.06 52.392 2.408 52.464 ;
     RECT  0.084 52.464 2.408 52.488 ;
     RECT  0.06 52.488 2.408 52.56 ;
     RECT  0.084 52.56 2.408 52.584 ;
     RECT  0.06 52.584 2.408 52.656 ;
     RECT  0.084 52.656 2.408 52.68 ;
     RECT  0.06 52.68 2.408 52.752 ;
     RECT  0.084 52.752 2.408 52.776 ;
     RECT  0.06 52.776 2.408 52.848 ;
     RECT  0.084 52.848 2.408 52.872 ;
     RECT  0.06 52.872 2.408 52.944 ;
     RECT  0.084 52.944 2.408 52.968 ;
     RECT  2.408 2.148 2.512 66.972 ;
     RECT  2.512 2.418 2.704 66.702 ;
     RECT  2.704 20.88 4.345 52.872 ;
     RECT  4.345 20.544 4.885 52.872 ;
     RECT  4.885 20.544 5.069 53.064 ;
     RECT  5.069 20.544 5.501 53.016 ;
     RECT  5.501 20.928 6.853 53.016 ;
     RECT  6.853 20.928 7.808 53.208 ;
     RECT  7.808 2.148 7.912 66.972 ;
     RECT  7.912 2.418 8.104 66.702 ;
     RECT  8.104 44.688 8.165 44.952 ;
     RECT  8.104 23.328 8.201 23.64 ;
     RECT  8.104 25.008 8.201 25.272 ;
     RECT  8.104 26.88 8.237 28.536 ;
     RECT  8.104 35.808 8.243 43.416 ;
     RECT  8.104 46.08 8.273 50.04 ;
     RECT  8.201 23.568 8.309 23.64 ;
     RECT  8.243 36.576 8.309 43.416 ;
     RECT  8.309 42.528 8.345 43.416 ;
     RECT  8.165 44.688 8.381 44.76 ;
     RECT  8.273 46.08 8.381 49.08 ;
     RECT  8.309 36.576 8.453 41.4 ;
     RECT  8.381 44.688 8.453 44.712 ;
     RECT  8.104 21.936 8.489 22.248 ;
     RECT  8.453 39.84 8.489 41.4 ;
     RECT  8.345 43.392 8.489 43.416 ;
     RECT  8.237 28.512 8.561 28.536 ;
     RECT  8.104 51.12 8.561 53.016 ;
     RECT  8.489 21.984 8.597 22.248 ;
     RECT  8.597 22.224 8.849 22.248 ;
     RECT  8.489 39.84 8.921 40.44 ;
     RECT  8.104 34.56 8.957 34.632 ;
     RECT  8.453 36.576 8.957 38.808 ;
     RECT  8.237 26.88 9.137 27.48 ;
     RECT  8.957 36.576 9.137 38.424 ;
     RECT  8.921 40.368 9.137 40.44 ;
     RECT  9.137 27.12 9.173 27.432 ;
     RECT  8.561 51.216 9.173 53.016 ;
     RECT  9.173 27.36 9.209 27.432 ;
     RECT  8.104 32.208 9.209 33.096 ;
     RECT  8.381 46.08 9.209 48.6 ;
     RECT  8.104 30.048 9.245 31.224 ;
     RECT  8.201 25.008 9.281 25.176 ;
     RECT  9.209 27.36 9.281 27.384 ;
     RECT  9.209 32.304 9.281 32.328 ;
     RECT  9.173 51.984 9.281 53.016 ;
     RECT  9.137 36.576 9.317 37.992 ;
     RECT  9.281 51.984 9.317 52.008 ;
     RECT  9.317 36.576 9.353 37.704 ;
     RECT  9.245 30.912 9.425 31.224 ;
     RECT  9.281 52.992 9.425 53.016 ;
     RECT  9.425 30.912 9.461 30.936 ;
     RECT  9.209 46.224 9.461 48.6 ;
     RECT  9.137 40.416 9.497 40.44 ;
     RECT  9.353 36.576 9.533 36.936 ;
     RECT  8.957 34.608 9.605 34.632 ;
     RECT  8.309 23.568 13.208 23.592 ;
     RECT  9.281 25.152 13.208 25.176 ;
     RECT  9.533 36.576 13.208 36.6 ;
     RECT  9.461 46.224 13.208 48.408 ;
     RECT  13.208 2.148 13.312 66.972 ;
     RECT  13.312 2.418 13.504 66.702 ;
     RECT  17.413 68.4 17.557 68.424 ;
     RECT  17.557 67.872 17.629 68.424 ;
     RECT  17.629 67.824 17.693 68.424 ;
     RECT  17.693 67.248 17.773 68.424 ;
     RECT  17.773 66.72 17.843 68.424 ;
     RECT  17.843 66.72 17.917 67.896 ;
     RECT  17.917 66 18.169 67.896 ;
     RECT  13.504 23.568 18.608 23.592 ;
     RECT  13.504 25.152 18.608 25.176 ;
     RECT  13.504 36.576 18.608 36.6 ;
     RECT  13.504 46.224 18.608 48.408 ;
     RECT  18.169 65.52 18.608 67.896 ;
     RECT  18.608 2.148 18.707 67.896 ;
     RECT  18.707 2.148 18.712 67.272 ;
     RECT  18.712 2.418 18.904 67.272 ;
     RECT  18.904 42.816 19.073 42.84 ;
     RECT  18.904 46.224 19.091 48.264 ;
     RECT  18.904 62.16 19.117 64.392 ;
     RECT  18.421 68.928 19.141 68.952 ;
     RECT  19.117 62.16 19.235 63.864 ;
     RECT  19.141 68.832 19.249 68.952 ;
     RECT  19.235 62.4 19.261 63.864 ;
     RECT  18.904 66.336 19.325 67.272 ;
     RECT  19.249 68.832 19.331 69 ;
     RECT  19.331 68.928 19.763 69 ;
     RECT  19.763 68.928 20.051 68.952 ;
     RECT  18.904 27.936 20.185 27.96 ;
     RECT  18.904 26.4 20.221 26.664 ;
     RECT  20.185 27.936 20.221 28.392 ;
     RECT  18.904 25.152 20.252 25.176 ;
     RECT  18.904 23.568 20.293 23.592 ;
     RECT  20.252 25.104 20.389 25.176 ;
     RECT  20.221 26.4 20.405 28.392 ;
     RECT  20.293 23.568 20.435 23.688 ;
     RECT  20.405 26.4 20.441 27.288 ;
     RECT  20.389 24.864 20.476 25.176 ;
     RECT  20.405 28.368 20.797 28.392 ;
     RECT  20.797 28.368 21.301 28.728 ;
     RECT  21.301 28.368 21.341 29.64 ;
     RECT  19.261 62.4 21.625 63.816 ;
     RECT  21.625 62.4 21.626 64.392 ;
     RECT  21.341 28.704 21.665 29.64 ;
     RECT  21.913 42.24 21.949 42.264 ;
     RECT  21.665 28.704 22.133 29.256 ;
     RECT  19.091 46.224 22.309 48.168 ;
     RECT  22.273 65.52 22.357 65.544 ;
     RECT  22.133 29.232 22.421 29.256 ;
     RECT  19.325 66.72 22.451 67.272 ;
     RECT  21.949 42.048 22.453 42.264 ;
     RECT  21.626 62.448 22.529 64.392 ;
     RECT  22.453 42.048 22.705 42.6 ;
     RECT  22.529 64.368 22.705 64.392 ;
     RECT  20.441 26.4 22.813 26.664 ;
     RECT  22.705 42.048 22.813 42.984 ;
     RECT  22.309 45.84 22.885 48.168 ;
     RECT  22.705 64.368 22.889 64.968 ;
     RECT  22.877 68.928 22.892 68.952 ;
     RECT  22.892 68.832 22.949 68.952 ;
     RECT  22.885 44.112 23.065 44.136 ;
     RECT  22.813 41.712 23.317 42.984 ;
     RECT  23.065 44.016 23.317 44.136 ;
     RECT  22.949 68.832 23.353 69 ;
     RECT  23.353 68.784 23.437 69 ;
     RECT  23.437 68.784 23.459 68.808 ;
     RECT  22.451 67.2 23.569 67.272 ;
     RECT  23.569 67.2 23.605 67.8 ;
     RECT  23.605 67.104 23.713 67.8 ;
     RECT  22.889 64.944 23.965 64.968 ;
     RECT  23.713 66.72 23.987 67.8 ;
     RECT  20.435 23.664 24.008 23.688 ;
     RECT  20.476 25.152 24.008 25.176 ;
     RECT  22.813 26.304 24.008 26.664 ;
     RECT  18.904 36.576 24.008 36.6 ;
     RECT  23.317 41.712 24.008 44.136 ;
     RECT  22.885 45.744 24.008 48.168 ;
     RECT  22.885 51.936 24.008 51.96 ;
     RECT  22.529 62.448 24.008 63.288 ;
     RECT  23.965 64.608 24.008 64.968 ;
     RECT  23.987 66.72 24.008 67.32 ;
     RECT  24.008 2.148 24.112 67.32 ;
     RECT  24.112 2.418 24.304 67.32 ;
     RECT  24.304 62.448 24.617 63.288 ;
     RECT  24.617 62.448 24.797 63.24 ;
     RECT  24.304 66.72 25.139 67.32 ;
     RECT  24.797 62.832 25.229 63.24 ;
     RECT  25.229 63.024 25.265 63.24 ;
     RECT  24.304 44.976 25.441 48.168 ;
     RECT  24.304 23.664 25.513 23.688 ;
     RECT  25.513 23.664 25.765 23.88 ;
     RECT  25.441 44.928 25.805 48.168 ;
     RECT  25.805 44.976 25.877 48.168 ;
     RECT  25.513 58.128 25.949 58.152 ;
     RECT  26.017 64.992 26.237 65.016 ;
     RECT  25.139 66.72 26.665 67.272 ;
     RECT  25.265 63.024 26.725 63.048 ;
     RECT  24.304 25.152 26.773 25.176 ;
     RECT  26.773 25.152 26.813 25.272 ;
     RECT  26.665 66.144 26.845 67.272 ;
     RECT  26.725 63.024 26.849 63.24 ;
     RECT  26.845 65.568 27.059 67.272 ;
     RECT  26.849 63.024 27.205 63.048 ;
     RECT  27.205 62.928 27.301 63.048 ;
     RECT  27.589 68.928 27.779 68.952 ;
     RECT  27.301 62.352 27.877 63.048 ;
     RECT  27.301 64.32 27.877 64.344 ;
     RECT  27.781 68.352 28.115 68.376 ;
     RECT  27.059 66.72 28.211 67.272 ;
     RECT  27.877 62.352 28.213 64.344 ;
     RECT  27.059 65.568 28.213 65.64 ;
     RECT  28.213 62.352 28.217 65.64 ;
     RECT  28.217 62.736 28.393 65.64 ;
     RECT  28.211 67.248 28.429 67.272 ;
     RECT  28.429 67.248 28.691 67.848 ;
     RECT  28.753 39.168 28.933 39.192 ;
     RECT  29.077 68.88 29.173 68.904 ;
     RECT  28.933 39.168 29.257 40.44 ;
     RECT  28.691 67.248 29.257 67.272 ;
     RECT  29.257 39.168 29.401 40.584 ;
     RECT  24.304 41.616 29.401 43.272 ;
     RECT  25.765 23.424 29.408 23.88 ;
     RECT  26.813 25.248 29.408 25.272 ;
     RECT  24.304 26.4 29.408 26.664 ;
     RECT  28.933 34.944 29.408 34.968 ;
     RECT  24.304 36.576 29.408 36.6 ;
     RECT  29.401 39.168 29.408 43.272 ;
     RECT  25.877 45.84 29.408 48.168 ;
     RECT  27.565 52.992 29.408 53.016 ;
     RECT  28.393 62.736 29.408 66.168 ;
     RECT  29.257 67.2 29.408 67.272 ;
     RECT  29.173 68.352 29.459 68.904 ;
     RECT  29.408 2.148 29.512 67.272 ;
     RECT  29.459 68.688 29.555 68.904 ;
     RECT  29.555 68.688 29.651 68.712 ;
     RECT  29.512 2.418 29.704 67.272 ;
     RECT  29.704 62.736 29.801 64.344 ;
     RECT  29.801 62.736 29.939 64.056 ;
     RECT  29.939 62.736 29.981 62.76 ;
     RECT  29.704 65.664 30.449 65.688 ;
     RECT  29.704 66.72 30.697 67.272 ;
     RECT  29.704 26.4 30.769 26.664 ;
     RECT  29.704 45.84 30.805 48.168 ;
     RECT  30.769 26.304 30.845 26.664 ;
     RECT  30.697 66.096 31.421 67.272 ;
     RECT  30.805 45.744 31.597 48.168 ;
     RECT  29.704 25.248 31.621 25.272 ;
     RECT  30.845 26.304 31.621 26.568 ;
     RECT  31.621 25.248 31.667 26.568 ;
     RECT  31.301 68.352 31.777 68.376 ;
     RECT  31.705 31.968 31.961 31.992 ;
     RECT  31.597 45.504 31.961 48.168 ;
     RECT  31.777 68.352 32.051 69 ;
     RECT  31.667 25.728 32.101 26.568 ;
     RECT  32.051 68.352 32.339 68.952 ;
     RECT  29.939 63.792 32.425 64.056 ;
     RECT  32.425 63.216 32.533 64.056 ;
     RECT  32.533 63.216 32.54 64.344 ;
     RECT  32.54 63.12 32.573 64.344 ;
     RECT  32.573 63.12 32.627 63.24 ;
     RECT  32.627 63.216 32.771 63.24 ;
     RECT  31.421 66.72 32.893 67.272 ;
     RECT  32.339 68.928 32.915 68.952 ;
     RECT  32.101 25.728 32.929 26.664 ;
     RECT  32.893 66.72 33.107 67.848 ;
     RECT  32.929 25.728 33.257 26.76 ;
     RECT  32.573 64.32 33.541 64.344 ;
     RECT  33.257 26.304 33.581 26.76 ;
     RECT  29.704 34.944 33.613 34.968 ;
     RECT  33.613 34.944 33.653 35.064 ;
     RECT  33.541 63.648 33.733 64.344 ;
     RECT  33.733 63.648 33.932 64.44 ;
     RECT  33.901 33.6 33.973 33.624 ;
     RECT  33.637 68.832 34.021 68.856 ;
     RECT  33.932 63.216 34.203 64.44 ;
     RECT  33.107 66.72 34.261 67.272 ;
     RECT  34.021 68.832 34.265 69 ;
     RECT  31.961 45.744 34.309 48.168 ;
     RECT  34.265 68.832 34.309 68.952 ;
     RECT  33.581 26.304 34.657 26.664 ;
     RECT  34.261 66.336 34.729 67.272 ;
     RECT  34.309 68.784 34.729 68.952 ;
     RECT  34.657 2.832 34.808 2.856 ;
     RECT  34.693 6.288 34.808 6.312 ;
     RECT  29.704 23.424 34.808 23.88 ;
     RECT  34.657 25.728 34.808 26.664 ;
     RECT  33.973 33.552 34.808 33.624 ;
     RECT  33.653 35.04 34.808 35.064 ;
     RECT  29.704 36.576 34.808 36.6 ;
     RECT  29.704 39.456 34.808 43.272 ;
     RECT  34.309 45.744 34.808 48.456 ;
     RECT  34.453 51.984 34.808 52.008 ;
     RECT  34.203 63.216 34.808 64.488 ;
     RECT  34.729 66.336 34.808 68.952 ;
     RECT  34.808 2.148 35.017 68.952 ;
     RECT  35.017 1.872 35.104 68.952 ;
     RECT  35.104 61.008 35.273 61.032 ;
     RECT  35.104 5.088 35.28 6.312 ;
     RECT  35.104 66.096 35.315 68.952 ;
     RECT  35.315 68.928 35.363 68.952 ;
     RECT  35.104 1.872 35.377 4.104 ;
     RECT  35.104 62.592 35.411 64.392 ;
     RECT  35.315 66.096 35.411 67.848 ;
     RECT  35.104 33.6 35.417 33.624 ;
     RECT  35.377 1.824 35.461 4.104 ;
     RECT  35.104 7.776 35.603 8.088 ;
     RECT  35.104 23.424 35.603 23.64 ;
     RECT  35.104 45.744 35.633 47.88 ;
     RECT  35.305 0.528 35.917 0.552 ;
     RECT  35.633 45.888 35.957 47.88 ;
     RECT  35.603 8.064 36.035 8.088 ;
     RECT  35.104 25.728 36.035 26.664 ;
     RECT  35.461 1.728 36.097 4.104 ;
     RECT  35.917 0.144 36.133 0.552 ;
     RECT  36.097 1.68 36.133 4.104 ;
     RECT  35.411 62.688 36.229 64.392 ;
     RECT  36.035 26.016 36.245 26.664 ;
     RECT  36.133 0.144 36.277 4.104 ;
     RECT  35.28 5.088 36.277 5.112 ;
     RECT  36.229 62.688 36.389 65.016 ;
     RECT  35.411 66.096 36.421 67.32 ;
     RECT  36.389 62.736 36.461 65.016 ;
     RECT  36.277 0.144 36.467 5.112 ;
     RECT  36.461 62.832 36.508 65.016 ;
     RECT  36.467 1.68 36.529 5.112 ;
     RECT  36.529 1.68 36.659 5.16 ;
     RECT  36.421 66.096 36.713 67.848 ;
     RECT  36.659 1.728 36.925 5.16 ;
     RECT  35.28 6.288 36.925 6.312 ;
     RECT  36.713 66.48 36.947 67.848 ;
     RECT  36.997 68.4 37.169 68.424 ;
     RECT  36.947 66.48 37.181 67.272 ;
     RECT  36.508 62.976 37.217 65.016 ;
     RECT  37.169 68.4 37.253 69 ;
     RECT  35.957 45.936 37.285 47.88 ;
     RECT  37.217 62.976 37.325 64.104 ;
     RECT  37.253 68.4 37.331 68.424 ;
     RECT  36.925 1.728 37.429 6.312 ;
     RECT  37.325 62.976 37.532 63.96 ;
     RECT  36.467 0.144 37.609 0.6 ;
     RECT  37.532 62.592 37.619 63.96 ;
     RECT  37.609 0.096 37.715 0.6 ;
     RECT  37.429 1.728 37.853 6.888 ;
     RECT  37.285 45.936 37.861 48.12 ;
     RECT  37.853 1.728 37.937 7.464 ;
     RECT  37.715 0.144 38.003 0.6 ;
     RECT  38.003 0.144 38.099 0.168 ;
     RECT  37.937 1.728 38.233 6.648 ;
     RECT  38.233 1.728 38.369 3.672 ;
     RECT  37.861 45.936 38.549 48.36 ;
     RECT  38.549 45.936 38.729 48.12 ;
     RECT  37.619 62.832 38.769 63.96 ;
     RECT  35.104 39.456 38.797 43.272 ;
     RECT  38.769 62.64 38.821 63.96 ;
     RECT  38.797 39.264 38.941 43.272 ;
     RECT  38.233 4.8 38.977 6.648 ;
     RECT  38.369 2.304 39.265 3.672 ;
     RECT  38.977 4.8 39.265 7.128 ;
     RECT  37.181 66.72 39.373 67.272 ;
     RECT  39.265 2.304 39.397 7.128 ;
     RECT  38.977 0.528 39.493 0.552 ;
     RECT  39.493 0.528 39.589 1.176 ;
     RECT  39.397 2.304 39.589 7.512 ;
     RECT  39.589 0.528 39.697 7.512 ;
     RECT  38.761 8.496 39.697 8.52 ;
     RECT  38.821 62.64 39.788 64.584 ;
     RECT  39.373 66.72 39.877 67.848 ;
     RECT  39.397 68.928 39.877 68.952 ;
     RECT  39.697 0.528 39.925 8.52 ;
     RECT  39.925 0.192 40.019 8.52 ;
     RECT  39.877 66.72 40.019 68.952 ;
     RECT  40.019 0.192 40.021 0.408 ;
     RECT  40.019 1.728 40.208 8.52 ;
     RECT  35.603 23.616 40.208 23.64 ;
     RECT  36.245 26.4 40.208 26.664 ;
     RECT  35.104 36.576 40.208 36.6 ;
     RECT  38.941 38.304 40.208 43.272 ;
     RECT  38.729 45.936 40.208 47.736 ;
     RECT  35.104 51.984 40.208 52.008 ;
     RECT  39.788 62.592 40.208 64.584 ;
     RECT  40.019 66.72 40.208 67.08 ;
     RECT  40.019 68.736 40.307 68.952 ;
     RECT  40.208 1.728 40.504 67.08 ;
     RECT  40.021 0.144 40.625 0.408 ;
     RECT  40.504 1.728 40.643 8.52 ;
     RECT  40.643 1.728 40.673 8.232 ;
     RECT  40.504 39.216 40.673 43.272 ;
     RECT  40.625 0.096 40.709 0.408 ;
     RECT  40.709 0.192 40.739 0.408 ;
     RECT  40.307 68.88 40.739 68.952 ;
     RECT  40.673 39.264 40.745 43.272 ;
     RECT  40.673 1.728 40.781 2.616 ;
     RECT  40.504 51.984 40.925 52.2 ;
     RECT  40.739 0.288 40.931 0.408 ;
     RECT  40.739 68.928 40.931 68.952 ;
     RECT  40.781 1.728 40.997 2.328 ;
     RECT  40.673 3.648 40.997 8.232 ;
     RECT  40.504 66.72 41.029 67.08 ;
     RECT  40.504 62.736 41.033 63.672 ;
     RECT  40.988 0.528 41.075 0.552 ;
     RECT  40.925 52.176 41.267 52.2 ;
     RECT  40.997 1.728 41.465 1.848 ;
     RECT  41.465 1.728 41.501 1.8 ;
     RECT  41.501 1.776 41.573 1.8 ;
     RECT  40.504 65.088 41.573 65.112 ;
     RECT  41.033 62.736 41.789 63.288 ;
     RECT  40.997 4.368 41.893 8.232 ;
     RECT  41.029 66.72 41.965 67.272 ;
     RECT  41.893 4.368 42.041 8.424 ;
     RECT  41.789 62.832 42.181 63.288 ;
     RECT  42.041 4.368 42.325 8.184 ;
     RECT  42.325 4.272 42.397 8.184 ;
     RECT  42.181 68.928 42.467 68.952 ;
     RECT  41.965 66.72 42.613 67.848 ;
     RECT  42.173 0.096 42.641 0.12 ;
     RECT  42.641 0.096 42.685 0.168 ;
     RECT  40.504 26.4 42.757 26.664 ;
     RECT  42.397 3.552 42.869 8.184 ;
     RECT  42.685 0.048 42.949 0.168 ;
     RECT  42.949 0.048 43.045 0.936 ;
     RECT  42.181 62.832 43.153 63.528 ;
     RECT  42.613 66.72 43.187 68.424 ;
     RECT  43.045 0.048 43.333 0.984 ;
     RECT  42.565 2.4 43.333 2.424 ;
     RECT  43.333 0.048 43.429 2.424 ;
     RECT  42.869 3.552 43.481 7.992 ;
     RECT  40.745 39.456 43.513 43.272 ;
     RECT  43.429 0.048 43.549 2.568 ;
     RECT  43.481 3.552 43.549 7.896 ;
     RECT  43.187 66.72 43.621 67.848 ;
     RECT  43.621 66.672 43.805 67.848 ;
     RECT  43.805 67.152 43.841 67.848 ;
     RECT  43.549 0.048 43.913 7.896 ;
     RECT  43.621 34.704 44.161 34.728 ;
     RECT  43.153 62.832 44.233 63.864 ;
     RECT  43.913 4.272 44.381 7.896 ;
     RECT  44.101 68.928 44.437 68.952 ;
     RECT  44.381 4.272 44.489 7.848 ;
     RECT  43.841 67.248 44.531 67.848 ;
     RECT  44.233 62.832 44.533 64.488 ;
     RECT  44.437 68.832 44.677 68.952 ;
     RECT  44.677 68.64 44.837 68.952 ;
     RECT  43.913 0.048 44.881 3.192 ;
     RECT  44.489 4.272 44.881 7.8 ;
     RECT  44.161 34.176 44.953 34.728 ;
     RECT  44.533 62.832 44.965 65.016 ;
     RECT  44.531 67.248 45.341 67.272 ;
     RECT  44.965 62.832 45.397 65.784 ;
     RECT  44.837 68.64 45.491 69 ;
     RECT  45.491 68.64 45.539 68.76 ;
     RECT  45.539 68.64 45.587 68.664 ;
     RECT  44.881 0.048 45.608 7.8 ;
     RECT  40.504 23.616 45.608 23.64 ;
     RECT  42.757 26.304 45.608 26.664 ;
     RECT  44.953 34.176 45.608 35.544 ;
     RECT  40.504 36.576 45.608 36.6 ;
     RECT  43.513 39.456 45.608 43.32 ;
     RECT  40.504 45.936 45.608 47.736 ;
     RECT  40.504 50.544 45.608 50.568 ;
     RECT  45.397 62.832 45.608 66.072 ;
     RECT  45.341 67.2 45.608 67.272 ;
     RECT  45.608 0.048 45.904 67.272 ;
     RECT  45.904 62.592 45.925 67.272 ;
     RECT  45.904 0.048 46.001 6.888 ;
     RECT  45.904 34.704 46.181 36.936 ;
     RECT  45.925 62.592 46.181 67.32 ;
     RECT  46.181 62.592 46.259 65.688 ;
     RECT  46.259 62.592 46.441 64.968 ;
     RECT  46.181 66.72 46.477 67.32 ;
     RECT  46.001 0.048 46.541 6.408 ;
     RECT  46.181 35.28 46.541 36.936 ;
     RECT  46.477 66.72 46.547 67.272 ;
     RECT  46.547 67.056 46.643 67.272 ;
     RECT  46.541 35.28 46.649 35.544 ;
     RECT  46.541 0.048 46.829 6.312 ;
     RECT  46.441 62.592 46.829 64.344 ;
     RECT  46.789 68.736 46.885 68.76 ;
     RECT  46.885 68.736 46.931 69 ;
     RECT  46.829 0.048 46.937 6.216 ;
     RECT  46.829 62.688 46.937 64.344 ;
     RECT  46.931 68.88 47.078 69 ;
     RECT  45.904 23.616 47.125 23.64 ;
     RECT  46.937 5.76 47.153 6.216 ;
     RECT  47.153 6 47.171 6.216 ;
     RECT  46.649 35.28 47.189 35.304 ;
     RECT  47.078 68.928 47.189 68.952 ;
     RECT  46.937 62.688 47.297 64.008 ;
     RECT  46.937 0.048 47.369 4.728 ;
     RECT  47.369 0.048 47.405 4.536 ;
     RECT  47.297 63.168 47.548 64.008 ;
     RECT  46.541 36.576 47.621 36.936 ;
     RECT  47.405 0.048 47.729 4.008 ;
     RECT  46.643 67.2 47.749 67.272 ;
     RECT  47.729 0.816 47.837 4.008 ;
     RECT  47.837 2.4 48.053 4.008 ;
     RECT  48.053 2.4 48.161 2.808 ;
     RECT  48.161 2.4 48.197 2.712 ;
     RECT  47.621 36.576 48.197 36.6 ;
     RECT  45.904 45.936 48.229 47.736 ;
     RECT  47.837 0.816 48.305 0.888 ;
     RECT  48.229 45.936 48.305 48.024 ;
     RECT  47.548 63.168 48.449 63.768 ;
     RECT  48.305 47.136 48.517 48.024 ;
     RECT  48.197 2.448 48.557 2.712 ;
     RECT  48.449 63.744 48.593 63.768 ;
     RECT  48.557 2.592 48.665 2.712 ;
     RECT  48.665 2.592 48.845 2.616 ;
     RECT  48.053 3.984 48.845 4.008 ;
     RECT  48.517 47.136 48.881 48.456 ;
     RECT  48.305 0.816 48.989 0.84 ;
     RECT  48.956 68.976 49.043 69 ;
     RECT  48.881 47.664 49.205 48.456 ;
     RECT  49.205 47.664 49.457 48.408 ;
     RECT  47.749 66.624 49.601 67.272 ;
     RECT  49.457 48.288 49.637 48.408 ;
     RECT  49.637 48.384 49.673 48.408 ;
     RECT  47.171 6 51.008 6.024 ;
     RECT  47.125 23.424 51.008 23.64 ;
     RECT  45.904 26.4 51.008 26.664 ;
     RECT  45.904 39.456 51.008 43.272 ;
     RECT  48.305 45.936 51.008 45.96 ;
     RECT  45.904 50.544 51.008 50.568 ;
     RECT  49.601 66.624 51.008 66.648 ;
     RECT  51.008 2.148 51.112 66.972 ;
     RECT  51.112 2.418 51.304 66.702 ;
     RECT  51.304 23.424 52.801 23.64 ;
     RECT  52.801 23.424 52.841 23.832 ;
     RECT  51.304 26.4 54.709 26.664 ;
     RECT  51.304 6 56.408 6.024 ;
     RECT  52.841 23.808 56.408 23.832 ;
     RECT  54.709 26.304 56.408 26.664 ;
     RECT  51.304 39.456 56.408 43.272 ;
     RECT  51.304 45.936 56.408 45.96 ;
     RECT  51.304 50.544 56.408 50.568 ;
     RECT  56.408 2.148 56.512 66.972 ;
     RECT  56.512 2.418 56.704 66.702 ;
     RECT  56.704 39.456 58.705 43.272 ;
     RECT  58.705 38.784 58.853 43.272 ;
     RECT  56.704 6 59.651 6.024 ;
     RECT  59.564 22.752 59.651 22.776 ;
     RECT  56.704 45.936 59.713 45.96 ;
     RECT  56.704 26.4 59.785 26.664 ;
     RECT  59.713 45.936 59.785 46.344 ;
     RECT  56.704 50.544 59.821 50.568 ;
     RECT  59.785 25.776 59.852 26.664 ;
     RECT  59.749 27.936 59.852 27.96 ;
     RECT  56.704 23.808 59.857 23.832 ;
     RECT  59.785 30.144 59.857 30.168 ;
     RECT  59.713 35.232 59.857 35.256 ;
     RECT  59.852 25.776 59.897 27.96 ;
     RECT  59.897 25.776 59.939 27.624 ;
     RECT  59.857 30.144 59.987 31.56 ;
     RECT  58.853 39.456 60.073 43.272 ;
     RECT  59.785 45.936 60.149 46.392 ;
     RECT  59.987 30.144 60.185 30.168 ;
     RECT  59.821 50.544 60.253 51.336 ;
     RECT  60.073 38.736 60.257 43.272 ;
     RECT  59.857 35.232 60.433 35.352 ;
     RECT  60.433 35.232 60.505 35.736 ;
     RECT  59.713 44.4 60.793 44.424 ;
     RECT  60.149 45.936 60.793 46.344 ;
     RECT  59.857 23.808 61.009 24.168 ;
     RECT  60.145 33.264 61.009 33.288 ;
     RECT  59.987 31.536 61.045 31.56 ;
     RECT  61.009 23.808 61.081 24.696 ;
     RECT  59.939 25.776 61.081 26.808 ;
     RECT  61.009 33.264 61.117 33.384 ;
     RECT  60.289 37.632 61.117 37.656 ;
     RECT  60.505 35.232 61.477 36.168 ;
     RECT  61.117 37.44 61.477 37.656 ;
     RECT  60.257 39.312 61.477 43.272 ;
     RECT  61.513 22.224 61.585 22.248 ;
     RECT  61.477 39.072 61.657 43.272 ;
     RECT  61.657 38.784 61.765 43.272 ;
     RECT  61.477 34.368 61.801 37.656 ;
     RECT  61.765 38.784 61.801 43.416 ;
     RECT  61.585 21.504 61.808 22.248 ;
     RECT  61.081 23.808 61.808 26.808 ;
     RECT  61.117 28.944 61.808 28.968 ;
     RECT  61.045 31.536 61.808 31.8 ;
     RECT  61.117 33.024 61.808 33.384 ;
     RECT  61.801 34.368 61.808 43.416 ;
     RECT  60.793 44.4 61.808 46.344 ;
     RECT  59.893 47.904 61.808 47.928 ;
     RECT  60.253 49.968 61.808 51.336 ;
     RECT  61.808 2.148 61.912 66.972 ;
     RECT  61.912 2.418 62.104 66.702 ;
     RECT  62.104 44.4 62.237 47.832 ;
     RECT  62.104 34.368 62.273 43.416 ;
     RECT  62.273 35.328 62.281 43.416 ;
     RECT  62.104 23.856 62.291 30.168 ;
     RECT  62.104 21.072 62.425 22.488 ;
     RECT  62.104 49.2 62.525 50.952 ;
     RECT  62.291 23.856 62.741 24.12 ;
     RECT  62.291 25.2 63.097 30.168 ;
     RECT  62.237 46.944 63.109 47.832 ;
     RECT  62.281 35.472 63.164 43.416 ;
     RECT  62.237 44.4 63.164 45.96 ;
     RECT  63.097 25.2 63.205 30.744 ;
     RECT  62.104 31.776 63.205 33.384 ;
     RECT  63.164 35.472 63.205 45.96 ;
     RECT  63.109 46.944 63.205 48.456 ;
     RECT  62.104 19.776 63.241 19.8 ;
     RECT  63.205 35.472 63.251 48.456 ;
     RECT  62.425 21.36 63.313 22.488 ;
     RECT  62.741 23.856 63.313 23.928 ;
     RECT  63.205 25.2 63.395 33.384 ;
     RECT  63.395 26.208 63.425 33.384 ;
     RECT  63.241 19.776 63.457 20.328 ;
     RECT  63.313 21.36 63.457 23.928 ;
     RECT  63.395 25.2 63.461 25.224 ;
     RECT  62.525 49.968 63.493 50.952 ;
     RECT  63.457 19.776 63.497 23.928 ;
     RECT  63.493 49.968 63.533 51.096 ;
     RECT  63.425 28.848 63.539 33.384 ;
     RECT  63.251 35.472 63.644 47.832 ;
     RECT  63.497 20.304 63.677 23.928 ;
     RECT  63.677 20.4 63.713 23.928 ;
     RECT  63.644 34.752 63.731 47.832 ;
     RECT  63.539 29.376 63.745 33.384 ;
     RECT  63.731 35.328 63.893 47.832 ;
     RECT  63.713 20.4 63.929 22.776 ;
     RECT  63.893 35.472 63.929 38.76 ;
     RECT  63.893 40.08 63.965 47.592 ;
     RECT  63.929 35.472 64.001 37.704 ;
     RECT  63.533 49.968 64.181 49.992 ;
     RECT  63.929 38.736 64.217 38.76 ;
     RECT  63.425 26.208 64.465 27.48 ;
     RECT  63.745 29.376 64.469 34.104 ;
     RECT  63.713 23.904 64.537 23.928 ;
     RECT  64.465 25.44 64.537 27.48 ;
     RECT  63.929 21.456 64.577 22.776 ;
     RECT  64.537 23.904 64.577 27.48 ;
     RECT  63.533 51.072 64.577 51.096 ;
     RECT  64.577 22.752 64.613 22.776 ;
     RECT  64.577 24.72 64.645 27.48 ;
     RECT  64.357 49.536 64.649 49.56 ;
     RECT  64.469 29.376 64.685 33.048 ;
     RECT  64.685 29.52 64.757 33.048 ;
     RECT  63.965 40.08 64.757 47.304 ;
     RECT  63.929 20.4 64.793 20.424 ;
     RECT  64.645 24.72 64.793 27.72 ;
     RECT  64.757 29.52 64.829 32.04 ;
     RECT  64.469 34.08 64.865 34.104 ;
     RECT  64.829 29.52 64.901 31.656 ;
     RECT  64.001 36.48 64.901 37.704 ;
     RECT  64.757 40.176 64.901 47.304 ;
     RECT  64.793 25.44 64.937 27.72 ;
     RECT  64.577 21.456 64.973 21.768 ;
     RECT  64.937 25.44 64.973 26.664 ;
     RECT  64.901 44.496 64.973 47.304 ;
     RECT  64.001 35.472 65.009 35.496 ;
     RECT  64.901 41.472 65.009 43.272 ;
     RECT  64.901 31.056 65.117 31.656 ;
     RECT  64.901 40.176 65.117 40.44 ;
     RECT  64.757 33.024 65.189 33.048 ;
     RECT  64.973 44.496 65.261 45 ;
     RECT  64.973 45.984 65.513 47.304 ;
     RECT  64.937 27.696 65.621 27.72 ;
     RECT  65.117 31.2 65.801 31.656 ;
     RECT  64.901 36.48 65.945 36.936 ;
     RECT  65.261 44.976 65.945 45 ;
     RECT  65.513 45.984 66.013 46.344 ;
     RECT  65.117 40.368 66.053 40.44 ;
     RECT  64.973 25.824 66.085 25.848 ;
     RECT  65.009 41.472 66.121 42.312 ;
     RECT  65.945 36.528 66.229 36.936 ;
     RECT  66.121 41.472 66.377 42.888 ;
     RECT  65.941 47.616 66.665 47.64 ;
     RECT  66.121 19.92 66.697 19.944 ;
     RECT  64.973 21.504 66.697 21.768 ;
     RECT  65.941 23.184 66.697 23.208 ;
     RECT  66.085 25.2 66.697 25.848 ;
     RECT  66.517 30.768 66.697 30.792 ;
     RECT  66.517 31.776 66.697 31.8 ;
     RECT  66.265 33.024 66.697 33.048 ;
     RECT  66.229 36.528 66.697 37.128 ;
     RECT  66.013 45.84 66.697 46.344 ;
     RECT  66.301 49.968 66.697 49.992 ;
     RECT  66.517 51.12 66.697 51.144 ;
     RECT  66.697 27.408 66.733 27.432 ;
     RECT  66.697 19.92 67.201 20.424 ;
     RECT  66.697 21.504 67.201 23.88 ;
     RECT  66.697 28.464 67.201 28.488 ;
     RECT  66.697 30 67.201 30.792 ;
     RECT  66.697 31.776 67.201 33.048 ;
     RECT  66.121 34.032 67.201 34.056 ;
     RECT  66.697 25.2 67.237 25.896 ;
     RECT  66.733 27.312 67.237 27.432 ;
     RECT  67.201 28.464 67.237 30.792 ;
     RECT  67.201 31.776 67.237 34.056 ;
     RECT  66.697 40.848 67.237 41.16 ;
     RECT  66.377 42.384 67.237 42.888 ;
     RECT  67.201 44.688 67.237 44.712 ;
     RECT  66.697 45.84 67.237 46.92 ;
     RECT  66.697 49.68 67.237 51.144 ;
     RECT  67.201 19.92 67.273 23.88 ;
     RECT  67.237 25.008 67.273 34.248 ;
     RECT  67.237 35.376 67.273 35.4 ;
     RECT  66.697 36.528 67.273 37.8 ;
     RECT  67.237 39.6 67.273 41.16 ;
     RECT  66.697 48.048 67.273 48.552 ;
     RECT  67.237 49.584 67.273 51.144 ;
     RECT  67.237 42.384 67.705 46.92 ;
     RECT  67.273 48.048 67.705 51.144 ;
     RECT  67.273 39.504 67.741 41.16 ;
     RECT  67.273 19.92 67.777 37.8 ;
     RECT  67.741 39.504 67.777 41.256 ;
     RECT  67.777 19.92 67.813 41.256 ;
     RECT  67.705 42.384 67.813 51.144 ;
     RECT  67.813 19.92 68.929 51.144 ;
     RECT  68.929 19.92 69.001 51.24 ;
     RECT  69.001 19.92 69.036 19.944 ;
     RECT  69.001 19.944 69.084 20.016 ;
     RECT  69.001 20.016 69.036 20.04 ;
     RECT  69.001 20.04 69.084 20.112 ;
     RECT  69.001 20.112 69.036 20.136 ;
     RECT  69.001 20.136 69.084 20.208 ;
     RECT  69.001 20.208 69.036 20.232 ;
     RECT  69.001 20.232 69.084 20.304 ;
     RECT  69.001 20.304 69.036 20.328 ;
     RECT  69.001 20.328 69.084 20.4 ;
     RECT  69.001 20.4 69.036 20.424 ;
     RECT  69.001 20.424 69.084 20.496 ;
     RECT  69.001 20.496 69.036 20.52 ;
     RECT  69.001 20.52 69.084 20.592 ;
     RECT  69.001 20.592 69.036 20.616 ;
     RECT  69.001 20.616 69.084 20.688 ;
     RECT  69.001 20.688 69.036 20.712 ;
     RECT  69.001 20.712 69.084 20.784 ;
     RECT  69.001 20.784 69.036 20.808 ;
     RECT  69.001 20.808 69.084 20.88 ;
     RECT  69.001 20.88 69.036 20.904 ;
     RECT  69.001 20.904 69.084 20.976 ;
     RECT  69.001 20.976 69.036 21 ;
     RECT  69.001 21 69.084 21.072 ;
     RECT  69.001 21.072 69.036 21.096 ;
     RECT  69.001 21.096 69.084 21.168 ;
     RECT  69.001 21.168 69.036 21.192 ;
     RECT  69.001 21.192 69.084 21.264 ;
     RECT  69.001 21.264 69.036 21.288 ;
     RECT  69.001 21.288 69.084 21.36 ;
     RECT  69.001 21.36 69.036 21.384 ;
     RECT  69.001 21.384 69.084 21.456 ;
     RECT  69.001 21.456 69.036 21.48 ;
     RECT  69.001 21.48 69.084 21.552 ;
     RECT  69.001 21.552 69.036 21.576 ;
     RECT  69.001 21.576 69.084 21.648 ;
     RECT  69.001 21.648 69.036 21.672 ;
     RECT  69.001 21.672 69.084 21.744 ;
     RECT  69.001 21.744 69.036 21.768 ;
     RECT  69.001 21.768 69.084 21.84 ;
     RECT  69.001 21.84 69.036 21.864 ;
     RECT  69.001 21.864 69.084 21.936 ;
     RECT  69.001 21.936 69.036 21.96 ;
     RECT  69.001 21.96 69.084 22.032 ;
     RECT  69.001 22.032 69.036 22.056 ;
     RECT  69.001 22.056 69.084 22.128 ;
     RECT  69.001 22.128 69.036 22.152 ;
     RECT  69.001 22.152 69.084 22.224 ;
     RECT  69.001 22.224 69.036 22.248 ;
     RECT  69.001 22.248 69.084 22.32 ;
     RECT  69.001 22.32 69.036 22.344 ;
     RECT  69.001 22.344 69.084 22.416 ;
     RECT  69.001 22.416 69.036 22.44 ;
     RECT  69.001 22.44 69.084 22.512 ;
     RECT  69.001 22.512 69.036 22.536 ;
     RECT  69.001 22.536 69.084 22.608 ;
     RECT  69.001 22.608 69.036 22.632 ;
     RECT  69.001 22.632 69.084 22.704 ;
     RECT  69.001 22.704 69.036 22.728 ;
     RECT  69.001 22.728 69.084 22.8 ;
     RECT  69.001 22.8 69.036 22.824 ;
     RECT  69.001 22.824 69.084 22.896 ;
     RECT  69.001 22.896 69.036 22.92 ;
     RECT  69.001 22.92 69.084 22.992 ;
     RECT  69.001 22.992 69.036 23.016 ;
     RECT  69.001 23.016 69.084 23.088 ;
     RECT  69.001 23.088 69.036 23.112 ;
     RECT  69.001 23.112 69.084 23.184 ;
     RECT  69.001 23.184 69.036 23.208 ;
     RECT  69.001 23.208 69.084 23.28 ;
     RECT  69.001 23.28 69.036 23.304 ;
     RECT  69.001 23.304 69.084 23.376 ;
     RECT  69.001 23.376 69.036 23.4 ;
     RECT  69.001 23.4 69.084 23.472 ;
     RECT  69.001 23.472 69.036 23.496 ;
     RECT  69.001 23.496 69.084 23.568 ;
     RECT  69.001 23.568 69.036 23.592 ;
     RECT  69.001 23.592 69.084 23.664 ;
     RECT  69.001 23.664 69.036 23.688 ;
     RECT  69.001 23.688 69.084 23.76 ;
     RECT  69.001 23.76 69.036 23.784 ;
     RECT  69.001 23.784 69.084 23.856 ;
     RECT  69.001 23.856 69.036 23.88 ;
     RECT  69.001 23.88 69.084 23.952 ;
     RECT  69.001 23.952 69.036 23.976 ;
     RECT  69.001 23.976 69.084 24.048 ;
     RECT  69.001 24.048 69.036 24.072 ;
     RECT  69.001 24.072 69.084 24.144 ;
     RECT  69.001 24.144 69.036 24.168 ;
     RECT  69.001 24.168 69.084 24.24 ;
     RECT  69.001 24.24 69.036 24.264 ;
     RECT  69.001 24.264 69.084 24.336 ;
     RECT  69.001 24.336 69.036 24.36 ;
     RECT  69.001 24.36 69.084 24.432 ;
     RECT  69.001 24.432 69.036 24.456 ;
     RECT  69.001 24.456 69.084 24.528 ;
     RECT  69.001 24.528 69.036 24.552 ;
     RECT  69.001 24.552 69.084 24.624 ;
     RECT  69.001 24.624 69.036 24.648 ;
     RECT  69.001 24.648 69.084 24.72 ;
     RECT  69.001 24.72 69.036 24.744 ;
     RECT  69.001 24.744 69.084 24.816 ;
     RECT  69.001 24.816 69.036 24.84 ;
     RECT  69.001 24.84 69.084 24.912 ;
     RECT  69.001 24.912 69.036 24.936 ;
     RECT  69.001 24.936 69.084 25.008 ;
     RECT  69.001 25.008 69.036 25.032 ;
     RECT  69.001 25.032 69.084 25.104 ;
     RECT  69.001 25.104 69.036 25.128 ;
     RECT  69.001 25.128 69.084 25.2 ;
     RECT  69.001 25.2 69.036 25.224 ;
     RECT  69.001 25.224 69.084 25.296 ;
     RECT  69.001 25.296 69.036 25.32 ;
     RECT  69.001 25.32 69.084 25.392 ;
     RECT  69.001 25.392 69.036 25.416 ;
     RECT  69.001 25.416 69.084 25.488 ;
     RECT  69.001 25.488 69.036 25.512 ;
     RECT  69.001 25.512 69.084 25.584 ;
     RECT  69.001 25.584 69.036 25.608 ;
     RECT  69.001 25.608 69.084 25.68 ;
     RECT  69.001 25.68 69.036 25.704 ;
     RECT  69.001 25.704 69.084 25.776 ;
     RECT  69.001 25.776 69.036 25.8 ;
     RECT  69.001 25.8 69.084 25.872 ;
     RECT  69.001 25.872 69.036 25.896 ;
     RECT  69.001 25.896 69.084 25.968 ;
     RECT  69.001 25.968 69.036 25.992 ;
     RECT  69.001 25.992 69.084 26.064 ;
     RECT  69.001 26.064 69.036 26.088 ;
     RECT  69.001 26.088 69.084 26.16 ;
     RECT  69.001 26.16 69.036 26.184 ;
     RECT  69.001 26.184 69.084 26.256 ;
     RECT  69.001 26.256 69.036 26.28 ;
     RECT  69.001 26.28 69.084 26.352 ;
     RECT  69.001 26.352 69.036 26.376 ;
     RECT  69.001 26.376 69.084 26.448 ;
     RECT  69.001 26.448 69.036 26.472 ;
     RECT  69.001 26.472 69.084 26.544 ;
     RECT  69.001 26.544 69.036 26.568 ;
     RECT  69.001 26.568 69.084 26.64 ;
     RECT  69.001 26.64 69.036 26.664 ;
     RECT  69.001 26.664 69.084 26.736 ;
     RECT  69.001 26.736 69.036 26.76 ;
     RECT  69.001 26.76 69.084 26.832 ;
     RECT  69.001 26.832 69.036 26.856 ;
     RECT  69.001 26.856 69.084 26.928 ;
     RECT  69.001 26.928 69.036 26.952 ;
     RECT  69.001 26.952 69.084 27.024 ;
     RECT  69.001 27.024 69.036 27.048 ;
     RECT  69.001 27.048 69.084 27.12 ;
     RECT  69.001 27.12 69.036 27.144 ;
     RECT  69.001 27.144 69.084 27.216 ;
     RECT  69.001 27.216 69.036 27.24 ;
     RECT  69.001 27.24 69.084 27.312 ;
     RECT  69.001 27.312 69.036 27.336 ;
     RECT  69.001 27.336 69.084 27.408 ;
     RECT  69.001 27.408 69.036 27.432 ;
     RECT  69.001 27.432 69.084 27.504 ;
     RECT  69.001 27.504 69.036 27.528 ;
     RECT  69.001 27.528 69.084 27.6 ;
     RECT  69.001 27.6 69.036 27.624 ;
     RECT  69.001 27.624 69.084 27.696 ;
     RECT  69.001 27.696 69.036 27.72 ;
     RECT  69.001 27.72 69.084 27.792 ;
     RECT  69.001 27.792 69.036 27.816 ;
     RECT  69.001 27.816 69.084 27.888 ;
     RECT  69.001 27.888 69.036 27.912 ;
     RECT  69.001 27.912 69.084 27.984 ;
     RECT  69.001 27.984 69.036 28.008 ;
     RECT  69.001 28.008 69.084 28.08 ;
     RECT  69.001 28.08 69.036 28.104 ;
     RECT  69.001 28.104 69.084 28.176 ;
     RECT  69.001 28.176 69.036 28.2 ;
     RECT  69.001 28.2 69.084 28.272 ;
     RECT  69.001 28.272 69.036 28.296 ;
     RECT  69.001 28.296 69.084 28.368 ;
     RECT  69.001 28.368 69.036 28.392 ;
     RECT  69.001 28.392 69.084 28.464 ;
     RECT  69.001 28.464 69.036 28.488 ;
     RECT  69.001 28.488 69.084 28.56 ;
     RECT  69.001 28.56 69.036 28.584 ;
     RECT  69.001 28.584 69.084 28.656 ;
     RECT  69.001 28.656 69.036 28.68 ;
     RECT  69.001 28.68 69.084 28.752 ;
     RECT  69.001 28.752 69.036 28.776 ;
     RECT  69.001 28.776 69.084 28.848 ;
     RECT  69.001 28.848 69.036 28.872 ;
     RECT  69.001 28.872 69.084 28.944 ;
     RECT  69.001 28.944 69.036 28.968 ;
     RECT  69.001 28.968 69.084 29.04 ;
     RECT  69.001 29.04 69.036 29.064 ;
     RECT  69.001 29.064 69.084 29.136 ;
     RECT  69.001 29.136 69.036 29.16 ;
     RECT  69.001 29.16 69.084 29.232 ;
     RECT  69.001 29.232 69.036 29.256 ;
     RECT  69.001 29.256 69.084 29.328 ;
     RECT  69.001 29.328 69.036 29.352 ;
     RECT  69.001 29.352 69.084 29.424 ;
     RECT  69.001 29.424 69.036 29.448 ;
     RECT  69.001 29.448 69.084 29.52 ;
     RECT  69.001 29.52 69.036 29.544 ;
     RECT  69.001 29.544 69.084 29.616 ;
     RECT  69.001 29.616 69.036 29.64 ;
     RECT  69.001 29.64 69.084 29.712 ;
     RECT  69.001 29.712 69.036 29.736 ;
     RECT  69.001 29.736 69.084 29.808 ;
     RECT  69.001 29.808 69.036 29.832 ;
     RECT  69.001 29.832 69.084 29.904 ;
     RECT  69.001 29.904 69.036 29.928 ;
     RECT  69.001 29.928 69.084 30 ;
     RECT  69.001 30 69.036 30.024 ;
     RECT  69.001 30.024 69.084 30.096 ;
     RECT  69.001 30.096 69.036 30.12 ;
     RECT  69.001 30.12 69.084 30.192 ;
     RECT  69.001 30.192 69.036 30.216 ;
     RECT  69.001 30.216 69.084 30.288 ;
     RECT  69.001 30.288 69.036 30.312 ;
     RECT  69.001 30.312 69.084 30.384 ;
     RECT  69.001 30.384 69.036 30.408 ;
     RECT  69.001 30.408 69.084 30.48 ;
     RECT  69.001 30.48 69.036 30.504 ;
     RECT  69.001 30.504 69.084 30.576 ;
     RECT  69.001 30.576 69.036 30.6 ;
     RECT  69.001 30.6 69.084 30.672 ;
     RECT  69.001 30.672 69.036 30.696 ;
     RECT  69.001 30.696 69.084 30.768 ;
     RECT  69.001 30.768 69.036 30.792 ;
     RECT  69.001 30.792 69.084 30.864 ;
     RECT  69.001 30.864 69.036 30.888 ;
     RECT  69.001 30.888 69.084 30.96 ;
     RECT  69.001 30.96 69.036 30.984 ;
     RECT  69.001 30.984 69.084 31.056 ;
     RECT  69.001 31.056 69.036 31.08 ;
     RECT  69.001 31.08 69.084 31.152 ;
     RECT  69.001 31.152 69.036 31.176 ;
     RECT  69.001 31.176 69.084 31.248 ;
     RECT  69.001 31.248 69.036 31.272 ;
     RECT  69.001 31.272 69.084 31.344 ;
     RECT  69.001 31.344 69.036 31.368 ;
     RECT  69.001 31.368 69.084 31.44 ;
     RECT  69.001 31.44 69.036 31.464 ;
     RECT  69.001 31.464 69.084 31.536 ;
     RECT  69.001 31.536 69.036 31.56 ;
     RECT  69.001 31.56 69.084 31.632 ;
     RECT  69.001 31.632 69.036 31.656 ;
     RECT  69.001 31.656 69.084 31.728 ;
     RECT  69.001 31.728 69.036 31.752 ;
     RECT  69.001 31.752 69.084 31.824 ;
     RECT  69.001 31.824 69.036 31.848 ;
     RECT  69.001 31.848 69.084 31.92 ;
     RECT  69.001 31.92 69.036 31.944 ;
     RECT  69.001 31.944 69.084 32.016 ;
     RECT  69.001 32.016 69.036 32.04 ;
     RECT  69.001 32.04 69.084 32.112 ;
     RECT  69.001 32.112 69.036 32.136 ;
     RECT  69.001 32.136 69.084 32.208 ;
     RECT  69.001 32.208 69.036 32.232 ;
     RECT  69.001 32.232 69.084 32.304 ;
     RECT  69.001 32.304 69.036 32.328 ;
     RECT  69.001 32.328 69.084 32.4 ;
     RECT  69.001 32.4 69.036 32.424 ;
     RECT  69.001 32.424 69.084 32.496 ;
     RECT  69.001 32.496 69.036 32.52 ;
     RECT  69.001 32.52 69.084 32.592 ;
     RECT  69.001 32.592 69.036 32.616 ;
     RECT  69.001 32.616 69.084 32.688 ;
     RECT  69.001 32.688 69.036 32.712 ;
     RECT  69.001 32.712 69.084 32.784 ;
     RECT  69.001 32.784 69.036 32.808 ;
     RECT  69.001 32.808 69.084 32.88 ;
     RECT  69.001 32.88 69.036 32.904 ;
     RECT  69.001 32.904 69.084 32.976 ;
     RECT  69.001 32.976 69.036 33 ;
     RECT  69.001 33 69.084 33.072 ;
     RECT  69.001 33.072 69.036 33.096 ;
     RECT  69.001 33.096 69.084 33.168 ;
     RECT  69.001 33.168 69.036 33.192 ;
     RECT  69.001 33.192 69.084 33.264 ;
     RECT  69.001 33.264 69.036 33.288 ;
     RECT  69.001 33.288 69.084 33.36 ;
     RECT  69.001 33.36 69.036 33.384 ;
     RECT  69.001 33.384 69.084 33.456 ;
     RECT  69.001 33.456 69.036 33.48 ;
     RECT  69.001 33.48 69.084 33.552 ;
     RECT  69.001 33.552 69.036 33.576 ;
     RECT  69.001 33.576 69.084 33.648 ;
     RECT  69.001 33.648 69.036 33.672 ;
     RECT  69.001 33.672 69.084 33.744 ;
     RECT  69.001 33.744 69.036 33.768 ;
     RECT  69.001 33.768 69.084 33.84 ;
     RECT  69.001 33.84 69.036 33.864 ;
     RECT  69.001 33.864 69.084 33.936 ;
     RECT  69.001 33.936 69.036 33.96 ;
     RECT  69.001 33.96 69.084 34.032 ;
     RECT  69.001 34.032 69.036 34.056 ;
     RECT  69.001 34.056 69.084 34.128 ;
     RECT  69.001 34.128 69.036 34.152 ;
     RECT  69.001 34.152 69.084 34.224 ;
     RECT  69.001 34.224 69.036 34.248 ;
     RECT  69.001 34.248 69.084 34.32 ;
     RECT  69.001 34.32 69.036 34.344 ;
     RECT  69.001 34.344 69.084 34.416 ;
     RECT  69.001 34.416 69.036 34.44 ;
     RECT  69.001 34.44 69.084 34.512 ;
     RECT  69.001 34.512 69.036 34.536 ;
     RECT  69.001 34.536 69.084 34.608 ;
     RECT  69.001 34.608 69.036 34.632 ;
     RECT  69.001 34.632 69.084 34.704 ;
     RECT  69.001 34.704 69.036 34.728 ;
     RECT  69.001 34.728 69.084 34.8 ;
     RECT  69.001 34.8 69.036 34.824 ;
     RECT  69.001 34.824 69.084 34.896 ;
     RECT  69.001 34.896 69.036 34.92 ;
     RECT  69.001 34.92 69.084 34.992 ;
     RECT  69.001 34.992 69.036 35.016 ;
     RECT  69.001 35.016 69.084 35.088 ;
     RECT  69.001 35.088 69.036 35.112 ;
     RECT  69.001 35.112 69.084 35.184 ;
     RECT  69.001 35.184 69.036 35.208 ;
     RECT  69.001 35.208 69.084 35.28 ;
     RECT  69.001 35.28 69.036 35.304 ;
     RECT  69.001 35.304 69.084 35.376 ;
     RECT  69.001 35.376 69.036 35.4 ;
     RECT  69.001 35.4 69.084 35.472 ;
     RECT  69.001 35.472 69.036 35.496 ;
     RECT  69.001 35.496 69.084 35.568 ;
     RECT  69.001 35.568 69.036 35.592 ;
     RECT  69.001 35.592 69.084 35.664 ;
     RECT  69.001 35.664 69.036 35.688 ;
     RECT  69.001 35.688 69.084 35.76 ;
     RECT  69.001 35.76 69.036 35.784 ;
     RECT  69.001 35.784 69.084 35.856 ;
     RECT  69.001 35.856 69.036 35.88 ;
     RECT  69.001 35.88 69.084 35.952 ;
     RECT  69.001 35.952 69.036 35.976 ;
     RECT  69.001 35.976 69.084 36.048 ;
     RECT  69.001 36.048 69.036 36.072 ;
     RECT  69.001 36.072 69.084 36.144 ;
     RECT  69.001 36.144 69.036 36.168 ;
     RECT  69.001 36.168 69.084 36.24 ;
     RECT  69.001 36.24 69.036 36.264 ;
     RECT  69.001 36.264 69.084 36.336 ;
     RECT  69.001 36.336 69.036 36.36 ;
     RECT  69.001 36.36 69.084 36.432 ;
     RECT  69.001 36.432 69.036 36.456 ;
     RECT  69.001 36.456 69.084 36.528 ;
     RECT  69.001 36.528 69.036 36.552 ;
     RECT  69.001 36.552 69.084 36.624 ;
     RECT  69.001 36.624 69.036 36.648 ;
     RECT  69.001 36.648 69.084 36.72 ;
     RECT  69.001 36.72 69.036 36.744 ;
     RECT  69.001 36.744 69.084 36.816 ;
     RECT  69.001 36.816 69.036 36.84 ;
     RECT  69.001 36.84 69.084 36.912 ;
     RECT  69.001 36.912 69.036 36.936 ;
     RECT  69.001 36.936 69.084 37.008 ;
     RECT  69.001 37.008 69.036 37.032 ;
     RECT  69.001 37.032 69.084 37.104 ;
     RECT  69.001 37.104 69.036 37.128 ;
     RECT  69.001 37.128 69.084 37.2 ;
     RECT  69.001 37.2 69.036 37.224 ;
     RECT  69.001 37.224 69.084 37.296 ;
     RECT  69.001 37.296 69.036 37.32 ;
     RECT  69.001 37.32 69.084 37.392 ;
     RECT  69.001 37.392 69.036 37.416 ;
     RECT  69.001 37.416 69.084 37.488 ;
     RECT  69.001 37.488 69.036 37.512 ;
     RECT  69.001 37.512 69.084 37.584 ;
     RECT  69.001 37.584 69.036 37.608 ;
     RECT  69.001 37.608 69.084 37.68 ;
     RECT  69.001 37.68 69.036 37.704 ;
     RECT  69.001 37.704 69.084 37.776 ;
     RECT  69.001 37.776 69.036 37.8 ;
     RECT  69.001 37.8 69.084 37.872 ;
     RECT  69.001 37.872 69.036 37.896 ;
     RECT  69.001 37.896 69.084 37.968 ;
     RECT  69.001 37.968 69.036 37.992 ;
     RECT  69.001 37.992 69.084 38.064 ;
     RECT  69.001 38.064 69.036 38.088 ;
     RECT  69.001 38.088 69.084 38.16 ;
     RECT  69.001 38.16 69.036 38.184 ;
     RECT  69.001 38.184 69.084 38.256 ;
     RECT  69.001 38.256 69.036 38.28 ;
     RECT  69.001 38.28 69.084 39.12 ;
     RECT  69.001 39.12 69.036 39.144 ;
     RECT  69.001 39.144 69.084 39.216 ;
     RECT  69.001 39.216 69.036 39.24 ;
     RECT  69.001 39.24 69.084 39.312 ;
     RECT  69.001 39.312 69.036 39.336 ;
     RECT  69.001 39.336 69.084 39.408 ;
     RECT  69.001 39.408 69.036 39.432 ;
     RECT  69.001 39.432 69.084 39.504 ;
     RECT  69.001 39.504 69.036 39.528 ;
     RECT  69.001 39.528 69.084 39.6 ;
     RECT  69.001 39.6 69.036 39.624 ;
     RECT  69.001 39.624 69.084 39.696 ;
     RECT  69.001 39.696 69.036 39.72 ;
     RECT  69.001 39.72 69.084 39.792 ;
     RECT  69.001 39.792 69.036 39.816 ;
     RECT  69.001 39.816 69.084 39.888 ;
     RECT  69.001 39.888 69.036 39.912 ;
     RECT  69.001 39.912 69.084 39.984 ;
     RECT  69.001 39.984 69.036 40.008 ;
     RECT  69.001 40.008 69.084 40.08 ;
     RECT  69.001 40.08 69.036 40.104 ;
     RECT  69.001 40.104 69.084 40.176 ;
     RECT  69.001 40.176 69.036 40.2 ;
     RECT  69.001 40.2 69.084 40.272 ;
     RECT  69.001 40.272 69.036 40.296 ;
     RECT  69.001 40.296 69.084 40.368 ;
     RECT  69.001 40.368 69.036 40.392 ;
     RECT  69.001 40.392 69.084 40.464 ;
     RECT  69.001 40.464 69.036 40.488 ;
     RECT  69.001 40.488 69.084 40.56 ;
     RECT  69.001 40.56 69.036 40.584 ;
     RECT  69.001 40.584 69.084 40.656 ;
     RECT  69.001 40.656 69.036 40.68 ;
     RECT  69.001 40.68 69.084 40.752 ;
     RECT  69.001 40.752 69.036 40.776 ;
     RECT  69.001 40.776 69.084 40.848 ;
     RECT  69.001 40.848 69.036 40.872 ;
     RECT  69.001 40.872 69.084 40.944 ;
     RECT  69.001 40.944 69.036 40.968 ;
     RECT  69.001 40.968 69.084 41.04 ;
     RECT  69.001 41.04 69.036 41.064 ;
     RECT  69.001 41.064 69.084 41.136 ;
     RECT  69.001 41.136 69.036 41.16 ;
     RECT  69.001 41.16 69.084 41.232 ;
     RECT  69.001 41.232 69.036 41.256 ;
     RECT  69.001 41.256 69.084 41.328 ;
     RECT  69.001 41.328 69.036 41.352 ;
     RECT  69.001 41.352 69.084 41.424 ;
     RECT  69.001 41.424 69.036 41.448 ;
     RECT  69.001 41.448 69.084 41.52 ;
     RECT  69.001 41.52 69.036 41.544 ;
     RECT  69.001 41.544 69.084 41.616 ;
     RECT  69.001 41.616 69.036 41.64 ;
     RECT  69.001 41.64 69.084 41.712 ;
     RECT  69.001 41.712 69.036 41.736 ;
     RECT  69.001 41.736 69.084 41.808 ;
     RECT  69.001 41.808 69.036 41.832 ;
     RECT  69.001 41.832 69.084 41.904 ;
     RECT  69.001 41.904 69.036 41.928 ;
     RECT  69.001 41.928 69.084 42 ;
     RECT  69.001 42 69.036 42.024 ;
     RECT  69.001 42.024 69.084 42.096 ;
     RECT  69.001 42.096 69.036 42.12 ;
     RECT  69.001 42.12 69.084 42.192 ;
     RECT  69.001 42.192 69.036 42.216 ;
     RECT  69.001 42.216 69.084 42.288 ;
     RECT  69.001 42.288 69.036 42.312 ;
     RECT  69.001 42.312 69.084 42.384 ;
     RECT  69.001 42.384 69.036 42.408 ;
     RECT  69.001 42.408 69.084 42.48 ;
     RECT  69.001 42.48 69.036 42.504 ;
     RECT  69.001 42.504 69.084 42.576 ;
     RECT  69.001 42.576 69.036 42.6 ;
     RECT  69.001 42.6 69.084 42.672 ;
     RECT  69.001 42.672 69.036 42.696 ;
     RECT  69.001 42.696 69.084 42.768 ;
     RECT  69.001 42.768 69.036 42.792 ;
     RECT  69.001 42.792 69.084 42.864 ;
     RECT  69.001 42.864 69.036 42.888 ;
     RECT  69.001 42.888 69.084 42.96 ;
     RECT  69.001 42.96 69.036 42.984 ;
     RECT  69.001 42.984 69.084 43.056 ;
     RECT  69.001 43.056 69.036 43.08 ;
     RECT  69.001 43.08 69.084 43.152 ;
     RECT  69.001 43.152 69.036 43.176 ;
     RECT  69.001 43.176 69.084 43.248 ;
     RECT  69.001 43.248 69.036 43.272 ;
     RECT  69.001 43.272 69.084 43.344 ;
     RECT  69.001 43.344 69.036 43.368 ;
     RECT  69.001 43.368 69.084 43.44 ;
     RECT  69.001 43.44 69.036 43.464 ;
     RECT  69.001 43.464 69.084 43.536 ;
     RECT  69.001 43.536 69.036 43.56 ;
     RECT  69.001 43.56 69.084 43.632 ;
     RECT  69.001 43.632 69.036 43.656 ;
     RECT  69.001 43.656 69.084 43.728 ;
     RECT  69.001 43.728 69.036 43.752 ;
     RECT  69.001 43.752 69.084 43.824 ;
     RECT  69.001 43.824 69.036 43.848 ;
     RECT  69.001 43.848 69.084 43.92 ;
     RECT  69.001 43.92 69.036 43.944 ;
     RECT  69.001 43.944 69.084 44.016 ;
     RECT  69.001 44.016 69.036 44.04 ;
     RECT  69.001 44.04 69.084 44.112 ;
     RECT  69.001 44.112 69.036 44.136 ;
     RECT  69.001 44.136 69.084 44.208 ;
     RECT  69.001 44.208 69.036 44.232 ;
     RECT  69.001 44.232 69.084 44.304 ;
     RECT  69.001 44.304 69.036 44.328 ;
     RECT  69.001 44.328 69.084 44.4 ;
     RECT  69.001 44.4 69.036 44.424 ;
     RECT  69.001 44.424 69.084 44.496 ;
     RECT  69.001 44.496 69.036 44.52 ;
     RECT  69.001 44.52 69.084 44.592 ;
     RECT  69.001 44.592 69.036 44.616 ;
     RECT  69.001 44.616 69.084 44.688 ;
     RECT  69.001 44.688 69.036 44.712 ;
     RECT  69.001 44.712 69.084 44.784 ;
     RECT  69.001 44.784 69.036 44.808 ;
     RECT  69.001 44.808 69.084 44.88 ;
     RECT  69.001 44.88 69.036 44.904 ;
     RECT  69.001 44.904 69.084 44.976 ;
     RECT  69.001 44.976 69.036 45 ;
     RECT  69.001 45 69.084 45.072 ;
     RECT  69.001 45.072 69.036 45.096 ;
     RECT  69.001 45.096 69.084 45.168 ;
     RECT  69.001 45.168 69.036 45.192 ;
     RECT  69.001 45.192 69.084 45.264 ;
     RECT  69.001 45.264 69.036 45.288 ;
     RECT  69.001 45.288 69.084 45.36 ;
     RECT  69.001 45.36 69.036 45.384 ;
     RECT  69.001 45.384 69.084 45.456 ;
     RECT  69.001 45.456 69.036 45.48 ;
     RECT  69.001 45.48 69.084 45.552 ;
     RECT  69.001 45.552 69.036 45.576 ;
     RECT  69.001 45.576 69.084 45.648 ;
     RECT  69.001 45.648 69.036 45.672 ;
     RECT  69.001 45.672 69.084 45.744 ;
     RECT  69.001 45.744 69.036 45.768 ;
     RECT  69.001 45.768 69.084 45.84 ;
     RECT  69.001 45.84 69.036 45.864 ;
     RECT  69.001 45.864 69.084 45.936 ;
     RECT  69.001 45.936 69.036 45.96 ;
     RECT  69.001 45.96 69.084 46.032 ;
     RECT  69.001 46.032 69.036 46.056 ;
     RECT  69.001 46.056 69.084 46.128 ;
     RECT  69.001 46.128 69.036 46.152 ;
     RECT  69.001 46.152 69.084 46.224 ;
     RECT  69.001 46.224 69.036 46.248 ;
     RECT  69.001 46.248 69.084 46.32 ;
     RECT  69.001 46.32 69.036 46.344 ;
     RECT  69.001 46.344 69.084 46.416 ;
     RECT  69.001 46.416 69.036 46.44 ;
     RECT  69.001 46.44 69.084 46.512 ;
     RECT  69.001 46.512 69.036 46.536 ;
     RECT  69.001 46.536 69.084 46.608 ;
     RECT  69.001 46.608 69.036 46.632 ;
     RECT  69.001 46.632 69.084 46.704 ;
     RECT  69.001 46.704 69.036 46.728 ;
     RECT  69.001 46.728 69.084 46.8 ;
     RECT  69.001 46.8 69.036 46.824 ;
     RECT  69.001 46.824 69.084 46.896 ;
     RECT  69.001 46.896 69.036 46.92 ;
     RECT  69.001 46.92 69.084 46.992 ;
     RECT  69.001 46.992 69.036 47.016 ;
     RECT  69.001 47.016 69.084 47.088 ;
     RECT  69.001 47.088 69.036 47.112 ;
     RECT  69.001 47.112 69.084 47.184 ;
     RECT  69.001 47.184 69.036 47.208 ;
     RECT  69.001 47.208 69.084 47.28 ;
     RECT  69.001 47.28 69.036 47.304 ;
     RECT  69.001 47.304 69.084 47.376 ;
     RECT  69.001 47.376 69.036 47.4 ;
     RECT  69.001 47.4 69.084 47.472 ;
     RECT  69.001 47.472 69.036 47.496 ;
     RECT  69.001 47.496 69.084 47.568 ;
     RECT  69.001 47.568 69.036 47.592 ;
     RECT  69.001 47.592 69.084 47.664 ;
     RECT  69.001 47.664 69.036 47.688 ;
     RECT  69.001 47.688 69.084 47.76 ;
     RECT  69.001 47.76 69.036 47.784 ;
     RECT  69.001 47.784 69.084 47.856 ;
     RECT  69.001 47.856 69.036 47.88 ;
     RECT  69.001 47.88 69.084 47.952 ;
     RECT  69.001 47.952 69.036 47.976 ;
     RECT  69.001 47.976 69.084 48.048 ;
     RECT  69.001 48.048 69.036 48.072 ;
     RECT  69.001 48.072 69.084 48.144 ;
     RECT  69.001 48.144 69.036 48.168 ;
     RECT  69.001 48.168 69.084 48.24 ;
     RECT  69.001 48.24 69.036 48.264 ;
     RECT  69.001 48.264 69.084 48.336 ;
     RECT  69.001 48.336 69.036 48.36 ;
     RECT  69.001 48.36 69.084 48.432 ;
     RECT  69.001 48.432 69.036 48.456 ;
     RECT  69.001 48.456 69.084 48.528 ;
     RECT  69.001 48.528 69.036 48.552 ;
     RECT  69.001 48.552 69.084 48.624 ;
     RECT  69.001 48.624 69.036 48.648 ;
     RECT  69.001 48.648 69.084 48.72 ;
     RECT  69.001 48.72 69.036 48.744 ;
     RECT  69.001 48.744 69.084 48.816 ;
     RECT  69.001 48.816 69.036 48.84 ;
     RECT  69.001 48.84 69.084 48.912 ;
     RECT  69.001 48.912 69.036 48.936 ;
     RECT  69.001 48.936 69.084 49.008 ;
     RECT  69.001 49.008 69.036 49.032 ;
     RECT  69.001 49.032 69.084 49.104 ;
     RECT  69.001 49.104 69.036 49.128 ;
     RECT  69.001 49.128 69.084 49.2 ;
     RECT  69.001 49.2 69.036 49.224 ;
     RECT  69.001 49.224 69.084 49.296 ;
     RECT  69.001 49.296 69.036 49.32 ;
     RECT  69.001 49.32 69.084 49.392 ;
     RECT  69.001 49.392 69.036 49.416 ;
     RECT  69.001 49.416 69.084 49.488 ;
     RECT  69.001 49.488 69.036 49.512 ;
     RECT  69.001 49.512 69.084 49.584 ;
     RECT  69.001 49.584 69.036 49.608 ;
     RECT  69.001 49.608 69.084 49.68 ;
     RECT  69.001 49.68 69.036 49.704 ;
     RECT  69.001 49.704 69.084 49.776 ;
     RECT  69.001 49.776 69.036 49.8 ;
     RECT  69.001 49.8 69.084 49.872 ;
     RECT  69.001 49.872 69.036 49.896 ;
     RECT  69.001 49.896 69.084 49.968 ;
     RECT  69.001 49.968 69.036 49.992 ;
     RECT  69.001 49.992 69.084 50.064 ;
     RECT  69.001 50.064 69.036 50.088 ;
     RECT  69.001 50.088 69.084 50.16 ;
     RECT  69.001 50.16 69.036 50.184 ;
     RECT  69.001 50.184 69.084 50.256 ;
     RECT  69.001 50.256 69.036 50.28 ;
     RECT  69.001 50.28 69.084 50.352 ;
     RECT  69.001 50.352 69.036 50.376 ;
     RECT  69.001 50.376 69.084 50.448 ;
     RECT  69.001 50.448 69.036 50.472 ;
     RECT  69.001 50.472 69.084 50.544 ;
     RECT  69.001 50.544 69.036 50.568 ;
     RECT  69.001 50.568 69.084 50.64 ;
     RECT  69.001 50.64 69.036 50.664 ;
     RECT  69.001 50.664 69.084 50.736 ;
     RECT  69.001 50.736 69.036 50.76 ;
     RECT  69.001 50.76 69.084 50.832 ;
     RECT  69.001 50.832 69.036 50.856 ;
     RECT  69.001 50.856 69.084 50.928 ;
     RECT  69.001 50.928 69.036 50.952 ;
     RECT  69.001 50.952 69.084 51.024 ;
     RECT  69.001 51.024 69.036 51.048 ;
     RECT  69.001 51.048 69.084 51.12 ;
     RECT  69.001 51.12 69.036 51.144 ;
     RECT  69.001 51.144 69.084 51.216 ;
     RECT  69.001 51.216 69.036 51.24 ;
     RECT  69.001 51.24 69.084 51.312 ;
     RECT  69.001 51.312 69.036 51.336 ;
    LAYER M5 ;
     RECT  35.304 0.016 35.376 0.084 ;
     RECT  35.4 0.016 35.472 0.084 ;
     RECT  35.496 0.016 35.568 0.084 ;
     RECT  35.592 0.016 35.664 0.084 ;
     RECT  35.688 0.016 35.76 0.084 ;
     RECT  35.784 0.016 35.856 0.084 ;
     RECT  35.88 0.016 35.952 0.084 ;
     RECT  35.976 0.016 36.048 0.084 ;
     RECT  36.072 0.016 36.144 0.084 ;
     RECT  36.168 0.016 36.24 0.084 ;
     RECT  36.264 0.016 36.336 0.084 ;
     RECT  36.36 0.016 36.432 0.084 ;
     RECT  36.456 0.016 36.528 0.084 ;
     RECT  36.552 0.016 36.624 0.084 ;
     RECT  36.648 0.016 36.72 0.084 ;
     RECT  36.744 0.016 36.816 0.084 ;
     RECT  36.84 0.016 36.912 0.084 ;
     RECT  36.936 0.016 37.008 0.084 ;
     RECT  37.032 0.016 37.104 0.084 ;
     RECT  37.128 0.016 37.2 0.084 ;
     RECT  37.224 0.016 37.296 0.084 ;
     RECT  37.32 0.016 37.392 0.084 ;
     RECT  37.416 0.016 37.488 0.084 ;
     RECT  37.512 0.016 37.584 0.084 ;
     RECT  37.608 0.016 37.68 0.084 ;
     RECT  37.704 0.016 37.776 0.084 ;
     RECT  37.8 0.016 37.872 0.084 ;
     RECT  37.896 0.016 37.968 0.084 ;
     RECT  37.992 0.016 38.064 0.084 ;
     RECT  38.088 0.016 38.16 0.084 ;
     RECT  38.184 0.016 38.256 0.084 ;
     RECT  38.28 0.016 39.12 0.084 ;
     RECT  39.144 0.016 39.216 0.084 ;
     RECT  39.24 0.016 39.312 0.084 ;
     RECT  39.336 0.016 39.408 0.084 ;
     RECT  39.432 0.016 39.504 0.084 ;
     RECT  39.528 0.016 39.6 0.084 ;
     RECT  39.624 0.016 39.696 0.084 ;
     RECT  39.72 0.016 39.792 0.084 ;
     RECT  39.816 0.016 39.888 0.084 ;
     RECT  39.912 0.016 39.984 0.084 ;
     RECT  40.008 0.016 40.08 0.084 ;
     RECT  40.104 0.016 40.176 0.084 ;
     RECT  40.2 0.016 40.272 0.084 ;
     RECT  40.296 0.016 40.368 0.084 ;
     RECT  40.392 0.016 40.464 0.084 ;
     RECT  40.488 0.016 40.56 0.084 ;
     RECT  40.584 0.016 40.656 0.084 ;
     RECT  40.68 0.016 40.752 0.084 ;
     RECT  40.776 0.016 40.848 0.084 ;
     RECT  40.872 0.016 40.944 0.084 ;
     RECT  40.968 0.016 41.04 0.084 ;
     RECT  41.064 0.016 41.136 0.084 ;
     RECT  41.16 0.016 41.232 0.084 ;
     RECT  41.256 0.016 41.328 0.084 ;
     RECT  41.352 0.016 41.424 0.084 ;
     RECT  41.448 0.016 41.52 0.084 ;
     RECT  41.544 0.016 41.616 0.084 ;
     RECT  41.64 0.016 41.712 0.084 ;
     RECT  41.736 0.016 41.808 0.084 ;
     RECT  41.832 0.016 41.904 0.084 ;
     RECT  41.928 0.016 42 0.084 ;
     RECT  42.024 0.016 42.096 0.084 ;
     RECT  42.12 0.016 42.192 0.084 ;
     RECT  42.216 0.016 42.288 0.084 ;
     RECT  42.312 0.016 42.384 0.084 ;
     RECT  42.408 0.016 42.48 0.084 ;
     RECT  42.504 0.016 42.576 0.084 ;
     RECT  42.6 0.016 42.672 0.084 ;
     RECT  42.696 0.016 42.768 0.084 ;
     RECT  42.792 0.016 42.864 0.084 ;
     RECT  42.888 0.016 42.96 0.084 ;
     RECT  42.984 0.016 43.056 0.084 ;
     RECT  43.08 0.016 43.152 0.084 ;
     RECT  43.176 0.016 43.248 0.084 ;
     RECT  43.272 0.016 43.344 0.084 ;
     RECT  43.368 0.016 43.44 0.084 ;
     RECT  43.464 0.016 43.536 0.084 ;
     RECT  43.56 0.016 43.632 0.084 ;
     RECT  43.656 0.016 43.728 0.084 ;
     RECT  43.752 0.016 43.824 0.084 ;
     RECT  43.848 0.016 43.92 0.084 ;
     RECT  43.944 0.016 44.016 0.084 ;
     RECT  44.04 0.016 44.112 0.084 ;
     RECT  44.136 0.016 44.208 0.084 ;
     RECT  44.232 0.016 44.304 0.084 ;
     RECT  44.328 0.016 44.4 0.084 ;
     RECT  44.424 0.016 44.496 0.084 ;
     RECT  44.52 0.016 44.592 0.084 ;
     RECT  44.616 0.016 44.688 0.084 ;
     RECT  44.712 0.016 44.784 0.084 ;
     RECT  44.808 0.016 44.88 0.084 ;
     RECT  44.904 0.016 44.976 0.084 ;
     RECT  45 0.016 45.072 0.084 ;
     RECT  45.096 0.016 45.168 0.084 ;
     RECT  45.192 0.016 45.264 0.084 ;
     RECT  45.288 0.016 45.36 0.084 ;
     RECT  45.384 0.016 45.456 0.084 ;
     RECT  45.48 0.016 45.552 0.084 ;
     RECT  45.576 0.016 45.648 0.084 ;
     RECT  45.672 0.016 45.744 0.084 ;
     RECT  35.28 0.084 45.768 0.085 ;
     RECT  35.28 0.085 46.008 1.763 ;
     RECT  35.28 1.763 38.184 2.137 ;
     RECT  2.4 2.137 2.52 2.151 ;
     RECT  7.8 2.137 7.92 2.151 ;
     RECT  13.2 2.137 13.32 2.151 ;
     RECT  18.6 2.137 18.72 2.151 ;
     RECT  24 2.137 24.12 2.151 ;
     RECT  29.4 2.137 29.52 2.151 ;
     RECT  51 2.137 51.12 2.151 ;
     RECT  56.4 2.137 56.52 2.151 ;
     RECT  61.8 2.137 61.92 2.151 ;
     RECT  34.8 2.137 38.184 2.243 ;
     RECT  34.8 2.243 37.896 2.867 ;
     RECT  39.216 1.763 46.008 2.963 ;
     RECT  36.72 2.867 37.896 3.925 ;
     RECT  34.8 2.867 35.592 4.115 ;
     RECT  34.8 4.115 35.208 5.077 ;
     RECT  36.72 3.925 38.184 5.125 ;
     RECT  39.216 2.963 45.912 5.125 ;
     RECT  36.72 5.125 45.912 5.171 ;
     RECT  37.008 5.171 45.912 5.363 ;
     RECT  39.216 5.363 45.912 5.651 ;
     RECT  44.112 5.651 45.912 5.699 ;
     RECT  44.256 5.699 45.912 5.795 ;
     RECT  45.504 5.795 45.912 6.035 ;
     RECT  34.8 5.077 35.592 6.277 ;
     RECT  37.008 5.363 37.896 6.323 ;
     RECT  39.216 5.651 42.888 6.371 ;
     RECT  37.488 6.323 37.896 6.899 ;
     RECT  39.408 6.371 42.888 6.947 ;
     RECT  39.408 6.947 42.168 7.331 ;
     RECT  37.872 6.899 37.896 7.475 ;
     RECT  39.408 7.331 41.832 7.523 ;
     RECT  44.256 5.795 44.28 7.907 ;
     RECT  39.984 7.523 40.632 8.003 ;
     RECT  41.616 7.523 41.832 8.003 ;
     RECT  41.712 8.003 41.832 8.051 ;
     RECT  41.712 8.051 41.736 8.195 ;
     RECT  40.2 8.003 40.632 8.531 ;
     RECT  61.8 2.151 62.112 21.061 ;
     RECT  7.8 2.151 8.112 22.741 ;
     RECT  59.616 5.989 59.64 22.787 ;
     RECT  2.4 2.151 2.712 22.885 ;
     RECT  2.4 22.885 2.808 23.075 ;
     RECT  47.136 6.181 47.16 23.459 ;
     RECT  7.68 22.741 8.112 23.603 ;
     RECT  34.8 6.277 36.024 23.605 ;
     RECT  20.4 23.557 20.424 23.653 ;
     RECT  34.704 23.605 36.024 23.845 ;
     RECT  61.8 21.061 62.376 23.893 ;
     RECT  61.8 23.893 63.288 23.939 ;
     RECT  20.304 23.653 20.424 24.899 ;
     RECT  61.8 23.939 62.28 24.947 ;
     RECT  20.304 24.899 20.328 25.139 ;
     RECT  7.8 23.603 8.112 25.237 ;
     RECT  5.616 21.541 5.64 25.333 ;
     RECT  7.392 25.237 8.112 25.333 ;
     RECT  4.8 25.333 5.64 25.379 ;
     RECT  0.192 25.525 0.216 25.763 ;
     RECT  34.32 23.845 36.024 25.763 ;
     RECT  63.264 23.939 63.288 25.813 ;
     RECT  63.264 25.813 63.384 25.859 ;
     RECT  7.152 25.333 8.112 26.243 ;
     RECT  31.632 25.237 31.656 26.291 ;
     RECT  59.904 26.677 59.928 27.635 ;
     RECT  7.8 26.243 8.112 27.877 ;
     RECT  0.144 27.637 0.168 27.923 ;
     RECT  63.36 25.859 63.384 28.837 ;
     RECT  63.36 28.837 63.528 28.883 ;
     RECT  4.8 25.379 4.824 28.885 ;
     RECT  4.56 28.885 4.824 28.931 ;
     RECT  6.864 27.877 8.112 29.219 ;
     RECT  1.248 29.509 1.272 29.651 ;
     RECT  7.8 29.219 8.112 30.181 ;
     RECT  7.8 30.181 8.232 30.995 ;
     RECT  4.56 28.931 4.584 31.381 ;
     RECT  4.56 31.381 4.68 31.523 ;
     RECT  59.952 30.709 59.976 31.571 ;
     RECT  7.8 30.995 8.112 31.909 ;
     RECT  6.816 31.909 8.112 32.483 ;
     RECT  63.504 28.883 63.528 34.741 ;
     RECT  29.4 2.151 29.712 34.933 ;
     RECT  61.8 24.947 62.112 35.317 ;
     RECT  63.504 34.741 63.72 35.363 ;
     RECT  61.8 35.317 62.232 35.795 ;
     RECT  7.8 32.483 8.112 35.797 ;
     RECT  63.504 35.363 63.528 35.939 ;
     RECT  4.56 34.741 4.584 36.565 ;
     RECT  7.8 35.797 8.232 36.659 ;
     RECT  4.56 36.565 4.68 36.851 ;
     RECT  61.8 35.795 62.112 37.573 ;
     RECT  0.144 37.429 0.168 37.619 ;
     RECT  63.456 36.421 63.48 37.667 ;
     RECT  4.56 36.851 4.584 38.149 ;
     RECT  4.416 38.149 4.584 38.195 ;
     RECT  61.8 37.573 62.232 38.435 ;
     RECT  7.8 36.659 8.112 39.589 ;
     RECT  7.8 39.589 8.232 40.499 ;
     RECT  4.416 38.195 4.44 40.789 ;
     RECT  4.176 40.789 4.44 40.835 ;
     RECT  61.8 38.435 62.112 40.981 ;
     RECT  61.8 40.981 63.096 41.365 ;
     RECT  61.8 41.365 63.24 41.411 ;
     RECT  5.232 43.045 5.256 44.339 ;
     RECT  0.144 45.685 0.168 46.691 ;
     RECT  4.176 40.835 4.2 46.693 ;
     RECT  3.936 46.693 4.2 46.883 ;
     RECT  2.4 23.075 2.712 47.125 ;
     RECT  2.304 47.125 2.712 47.315 ;
     RECT  33.072 47.701 33.096 47.891 ;
     RECT  18.6 2.151 18.912 48.229 ;
     RECT  7.8 40.499 8.112 48.373 ;
     RECT  63.216 41.411 63.24 48.421 ;
     RECT  34.32 25.763 35.112 48.467 ;
     RECT  63.12 48.421 63.24 48.467 ;
     RECT  4.176 46.883 4.2 48.997 ;
     RECT  0.144 48.997 0.168 49.187 ;
     RECT  1.152 48.997 1.176 49.235 ;
     RECT  4.176 48.997 5.112 49.235 ;
     RECT  4.176 49.235 4.92 49.523 ;
     RECT  7.8 48.373 8.232 49.523 ;
     RECT  2.4 47.315 2.712 50.149 ;
     RECT  2.304 50.149 2.712 50.339 ;
     RECT  40.2 8.531 40.512 50.533 ;
     RECT  63.12 48.467 63.144 50.579 ;
     RECT  2.4 50.339 2.712 51.637 ;
     RECT  2.304 51.637 2.712 51.827 ;
     RECT  34.464 48.467 35.112 52.019 ;
     RECT  4.896 49.523 4.92 52.021 ;
     RECT  6.288 51.061 6.312 52.115 ;
     RECT  4.416 52.021 4.92 52.211 ;
     RECT  7.8 49.523 8.112 52.453 ;
     RECT  2.4 51.827 2.712 52.789 ;
     RECT  2.304 52.789 2.712 52.979 ;
     RECT  4.896 52.211 4.92 53.075 ;
     RECT  6.864 52.453 8.112 53.219 ;
     RECT  18.6 48.229 19.08 62.149 ;
     RECT  24 2.151 24.312 62.485 ;
     RECT  23.472 62.485 24.312 62.581 ;
     RECT  34.8 52.019 35.112 62.581 ;
     RECT  40.2 50.533 41.256 62.581 ;
     RECT  45.6 6.035 45.912 62.581 ;
     RECT  34.8 62.581 35.4 62.677 ;
     RECT  45.6 62.581 46.728 62.677 ;
     RECT  23.424 62.581 24.312 62.725 ;
     RECT  34.8 62.677 35.88 62.725 ;
     RECT  23.184 62.725 24.312 62.821 ;
     RECT  27.312 62.341 27.336 62.821 ;
     RECT  34.8 62.725 36.36 62.821 ;
     RECT  37.584 62.581 37.608 62.821 ;
     RECT  38.832 62.629 38.856 62.821 ;
     RECT  45.6 62.677 47.016 62.821 ;
     RECT  42.432 62.821 43.944 62.869 ;
     RECT  27.312 62.821 27.768 62.963 ;
     RECT  23.184 62.821 25.032 63.013 ;
     RECT  42.432 62.869 44.424 63.061 ;
     RECT  23.04 63.013 25.032 63.109 ;
     RECT  37.584 62.821 38.856 63.109 ;
     RECT  39.84 62.581 41.256 63.109 ;
     RECT  42.432 63.061 44.472 63.109 ;
     RECT  37.584 63.109 44.472 63.157 ;
     RECT  45.456 62.821 47.016 63.157 ;
     RECT  32.592 63.109 32.616 63.205 ;
     RECT  34.8 62.821 36.456 63.205 ;
     RECT  37.584 63.157 47.496 63.205 ;
     RECT  22.128 63.109 25.032 63.253 ;
     RECT  27.744 62.963 27.768 63.253 ;
     RECT  28.944 34.933 29.712 63.253 ;
     RECT  21.072 63.253 25.032 63.637 ;
     RECT  32.448 63.205 32.76 63.637 ;
     RECT  33.984 63.205 47.88 63.637 ;
     RECT  18.6 62.149 19.224 63.781 ;
     RECT  20.976 63.637 25.032 63.781 ;
     RECT  27.744 63.253 29.928 63.781 ;
     RECT  32.448 63.637 47.88 63.829 ;
     RECT  26.736 63.205 26.76 64.309 ;
     RECT  27.744 63.781 30.696 64.309 ;
     RECT  18.6 63.781 25.032 65.509 ;
     RECT  26.736 64.309 30.696 66.133 ;
     RECT  31.824 63.829 47.88 66.133 ;
     RECT  18.384 65.509 25.032 66.661 ;
     RECT  18.288 66.661 25.032 66.709 ;
     RECT  26.736 66.133 47.88 66.709 ;
     RECT  18 66.709 48.552 66.757 ;
     RECT  2.4 52.979 2.712 66.969 ;
     RECT  7.8 53.219 8.112 66.969 ;
     RECT  13.2 2.151 13.512 66.969 ;
     RECT  51 2.151 51.312 66.969 ;
     RECT  56.4 2.151 56.712 66.969 ;
     RECT  61.8 41.411 62.112 66.969 ;
     RECT  2.4 66.969 2.52 66.983 ;
     RECT  7.8 66.969 7.92 66.983 ;
     RECT  13.2 66.969 13.32 66.983 ;
     RECT  51 66.969 51.12 66.983 ;
     RECT  56.4 66.969 56.52 66.983 ;
     RECT  61.8 66.969 61.92 66.983 ;
     RECT  18 66.757 48.936 67.237 ;
     RECT  17.712 67.237 49.128 69.036 ;
     RECT  17.736 69.036 17.808 69.072 ;
     RECT  17.832 69.036 17.904 69.072 ;
     RECT  17.928 69.036 18 69.072 ;
     RECT  18.024 69.036 18.096 69.072 ;
     RECT  18.12 69.036 18.192 69.072 ;
     RECT  18.216 69.036 18.288 69.072 ;
     RECT  18.312 69.036 18.384 69.072 ;
     RECT  18.408 69.036 18.48 69.072 ;
     RECT  18.504 69.036 18.576 69.072 ;
     RECT  18.6 69.036 18.672 69.072 ;
     RECT  18.696 69.036 18.768 69.072 ;
     RECT  18.792 69.036 18.864 69.072 ;
     RECT  18.888 69.036 18.96 69.072 ;
     RECT  18.984 69.036 19.056 69.072 ;
     RECT  19.08 69.036 19.152 69.072 ;
     RECT  19.176 69.036 19.248 69.072 ;
     RECT  19.272 69.036 19.344 69.072 ;
     RECT  19.368 69.036 19.44 69.072 ;
     RECT  19.464 69.036 19.536 69.072 ;
     RECT  19.56 69.036 19.632 69.072 ;
     RECT  19.656 69.036 19.728 69.072 ;
     RECT  19.752 69.036 19.824 69.072 ;
     RECT  19.848 69.036 19.92 69.072 ;
     RECT  19.944 69.036 20.016 69.072 ;
     RECT  20.04 69.036 20.112 69.072 ;
     RECT  20.136 69.036 20.208 69.072 ;
     RECT  20.232 69.036 20.304 69.072 ;
     RECT  20.328 69.036 20.4 69.072 ;
     RECT  20.424 69.036 20.496 69.072 ;
     RECT  20.52 69.036 20.592 69.072 ;
     RECT  20.616 69.036 20.688 69.072 ;
     RECT  20.712 69.036 20.784 69.072 ;
     RECT  20.808 69.036 20.88 69.072 ;
     RECT  20.904 69.036 20.976 69.072 ;
     RECT  21 69.036 21.072 69.072 ;
     RECT  21.096 69.036 21.168 69.072 ;
     RECT  21.192 69.036 21.264 69.072 ;
     RECT  21.288 69.036 21.36 69.072 ;
     RECT  21.384 69.036 21.456 69.072 ;
     RECT  21.48 69.036 21.552 69.072 ;
     RECT  21.576 69.036 21.648 69.072 ;
     RECT  21.672 69.036 21.744 69.072 ;
     RECT  21.768 69.036 21.84 69.072 ;
     RECT  21.864 69.036 21.936 69.072 ;
     RECT  21.96 69.036 22.032 69.072 ;
     RECT  22.056 69.036 22.128 69.072 ;
     RECT  22.152 69.036 22.224 69.072 ;
     RECT  22.248 69.036 22.32 69.072 ;
     RECT  22.344 69.036 22.416 69.072 ;
     RECT  22.44 69.036 22.512 69.072 ;
     RECT  22.536 69.036 22.608 69.072 ;
     RECT  22.632 69.036 22.704 69.072 ;
     RECT  22.728 69.036 22.8 69.072 ;
     RECT  22.824 69.036 22.896 69.072 ;
     RECT  22.92 69.036 22.992 69.072 ;
     RECT  23.016 69.036 23.088 69.072 ;
     RECT  23.112 69.036 23.184 69.072 ;
     RECT  23.208 69.036 23.28 69.072 ;
     RECT  23.304 69.036 23.376 69.072 ;
     RECT  23.4 69.036 23.472 69.072 ;
     RECT  23.496 69.036 23.568 69.072 ;
     RECT  23.592 69.036 23.664 69.072 ;
     RECT  23.688 69.036 23.76 69.072 ;
     RECT  23.784 69.036 23.856 69.072 ;
     RECT  23.88 69.036 23.952 69.072 ;
     RECT  23.976 69.036 24.048 69.072 ;
     RECT  24.072 69.036 24.144 69.072 ;
     RECT  24.168 69.036 24.24 69.072 ;
     RECT  24.264 69.036 24.336 69.072 ;
     RECT  24.36 69.036 24.432 69.072 ;
     RECT  24.456 69.036 24.528 69.072 ;
     RECT  24.552 69.036 24.624 69.072 ;
     RECT  24.648 69.036 24.72 69.072 ;
     RECT  24.744 69.036 24.816 69.072 ;
     RECT  24.84 69.036 24.912 69.072 ;
     RECT  24.936 69.036 25.008 69.072 ;
     RECT  25.032 69.036 25.104 69.072 ;
     RECT  25.128 69.036 25.2 69.072 ;
     RECT  25.224 69.036 25.296 69.072 ;
     RECT  25.32 69.036 25.392 69.072 ;
     RECT  25.416 69.036 25.488 69.072 ;
     RECT  25.512 69.036 25.584 69.072 ;
     RECT  25.608 69.036 25.68 69.072 ;
     RECT  25.704 69.036 25.776 69.072 ;
     RECT  25.8 69.036 25.872 69.072 ;
     RECT  25.896 69.036 25.968 69.072 ;
     RECT  25.992 69.036 26.064 69.072 ;
     RECT  26.088 69.036 26.16 69.072 ;
     RECT  26.184 69.036 26.256 69.072 ;
     RECT  26.28 69.036 26.352 69.072 ;
     RECT  26.376 69.036 26.448 69.072 ;
     RECT  26.472 69.036 26.544 69.072 ;
     RECT  26.568 69.036 26.64 69.072 ;
     RECT  26.664 69.036 26.736 69.072 ;
     RECT  26.76 69.036 26.832 69.072 ;
     RECT  26.856 69.036 26.928 69.072 ;
     RECT  26.952 69.036 27.024 69.072 ;
     RECT  27.048 69.036 27.12 69.072 ;
     RECT  27.144 69.036 27.216 69.072 ;
     RECT  27.24 69.036 27.312 69.072 ;
     RECT  27.336 69.036 27.408 69.072 ;
     RECT  27.432 69.036 27.504 69.072 ;
     RECT  27.528 69.036 27.6 69.072 ;
     RECT  27.624 69.036 27.696 69.072 ;
     RECT  27.72 69.036 27.792 69.072 ;
     RECT  27.816 69.036 27.888 69.072 ;
     RECT  27.912 69.036 27.984 69.072 ;
     RECT  28.008 69.036 28.08 69.072 ;
     RECT  28.104 69.036 28.176 69.072 ;
     RECT  28.2 69.036 28.272 69.072 ;
     RECT  28.296 69.036 28.368 69.072 ;
     RECT  28.392 69.036 28.464 69.072 ;
     RECT  28.488 69.036 28.56 69.072 ;
     RECT  28.584 69.036 28.656 69.072 ;
     RECT  28.68 69.036 28.752 69.072 ;
     RECT  28.776 69.036 28.848 69.072 ;
     RECT  28.872 69.036 28.944 69.072 ;
     RECT  28.968 69.036 29.04 69.072 ;
     RECT  29.064 69.036 29.136 69.072 ;
     RECT  29.16 69.036 29.232 69.072 ;
     RECT  29.256 69.036 29.328 69.072 ;
     RECT  29.352 69.036 29.424 69.072 ;
     RECT  29.448 69.036 29.52 69.072 ;
     RECT  29.544 69.036 29.616 69.072 ;
     RECT  29.64 69.036 29.712 69.072 ;
     RECT  29.736 69.036 29.808 69.072 ;
     RECT  29.832 69.036 29.904 69.072 ;
     RECT  29.928 69.036 30.576 69.072 ;
     RECT  30.6 69.036 30.672 69.072 ;
     RECT  30.696 69.036 30.768 69.072 ;
     RECT  30.792 69.036 30.864 69.072 ;
     RECT  30.888 69.036 30.96 69.072 ;
     RECT  30.984 69.036 31.056 69.072 ;
     RECT  31.08 69.036 31.152 69.072 ;
     RECT  31.176 69.036 31.248 69.072 ;
     RECT  31.272 69.036 31.344 69.072 ;
     RECT  31.368 69.036 31.44 69.072 ;
     RECT  31.464 69.036 31.536 69.072 ;
     RECT  31.56 69.036 31.632 69.072 ;
     RECT  31.656 69.036 31.728 69.072 ;
     RECT  31.752 69.036 31.824 69.072 ;
     RECT  31.848 69.036 31.92 69.072 ;
     RECT  31.944 69.036 32.016 69.072 ;
     RECT  32.04 69.036 32.112 69.072 ;
     RECT  32.136 69.036 32.208 69.072 ;
     RECT  32.232 69.036 32.304 69.072 ;
     RECT  32.328 69.036 32.4 69.072 ;
     RECT  32.424 69.036 32.496 69.072 ;
     RECT  32.52 69.036 32.592 69.072 ;
     RECT  32.616 69.036 32.688 69.072 ;
     RECT  32.712 69.036 32.784 69.072 ;
     RECT  32.808 69.036 32.88 69.072 ;
     RECT  32.904 69.036 32.976 69.072 ;
     RECT  33 69.036 33.072 69.072 ;
     RECT  33.096 69.036 33.168 69.072 ;
     RECT  33.192 69.036 33.264 69.072 ;
     RECT  33.288 69.036 33.36 69.072 ;
     RECT  33.384 69.036 33.456 69.072 ;
     RECT  33.48 69.036 33.552 69.072 ;
     RECT  33.576 69.036 33.648 69.072 ;
     RECT  33.672 69.036 33.744 69.072 ;
     RECT  33.768 69.036 33.84 69.072 ;
     RECT  33.864 69.036 33.936 69.072 ;
     RECT  33.96 69.036 34.032 69.072 ;
     RECT  34.056 69.036 34.128 69.072 ;
     RECT  34.152 69.036 34.224 69.072 ;
     RECT  34.248 69.036 34.32 69.072 ;
     RECT  34.344 69.036 34.416 69.072 ;
     RECT  34.44 69.036 34.512 69.072 ;
     RECT  34.536 69.036 34.608 69.072 ;
     RECT  34.632 69.036 34.704 69.072 ;
     RECT  34.728 69.036 34.8 69.072 ;
     RECT  34.824 69.036 34.896 69.072 ;
     RECT  34.92 69.036 34.992 69.072 ;
     RECT  35.016 69.036 35.088 69.072 ;
     RECT  35.112 69.036 35.184 69.072 ;
     RECT  35.208 69.036 35.28 69.072 ;
     RECT  35.304 69.036 35.376 69.072 ;
     RECT  35.4 69.036 35.472 69.072 ;
     RECT  35.496 69.036 35.568 69.072 ;
     RECT  35.592 69.036 35.664 69.072 ;
     RECT  35.688 69.036 35.76 69.072 ;
     RECT  35.784 69.036 35.856 69.072 ;
     RECT  35.88 69.036 35.952 69.072 ;
     RECT  35.976 69.036 36.048 69.072 ;
     RECT  36.072 69.036 36.144 69.072 ;
     RECT  36.168 69.036 36.24 69.072 ;
     RECT  36.264 69.036 36.336 69.072 ;
     RECT  36.36 69.036 36.432 69.072 ;
     RECT  36.456 69.036 36.528 69.072 ;
     RECT  36.552 69.036 36.624 69.072 ;
     RECT  36.648 69.036 36.72 69.072 ;
     RECT  36.744 69.036 36.816 69.072 ;
     RECT  36.84 69.036 36.912 69.072 ;
     RECT  36.936 69.036 37.008 69.072 ;
     RECT  37.032 69.036 37.104 69.072 ;
     RECT  37.128 69.036 37.2 69.072 ;
     RECT  37.224 69.036 37.296 69.072 ;
     RECT  37.32 69.036 37.392 69.072 ;
     RECT  37.416 69.036 37.488 69.072 ;
     RECT  37.512 69.036 37.584 69.072 ;
     RECT  37.608 69.036 37.68 69.072 ;
     RECT  37.704 69.036 37.776 69.072 ;
     RECT  37.8 69.036 37.872 69.072 ;
     RECT  37.896 69.036 37.968 69.072 ;
     RECT  37.992 69.036 38.064 69.072 ;
     RECT  38.088 69.036 38.16 69.072 ;
     RECT  38.184 69.036 38.256 69.072 ;
     RECT  38.28 69.036 38.352 69.072 ;
     RECT  38.376 69.036 38.448 69.072 ;
     RECT  38.472 69.036 38.544 69.072 ;
     RECT  38.568 69.036 38.64 69.072 ;
     RECT  38.664 69.036 38.736 69.072 ;
     RECT  38.76 69.036 38.832 69.072 ;
     RECT  38.856 69.036 38.928 69.072 ;
     RECT  38.952 69.036 39.024 69.072 ;
     RECT  39.048 69.036 39.12 69.072 ;
     RECT  39.144 69.036 39.216 69.072 ;
     RECT  39.24 69.036 39.312 69.072 ;
     RECT  39.336 69.036 39.408 69.072 ;
     RECT  39.432 69.036 39.504 69.072 ;
     RECT  39.528 69.036 39.6 69.072 ;
     RECT  39.624 69.036 39.696 69.072 ;
     RECT  39.72 69.036 39.792 69.072 ;
     RECT  39.816 69.036 39.888 69.072 ;
     RECT  39.912 69.036 39.984 69.072 ;
     RECT  40.008 69.036 40.08 69.072 ;
     RECT  40.104 69.036 40.176 69.072 ;
     RECT  40.2 69.036 40.272 69.072 ;
     RECT  40.296 69.036 40.368 69.072 ;
     RECT  40.392 69.036 40.464 69.072 ;
     RECT  40.488 69.036 40.56 69.072 ;
     RECT  40.584 69.036 40.656 69.072 ;
     RECT  40.68 69.036 40.752 69.072 ;
     RECT  40.776 69.036 40.848 69.072 ;
     RECT  40.872 69.036 40.944 69.072 ;
     RECT  40.968 69.036 41.04 69.072 ;
     RECT  41.064 69.036 41.136 69.072 ;
     RECT  41.16 69.036 41.232 69.072 ;
     RECT  41.256 69.036 41.328 69.072 ;
     RECT  41.352 69.036 41.424 69.072 ;
     RECT  41.448 69.036 41.52 69.072 ;
     RECT  41.544 69.036 41.616 69.072 ;
     RECT  41.64 69.036 41.712 69.072 ;
     RECT  41.736 69.036 41.808 69.072 ;
     RECT  41.832 69.036 41.904 69.072 ;
     RECT  41.928 69.036 42 69.072 ;
     RECT  42.024 69.036 42.096 69.072 ;
     RECT  42.12 69.036 42.192 69.072 ;
     RECT  42.216 69.036 42.288 69.072 ;
     RECT  42.312 69.036 42.384 69.072 ;
     RECT  42.408 69.036 42.48 69.072 ;
     RECT  42.504 69.036 42.576 69.072 ;
     RECT  42.6 69.036 42.672 69.072 ;
     RECT  42.696 69.036 42.768 69.072 ;
     RECT  42.792 69.036 42.864 69.072 ;
     RECT  42.888 69.036 42.96 69.072 ;
     RECT  42.984 69.036 43.056 69.072 ;
     RECT  43.08 69.036 43.152 69.072 ;
     RECT  43.176 69.036 43.248 69.072 ;
     RECT  43.272 69.036 43.344 69.072 ;
     RECT  43.368 69.036 43.44 69.072 ;
     RECT  43.464 69.036 43.536 69.072 ;
     RECT  43.56 69.036 43.632 69.072 ;
     RECT  43.656 69.036 43.728 69.072 ;
     RECT  43.752 69.036 43.824 69.072 ;
     RECT  43.848 69.036 43.92 69.072 ;
     RECT  43.944 69.036 44.016 69.072 ;
     RECT  44.04 69.036 44.112 69.072 ;
     RECT  44.136 69.036 44.208 69.072 ;
     RECT  44.232 69.036 44.304 69.072 ;
     RECT  44.328 69.036 44.4 69.072 ;
     RECT  44.424 69.036 44.496 69.072 ;
     RECT  44.52 69.036 44.592 69.072 ;
     RECT  44.616 69.036 44.688 69.072 ;
     RECT  44.712 69.036 44.784 69.072 ;
     RECT  44.808 69.036 44.88 69.072 ;
     RECT  44.904 69.036 44.976 69.072 ;
     RECT  45 69.036 45.072 69.072 ;
     RECT  45.096 69.036 45.168 69.072 ;
     RECT  45.192 69.036 45.264 69.072 ;
     RECT  45.288 69.036 45.36 69.072 ;
     RECT  45.384 69.036 45.456 69.072 ;
     RECT  45.48 69.036 45.552 69.072 ;
     RECT  45.576 69.036 45.648 69.072 ;
     RECT  45.672 69.036 45.744 69.072 ;
     RECT  45.768 69.036 45.84 69.072 ;
     RECT  45.864 69.036 45.936 69.072 ;
     RECT  45.96 69.036 46.032 69.072 ;
     RECT  46.056 69.036 46.128 69.072 ;
     RECT  46.152 69.036 46.224 69.072 ;
     RECT  46.248 69.036 46.32 69.072 ;
     RECT  46.344 69.036 46.416 69.072 ;
     RECT  46.44 69.036 46.512 69.072 ;
     RECT  46.536 69.036 46.608 69.072 ;
     RECT  46.632 69.036 46.704 69.072 ;
     RECT  46.728 69.036 46.8 69.072 ;
     RECT  46.824 69.036 46.896 69.072 ;
     RECT  46.92 69.036 46.992 69.072 ;
     RECT  47.016 69.036 47.088 69.072 ;
     RECT  47.112 69.036 47.184 69.072 ;
     RECT  47.208 69.036 47.28 69.072 ;
     RECT  47.304 69.036 47.376 69.072 ;
     RECT  47.4 69.036 47.472 69.072 ;
     RECT  47.496 69.036 47.568 69.072 ;
     RECT  47.592 69.036 47.664 69.072 ;
     RECT  47.688 69.036 47.76 69.072 ;
     RECT  47.784 69.036 47.856 69.072 ;
     RECT  47.88 69.036 47.952 69.072 ;
     RECT  47.976 69.036 48.048 69.072 ;
     RECT  48.072 69.036 48.144 69.072 ;
     RECT  48.168 69.036 48.24 69.072 ;
     RECT  48.264 69.036 48.336 69.072 ;
     RECT  48.36 69.036 48.432 69.072 ;
     RECT  48.456 69.036 48.528 69.072 ;
     RECT  48.552 69.036 48.624 69.072 ;
     RECT  48.648 69.036 48.72 69.072 ;
     RECT  48.744 69.036 48.816 69.072 ;
     RECT  48.84 69.036 48.912 69.072 ;
     RECT  48.936 69.036 49.008 69.072 ;
     RECT  49.032 69.036 49.104 69.072 ;
     RECT  38.184 1.763 39.216 2.243 ;
     RECT  37.896 2.243 39.216 3.925 ;
     RECT  35.592 2.867 36.72 4.115 ;
     RECT  38.184 3.925 39.216 5.125 ;
     RECT  35.208 4.115 36.72 5.077 ;
     RECT  35.592 5.077 36.72 5.171 ;
     RECT  35.592 5.171 37.008 6.277 ;
     RECT  37.896 5.363 39.216 6.371 ;
     RECT  42.888 5.651 44.112 5.699 ;
     RECT  42.888 5.699 44.256 6.947 ;
     RECT  44.28 5.795 45.504 6.035 ;
     RECT  44.28 6.035 45.6 7.907 ;
     RECT  45.912 6.181 47.136 23.459 ;
     RECT  36.024 6.277 37.008 6.323 ;
     RECT  36.024 6.323 37.488 6.899 ;
     RECT  37.896 6.371 39.408 7.475 ;
     RECT  40.632 7.523 41.616 8.003 ;
     RECT  40.632 8.003 41.712 8.195 ;
     RECT  18.912 23.557 20.4 23.653 ;
     RECT  18.912 23.653 20.304 25.139 ;
     RECT  62.28 23.939 63.264 24.947 ;
     RECT  62.112 24.947 63.264 25.859 ;
     RECT  5.64 25.333 7.152 25.379 ;
     RECT  62.112 25.859 63.36 28.883 ;
     RECT  62.112 28.883 63.504 35.317 ;
     RECT  1.272 29.509 2.4 29.651 ;
     RECT  62.232 35.317 63.504 35.795 ;
     RECT  62.112 35.795 63.504 35.939 ;
     RECT  62.112 35.939 63.48 36.421 ;
     RECT  62.112 36.421 63.456 37.573 ;
     RECT  62.232 37.573 63.456 37.667 ;
     RECT  2.712 40.789 4.176 46.693 ;
     RECT  62.112 41.411 63.216 48.421 ;
     RECT  4.2 43.045 5.232 44.339 ;
     RECT  2.712 46.693 3.936 46.883 ;
     RECT  2.712 46.883 4.176 49.523 ;
     RECT  33.096 47.701 34.32 47.891 ;
     RECT  62.112 48.421 63.12 50.579 ;
     RECT  0.168 48.997 1.152 49.187 ;
     RECT  1.176 48.997 2.4 49.235 ;
     RECT  2.304 49.235 2.4 50.149 ;
     RECT  2.304 50.339 2.4 51.637 ;
     RECT  4.92 51.061 6.288 52.115 ;
     RECT  6.312 51.061 7.8 52.115 ;
     RECT  2.304 51.827 2.4 52.789 ;
     RECT  6.864 52.115 7.8 52.453 ;
     RECT  37.608 62.629 38.832 62.821 ;
     RECT  38.856 62.629 39.84 63.109 ;
     RECT  36.36 62.725 37.584 62.821 ;
     RECT  27.768 62.821 28.944 63.253 ;
     RECT  36.456 62.821 37.584 63.205 ;
     RECT  41.256 62.821 42.432 63.109 ;
     RECT  43.944 62.821 45.456 62.869 ;
     RECT  44.424 62.869 45.456 63.061 ;
     RECT  27.312 62.963 27.744 63.205 ;
     RECT  44.472 63.061 45.456 63.157 ;
     RECT  26.76 63.205 27.744 64.309 ;
     RECT  32.76 63.205 33.984 63.637 ;
     RECT  30.696 63.829 31.824 66.133 ;
  END
END ot_hbm_host_cfg_leaf_ne
END LIBRARY
